VERSION 5.8 ;
BUSBITCHARS "[]" ;
DIVIDERCHAR "/" ;
UNITS
    DATABASE MICRONS 1000 ;
END UNITS

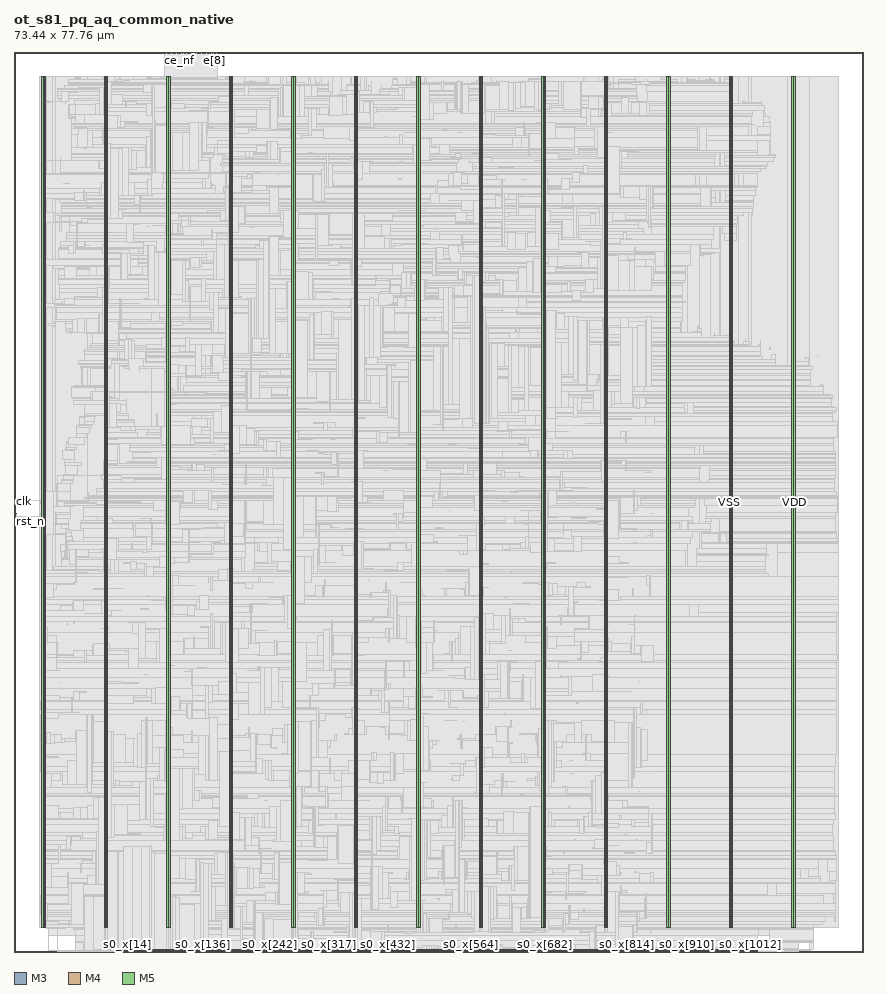
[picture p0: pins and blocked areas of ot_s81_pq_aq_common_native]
MACRO ot_s81_pq_aq_common_native
  FOREIGN ot_s81_pq_aq_common_native 0 0 ;
  CLASS BLOCK ;
  SIZE 73.44 BY 77.76 ;
  PIN ce_nf
    DIRECTION OUTPUT ;
    USE SIGNAL ;
    PORT
      LAYER M3 ;
        RECT  14.256 77.616 14.274 77.76 ;
    END
  END ce_nf
  PIN ce_r[0]
    DIRECTION OUTPUT ;
    USE SIGNAL ;
    PORT
      LAYER M3 ;
        RECT  12.96 77.616 12.978 77.76 ;
    END
  END ce_r[0]
  PIN ce_r[1]
    DIRECTION OUTPUT ;
    USE SIGNAL ;
    PORT
      LAYER M3 ;
        RECT  13.104 77.616 13.122 77.76 ;
    END
  END ce_r[1]
  PIN ce_r[2]
    DIRECTION OUTPUT ;
    USE SIGNAL ;
    PORT
      LAYER M3 ;
        RECT  13.248 77.616 13.266 77.76 ;
    END
  END ce_r[2]
  PIN ce_r[3]
    DIRECTION OUTPUT ;
    USE SIGNAL ;
    PORT
      LAYER M3 ;
        RECT  13.392 77.616 13.41 77.76 ;
    END
  END ce_r[3]
  PIN ce_r[4]
    DIRECTION OUTPUT ;
    USE SIGNAL ;
    PORT
      LAYER M3 ;
        RECT  13.536 77.616 13.554 77.76 ;
    END
  END ce_r[4]
  PIN ce_r[5]
    DIRECTION OUTPUT ;
    USE SIGNAL ;
    PORT
      LAYER M3 ;
        RECT  13.68 77.616 13.698 77.76 ;
    END
  END ce_r[5]
  PIN ce_r[6]
    DIRECTION OUTPUT ;
    USE SIGNAL ;
    PORT
      LAYER M3 ;
        RECT  13.824 77.616 13.842 77.76 ;
    END
  END ce_r[6]
  PIN ce_r[7]
    DIRECTION OUTPUT ;
    USE SIGNAL ;
    PORT
      LAYER M3 ;
        RECT  13.968 77.616 13.986 77.76 ;
    END
  END ce_r[7]
  PIN ce_r[8]
    DIRECTION OUTPUT ;
    USE SIGNAL ;
    PORT
      LAYER M3 ;
        RECT  14.112 77.616 14.13 77.76 ;
    END
  END ce_r[8]
  PIN clk
    DIRECTION INPUT ;
    USE SIGNAL ;
    PORT
      LAYER M4 ;
        RECT  0 38.88 0.192 38.904 ;
    END
    PORT
      LAYER M4 ;
        RECT  0.156 38.88 0.205 38.904 ;
    END
  END clk
  PIN e[0]
    DIRECTION OUTPUT ;
    USE SIGNAL ;
    PORT
      LAYER M3 ;
        RECT  16.128 77.616 16.146 77.76 ;
    END
  END e[0]
  PIN e[1]
    DIRECTION OUTPUT ;
    USE SIGNAL ;
    PORT
      LAYER M3 ;
        RECT  16.272 77.616 16.29 77.76 ;
    END
  END e[1]
  PIN e[2]
    DIRECTION OUTPUT ;
    USE SIGNAL ;
    PORT
      LAYER M3 ;
        RECT  16.416 77.616 16.434 77.76 ;
    END
  END e[2]
  PIN e[3]
    DIRECTION OUTPUT ;
    USE SIGNAL ;
    PORT
      LAYER M3 ;
        RECT  16.56 77.616 16.578 77.76 ;
    END
  END e[3]
  PIN e[4]
    DIRECTION OUTPUT ;
    USE SIGNAL ;
    PORT
      LAYER M3 ;
        RECT  16.704 77.616 16.722 77.76 ;
    END
  END e[4]
  PIN e[5]
    DIRECTION OUTPUT ;
    USE SIGNAL ;
    PORT
      LAYER M3 ;
        RECT  16.848 77.616 16.866 77.76 ;
    END
  END e[5]
  PIN e[6]
    DIRECTION OUTPUT ;
    USE SIGNAL ;
    PORT
      LAYER M3 ;
        RECT  16.992 77.616 17.01 77.76 ;
    END
  END e[6]
  PIN e[7]
    DIRECTION OUTPUT ;
    USE SIGNAL ;
    PORT
      LAYER M3 ;
        RECT  17.136 77.616 17.154 77.76 ;
    END
  END e[7]
  PIN e[8]
    DIRECTION OUTPUT ;
    USE SIGNAL ;
    PORT
      LAYER M3 ;
        RECT  17.28 77.616 17.298 77.76 ;
    END
  END e[8]
  PIN e[9]
    DIRECTION OUTPUT ;
    USE SIGNAL ;
    PORT
      LAYER M3 ;
        RECT  17.424 77.616 17.442 77.76 ;
    END
  END e[9]
  PIN ep
    DIRECTION OUTPUT ;
    USE SIGNAL ;
    PORT
      LAYER M3 ;
        RECT  17.568 77.616 17.586 77.76 ;
    END
  END ep
  PIN fault
    DIRECTION OUTPUT ;
    USE SIGNAL ;
    PORT
      LAYER M3 ;
        RECT  15.984 77.616 16.002 77.76 ;
    END
  END fault
  PIN rst_n
    DIRECTION INPUT ;
    USE SIGNAL ;
    PORT
      LAYER M4 ;
        RECT  0 37.872 0.192 37.896 ;
    END
    PORT
      LAYER M4 ;
        RECT  0.156 37.872 0.245 37.896 ;
    END
  END rst_n
  PIN s0_x[0]
    DIRECTION INPUT ;
    USE SIGNAL ;
    PORT
      LAYER M3 ;
        RECT  9 0 9.018 0.144 ;
    END
  END s0_x[0]
  PIN s0_x[1000]
    DIRECTION INPUT ;
    USE SIGNAL ;
    PORT
      LAYER M3 ;
        RECT  63 0 63.018 0.144 ;
    END
  END s0_x[1000]
  PIN s0_x[1001]
    DIRECTION INPUT ;
    USE SIGNAL ;
    PORT
      LAYER M5 ;
        RECT  60 0 60.024 0.192 ;
    END
  END s0_x[1001]
  PIN s0_x[1002]
    DIRECTION INPUT ;
    USE SIGNAL ;
    PORT
      LAYER M3 ;
        RECT  63.108 0 63.126 0.144 ;
    END
  END s0_x[1002]
  PIN s0_x[1003]
    DIRECTION INPUT ;
    USE SIGNAL ;
    PORT
      LAYER M5 ;
        RECT  60.096 0 60.12 0.192 ;
    END
  END s0_x[1003]
  PIN s0_x[1004]
    DIRECTION INPUT ;
    USE SIGNAL ;
    PORT
      LAYER M3 ;
        RECT  63.216 0 63.234 0.144 ;
    END
  END s0_x[1004]
  PIN s0_x[1005]
    DIRECTION INPUT ;
    USE SIGNAL ;
    PORT
      LAYER M5 ;
        RECT  60.192 0 60.216 0.192 ;
    END
  END s0_x[1005]
  PIN s0_x[1006]
    DIRECTION INPUT ;
    USE SIGNAL ;
    PORT
      LAYER M3 ;
        RECT  63.324 0 63.342 0.144 ;
    END
  END s0_x[1006]
  PIN s0_x[1007]
    DIRECTION INPUT ;
    USE SIGNAL ;
    PORT
      LAYER M5 ;
        RECT  60.288 0 60.312 0.192 ;
    END
  END s0_x[1007]
  PIN s0_x[1008]
    DIRECTION INPUT ;
    USE SIGNAL ;
    PORT
      LAYER M3 ;
        RECT  63.432 0 63.45 0.144 ;
    END
  END s0_x[1008]
  PIN s0_x[1009]
    DIRECTION INPUT ;
    USE SIGNAL ;
    PORT
      LAYER M5 ;
        RECT  60.384 0 60.408 0.192 ;
    END
  END s0_x[1009]
  PIN s0_x[100]
    DIRECTION INPUT ;
    USE SIGNAL ;
    PORT
      LAYER M3 ;
        RECT  14.4 0 14.418 0.144 ;
    END
  END s0_x[100]
  PIN s0_x[1010]
    DIRECTION INPUT ;
    USE SIGNAL ;
    PORT
      LAYER M3 ;
        RECT  63.54 0 63.558 0.144 ;
    END
  END s0_x[1010]
  PIN s0_x[1011]
    DIRECTION INPUT ;
    USE SIGNAL ;
    PORT
      LAYER M5 ;
        RECT  60.48 0 60.504 0.192 ;
    END
  END s0_x[1011]
  PIN s0_x[1012]
    DIRECTION INPUT ;
    USE SIGNAL ;
    PORT
      LAYER M3 ;
        RECT  63.648 0 63.666 0.144 ;
    END
  END s0_x[1012]
  PIN s0_x[1013]
    DIRECTION INPUT ;
    USE SIGNAL ;
    PORT
      LAYER M5 ;
        RECT  60.576 0 60.6 0.192 ;
    END
  END s0_x[1013]
  PIN s0_x[1014]
    DIRECTION INPUT ;
    USE SIGNAL ;
    PORT
      LAYER M3 ;
        RECT  63.756 0 63.774 0.144 ;
    END
  END s0_x[1014]
  PIN s0_x[1015]
    DIRECTION INPUT ;
    USE SIGNAL ;
    PORT
      LAYER M5 ;
        RECT  60.672 0 60.696 0.192 ;
    END
  END s0_x[1015]
  PIN s0_x[1016]
    DIRECTION INPUT ;
    USE SIGNAL ;
    PORT
      LAYER M3 ;
        RECT  63.864 0 63.882 0.144 ;
    END
  END s0_x[1016]
  PIN s0_x[1017]
    DIRECTION INPUT ;
    USE SIGNAL ;
    PORT
      LAYER M5 ;
        RECT  60.768 0 60.792 0.192 ;
    END
  END s0_x[1017]
  PIN s0_x[1018]
    DIRECTION INPUT ;
    USE SIGNAL ;
    PORT
      LAYER M3 ;
        RECT  63.972 0 63.99 0.144 ;
    END
  END s0_x[1018]
  PIN s0_x[1019]
    DIRECTION INPUT ;
    USE SIGNAL ;
    PORT
      LAYER M5 ;
        RECT  60.864 0 60.888 0.192 ;
    END
  END s0_x[1019]
  PIN s0_x[101]
    DIRECTION INPUT ;
    USE SIGNAL ;
    PORT
      LAYER M5 ;
        RECT  16.8 0 16.824 0.192 ;
    END
  END s0_x[101]
  PIN s0_x[1020]
    DIRECTION INPUT ;
    USE SIGNAL ;
    PORT
      LAYER M3 ;
        RECT  64.08 0 64.098 0.144 ;
    END
  END s0_x[1020]
  PIN s0_x[1021]
    DIRECTION INPUT ;
    USE SIGNAL ;
    PORT
      LAYER M5 ;
        RECT  60.96 0 60.984 0.192 ;
    END
  END s0_x[1021]
  PIN s0_x[1022]
    DIRECTION INPUT ;
    USE SIGNAL ;
    PORT
      LAYER M3 ;
        RECT  64.188 0 64.206 0.144 ;
    END
  END s0_x[1022]
  PIN s0_x[1023]
    DIRECTION INPUT ;
    USE SIGNAL ;
    PORT
      LAYER M5 ;
        RECT  61.056 0 61.08 0.192 ;
    END
  END s0_x[1023]
  PIN s0_x[102]
    DIRECTION INPUT ;
    USE SIGNAL ;
    PORT
      LAYER M3 ;
        RECT  14.508 0 14.526 0.144 ;
    END
  END s0_x[102]
  PIN s0_x[103]
    DIRECTION INPUT ;
    USE SIGNAL ;
    PORT
      LAYER M5 ;
        RECT  16.896 0 16.92 0.192 ;
    END
  END s0_x[103]
  PIN s0_x[104]
    DIRECTION INPUT ;
    USE SIGNAL ;
    PORT
      LAYER M3 ;
        RECT  14.616 0 14.634 0.144 ;
    END
  END s0_x[104]
  PIN s0_x[105]
    DIRECTION INPUT ;
    USE SIGNAL ;
    PORT
      LAYER M5 ;
        RECT  16.992 0 17.016 0.192 ;
    END
  END s0_x[105]
  PIN s0_x[106]
    DIRECTION INPUT ;
    USE SIGNAL ;
    PORT
      LAYER M3 ;
        RECT  14.724 0 14.742 0.144 ;
    END
  END s0_x[106]
  PIN s0_x[107]
    DIRECTION INPUT ;
    USE SIGNAL ;
    PORT
      LAYER M5 ;
        RECT  17.088 0 17.112 0.192 ;
    END
  END s0_x[107]
  PIN s0_x[108]
    DIRECTION INPUT ;
    USE SIGNAL ;
    PORT
      LAYER M3 ;
        RECT  14.832 0 14.85 0.144 ;
    END
  END s0_x[108]
  PIN s0_x[109]
    DIRECTION INPUT ;
    USE SIGNAL ;
    PORT
      LAYER M5 ;
        RECT  17.184 0 17.208 0.192 ;
    END
  END s0_x[109]
  PIN s0_x[10]
    DIRECTION INPUT ;
    USE SIGNAL ;
    PORT
      LAYER M3 ;
        RECT  9.54 0 9.558 0.144 ;
    END
  END s0_x[10]
  PIN s0_x[110]
    DIRECTION INPUT ;
    USE SIGNAL ;
    PORT
      LAYER M3 ;
        RECT  14.94 0 14.958 0.144 ;
    END
  END s0_x[110]
  PIN s0_x[111]
    DIRECTION INPUT ;
    USE SIGNAL ;
    PORT
      LAYER M5 ;
        RECT  17.28 0 17.304 0.192 ;
    END
  END s0_x[111]
  PIN s0_x[112]
    DIRECTION INPUT ;
    USE SIGNAL ;
    PORT
      LAYER M3 ;
        RECT  15.048 0 15.066 0.144 ;
    END
  END s0_x[112]
  PIN s0_x[113]
    DIRECTION INPUT ;
    USE SIGNAL ;
    PORT
      LAYER M5 ;
        RECT  17.376 0 17.4 0.192 ;
    END
  END s0_x[113]
  PIN s0_x[114]
    DIRECTION INPUT ;
    USE SIGNAL ;
    PORT
      LAYER M3 ;
        RECT  15.156 0 15.174 0.144 ;
    END
  END s0_x[114]
  PIN s0_x[115]
    DIRECTION INPUT ;
    USE SIGNAL ;
    PORT
      LAYER M5 ;
        RECT  17.472 0 17.496 0.192 ;
    END
  END s0_x[115]
  PIN s0_x[116]
    DIRECTION INPUT ;
    USE SIGNAL ;
    PORT
      LAYER M3 ;
        RECT  15.264 0 15.282 0.144 ;
    END
  END s0_x[116]
  PIN s0_x[117]
    DIRECTION INPUT ;
    USE SIGNAL ;
    PORT
      LAYER M5 ;
        RECT  17.568 0 17.592 0.192 ;
    END
  END s0_x[117]
  PIN s0_x[118]
    DIRECTION INPUT ;
    USE SIGNAL ;
    PORT
      LAYER M3 ;
        RECT  15.372 0 15.39 0.144 ;
    END
  END s0_x[118]
  PIN s0_x[119]
    DIRECTION INPUT ;
    USE SIGNAL ;
    PORT
      LAYER M5 ;
        RECT  17.664 0 17.688 0.192 ;
    END
  END s0_x[119]
  PIN s0_x[11]
    DIRECTION INPUT ;
    USE SIGNAL ;
    PORT
      LAYER M5 ;
        RECT  12.48 0 12.504 0.192 ;
    END
  END s0_x[11]
  PIN s0_x[120]
    DIRECTION INPUT ;
    USE SIGNAL ;
    PORT
      LAYER M3 ;
        RECT  15.48 0 15.498 0.144 ;
    END
  END s0_x[120]
  PIN s0_x[121]
    DIRECTION INPUT ;
    USE SIGNAL ;
    PORT
      LAYER M5 ;
        RECT  17.76 0 17.784 0.192 ;
    END
  END s0_x[121]
  PIN s0_x[122]
    DIRECTION INPUT ;
    USE SIGNAL ;
    PORT
      LAYER M3 ;
        RECT  15.588 0 15.606 0.144 ;
    END
  END s0_x[122]
  PIN s0_x[123]
    DIRECTION INPUT ;
    USE SIGNAL ;
    PORT
      LAYER M5 ;
        RECT  17.856 0 17.88 0.192 ;
    END
  END s0_x[123]
  PIN s0_x[124]
    DIRECTION INPUT ;
    USE SIGNAL ;
    PORT
      LAYER M3 ;
        RECT  15.696 0 15.714 0.144 ;
    END
  END s0_x[124]
  PIN s0_x[125]
    DIRECTION INPUT ;
    USE SIGNAL ;
    PORT
      LAYER M5 ;
        RECT  17.952 0 17.976 0.192 ;
    END
  END s0_x[125]
  PIN s0_x[126]
    DIRECTION INPUT ;
    USE SIGNAL ;
    PORT
      LAYER M3 ;
        RECT  15.804 0 15.822 0.144 ;
    END
  END s0_x[126]
  PIN s0_x[127]
    DIRECTION INPUT ;
    USE SIGNAL ;
    PORT
      LAYER M5 ;
        RECT  18.048 0 18.072 0.192 ;
    END
  END s0_x[127]
  PIN s0_x[128]
    DIRECTION INPUT ;
    USE SIGNAL ;
    PORT
      LAYER M3 ;
        RECT  15.912 0 15.93 0.144 ;
    END
  END s0_x[128]
  PIN s0_x[129]
    DIRECTION INPUT ;
    USE SIGNAL ;
    PORT
      LAYER M5 ;
        RECT  18.144 0 18.168 0.192 ;
    END
  END s0_x[129]
  PIN s0_x[12]
    DIRECTION INPUT ;
    USE SIGNAL ;
    PORT
      LAYER M3 ;
        RECT  9.648 0 9.666 0.144 ;
    END
  END s0_x[12]
  PIN s0_x[130]
    DIRECTION INPUT ;
    USE SIGNAL ;
    PORT
      LAYER M3 ;
        RECT  16.02 0 16.038 0.144 ;
    END
  END s0_x[130]
  PIN s0_x[131]
    DIRECTION INPUT ;
    USE SIGNAL ;
    PORT
      LAYER M5 ;
        RECT  18.24 0 18.264 0.192 ;
    END
  END s0_x[131]
  PIN s0_x[132]
    DIRECTION INPUT ;
    USE SIGNAL ;
    PORT
      LAYER M3 ;
        RECT  16.128 0 16.146 0.144 ;
    END
  END s0_x[132]
  PIN s0_x[133]
    DIRECTION INPUT ;
    USE SIGNAL ;
    PORT
      LAYER M5 ;
        RECT  18.336 0 18.36 0.192 ;
    END
  END s0_x[133]
  PIN s0_x[134]
    DIRECTION INPUT ;
    USE SIGNAL ;
    PORT
      LAYER M3 ;
        RECT  16.236 0 16.254 0.144 ;
    END
  END s0_x[134]
  PIN s0_x[135]
    DIRECTION INPUT ;
    USE SIGNAL ;
    PORT
      LAYER M5 ;
        RECT  18.432 0 18.456 0.192 ;
    END
  END s0_x[135]
  PIN s0_x[136]
    DIRECTION INPUT ;
    USE SIGNAL ;
    PORT
      LAYER M3 ;
        RECT  16.344 0 16.362 0.144 ;
    END
  END s0_x[136]
  PIN s0_x[137]
    DIRECTION INPUT ;
    USE SIGNAL ;
    PORT
      LAYER M5 ;
        RECT  18.528 0 18.552 0.192 ;
    END
  END s0_x[137]
  PIN s0_x[138]
    DIRECTION INPUT ;
    USE SIGNAL ;
    PORT
      LAYER M3 ;
        RECT  16.452 0 16.47 0.144 ;
    END
  END s0_x[138]
  PIN s0_x[139]
    DIRECTION INPUT ;
    USE SIGNAL ;
    PORT
      LAYER M5 ;
        RECT  18.624 0 18.648 0.192 ;
    END
  END s0_x[139]
  PIN s0_x[13]
    DIRECTION INPUT ;
    USE SIGNAL ;
    PORT
      LAYER M5 ;
        RECT  12.576 0 12.6 0.192 ;
    END
  END s0_x[13]
  PIN s0_x[140]
    DIRECTION INPUT ;
    USE SIGNAL ;
    PORT
      LAYER M3 ;
        RECT  16.56 0 16.578 0.144 ;
    END
  END s0_x[140]
  PIN s0_x[141]
    DIRECTION INPUT ;
    USE SIGNAL ;
    PORT
      LAYER M5 ;
        RECT  18.72 0 18.744 0.192 ;
    END
  END s0_x[141]
  PIN s0_x[142]
    DIRECTION INPUT ;
    USE SIGNAL ;
    PORT
      LAYER M3 ;
        RECT  16.668 0 16.686 0.144 ;
    END
  END s0_x[142]
  PIN s0_x[143]
    DIRECTION INPUT ;
    USE SIGNAL ;
    PORT
      LAYER M5 ;
        RECT  18.816 0 18.84 0.192 ;
    END
  END s0_x[143]
  PIN s0_x[144]
    DIRECTION INPUT ;
    USE SIGNAL ;
    PORT
      LAYER M3 ;
        RECT  16.776 0 16.794 0.144 ;
    END
  END s0_x[144]
  PIN s0_x[145]
    DIRECTION INPUT ;
    USE SIGNAL ;
    PORT
      LAYER M5 ;
        RECT  18.912 0 18.936 0.192 ;
    END
  END s0_x[145]
  PIN s0_x[146]
    DIRECTION INPUT ;
    USE SIGNAL ;
    PORT
      LAYER M3 ;
        RECT  16.884 0 16.902 0.144 ;
    END
  END s0_x[146]
  PIN s0_x[147]
    DIRECTION INPUT ;
    USE SIGNAL ;
    PORT
      LAYER M5 ;
        RECT  19.008 0 19.032 0.192 ;
    END
  END s0_x[147]
  PIN s0_x[148]
    DIRECTION INPUT ;
    USE SIGNAL ;
    PORT
      LAYER M3 ;
        RECT  16.992 0 17.01 0.144 ;
    END
  END s0_x[148]
  PIN s0_x[149]
    DIRECTION INPUT ;
    USE SIGNAL ;
    PORT
      LAYER M5 ;
        RECT  19.104 0 19.128 0.192 ;
    END
  END s0_x[149]
  PIN s0_x[14]
    DIRECTION INPUT ;
    USE SIGNAL ;
    PORT
      LAYER M3 ;
        RECT  9.756 0 9.774 0.144 ;
    END
  END s0_x[14]
  PIN s0_x[150]
    DIRECTION INPUT ;
    USE SIGNAL ;
    PORT
      LAYER M3 ;
        RECT  17.1 0 17.118 0.144 ;
    END
  END s0_x[150]
  PIN s0_x[151]
    DIRECTION INPUT ;
    USE SIGNAL ;
    PORT
      LAYER M5 ;
        RECT  19.2 0 19.224 0.192 ;
    END
  END s0_x[151]
  PIN s0_x[152]
    DIRECTION INPUT ;
    USE SIGNAL ;
    PORT
      LAYER M3 ;
        RECT  17.208 0 17.226 0.144 ;
    END
  END s0_x[152]
  PIN s0_x[153]
    DIRECTION INPUT ;
    USE SIGNAL ;
    PORT
      LAYER M5 ;
        RECT  19.296 0 19.32 0.192 ;
    END
  END s0_x[153]
  PIN s0_x[154]
    DIRECTION INPUT ;
    USE SIGNAL ;
    PORT
      LAYER M3 ;
        RECT  17.316 0 17.334 0.144 ;
    END
  END s0_x[154]
  PIN s0_x[155]
    DIRECTION INPUT ;
    USE SIGNAL ;
    PORT
      LAYER M5 ;
        RECT  19.392 0 19.416 0.192 ;
    END
  END s0_x[155]
  PIN s0_x[156]
    DIRECTION INPUT ;
    USE SIGNAL ;
    PORT
      LAYER M3 ;
        RECT  17.424 0 17.442 0.144 ;
    END
  END s0_x[156]
  PIN s0_x[157]
    DIRECTION INPUT ;
    USE SIGNAL ;
    PORT
      LAYER M5 ;
        RECT  19.488 0 19.512 0.192 ;
    END
  END s0_x[157]
  PIN s0_x[158]
    DIRECTION INPUT ;
    USE SIGNAL ;
    PORT
      LAYER M3 ;
        RECT  17.532 0 17.55 0.144 ;
    END
  END s0_x[158]
  PIN s0_x[159]
    DIRECTION INPUT ;
    USE SIGNAL ;
    PORT
      LAYER M5 ;
        RECT  19.584 0 19.608 0.192 ;
    END
  END s0_x[159]
  PIN s0_x[15]
    DIRECTION INPUT ;
    USE SIGNAL ;
    PORT
      LAYER M5 ;
        RECT  12.672 0 12.696 0.192 ;
    END
  END s0_x[15]
  PIN s0_x[160]
    DIRECTION INPUT ;
    USE SIGNAL ;
    PORT
      LAYER M3 ;
        RECT  17.64 0 17.658 0.144 ;
    END
  END s0_x[160]
  PIN s0_x[161]
    DIRECTION INPUT ;
    USE SIGNAL ;
    PORT
      LAYER M5 ;
        RECT  19.68 0 19.704 0.192 ;
    END
  END s0_x[161]
  PIN s0_x[162]
    DIRECTION INPUT ;
    USE SIGNAL ;
    PORT
      LAYER M3 ;
        RECT  17.748 0 17.766 0.144 ;
    END
  END s0_x[162]
  PIN s0_x[163]
    DIRECTION INPUT ;
    USE SIGNAL ;
    PORT
      LAYER M5 ;
        RECT  19.776 0 19.8 0.192 ;
    END
  END s0_x[163]
  PIN s0_x[164]
    DIRECTION INPUT ;
    USE SIGNAL ;
    PORT
      LAYER M3 ;
        RECT  17.856 0 17.874 0.144 ;
    END
  END s0_x[164]
  PIN s0_x[165]
    DIRECTION INPUT ;
    USE SIGNAL ;
    PORT
      LAYER M5 ;
        RECT  19.872 0 19.896 0.192 ;
    END
  END s0_x[165]
  PIN s0_x[166]
    DIRECTION INPUT ;
    USE SIGNAL ;
    PORT
      LAYER M3 ;
        RECT  17.964 0 17.982 0.144 ;
    END
  END s0_x[166]
  PIN s0_x[167]
    DIRECTION INPUT ;
    USE SIGNAL ;
    PORT
      LAYER M5 ;
        RECT  19.968 0 19.992 0.192 ;
    END
  END s0_x[167]
  PIN s0_x[168]
    DIRECTION INPUT ;
    USE SIGNAL ;
    PORT
      LAYER M3 ;
        RECT  18.072 0 18.09 0.144 ;
    END
  END s0_x[168]
  PIN s0_x[169]
    DIRECTION INPUT ;
    USE SIGNAL ;
    PORT
      LAYER M5 ;
        RECT  20.064 0 20.088 0.192 ;
    END
  END s0_x[169]
  PIN s0_x[16]
    DIRECTION INPUT ;
    USE SIGNAL ;
    PORT
      LAYER M3 ;
        RECT  9.864 0 9.882 0.144 ;
    END
  END s0_x[16]
  PIN s0_x[170]
    DIRECTION INPUT ;
    USE SIGNAL ;
    PORT
      LAYER M3 ;
        RECT  18.18 0 18.198 0.144 ;
    END
  END s0_x[170]
  PIN s0_x[171]
    DIRECTION INPUT ;
    USE SIGNAL ;
    PORT
      LAYER M5 ;
        RECT  20.16 0 20.184 0.192 ;
    END
  END s0_x[171]
  PIN s0_x[172]
    DIRECTION INPUT ;
    USE SIGNAL ;
    PORT
      LAYER M3 ;
        RECT  18.288 0 18.306 0.144 ;
    END
  END s0_x[172]
  PIN s0_x[173]
    DIRECTION INPUT ;
    USE SIGNAL ;
    PORT
      LAYER M5 ;
        RECT  20.256 0 20.28 0.192 ;
    END
  END s0_x[173]
  PIN s0_x[174]
    DIRECTION INPUT ;
    USE SIGNAL ;
    PORT
      LAYER M3 ;
        RECT  18.396 0 18.414 0.144 ;
    END
  END s0_x[174]
  PIN s0_x[175]
    DIRECTION INPUT ;
    USE SIGNAL ;
    PORT
      LAYER M5 ;
        RECT  20.352 0 20.376 0.192 ;
    END
  END s0_x[175]
  PIN s0_x[176]
    DIRECTION INPUT ;
    USE SIGNAL ;
    PORT
      LAYER M3 ;
        RECT  18.504 0 18.522 0.144 ;
    END
  END s0_x[176]
  PIN s0_x[177]
    DIRECTION INPUT ;
    USE SIGNAL ;
    PORT
      LAYER M5 ;
        RECT  20.448 0 20.472 0.192 ;
    END
  END s0_x[177]
  PIN s0_x[178]
    DIRECTION INPUT ;
    USE SIGNAL ;
    PORT
      LAYER M3 ;
        RECT  18.612 0 18.63 0.144 ;
    END
  END s0_x[178]
  PIN s0_x[179]
    DIRECTION INPUT ;
    USE SIGNAL ;
    PORT
      LAYER M5 ;
        RECT  20.544 0 20.568 0.192 ;
    END
  END s0_x[179]
  PIN s0_x[17]
    DIRECTION INPUT ;
    USE SIGNAL ;
    PORT
      LAYER M5 ;
        RECT  12.768 0 12.792 0.192 ;
    END
  END s0_x[17]
  PIN s0_x[180]
    DIRECTION INPUT ;
    USE SIGNAL ;
    PORT
      LAYER M3 ;
        RECT  18.72 0 18.738 0.144 ;
    END
  END s0_x[180]
  PIN s0_x[181]
    DIRECTION INPUT ;
    USE SIGNAL ;
    PORT
      LAYER M5 ;
        RECT  20.64 0 20.664 0.192 ;
    END
  END s0_x[181]
  PIN s0_x[182]
    DIRECTION INPUT ;
    USE SIGNAL ;
    PORT
      LAYER M3 ;
        RECT  18.828 0 18.846 0.144 ;
    END
  END s0_x[182]
  PIN s0_x[183]
    DIRECTION INPUT ;
    USE SIGNAL ;
    PORT
      LAYER M5 ;
        RECT  20.736 0 20.76 0.192 ;
    END
  END s0_x[183]
  PIN s0_x[184]
    DIRECTION INPUT ;
    USE SIGNAL ;
    PORT
      LAYER M3 ;
        RECT  18.936 0 18.954 0.144 ;
    END
  END s0_x[184]
  PIN s0_x[185]
    DIRECTION INPUT ;
    USE SIGNAL ;
    PORT
      LAYER M5 ;
        RECT  20.832 0 20.856 0.192 ;
    END
  END s0_x[185]
  PIN s0_x[186]
    DIRECTION INPUT ;
    USE SIGNAL ;
    PORT
      LAYER M3 ;
        RECT  19.044 0 19.062 0.144 ;
    END
  END s0_x[186]
  PIN s0_x[187]
    DIRECTION INPUT ;
    USE SIGNAL ;
    PORT
      LAYER M5 ;
        RECT  20.928 0 20.952 0.192 ;
    END
  END s0_x[187]
  PIN s0_x[188]
    DIRECTION INPUT ;
    USE SIGNAL ;
    PORT
      LAYER M3 ;
        RECT  19.152 0 19.17 0.144 ;
    END
  END s0_x[188]
  PIN s0_x[189]
    DIRECTION INPUT ;
    USE SIGNAL ;
    PORT
      LAYER M5 ;
        RECT  21.024 0 21.048 0.192 ;
    END
  END s0_x[189]
  PIN s0_x[18]
    DIRECTION INPUT ;
    USE SIGNAL ;
    PORT
      LAYER M3 ;
        RECT  9.972 0 9.99 0.144 ;
    END
  END s0_x[18]
  PIN s0_x[190]
    DIRECTION INPUT ;
    USE SIGNAL ;
    PORT
      LAYER M3 ;
        RECT  19.26 0 19.278 0.144 ;
    END
  END s0_x[190]
  PIN s0_x[191]
    DIRECTION INPUT ;
    USE SIGNAL ;
    PORT
      LAYER M5 ;
        RECT  21.12 0 21.144 0.192 ;
    END
  END s0_x[191]
  PIN s0_x[192]
    DIRECTION INPUT ;
    USE SIGNAL ;
    PORT
      LAYER M3 ;
        RECT  19.368 0 19.386 0.144 ;
    END
  END s0_x[192]
  PIN s0_x[193]
    DIRECTION INPUT ;
    USE SIGNAL ;
    PORT
      LAYER M5 ;
        RECT  21.216 0 21.24 0.192 ;
    END
  END s0_x[193]
  PIN s0_x[194]
    DIRECTION INPUT ;
    USE SIGNAL ;
    PORT
      LAYER M3 ;
        RECT  19.476 0 19.494 0.144 ;
    END
  END s0_x[194]
  PIN s0_x[195]
    DIRECTION INPUT ;
    USE SIGNAL ;
    PORT
      LAYER M5 ;
        RECT  21.312 0 21.336 0.192 ;
    END
  END s0_x[195]
  PIN s0_x[196]
    DIRECTION INPUT ;
    USE SIGNAL ;
    PORT
      LAYER M3 ;
        RECT  19.584 0 19.602 0.144 ;
    END
  END s0_x[196]
  PIN s0_x[197]
    DIRECTION INPUT ;
    USE SIGNAL ;
    PORT
      LAYER M5 ;
        RECT  21.408 0 21.432 0.192 ;
    END
  END s0_x[197]
  PIN s0_x[198]
    DIRECTION INPUT ;
    USE SIGNAL ;
    PORT
      LAYER M3 ;
        RECT  19.692 0 19.71 0.144 ;
    END
  END s0_x[198]
  PIN s0_x[199]
    DIRECTION INPUT ;
    USE SIGNAL ;
    PORT
      LAYER M5 ;
        RECT  21.504 0 21.528 0.192 ;
    END
  END s0_x[199]
  PIN s0_x[19]
    DIRECTION INPUT ;
    USE SIGNAL ;
    PORT
      LAYER M5 ;
        RECT  12.864 0 12.888 0.192 ;
    END
  END s0_x[19]
  PIN s0_x[1]
    DIRECTION INPUT ;
    USE SIGNAL ;
    PORT
      LAYER M5 ;
        RECT  12 0 12.024 0.192 ;
    END
  END s0_x[1]
  PIN s0_x[200]
    DIRECTION INPUT ;
    USE SIGNAL ;
    PORT
      LAYER M3 ;
        RECT  19.8 0 19.818 0.144 ;
    END
  END s0_x[200]
  PIN s0_x[201]
    DIRECTION INPUT ;
    USE SIGNAL ;
    PORT
      LAYER M5 ;
        RECT  21.6 0 21.624 0.192 ;
    END
  END s0_x[201]
  PIN s0_x[202]
    DIRECTION INPUT ;
    USE SIGNAL ;
    PORT
      LAYER M3 ;
        RECT  19.908 0 19.926 0.144 ;
    END
  END s0_x[202]
  PIN s0_x[203]
    DIRECTION INPUT ;
    USE SIGNAL ;
    PORT
      LAYER M5 ;
        RECT  21.696 0 21.72 0.192 ;
    END
  END s0_x[203]
  PIN s0_x[204]
    DIRECTION INPUT ;
    USE SIGNAL ;
    PORT
      LAYER M3 ;
        RECT  20.016 0 20.034 0.144 ;
    END
  END s0_x[204]
  PIN s0_x[205]
    DIRECTION INPUT ;
    USE SIGNAL ;
    PORT
      LAYER M5 ;
        RECT  21.792 0 21.816 0.192 ;
    END
  END s0_x[205]
  PIN s0_x[206]
    DIRECTION INPUT ;
    USE SIGNAL ;
    PORT
      LAYER M3 ;
        RECT  20.124 0 20.142 0.144 ;
    END
  END s0_x[206]
  PIN s0_x[207]
    DIRECTION INPUT ;
    USE SIGNAL ;
    PORT
      LAYER M5 ;
        RECT  21.888 0 21.912 0.192 ;
    END
  END s0_x[207]
  PIN s0_x[208]
    DIRECTION INPUT ;
    USE SIGNAL ;
    PORT
      LAYER M3 ;
        RECT  20.232 0 20.25 0.144 ;
    END
  END s0_x[208]
  PIN s0_x[209]
    DIRECTION INPUT ;
    USE SIGNAL ;
    PORT
      LAYER M5 ;
        RECT  21.984 0 22.008 0.192 ;
    END
  END s0_x[209]
  PIN s0_x[20]
    DIRECTION INPUT ;
    USE SIGNAL ;
    PORT
      LAYER M3 ;
        RECT  10.08 0 10.098 0.144 ;
    END
  END s0_x[20]
  PIN s0_x[210]
    DIRECTION INPUT ;
    USE SIGNAL ;
    PORT
      LAYER M3 ;
        RECT  20.34 0 20.358 0.144 ;
    END
  END s0_x[210]
  PIN s0_x[211]
    DIRECTION INPUT ;
    USE SIGNAL ;
    PORT
      LAYER M5 ;
        RECT  22.08 0 22.104 0.192 ;
    END
  END s0_x[211]
  PIN s0_x[212]
    DIRECTION INPUT ;
    USE SIGNAL ;
    PORT
      LAYER M3 ;
        RECT  20.448 0 20.466 0.144 ;
    END
  END s0_x[212]
  PIN s0_x[213]
    DIRECTION INPUT ;
    USE SIGNAL ;
    PORT
      LAYER M5 ;
        RECT  22.176 0 22.2 0.192 ;
    END
  END s0_x[213]
  PIN s0_x[214]
    DIRECTION INPUT ;
    USE SIGNAL ;
    PORT
      LAYER M3 ;
        RECT  20.556 0 20.574 0.144 ;
    END
  END s0_x[214]
  PIN s0_x[215]
    DIRECTION INPUT ;
    USE SIGNAL ;
    PORT
      LAYER M5 ;
        RECT  22.272 0 22.296 0.192 ;
    END
  END s0_x[215]
  PIN s0_x[216]
    DIRECTION INPUT ;
    USE SIGNAL ;
    PORT
      LAYER M3 ;
        RECT  20.664 0 20.682 0.144 ;
    END
  END s0_x[216]
  PIN s0_x[217]
    DIRECTION INPUT ;
    USE SIGNAL ;
    PORT
      LAYER M5 ;
        RECT  22.368 0 22.392 0.192 ;
    END
  END s0_x[217]
  PIN s0_x[218]
    DIRECTION INPUT ;
    USE SIGNAL ;
    PORT
      LAYER M3 ;
        RECT  20.772 0 20.79 0.144 ;
    END
  END s0_x[218]
  PIN s0_x[219]
    DIRECTION INPUT ;
    USE SIGNAL ;
    PORT
      LAYER M5 ;
        RECT  22.464 0 22.488 0.192 ;
    END
  END s0_x[219]
  PIN s0_x[21]
    DIRECTION INPUT ;
    USE SIGNAL ;
    PORT
      LAYER M5 ;
        RECT  12.96 0 12.984 0.192 ;
    END
  END s0_x[21]
  PIN s0_x[220]
    DIRECTION INPUT ;
    USE SIGNAL ;
    PORT
      LAYER M3 ;
        RECT  20.88 0 20.898 0.144 ;
    END
  END s0_x[220]
  PIN s0_x[221]
    DIRECTION INPUT ;
    USE SIGNAL ;
    PORT
      LAYER M5 ;
        RECT  22.56 0 22.584 0.192 ;
    END
  END s0_x[221]
  PIN s0_x[222]
    DIRECTION INPUT ;
    USE SIGNAL ;
    PORT
      LAYER M3 ;
        RECT  20.988 0 21.006 0.144 ;
    END
  END s0_x[222]
  PIN s0_x[223]
    DIRECTION INPUT ;
    USE SIGNAL ;
    PORT
      LAYER M5 ;
        RECT  22.656 0 22.68 0.192 ;
    END
  END s0_x[223]
  PIN s0_x[224]
    DIRECTION INPUT ;
    USE SIGNAL ;
    PORT
      LAYER M3 ;
        RECT  21.096 0 21.114 0.144 ;
    END
  END s0_x[224]
  PIN s0_x[225]
    DIRECTION INPUT ;
    USE SIGNAL ;
    PORT
      LAYER M5 ;
        RECT  22.752 0 22.776 0.192 ;
    END
  END s0_x[225]
  PIN s0_x[226]
    DIRECTION INPUT ;
    USE SIGNAL ;
    PORT
      LAYER M3 ;
        RECT  21.204 0 21.222 0.144 ;
    END
  END s0_x[226]
  PIN s0_x[227]
    DIRECTION INPUT ;
    USE SIGNAL ;
    PORT
      LAYER M5 ;
        RECT  22.848 0 22.872 0.192 ;
    END
  END s0_x[227]
  PIN s0_x[228]
    DIRECTION INPUT ;
    USE SIGNAL ;
    PORT
      LAYER M3 ;
        RECT  21.312 0 21.33 0.144 ;
    END
  END s0_x[228]
  PIN s0_x[229]
    DIRECTION INPUT ;
    USE SIGNAL ;
    PORT
      LAYER M5 ;
        RECT  22.944 0 22.968 0.192 ;
    END
  END s0_x[229]
  PIN s0_x[22]
    DIRECTION INPUT ;
    USE SIGNAL ;
    PORT
      LAYER M3 ;
        RECT  10.188 0 10.206 0.144 ;
    END
  END s0_x[22]
  PIN s0_x[230]
    DIRECTION INPUT ;
    USE SIGNAL ;
    PORT
      LAYER M3 ;
        RECT  21.42 0 21.438 0.144 ;
    END
  END s0_x[230]
  PIN s0_x[231]
    DIRECTION INPUT ;
    USE SIGNAL ;
    PORT
      LAYER M5 ;
        RECT  23.04 0 23.064 0.192 ;
    END
  END s0_x[231]
  PIN s0_x[232]
    DIRECTION INPUT ;
    USE SIGNAL ;
    PORT
      LAYER M3 ;
        RECT  21.528 0 21.546 0.144 ;
    END
  END s0_x[232]
  PIN s0_x[233]
    DIRECTION INPUT ;
    USE SIGNAL ;
    PORT
      LAYER M5 ;
        RECT  23.136 0 23.16 0.192 ;
    END
  END s0_x[233]
  PIN s0_x[234]
    DIRECTION INPUT ;
    USE SIGNAL ;
    PORT
      LAYER M3 ;
        RECT  21.636 0 21.654 0.144 ;
    END
  END s0_x[234]
  PIN s0_x[235]
    DIRECTION INPUT ;
    USE SIGNAL ;
    PORT
      LAYER M5 ;
        RECT  23.232 0 23.256 0.192 ;
    END
  END s0_x[235]
  PIN s0_x[236]
    DIRECTION INPUT ;
    USE SIGNAL ;
    PORT
      LAYER M3 ;
        RECT  21.744 0 21.762 0.144 ;
    END
  END s0_x[236]
  PIN s0_x[237]
    DIRECTION INPUT ;
    USE SIGNAL ;
    PORT
      LAYER M5 ;
        RECT  23.328 0 23.352 0.192 ;
    END
  END s0_x[237]
  PIN s0_x[238]
    DIRECTION INPUT ;
    USE SIGNAL ;
    PORT
      LAYER M3 ;
        RECT  21.852 0 21.87 0.144 ;
    END
  END s0_x[238]
  PIN s0_x[239]
    DIRECTION INPUT ;
    USE SIGNAL ;
    PORT
      LAYER M5 ;
        RECT  23.424 0 23.448 0.192 ;
    END
  END s0_x[239]
  PIN s0_x[23]
    DIRECTION INPUT ;
    USE SIGNAL ;
    PORT
      LAYER M5 ;
        RECT  13.056 0 13.08 0.192 ;
    END
  END s0_x[23]
  PIN s0_x[240]
    DIRECTION INPUT ;
    USE SIGNAL ;
    PORT
      LAYER M3 ;
        RECT  21.96 0 21.978 0.144 ;
    END
  END s0_x[240]
  PIN s0_x[241]
    DIRECTION INPUT ;
    USE SIGNAL ;
    PORT
      LAYER M5 ;
        RECT  23.52 0 23.544 0.192 ;
    END
  END s0_x[241]
  PIN s0_x[242]
    DIRECTION INPUT ;
    USE SIGNAL ;
    PORT
      LAYER M3 ;
        RECT  22.068 0 22.086 0.144 ;
    END
  END s0_x[242]
  PIN s0_x[243]
    DIRECTION INPUT ;
    USE SIGNAL ;
    PORT
      LAYER M5 ;
        RECT  23.616 0 23.64 0.192 ;
    END
  END s0_x[243]
  PIN s0_x[244]
    DIRECTION INPUT ;
    USE SIGNAL ;
    PORT
      LAYER M3 ;
        RECT  22.176 0 22.194 0.144 ;
    END
  END s0_x[244]
  PIN s0_x[245]
    DIRECTION INPUT ;
    USE SIGNAL ;
    PORT
      LAYER M5 ;
        RECT  23.712 0 23.736 0.192 ;
    END
  END s0_x[245]
  PIN s0_x[246]
    DIRECTION INPUT ;
    USE SIGNAL ;
    PORT
      LAYER M3 ;
        RECT  22.284 0 22.302 0.144 ;
    END
  END s0_x[246]
  PIN s0_x[247]
    DIRECTION INPUT ;
    USE SIGNAL ;
    PORT
      LAYER M5 ;
        RECT  23.808 0 23.832 0.192 ;
    END
  END s0_x[247]
  PIN s0_x[248]
    DIRECTION INPUT ;
    USE SIGNAL ;
    PORT
      LAYER M3 ;
        RECT  22.392 0 22.41 0.144 ;
    END
  END s0_x[248]
  PIN s0_x[249]
    DIRECTION INPUT ;
    USE SIGNAL ;
    PORT
      LAYER M5 ;
        RECT  23.904 0 23.928 0.192 ;
    END
  END s0_x[249]
  PIN s0_x[24]
    DIRECTION INPUT ;
    USE SIGNAL ;
    PORT
      LAYER M3 ;
        RECT  10.296 0 10.314 0.144 ;
    END
  END s0_x[24]
  PIN s0_x[250]
    DIRECTION INPUT ;
    USE SIGNAL ;
    PORT
      LAYER M3 ;
        RECT  22.5 0 22.518 0.144 ;
    END
  END s0_x[250]
  PIN s0_x[251]
    DIRECTION INPUT ;
    USE SIGNAL ;
    PORT
      LAYER M5 ;
        RECT  24 0 24.024 0.192 ;
    END
  END s0_x[251]
  PIN s0_x[252]
    DIRECTION INPUT ;
    USE SIGNAL ;
    PORT
      LAYER M3 ;
        RECT  22.608 0 22.626 0.144 ;
    END
  END s0_x[252]
  PIN s0_x[253]
    DIRECTION INPUT ;
    USE SIGNAL ;
    PORT
      LAYER M5 ;
        RECT  24.096 0 24.12 0.192 ;
    END
  END s0_x[253]
  PIN s0_x[254]
    DIRECTION INPUT ;
    USE SIGNAL ;
    PORT
      LAYER M3 ;
        RECT  22.716 0 22.734 0.144 ;
    END
  END s0_x[254]
  PIN s0_x[255]
    DIRECTION INPUT ;
    USE SIGNAL ;
    PORT
      LAYER M5 ;
        RECT  24.192 0 24.216 0.192 ;
    END
  END s0_x[255]
  PIN s0_x[256]
    DIRECTION INPUT ;
    USE SIGNAL ;
    PORT
      LAYER M3 ;
        RECT  22.824 0 22.842 0.144 ;
    END
  END s0_x[256]
  PIN s0_x[257]
    DIRECTION INPUT ;
    USE SIGNAL ;
    PORT
      LAYER M5 ;
        RECT  24.288 0 24.312 0.192 ;
    END
  END s0_x[257]
  PIN s0_x[258]
    DIRECTION INPUT ;
    USE SIGNAL ;
    PORT
      LAYER M3 ;
        RECT  22.932 0 22.95 0.144 ;
    END
  END s0_x[258]
  PIN s0_x[259]
    DIRECTION INPUT ;
    USE SIGNAL ;
    PORT
      LAYER M5 ;
        RECT  24.384 0 24.408 0.192 ;
    END
  END s0_x[259]
  PIN s0_x[25]
    DIRECTION INPUT ;
    USE SIGNAL ;
    PORT
      LAYER M5 ;
        RECT  13.152 0 13.176 0.192 ;
    END
  END s0_x[25]
  PIN s0_x[260]
    DIRECTION INPUT ;
    USE SIGNAL ;
    PORT
      LAYER M3 ;
        RECT  23.04 0 23.058 0.144 ;
    END
  END s0_x[260]
  PIN s0_x[261]
    DIRECTION INPUT ;
    USE SIGNAL ;
    PORT
      LAYER M5 ;
        RECT  24.48 0 24.504 0.192 ;
    END
  END s0_x[261]
  PIN s0_x[262]
    DIRECTION INPUT ;
    USE SIGNAL ;
    PORT
      LAYER M3 ;
        RECT  23.148 0 23.166 0.144 ;
    END
  END s0_x[262]
  PIN s0_x[263]
    DIRECTION INPUT ;
    USE SIGNAL ;
    PORT
      LAYER M5 ;
        RECT  24.576 0 24.6 0.192 ;
    END
  END s0_x[263]
  PIN s0_x[264]
    DIRECTION INPUT ;
    USE SIGNAL ;
    PORT
      LAYER M3 ;
        RECT  23.256 0 23.274 0.144 ;
    END
  END s0_x[264]
  PIN s0_x[265]
    DIRECTION INPUT ;
    USE SIGNAL ;
    PORT
      LAYER M5 ;
        RECT  24.672 0 24.696 0.192 ;
    END
  END s0_x[265]
  PIN s0_x[266]
    DIRECTION INPUT ;
    USE SIGNAL ;
    PORT
      LAYER M3 ;
        RECT  23.364 0 23.382 0.144 ;
    END
  END s0_x[266]
  PIN s0_x[267]
    DIRECTION INPUT ;
    USE SIGNAL ;
    PORT
      LAYER M5 ;
        RECT  24.768 0 24.792 0.192 ;
    END
  END s0_x[267]
  PIN s0_x[268]
    DIRECTION INPUT ;
    USE SIGNAL ;
    PORT
      LAYER M3 ;
        RECT  23.472 0 23.49 0.144 ;
    END
  END s0_x[268]
  PIN s0_x[269]
    DIRECTION INPUT ;
    USE SIGNAL ;
    PORT
      LAYER M5 ;
        RECT  24.864 0 24.888 0.192 ;
    END
  END s0_x[269]
  PIN s0_x[26]
    DIRECTION INPUT ;
    USE SIGNAL ;
    PORT
      LAYER M3 ;
        RECT  10.404 0 10.422 0.144 ;
    END
  END s0_x[26]
  PIN s0_x[270]
    DIRECTION INPUT ;
    USE SIGNAL ;
    PORT
      LAYER M3 ;
        RECT  23.58 0 23.598 0.144 ;
    END
  END s0_x[270]
  PIN s0_x[271]
    DIRECTION INPUT ;
    USE SIGNAL ;
    PORT
      LAYER M5 ;
        RECT  24.96 0 24.984 0.192 ;
    END
  END s0_x[271]
  PIN s0_x[272]
    DIRECTION INPUT ;
    USE SIGNAL ;
    PORT
      LAYER M3 ;
        RECT  23.688 0 23.706 0.144 ;
    END
  END s0_x[272]
  PIN s0_x[273]
    DIRECTION INPUT ;
    USE SIGNAL ;
    PORT
      LAYER M5 ;
        RECT  25.056 0 25.08 0.192 ;
    END
  END s0_x[273]
  PIN s0_x[274]
    DIRECTION INPUT ;
    USE SIGNAL ;
    PORT
      LAYER M3 ;
        RECT  23.796 0 23.814 0.144 ;
    END
  END s0_x[274]
  PIN s0_x[275]
    DIRECTION INPUT ;
    USE SIGNAL ;
    PORT
      LAYER M5 ;
        RECT  25.152 0 25.176 0.192 ;
    END
  END s0_x[275]
  PIN s0_x[276]
    DIRECTION INPUT ;
    USE SIGNAL ;
    PORT
      LAYER M3 ;
        RECT  23.904 0 23.922 0.144 ;
    END
  END s0_x[276]
  PIN s0_x[277]
    DIRECTION INPUT ;
    USE SIGNAL ;
    PORT
      LAYER M5 ;
        RECT  25.248 0 25.272 0.192 ;
    END
  END s0_x[277]
  PIN s0_x[278]
    DIRECTION INPUT ;
    USE SIGNAL ;
    PORT
      LAYER M3 ;
        RECT  24.012 0 24.03 0.144 ;
    END
  END s0_x[278]
  PIN s0_x[279]
    DIRECTION INPUT ;
    USE SIGNAL ;
    PORT
      LAYER M5 ;
        RECT  25.344 0 25.368 0.192 ;
    END
  END s0_x[279]
  PIN s0_x[27]
    DIRECTION INPUT ;
    USE SIGNAL ;
    PORT
      LAYER M5 ;
        RECT  13.248 0 13.272 0.192 ;
    END
  END s0_x[27]
  PIN s0_x[280]
    DIRECTION INPUT ;
    USE SIGNAL ;
    PORT
      LAYER M3 ;
        RECT  24.12 0 24.138 0.144 ;
    END
  END s0_x[280]
  PIN s0_x[281]
    DIRECTION INPUT ;
    USE SIGNAL ;
    PORT
      LAYER M5 ;
        RECT  25.44 0 25.464 0.192 ;
    END
  END s0_x[281]
  PIN s0_x[282]
    DIRECTION INPUT ;
    USE SIGNAL ;
    PORT
      LAYER M3 ;
        RECT  24.228 0 24.246 0.144 ;
    END
  END s0_x[282]
  PIN s0_x[283]
    DIRECTION INPUT ;
    USE SIGNAL ;
    PORT
      LAYER M5 ;
        RECT  25.536 0 25.56 0.192 ;
    END
  END s0_x[283]
  PIN s0_x[284]
    DIRECTION INPUT ;
    USE SIGNAL ;
    PORT
      LAYER M3 ;
        RECT  24.336 0 24.354 0.144 ;
    END
  END s0_x[284]
  PIN s0_x[285]
    DIRECTION INPUT ;
    USE SIGNAL ;
    PORT
      LAYER M5 ;
        RECT  25.632 0 25.656 0.192 ;
    END
  END s0_x[285]
  PIN s0_x[286]
    DIRECTION INPUT ;
    USE SIGNAL ;
    PORT
      LAYER M3 ;
        RECT  24.444 0 24.462 0.144 ;
    END
  END s0_x[286]
  PIN s0_x[287]
    DIRECTION INPUT ;
    USE SIGNAL ;
    PORT
      LAYER M5 ;
        RECT  25.728 0 25.752 0.192 ;
    END
  END s0_x[287]
  PIN s0_x[288]
    DIRECTION INPUT ;
    USE SIGNAL ;
    PORT
      LAYER M3 ;
        RECT  24.552 0 24.57 0.144 ;
    END
  END s0_x[288]
  PIN s0_x[289]
    DIRECTION INPUT ;
    USE SIGNAL ;
    PORT
      LAYER M5 ;
        RECT  25.824 0 25.848 0.192 ;
    END
  END s0_x[289]
  PIN s0_x[28]
    DIRECTION INPUT ;
    USE SIGNAL ;
    PORT
      LAYER M3 ;
        RECT  10.512 0 10.53 0.144 ;
    END
  END s0_x[28]
  PIN s0_x[290]
    DIRECTION INPUT ;
    USE SIGNAL ;
    PORT
      LAYER M3 ;
        RECT  24.66 0 24.678 0.144 ;
    END
  END s0_x[290]
  PIN s0_x[291]
    DIRECTION INPUT ;
    USE SIGNAL ;
    PORT
      LAYER M5 ;
        RECT  25.92 0 25.944 0.192 ;
    END
  END s0_x[291]
  PIN s0_x[292]
    DIRECTION INPUT ;
    USE SIGNAL ;
    PORT
      LAYER M3 ;
        RECT  24.768 0 24.786 0.144 ;
    END
  END s0_x[292]
  PIN s0_x[293]
    DIRECTION INPUT ;
    USE SIGNAL ;
    PORT
      LAYER M5 ;
        RECT  26.016 0 26.04 0.192 ;
    END
  END s0_x[293]
  PIN s0_x[294]
    DIRECTION INPUT ;
    USE SIGNAL ;
    PORT
      LAYER M3 ;
        RECT  24.876 0 24.894 0.144 ;
    END
  END s0_x[294]
  PIN s0_x[295]
    DIRECTION INPUT ;
    USE SIGNAL ;
    PORT
      LAYER M5 ;
        RECT  26.112 0 26.136 0.192 ;
    END
  END s0_x[295]
  PIN s0_x[296]
    DIRECTION INPUT ;
    USE SIGNAL ;
    PORT
      LAYER M3 ;
        RECT  24.984 0 25.002 0.144 ;
    END
  END s0_x[296]
  PIN s0_x[297]
    DIRECTION INPUT ;
    USE SIGNAL ;
    PORT
      LAYER M5 ;
        RECT  26.208 0 26.232 0.192 ;
    END
  END s0_x[297]
  PIN s0_x[298]
    DIRECTION INPUT ;
    USE SIGNAL ;
    PORT
      LAYER M3 ;
        RECT  25.092 0 25.11 0.144 ;
    END
  END s0_x[298]
  PIN s0_x[299]
    DIRECTION INPUT ;
    USE SIGNAL ;
    PORT
      LAYER M5 ;
        RECT  26.304 0 26.328 0.192 ;
    END
  END s0_x[299]
  PIN s0_x[29]
    DIRECTION INPUT ;
    USE SIGNAL ;
    PORT
      LAYER M5 ;
        RECT  13.344 0 13.368 0.192 ;
    END
  END s0_x[29]
  PIN s0_x[2]
    DIRECTION INPUT ;
    USE SIGNAL ;
    PORT
      LAYER M3 ;
        RECT  9.108 0 9.126 0.144 ;
    END
  END s0_x[2]
  PIN s0_x[300]
    DIRECTION INPUT ;
    USE SIGNAL ;
    PORT
      LAYER M3 ;
        RECT  25.2 0 25.218 0.144 ;
    END
  END s0_x[300]
  PIN s0_x[301]
    DIRECTION INPUT ;
    USE SIGNAL ;
    PORT
      LAYER M5 ;
        RECT  26.4 0 26.424 0.192 ;
    END
  END s0_x[301]
  PIN s0_x[302]
    DIRECTION INPUT ;
    USE SIGNAL ;
    PORT
      LAYER M3 ;
        RECT  25.308 0 25.326 0.144 ;
    END
  END s0_x[302]
  PIN s0_x[303]
    DIRECTION INPUT ;
    USE SIGNAL ;
    PORT
      LAYER M5 ;
        RECT  26.496 0 26.52 0.192 ;
    END
  END s0_x[303]
  PIN s0_x[304]
    DIRECTION INPUT ;
    USE SIGNAL ;
    PORT
      LAYER M3 ;
        RECT  25.416 0 25.434 0.144 ;
    END
  END s0_x[304]
  PIN s0_x[305]
    DIRECTION INPUT ;
    USE SIGNAL ;
    PORT
      LAYER M5 ;
        RECT  26.592 0 26.616 0.192 ;
    END
  END s0_x[305]
  PIN s0_x[306]
    DIRECTION INPUT ;
    USE SIGNAL ;
    PORT
      LAYER M3 ;
        RECT  25.524 0 25.542 0.144 ;
    END
  END s0_x[306]
  PIN s0_x[307]
    DIRECTION INPUT ;
    USE SIGNAL ;
    PORT
      LAYER M5 ;
        RECT  26.688 0 26.712 0.192 ;
    END
  END s0_x[307]
  PIN s0_x[308]
    DIRECTION INPUT ;
    USE SIGNAL ;
    PORT
      LAYER M3 ;
        RECT  25.632 0 25.65 0.144 ;
    END
  END s0_x[308]
  PIN s0_x[309]
    DIRECTION INPUT ;
    USE SIGNAL ;
    PORT
      LAYER M5 ;
        RECT  26.784 0 26.808 0.192 ;
    END
  END s0_x[309]
  PIN s0_x[30]
    DIRECTION INPUT ;
    USE SIGNAL ;
    PORT
      LAYER M3 ;
        RECT  10.62 0 10.638 0.144 ;
    END
  END s0_x[30]
  PIN s0_x[310]
    DIRECTION INPUT ;
    USE SIGNAL ;
    PORT
      LAYER M3 ;
        RECT  25.74 0 25.758 0.144 ;
    END
  END s0_x[310]
  PIN s0_x[311]
    DIRECTION INPUT ;
    USE SIGNAL ;
    PORT
      LAYER M5 ;
        RECT  26.88 0 26.904 0.192 ;
    END
  END s0_x[311]
  PIN s0_x[312]
    DIRECTION INPUT ;
    USE SIGNAL ;
    PORT
      LAYER M3 ;
        RECT  25.848 0 25.866 0.144 ;
    END
  END s0_x[312]
  PIN s0_x[313]
    DIRECTION INPUT ;
    USE SIGNAL ;
    PORT
      LAYER M5 ;
        RECT  26.976 0 27 0.192 ;
    END
  END s0_x[313]
  PIN s0_x[314]
    DIRECTION INPUT ;
    USE SIGNAL ;
    PORT
      LAYER M3 ;
        RECT  25.956 0 25.974 0.144 ;
    END
  END s0_x[314]
  PIN s0_x[315]
    DIRECTION INPUT ;
    USE SIGNAL ;
    PORT
      LAYER M5 ;
        RECT  27.072 0 27.096 0.192 ;
    END
  END s0_x[315]
  PIN s0_x[316]
    DIRECTION INPUT ;
    USE SIGNAL ;
    PORT
      LAYER M3 ;
        RECT  26.064 0 26.082 0.144 ;
    END
  END s0_x[316]
  PIN s0_x[317]
    DIRECTION INPUT ;
    USE SIGNAL ;
    PORT
      LAYER M5 ;
        RECT  27.168 0 27.192 0.192 ;
    END
  END s0_x[317]
  PIN s0_x[318]
    DIRECTION INPUT ;
    USE SIGNAL ;
    PORT
      LAYER M3 ;
        RECT  26.172 0 26.19 0.144 ;
    END
  END s0_x[318]
  PIN s0_x[319]
    DIRECTION INPUT ;
    USE SIGNAL ;
    PORT
      LAYER M5 ;
        RECT  27.264 0 27.288 0.192 ;
    END
  END s0_x[319]
  PIN s0_x[31]
    DIRECTION INPUT ;
    USE SIGNAL ;
    PORT
      LAYER M5 ;
        RECT  13.44 0 13.464 0.192 ;
    END
  END s0_x[31]
  PIN s0_x[320]
    DIRECTION INPUT ;
    USE SIGNAL ;
    PORT
      LAYER M3 ;
        RECT  26.28 0 26.298 0.144 ;
    END
  END s0_x[320]
  PIN s0_x[321]
    DIRECTION INPUT ;
    USE SIGNAL ;
    PORT
      LAYER M5 ;
        RECT  27.36 0 27.384 0.192 ;
    END
  END s0_x[321]
  PIN s0_x[322]
    DIRECTION INPUT ;
    USE SIGNAL ;
    PORT
      LAYER M3 ;
        RECT  26.388 0 26.406 0.144 ;
    END
  END s0_x[322]
  PIN s0_x[323]
    DIRECTION INPUT ;
    USE SIGNAL ;
    PORT
      LAYER M5 ;
        RECT  27.456 0 27.48 0.192 ;
    END
  END s0_x[323]
  PIN s0_x[324]
    DIRECTION INPUT ;
    USE SIGNAL ;
    PORT
      LAYER M3 ;
        RECT  26.496 0 26.514 0.144 ;
    END
  END s0_x[324]
  PIN s0_x[325]
    DIRECTION INPUT ;
    USE SIGNAL ;
    PORT
      LAYER M5 ;
        RECT  27.552 0 27.576 0.192 ;
    END
  END s0_x[325]
  PIN s0_x[326]
    DIRECTION INPUT ;
    USE SIGNAL ;
    PORT
      LAYER M3 ;
        RECT  26.604 0 26.622 0.144 ;
    END
  END s0_x[326]
  PIN s0_x[327]
    DIRECTION INPUT ;
    USE SIGNAL ;
    PORT
      LAYER M5 ;
        RECT  27.648 0 27.672 0.192 ;
    END
  END s0_x[327]
  PIN s0_x[328]
    DIRECTION INPUT ;
    USE SIGNAL ;
    PORT
      LAYER M3 ;
        RECT  26.712 0 26.73 0.144 ;
    END
  END s0_x[328]
  PIN s0_x[329]
    DIRECTION INPUT ;
    USE SIGNAL ;
    PORT
      LAYER M5 ;
        RECT  27.744 0 27.768 0.192 ;
    END
  END s0_x[329]
  PIN s0_x[32]
    DIRECTION INPUT ;
    USE SIGNAL ;
    PORT
      LAYER M3 ;
        RECT  10.728 0 10.746 0.144 ;
    END
  END s0_x[32]
  PIN s0_x[330]
    DIRECTION INPUT ;
    USE SIGNAL ;
    PORT
      LAYER M3 ;
        RECT  26.82 0 26.838 0.144 ;
    END
  END s0_x[330]
  PIN s0_x[331]
    DIRECTION INPUT ;
    USE SIGNAL ;
    PORT
      LAYER M5 ;
        RECT  27.84 0 27.864 0.192 ;
    END
  END s0_x[331]
  PIN s0_x[332]
    DIRECTION INPUT ;
    USE SIGNAL ;
    PORT
      LAYER M3 ;
        RECT  26.928 0 26.946 0.144 ;
    END
  END s0_x[332]
  PIN s0_x[333]
    DIRECTION INPUT ;
    USE SIGNAL ;
    PORT
      LAYER M5 ;
        RECT  27.936 0 27.96 0.192 ;
    END
  END s0_x[333]
  PIN s0_x[334]
    DIRECTION INPUT ;
    USE SIGNAL ;
    PORT
      LAYER M3 ;
        RECT  27.036 0 27.054 0.144 ;
    END
  END s0_x[334]
  PIN s0_x[335]
    DIRECTION INPUT ;
    USE SIGNAL ;
    PORT
      LAYER M5 ;
        RECT  28.032 0 28.056 0.192 ;
    END
  END s0_x[335]
  PIN s0_x[336]
    DIRECTION INPUT ;
    USE SIGNAL ;
    PORT
      LAYER M3 ;
        RECT  27.144 0 27.162 0.144 ;
    END
  END s0_x[336]
  PIN s0_x[337]
    DIRECTION INPUT ;
    USE SIGNAL ;
    PORT
      LAYER M5 ;
        RECT  28.128 0 28.152 0.192 ;
    END
  END s0_x[337]
  PIN s0_x[338]
    DIRECTION INPUT ;
    USE SIGNAL ;
    PORT
      LAYER M3 ;
        RECT  27.252 0 27.27 0.144 ;
    END
  END s0_x[338]
  PIN s0_x[339]
    DIRECTION INPUT ;
    USE SIGNAL ;
    PORT
      LAYER M5 ;
        RECT  28.224 0 28.248 0.192 ;
    END
  END s0_x[339]
  PIN s0_x[33]
    DIRECTION INPUT ;
    USE SIGNAL ;
    PORT
      LAYER M5 ;
        RECT  13.536 0 13.56 0.192 ;
    END
  END s0_x[33]
  PIN s0_x[340]
    DIRECTION INPUT ;
    USE SIGNAL ;
    PORT
      LAYER M3 ;
        RECT  27.36 0 27.378 0.144 ;
    END
  END s0_x[340]
  PIN s0_x[341]
    DIRECTION INPUT ;
    USE SIGNAL ;
    PORT
      LAYER M5 ;
        RECT  28.32 0 28.344 0.192 ;
    END
  END s0_x[341]
  PIN s0_x[342]
    DIRECTION INPUT ;
    USE SIGNAL ;
    PORT
      LAYER M3 ;
        RECT  27.468 0 27.486 0.144 ;
    END
  END s0_x[342]
  PIN s0_x[343]
    DIRECTION INPUT ;
    USE SIGNAL ;
    PORT
      LAYER M5 ;
        RECT  28.416 0 28.44 0.192 ;
    END
  END s0_x[343]
  PIN s0_x[344]
    DIRECTION INPUT ;
    USE SIGNAL ;
    PORT
      LAYER M3 ;
        RECT  27.576 0 27.594 0.144 ;
    END
  END s0_x[344]
  PIN s0_x[345]
    DIRECTION INPUT ;
    USE SIGNAL ;
    PORT
      LAYER M5 ;
        RECT  28.512 0 28.536 0.192 ;
    END
  END s0_x[345]
  PIN s0_x[346]
    DIRECTION INPUT ;
    USE SIGNAL ;
    PORT
      LAYER M3 ;
        RECT  27.684 0 27.702 0.144 ;
    END
  END s0_x[346]
  PIN s0_x[347]
    DIRECTION INPUT ;
    USE SIGNAL ;
    PORT
      LAYER M5 ;
        RECT  28.608 0 28.632 0.192 ;
    END
  END s0_x[347]
  PIN s0_x[348]
    DIRECTION INPUT ;
    USE SIGNAL ;
    PORT
      LAYER M3 ;
        RECT  27.792 0 27.81 0.144 ;
    END
  END s0_x[348]
  PIN s0_x[349]
    DIRECTION INPUT ;
    USE SIGNAL ;
    PORT
      LAYER M5 ;
        RECT  28.704 0 28.728 0.192 ;
    END
  END s0_x[349]
  PIN s0_x[34]
    DIRECTION INPUT ;
    USE SIGNAL ;
    PORT
      LAYER M3 ;
        RECT  10.836 0 10.854 0.144 ;
    END
  END s0_x[34]
  PIN s0_x[350]
    DIRECTION INPUT ;
    USE SIGNAL ;
    PORT
      LAYER M3 ;
        RECT  27.9 0 27.918 0.144 ;
    END
  END s0_x[350]
  PIN s0_x[351]
    DIRECTION INPUT ;
    USE SIGNAL ;
    PORT
      LAYER M5 ;
        RECT  28.8 0 28.824 0.192 ;
    END
  END s0_x[351]
  PIN s0_x[352]
    DIRECTION INPUT ;
    USE SIGNAL ;
    PORT
      LAYER M3 ;
        RECT  28.008 0 28.026 0.144 ;
    END
  END s0_x[352]
  PIN s0_x[353]
    DIRECTION INPUT ;
    USE SIGNAL ;
    PORT
      LAYER M5 ;
        RECT  28.896 0 28.92 0.192 ;
    END
  END s0_x[353]
  PIN s0_x[354]
    DIRECTION INPUT ;
    USE SIGNAL ;
    PORT
      LAYER M3 ;
        RECT  28.116 0 28.134 0.144 ;
    END
  END s0_x[354]
  PIN s0_x[355]
    DIRECTION INPUT ;
    USE SIGNAL ;
    PORT
      LAYER M5 ;
        RECT  28.992 0 29.016 0.192 ;
    END
  END s0_x[355]
  PIN s0_x[356]
    DIRECTION INPUT ;
    USE SIGNAL ;
    PORT
      LAYER M3 ;
        RECT  28.224 0 28.242 0.144 ;
    END
  END s0_x[356]
  PIN s0_x[357]
    DIRECTION INPUT ;
    USE SIGNAL ;
    PORT
      LAYER M5 ;
        RECT  29.088 0 29.112 0.192 ;
    END
  END s0_x[357]
  PIN s0_x[358]
    DIRECTION INPUT ;
    USE SIGNAL ;
    PORT
      LAYER M3 ;
        RECT  28.332 0 28.35 0.144 ;
    END
  END s0_x[358]
  PIN s0_x[359]
    DIRECTION INPUT ;
    USE SIGNAL ;
    PORT
      LAYER M5 ;
        RECT  29.184 0 29.208 0.192 ;
    END
  END s0_x[359]
  PIN s0_x[35]
    DIRECTION INPUT ;
    USE SIGNAL ;
    PORT
      LAYER M5 ;
        RECT  13.632 0 13.656 0.192 ;
    END
  END s0_x[35]
  PIN s0_x[360]
    DIRECTION INPUT ;
    USE SIGNAL ;
    PORT
      LAYER M3 ;
        RECT  28.44 0 28.458 0.144 ;
    END
  END s0_x[360]
  PIN s0_x[361]
    DIRECTION INPUT ;
    USE SIGNAL ;
    PORT
      LAYER M5 ;
        RECT  29.28 0 29.304 0.192 ;
    END
  END s0_x[361]
  PIN s0_x[362]
    DIRECTION INPUT ;
    USE SIGNAL ;
    PORT
      LAYER M3 ;
        RECT  28.548 0 28.566 0.144 ;
    END
  END s0_x[362]
  PIN s0_x[363]
    DIRECTION INPUT ;
    USE SIGNAL ;
    PORT
      LAYER M5 ;
        RECT  29.376 0 29.4 0.192 ;
    END
  END s0_x[363]
  PIN s0_x[364]
    DIRECTION INPUT ;
    USE SIGNAL ;
    PORT
      LAYER M3 ;
        RECT  28.656 0 28.674 0.144 ;
    END
  END s0_x[364]
  PIN s0_x[365]
    DIRECTION INPUT ;
    USE SIGNAL ;
    PORT
      LAYER M5 ;
        RECT  29.472 0 29.496 0.192 ;
    END
  END s0_x[365]
  PIN s0_x[366]
    DIRECTION INPUT ;
    USE SIGNAL ;
    PORT
      LAYER M3 ;
        RECT  28.764 0 28.782 0.144 ;
    END
  END s0_x[366]
  PIN s0_x[367]
    DIRECTION INPUT ;
    USE SIGNAL ;
    PORT
      LAYER M5 ;
        RECT  29.568 0 29.592 0.192 ;
    END
  END s0_x[367]
  PIN s0_x[368]
    DIRECTION INPUT ;
    USE SIGNAL ;
    PORT
      LAYER M3 ;
        RECT  28.872 0 28.89 0.144 ;
    END
  END s0_x[368]
  PIN s0_x[369]
    DIRECTION INPUT ;
    USE SIGNAL ;
    PORT
      LAYER M5 ;
        RECT  29.664 0 29.688 0.192 ;
    END
  END s0_x[369]
  PIN s0_x[36]
    DIRECTION INPUT ;
    USE SIGNAL ;
    PORT
      LAYER M3 ;
        RECT  10.944 0 10.962 0.144 ;
    END
  END s0_x[36]
  PIN s0_x[370]
    DIRECTION INPUT ;
    USE SIGNAL ;
    PORT
      LAYER M3 ;
        RECT  28.98 0 28.998 0.144 ;
    END
  END s0_x[370]
  PIN s0_x[371]
    DIRECTION INPUT ;
    USE SIGNAL ;
    PORT
      LAYER M5 ;
        RECT  29.76 0 29.784 0.192 ;
    END
  END s0_x[371]
  PIN s0_x[372]
    DIRECTION INPUT ;
    USE SIGNAL ;
    PORT
      LAYER M3 ;
        RECT  29.088 0 29.106 0.144 ;
    END
  END s0_x[372]
  PIN s0_x[373]
    DIRECTION INPUT ;
    USE SIGNAL ;
    PORT
      LAYER M5 ;
        RECT  29.856 0 29.88 0.192 ;
    END
  END s0_x[373]
  PIN s0_x[374]
    DIRECTION INPUT ;
    USE SIGNAL ;
    PORT
      LAYER M3 ;
        RECT  29.196 0 29.214 0.144 ;
    END
  END s0_x[374]
  PIN s0_x[375]
    DIRECTION INPUT ;
    USE SIGNAL ;
    PORT
      LAYER M5 ;
        RECT  29.952 0 29.976 0.192 ;
    END
  END s0_x[375]
  PIN s0_x[376]
    DIRECTION INPUT ;
    USE SIGNAL ;
    PORT
      LAYER M3 ;
        RECT  29.304 0 29.322 0.144 ;
    END
  END s0_x[376]
  PIN s0_x[377]
    DIRECTION INPUT ;
    USE SIGNAL ;
    PORT
      LAYER M5 ;
        RECT  30.048 0 30.072 0.192 ;
    END
  END s0_x[377]
  PIN s0_x[378]
    DIRECTION INPUT ;
    USE SIGNAL ;
    PORT
      LAYER M3 ;
        RECT  29.412 0 29.43 0.144 ;
    END
  END s0_x[378]
  PIN s0_x[379]
    DIRECTION INPUT ;
    USE SIGNAL ;
    PORT
      LAYER M5 ;
        RECT  30.144 0 30.168 0.192 ;
    END
  END s0_x[379]
  PIN s0_x[37]
    DIRECTION INPUT ;
    USE SIGNAL ;
    PORT
      LAYER M5 ;
        RECT  13.728 0 13.752 0.192 ;
    END
  END s0_x[37]
  PIN s0_x[380]
    DIRECTION INPUT ;
    USE SIGNAL ;
    PORT
      LAYER M3 ;
        RECT  29.52 0 29.538 0.144 ;
    END
  END s0_x[380]
  PIN s0_x[381]
    DIRECTION INPUT ;
    USE SIGNAL ;
    PORT
      LAYER M5 ;
        RECT  30.24 0 30.264 0.192 ;
    END
  END s0_x[381]
  PIN s0_x[382]
    DIRECTION INPUT ;
    USE SIGNAL ;
    PORT
      LAYER M3 ;
        RECT  29.628 0 29.646 0.144 ;
    END
  END s0_x[382]
  PIN s0_x[383]
    DIRECTION INPUT ;
    USE SIGNAL ;
    PORT
      LAYER M5 ;
        RECT  30.336 0 30.36 0.192 ;
    END
  END s0_x[383]
  PIN s0_x[384]
    DIRECTION INPUT ;
    USE SIGNAL ;
    PORT
      LAYER M3 ;
        RECT  29.736 0 29.754 0.144 ;
    END
  END s0_x[384]
  PIN s0_x[385]
    DIRECTION INPUT ;
    USE SIGNAL ;
    PORT
      LAYER M5 ;
        RECT  30.432 0 30.456 0.192 ;
    END
  END s0_x[385]
  PIN s0_x[386]
    DIRECTION INPUT ;
    USE SIGNAL ;
    PORT
      LAYER M3 ;
        RECT  29.844 0 29.862 0.144 ;
    END
  END s0_x[386]
  PIN s0_x[387]
    DIRECTION INPUT ;
    USE SIGNAL ;
    PORT
      LAYER M5 ;
        RECT  30.528 0 30.552 0.192 ;
    END
  END s0_x[387]
  PIN s0_x[388]
    DIRECTION INPUT ;
    USE SIGNAL ;
    PORT
      LAYER M3 ;
        RECT  29.952 0 29.97 0.144 ;
    END
  END s0_x[388]
  PIN s0_x[389]
    DIRECTION INPUT ;
    USE SIGNAL ;
    PORT
      LAYER M5 ;
        RECT  30.624 0 30.648 0.192 ;
    END
  END s0_x[389]
  PIN s0_x[38]
    DIRECTION INPUT ;
    USE SIGNAL ;
    PORT
      LAYER M3 ;
        RECT  11.052 0 11.07 0.144 ;
    END
  END s0_x[38]
  PIN s0_x[390]
    DIRECTION INPUT ;
    USE SIGNAL ;
    PORT
      LAYER M3 ;
        RECT  30.06 0 30.078 0.144 ;
    END
  END s0_x[390]
  PIN s0_x[391]
    DIRECTION INPUT ;
    USE SIGNAL ;
    PORT
      LAYER M5 ;
        RECT  30.72 0 30.744 0.192 ;
    END
  END s0_x[391]
  PIN s0_x[392]
    DIRECTION INPUT ;
    USE SIGNAL ;
    PORT
      LAYER M3 ;
        RECT  30.168 0 30.186 0.144 ;
    END
  END s0_x[392]
  PIN s0_x[393]
    DIRECTION INPUT ;
    USE SIGNAL ;
    PORT
      LAYER M5 ;
        RECT  30.816 0 30.84 0.192 ;
    END
  END s0_x[393]
  PIN s0_x[394]
    DIRECTION INPUT ;
    USE SIGNAL ;
    PORT
      LAYER M3 ;
        RECT  30.276 0 30.294 0.144 ;
    END
  END s0_x[394]
  PIN s0_x[395]
    DIRECTION INPUT ;
    USE SIGNAL ;
    PORT
      LAYER M5 ;
        RECT  30.912 0 30.936 0.192 ;
    END
  END s0_x[395]
  PIN s0_x[396]
    DIRECTION INPUT ;
    USE SIGNAL ;
    PORT
      LAYER M3 ;
        RECT  30.384 0 30.402 0.144 ;
    END
  END s0_x[396]
  PIN s0_x[397]
    DIRECTION INPUT ;
    USE SIGNAL ;
    PORT
      LAYER M5 ;
        RECT  31.008 0 31.032 0.192 ;
    END
  END s0_x[397]
  PIN s0_x[398]
    DIRECTION INPUT ;
    USE SIGNAL ;
    PORT
      LAYER M3 ;
        RECT  30.492 0 30.51 0.144 ;
    END
  END s0_x[398]
  PIN s0_x[399]
    DIRECTION INPUT ;
    USE SIGNAL ;
    PORT
      LAYER M5 ;
        RECT  31.104 0 31.128 0.192 ;
    END
  END s0_x[399]
  PIN s0_x[39]
    DIRECTION INPUT ;
    USE SIGNAL ;
    PORT
      LAYER M5 ;
        RECT  13.824 0 13.848 0.192 ;
    END
  END s0_x[39]
  PIN s0_x[3]
    DIRECTION INPUT ;
    USE SIGNAL ;
    PORT
      LAYER M5 ;
        RECT  12.096 0 12.12 0.192 ;
    END
  END s0_x[3]
  PIN s0_x[400]
    DIRECTION INPUT ;
    USE SIGNAL ;
    PORT
      LAYER M3 ;
        RECT  30.6 0 30.618 0.144 ;
    END
  END s0_x[400]
  PIN s0_x[401]
    DIRECTION INPUT ;
    USE SIGNAL ;
    PORT
      LAYER M5 ;
        RECT  31.2 0 31.224 0.192 ;
    END
  END s0_x[401]
  PIN s0_x[402]
    DIRECTION INPUT ;
    USE SIGNAL ;
    PORT
      LAYER M3 ;
        RECT  30.708 0 30.726 0.144 ;
    END
  END s0_x[402]
  PIN s0_x[403]
    DIRECTION INPUT ;
    USE SIGNAL ;
    PORT
      LAYER M5 ;
        RECT  31.296 0 31.32 0.192 ;
    END
  END s0_x[403]
  PIN s0_x[404]
    DIRECTION INPUT ;
    USE SIGNAL ;
    PORT
      LAYER M3 ;
        RECT  30.816 0 30.834 0.144 ;
    END
  END s0_x[404]
  PIN s0_x[405]
    DIRECTION INPUT ;
    USE SIGNAL ;
    PORT
      LAYER M5 ;
        RECT  31.392 0 31.416 0.192 ;
    END
  END s0_x[405]
  PIN s0_x[406]
    DIRECTION INPUT ;
    USE SIGNAL ;
    PORT
      LAYER M3 ;
        RECT  30.924 0 30.942 0.144 ;
    END
  END s0_x[406]
  PIN s0_x[407]
    DIRECTION INPUT ;
    USE SIGNAL ;
    PORT
      LAYER M5 ;
        RECT  31.488 0 31.512 0.192 ;
    END
  END s0_x[407]
  PIN s0_x[408]
    DIRECTION INPUT ;
    USE SIGNAL ;
    PORT
      LAYER M3 ;
        RECT  31.032 0 31.05 0.144 ;
    END
  END s0_x[408]
  PIN s0_x[409]
    DIRECTION INPUT ;
    USE SIGNAL ;
    PORT
      LAYER M5 ;
        RECT  31.584 0 31.608 0.192 ;
    END
  END s0_x[409]
  PIN s0_x[40]
    DIRECTION INPUT ;
    USE SIGNAL ;
    PORT
      LAYER M3 ;
        RECT  11.16 0 11.178 0.144 ;
    END
  END s0_x[40]
  PIN s0_x[410]
    DIRECTION INPUT ;
    USE SIGNAL ;
    PORT
      LAYER M3 ;
        RECT  31.14 0 31.158 0.144 ;
    END
  END s0_x[410]
  PIN s0_x[411]
    DIRECTION INPUT ;
    USE SIGNAL ;
    PORT
      LAYER M5 ;
        RECT  31.68 0 31.704 0.192 ;
    END
  END s0_x[411]
  PIN s0_x[412]
    DIRECTION INPUT ;
    USE SIGNAL ;
    PORT
      LAYER M3 ;
        RECT  31.248 0 31.266 0.144 ;
    END
  END s0_x[412]
  PIN s0_x[413]
    DIRECTION INPUT ;
    USE SIGNAL ;
    PORT
      LAYER M5 ;
        RECT  31.776 0 31.8 0.192 ;
    END
  END s0_x[413]
  PIN s0_x[414]
    DIRECTION INPUT ;
    USE SIGNAL ;
    PORT
      LAYER M3 ;
        RECT  31.356 0 31.374 0.144 ;
    END
  END s0_x[414]
  PIN s0_x[415]
    DIRECTION INPUT ;
    USE SIGNAL ;
    PORT
      LAYER M5 ;
        RECT  31.872 0 31.896 0.192 ;
    END
  END s0_x[415]
  PIN s0_x[416]
    DIRECTION INPUT ;
    USE SIGNAL ;
    PORT
      LAYER M3 ;
        RECT  31.464 0 31.482 0.144 ;
    END
  END s0_x[416]
  PIN s0_x[417]
    DIRECTION INPUT ;
    USE SIGNAL ;
    PORT
      LAYER M5 ;
        RECT  31.968 0 31.992 0.192 ;
    END
  END s0_x[417]
  PIN s0_x[418]
    DIRECTION INPUT ;
    USE SIGNAL ;
    PORT
      LAYER M3 ;
        RECT  31.572 0 31.59 0.144 ;
    END
  END s0_x[418]
  PIN s0_x[419]
    DIRECTION INPUT ;
    USE SIGNAL ;
    PORT
      LAYER M5 ;
        RECT  32.064 0 32.088 0.192 ;
    END
  END s0_x[419]
  PIN s0_x[41]
    DIRECTION INPUT ;
    USE SIGNAL ;
    PORT
      LAYER M5 ;
        RECT  13.92 0 13.944 0.192 ;
    END
  END s0_x[41]
  PIN s0_x[420]
    DIRECTION INPUT ;
    USE SIGNAL ;
    PORT
      LAYER M3 ;
        RECT  31.68 0 31.698 0.144 ;
    END
  END s0_x[420]
  PIN s0_x[421]
    DIRECTION INPUT ;
    USE SIGNAL ;
    PORT
      LAYER M5 ;
        RECT  32.16 0 32.184 0.192 ;
    END
  END s0_x[421]
  PIN s0_x[422]
    DIRECTION INPUT ;
    USE SIGNAL ;
    PORT
      LAYER M3 ;
        RECT  31.788 0 31.806 0.144 ;
    END
  END s0_x[422]
  PIN s0_x[423]
    DIRECTION INPUT ;
    USE SIGNAL ;
    PORT
      LAYER M5 ;
        RECT  32.256 0 32.28 0.192 ;
    END
  END s0_x[423]
  PIN s0_x[424]
    DIRECTION INPUT ;
    USE SIGNAL ;
    PORT
      LAYER M3 ;
        RECT  31.896 0 31.914 0.144 ;
    END
  END s0_x[424]
  PIN s0_x[425]
    DIRECTION INPUT ;
    USE SIGNAL ;
    PORT
      LAYER M5 ;
        RECT  32.352 0 32.376 0.192 ;
    END
  END s0_x[425]
  PIN s0_x[426]
    DIRECTION INPUT ;
    USE SIGNAL ;
    PORT
      LAYER M3 ;
        RECT  32.004 0 32.022 0.144 ;
    END
  END s0_x[426]
  PIN s0_x[427]
    DIRECTION INPUT ;
    USE SIGNAL ;
    PORT
      LAYER M5 ;
        RECT  32.448 0 32.472 0.192 ;
    END
  END s0_x[427]
  PIN s0_x[428]
    DIRECTION INPUT ;
    USE SIGNAL ;
    PORT
      LAYER M3 ;
        RECT  32.112 0 32.13 0.144 ;
    END
  END s0_x[428]
  PIN s0_x[429]
    DIRECTION INPUT ;
    USE SIGNAL ;
    PORT
      LAYER M5 ;
        RECT  32.544 0 32.568 0.192 ;
    END
  END s0_x[429]
  PIN s0_x[42]
    DIRECTION INPUT ;
    USE SIGNAL ;
    PORT
      LAYER M3 ;
        RECT  11.268 0 11.286 0.144 ;
    END
  END s0_x[42]
  PIN s0_x[430]
    DIRECTION INPUT ;
    USE SIGNAL ;
    PORT
      LAYER M3 ;
        RECT  32.22 0 32.238 0.144 ;
    END
  END s0_x[430]
  PIN s0_x[431]
    DIRECTION INPUT ;
    USE SIGNAL ;
    PORT
      LAYER M5 ;
        RECT  32.64 0 32.664 0.192 ;
    END
  END s0_x[431]
  PIN s0_x[432]
    DIRECTION INPUT ;
    USE SIGNAL ;
    PORT
      LAYER M3 ;
        RECT  32.328 0 32.346 0.144 ;
    END
  END s0_x[432]
  PIN s0_x[433]
    DIRECTION INPUT ;
    USE SIGNAL ;
    PORT
      LAYER M5 ;
        RECT  32.736 0 32.76 0.192 ;
    END
  END s0_x[433]
  PIN s0_x[434]
    DIRECTION INPUT ;
    USE SIGNAL ;
    PORT
      LAYER M3 ;
        RECT  32.436 0 32.454 0.144 ;
    END
  END s0_x[434]
  PIN s0_x[435]
    DIRECTION INPUT ;
    USE SIGNAL ;
    PORT
      LAYER M5 ;
        RECT  32.832 0 32.856 0.192 ;
    END
  END s0_x[435]
  PIN s0_x[436]
    DIRECTION INPUT ;
    USE SIGNAL ;
    PORT
      LAYER M3 ;
        RECT  32.544 0 32.562 0.144 ;
    END
  END s0_x[436]
  PIN s0_x[437]
    DIRECTION INPUT ;
    USE SIGNAL ;
    PORT
      LAYER M5 ;
        RECT  32.928 0 32.952 0.192 ;
    END
  END s0_x[437]
  PIN s0_x[438]
    DIRECTION INPUT ;
    USE SIGNAL ;
    PORT
      LAYER M3 ;
        RECT  32.652 0 32.67 0.144 ;
    END
  END s0_x[438]
  PIN s0_x[439]
    DIRECTION INPUT ;
    USE SIGNAL ;
    PORT
      LAYER M5 ;
        RECT  33.024 0 33.048 0.192 ;
    END
  END s0_x[439]
  PIN s0_x[43]
    DIRECTION INPUT ;
    USE SIGNAL ;
    PORT
      LAYER M5 ;
        RECT  14.016 0 14.04 0.192 ;
    END
  END s0_x[43]
  PIN s0_x[440]
    DIRECTION INPUT ;
    USE SIGNAL ;
    PORT
      LAYER M3 ;
        RECT  32.76 0 32.778 0.144 ;
    END
  END s0_x[440]
  PIN s0_x[441]
    DIRECTION INPUT ;
    USE SIGNAL ;
    PORT
      LAYER M5 ;
        RECT  33.12 0 33.144 0.192 ;
    END
  END s0_x[441]
  PIN s0_x[442]
    DIRECTION INPUT ;
    USE SIGNAL ;
    PORT
      LAYER M3 ;
        RECT  32.868 0 32.886 0.144 ;
    END
  END s0_x[442]
  PIN s0_x[443]
    DIRECTION INPUT ;
    USE SIGNAL ;
    PORT
      LAYER M5 ;
        RECT  33.216 0 33.24 0.192 ;
    END
  END s0_x[443]
  PIN s0_x[444]
    DIRECTION INPUT ;
    USE SIGNAL ;
    PORT
      LAYER M3 ;
        RECT  32.976 0 32.994 0.144 ;
    END
  END s0_x[444]
  PIN s0_x[445]
    DIRECTION INPUT ;
    USE SIGNAL ;
    PORT
      LAYER M5 ;
        RECT  33.312 0 33.336 0.192 ;
    END
  END s0_x[445]
  PIN s0_x[446]
    DIRECTION INPUT ;
    USE SIGNAL ;
    PORT
      LAYER M3 ;
        RECT  33.084 0 33.102 0.144 ;
    END
  END s0_x[446]
  PIN s0_x[447]
    DIRECTION INPUT ;
    USE SIGNAL ;
    PORT
      LAYER M5 ;
        RECT  33.408 0 33.432 0.192 ;
    END
  END s0_x[447]
  PIN s0_x[448]
    DIRECTION INPUT ;
    USE SIGNAL ;
    PORT
      LAYER M3 ;
        RECT  33.192 0 33.21 0.144 ;
    END
  END s0_x[448]
  PIN s0_x[449]
    DIRECTION INPUT ;
    USE SIGNAL ;
    PORT
      LAYER M5 ;
        RECT  33.504 0 33.528 0.192 ;
    END
  END s0_x[449]
  PIN s0_x[44]
    DIRECTION INPUT ;
    USE SIGNAL ;
    PORT
      LAYER M3 ;
        RECT  11.376 0 11.394 0.144 ;
    END
  END s0_x[44]
  PIN s0_x[450]
    DIRECTION INPUT ;
    USE SIGNAL ;
    PORT
      LAYER M3 ;
        RECT  33.3 0 33.318 0.144 ;
    END
  END s0_x[450]
  PIN s0_x[451]
    DIRECTION INPUT ;
    USE SIGNAL ;
    PORT
      LAYER M5 ;
        RECT  33.6 0 33.624 0.192 ;
    END
  END s0_x[451]
  PIN s0_x[452]
    DIRECTION INPUT ;
    USE SIGNAL ;
    PORT
      LAYER M3 ;
        RECT  33.408 0 33.426 0.144 ;
    END
  END s0_x[452]
  PIN s0_x[453]
    DIRECTION INPUT ;
    USE SIGNAL ;
    PORT
      LAYER M5 ;
        RECT  33.696 0 33.72 0.192 ;
    END
  END s0_x[453]
  PIN s0_x[454]
    DIRECTION INPUT ;
    USE SIGNAL ;
    PORT
      LAYER M3 ;
        RECT  33.516 0 33.534 0.144 ;
    END
  END s0_x[454]
  PIN s0_x[455]
    DIRECTION INPUT ;
    USE SIGNAL ;
    PORT
      LAYER M5 ;
        RECT  33.792 0 33.816 0.192 ;
    END
  END s0_x[455]
  PIN s0_x[456]
    DIRECTION INPUT ;
    USE SIGNAL ;
    PORT
      LAYER M3 ;
        RECT  33.624 0 33.642 0.144 ;
    END
  END s0_x[456]
  PIN s0_x[457]
    DIRECTION INPUT ;
    USE SIGNAL ;
    PORT
      LAYER M5 ;
        RECT  33.888 0 33.912 0.192 ;
    END
  END s0_x[457]
  PIN s0_x[458]
    DIRECTION INPUT ;
    USE SIGNAL ;
    PORT
      LAYER M3 ;
        RECT  33.732 0 33.75 0.144 ;
    END
  END s0_x[458]
  PIN s0_x[459]
    DIRECTION INPUT ;
    USE SIGNAL ;
    PORT
      LAYER M5 ;
        RECT  33.984 0 34.008 0.192 ;
    END
  END s0_x[459]
  PIN s0_x[45]
    DIRECTION INPUT ;
    USE SIGNAL ;
    PORT
      LAYER M5 ;
        RECT  14.112 0 14.136 0.192 ;
    END
  END s0_x[45]
  PIN s0_x[460]
    DIRECTION INPUT ;
    USE SIGNAL ;
    PORT
      LAYER M3 ;
        RECT  33.84 0 33.858 0.144 ;
    END
  END s0_x[460]
  PIN s0_x[461]
    DIRECTION INPUT ;
    USE SIGNAL ;
    PORT
      LAYER M5 ;
        RECT  34.08 0 34.104 0.192 ;
    END
  END s0_x[461]
  PIN s0_x[462]
    DIRECTION INPUT ;
    USE SIGNAL ;
    PORT
      LAYER M3 ;
        RECT  33.948 0 33.966 0.144 ;
    END
  END s0_x[462]
  PIN s0_x[463]
    DIRECTION INPUT ;
    USE SIGNAL ;
    PORT
      LAYER M5 ;
        RECT  34.176 0 34.2 0.192 ;
    END
  END s0_x[463]
  PIN s0_x[464]
    DIRECTION INPUT ;
    USE SIGNAL ;
    PORT
      LAYER M3 ;
        RECT  34.056 0 34.074 0.144 ;
    END
  END s0_x[464]
  PIN s0_x[465]
    DIRECTION INPUT ;
    USE SIGNAL ;
    PORT
      LAYER M5 ;
        RECT  34.272 0 34.296 0.192 ;
    END
  END s0_x[465]
  PIN s0_x[466]
    DIRECTION INPUT ;
    USE SIGNAL ;
    PORT
      LAYER M3 ;
        RECT  34.164 0 34.182 0.144 ;
    END
  END s0_x[466]
  PIN s0_x[467]
    DIRECTION INPUT ;
    USE SIGNAL ;
    PORT
      LAYER M5 ;
        RECT  34.368 0 34.392 0.192 ;
    END
  END s0_x[467]
  PIN s0_x[468]
    DIRECTION INPUT ;
    USE SIGNAL ;
    PORT
      LAYER M3 ;
        RECT  34.272 0 34.29 0.144 ;
    END
  END s0_x[468]
  PIN s0_x[469]
    DIRECTION INPUT ;
    USE SIGNAL ;
    PORT
      LAYER M5 ;
        RECT  34.464 0 34.488 0.192 ;
    END
  END s0_x[469]
  PIN s0_x[46]
    DIRECTION INPUT ;
    USE SIGNAL ;
    PORT
      LAYER M3 ;
        RECT  11.484 0 11.502 0.144 ;
    END
  END s0_x[46]
  PIN s0_x[470]
    DIRECTION INPUT ;
    USE SIGNAL ;
    PORT
      LAYER M3 ;
        RECT  34.38 0 34.398 0.144 ;
    END
  END s0_x[470]
  PIN s0_x[471]
    DIRECTION INPUT ;
    USE SIGNAL ;
    PORT
      LAYER M5 ;
        RECT  34.56 0 34.584 0.192 ;
    END
  END s0_x[471]
  PIN s0_x[472]
    DIRECTION INPUT ;
    USE SIGNAL ;
    PORT
      LAYER M3 ;
        RECT  34.488 0 34.506 0.144 ;
    END
  END s0_x[472]
  PIN s0_x[473]
    DIRECTION INPUT ;
    USE SIGNAL ;
    PORT
      LAYER M5 ;
        RECT  34.656 0 34.68 0.192 ;
    END
  END s0_x[473]
  PIN s0_x[474]
    DIRECTION INPUT ;
    USE SIGNAL ;
    PORT
      LAYER M3 ;
        RECT  34.596 0 34.614 0.144 ;
    END
  END s0_x[474]
  PIN s0_x[475]
    DIRECTION INPUT ;
    USE SIGNAL ;
    PORT
      LAYER M5 ;
        RECT  34.752 0 34.776 0.192 ;
    END
  END s0_x[475]
  PIN s0_x[476]
    DIRECTION INPUT ;
    USE SIGNAL ;
    PORT
      LAYER M3 ;
        RECT  34.704 0 34.722 0.144 ;
    END
  END s0_x[476]
  PIN s0_x[477]
    DIRECTION INPUT ;
    USE SIGNAL ;
    PORT
      LAYER M5 ;
        RECT  34.848 0 34.872 0.192 ;
    END
  END s0_x[477]
  PIN s0_x[478]
    DIRECTION INPUT ;
    USE SIGNAL ;
    PORT
      LAYER M3 ;
        RECT  34.812 0 34.83 0.144 ;
    END
  END s0_x[478]
  PIN s0_x[479]
    DIRECTION INPUT ;
    USE SIGNAL ;
    PORT
      LAYER M5 ;
        RECT  34.944 0 34.968 0.192 ;
    END
  END s0_x[479]
  PIN s0_x[47]
    DIRECTION INPUT ;
    USE SIGNAL ;
    PORT
      LAYER M5 ;
        RECT  14.208 0 14.232 0.192 ;
    END
  END s0_x[47]
  PIN s0_x[480]
    DIRECTION INPUT ;
    USE SIGNAL ;
    PORT
      LAYER M3 ;
        RECT  34.92 0 34.938 0.144 ;
    END
  END s0_x[480]
  PIN s0_x[481]
    DIRECTION INPUT ;
    USE SIGNAL ;
    PORT
      LAYER M5 ;
        RECT  35.04 0 35.064 0.192 ;
    END
  END s0_x[481]
  PIN s0_x[482]
    DIRECTION INPUT ;
    USE SIGNAL ;
    PORT
      LAYER M3 ;
        RECT  35.028 0 35.046 0.144 ;
    END
  END s0_x[482]
  PIN s0_x[483]
    DIRECTION INPUT ;
    USE SIGNAL ;
    PORT
      LAYER M5 ;
        RECT  35.136 0 35.16 0.192 ;
    END
  END s0_x[483]
  PIN s0_x[484]
    DIRECTION INPUT ;
    USE SIGNAL ;
    PORT
      LAYER M3 ;
        RECT  35.136 0 35.154 0.144 ;
    END
  END s0_x[484]
  PIN s0_x[485]
    DIRECTION INPUT ;
    USE SIGNAL ;
    PORT
      LAYER M5 ;
        RECT  35.232 0 35.256 0.192 ;
    END
  END s0_x[485]
  PIN s0_x[486]
    DIRECTION INPUT ;
    USE SIGNAL ;
    PORT
      LAYER M3 ;
        RECT  35.244 0 35.262 0.144 ;
    END
  END s0_x[486]
  PIN s0_x[487]
    DIRECTION INPUT ;
    USE SIGNAL ;
    PORT
      LAYER M5 ;
        RECT  35.328 0 35.352 0.192 ;
    END
  END s0_x[487]
  PIN s0_x[488]
    DIRECTION INPUT ;
    USE SIGNAL ;
    PORT
      LAYER M3 ;
        RECT  35.352 0 35.37 0.144 ;
    END
  END s0_x[488]
  PIN s0_x[489]
    DIRECTION INPUT ;
    USE SIGNAL ;
    PORT
      LAYER M5 ;
        RECT  35.424 0 35.448 0.192 ;
    END
  END s0_x[489]
  PIN s0_x[48]
    DIRECTION INPUT ;
    USE SIGNAL ;
    PORT
      LAYER M3 ;
        RECT  11.592 0 11.61 0.144 ;
    END
  END s0_x[48]
  PIN s0_x[490]
    DIRECTION INPUT ;
    USE SIGNAL ;
    PORT
      LAYER M3 ;
        RECT  35.46 0 35.478 0.144 ;
    END
  END s0_x[490]
  PIN s0_x[491]
    DIRECTION INPUT ;
    USE SIGNAL ;
    PORT
      LAYER M5 ;
        RECT  35.52 0 35.544 0.192 ;
    END
  END s0_x[491]
  PIN s0_x[492]
    DIRECTION INPUT ;
    USE SIGNAL ;
    PORT
      LAYER M3 ;
        RECT  35.568 0 35.586 0.144 ;
    END
  END s0_x[492]
  PIN s0_x[493]
    DIRECTION INPUT ;
    USE SIGNAL ;
    PORT
      LAYER M5 ;
        RECT  35.616 0 35.64 0.192 ;
    END
  END s0_x[493]
  PIN s0_x[494]
    DIRECTION INPUT ;
    USE SIGNAL ;
    PORT
      LAYER M3 ;
        RECT  35.676 0 35.694 0.144 ;
    END
  END s0_x[494]
  PIN s0_x[495]
    DIRECTION INPUT ;
    USE SIGNAL ;
    PORT
      LAYER M5 ;
        RECT  35.712 0 35.736 0.192 ;
    END
  END s0_x[495]
  PIN s0_x[496]
    DIRECTION INPUT ;
    USE SIGNAL ;
    PORT
      LAYER M3 ;
        RECT  35.784 0 35.802 0.144 ;
    END
  END s0_x[496]
  PIN s0_x[497]
    DIRECTION INPUT ;
    USE SIGNAL ;
    PORT
      LAYER M5 ;
        RECT  35.808 0 35.832 0.192 ;
    END
  END s0_x[497]
  PIN s0_x[498]
    DIRECTION INPUT ;
    USE SIGNAL ;
    PORT
      LAYER M3 ;
        RECT  35.892 0 35.91 0.144 ;
    END
  END s0_x[498]
  PIN s0_x[499]
    DIRECTION INPUT ;
    USE SIGNAL ;
    PORT
      LAYER M5 ;
        RECT  35.904 0 35.928 0.192 ;
    END
  END s0_x[499]
  PIN s0_x[49]
    DIRECTION INPUT ;
    USE SIGNAL ;
    PORT
      LAYER M5 ;
        RECT  14.304 0 14.328 0.192 ;
    END
  END s0_x[49]
  PIN s0_x[4]
    DIRECTION INPUT ;
    USE SIGNAL ;
    PORT
      LAYER M3 ;
        RECT  9.216 0 9.234 0.144 ;
    END
  END s0_x[4]
  PIN s0_x[500]
    DIRECTION INPUT ;
    USE SIGNAL ;
    PORT
      LAYER M3 ;
        RECT  36 0 36.018 0.144 ;
    END
  END s0_x[500]
  PIN s0_x[501]
    DIRECTION INPUT ;
    USE SIGNAL ;
    PORT
      LAYER M5 ;
        RECT  36 0 36.024 0.192 ;
    END
  END s0_x[501]
  PIN s0_x[502]
    DIRECTION INPUT ;
    USE SIGNAL ;
    PORT
      LAYER M3 ;
        RECT  36.108 0 36.126 0.144 ;
    END
  END s0_x[502]
  PIN s0_x[503]
    DIRECTION INPUT ;
    USE SIGNAL ;
    PORT
      LAYER M5 ;
        RECT  36.096 0 36.12 0.192 ;
    END
  END s0_x[503]
  PIN s0_x[504]
    DIRECTION INPUT ;
    USE SIGNAL ;
    PORT
      LAYER M3 ;
        RECT  36.216 0 36.234 0.144 ;
    END
  END s0_x[504]
  PIN s0_x[505]
    DIRECTION INPUT ;
    USE SIGNAL ;
    PORT
      LAYER M5 ;
        RECT  36.192 0 36.216 0.192 ;
    END
  END s0_x[505]
  PIN s0_x[506]
    DIRECTION INPUT ;
    USE SIGNAL ;
    PORT
      LAYER M3 ;
        RECT  36.324 0 36.342 0.144 ;
    END
  END s0_x[506]
  PIN s0_x[507]
    DIRECTION INPUT ;
    USE SIGNAL ;
    PORT
      LAYER M5 ;
        RECT  36.288 0 36.312 0.192 ;
    END
  END s0_x[507]
  PIN s0_x[508]
    DIRECTION INPUT ;
    USE SIGNAL ;
    PORT
      LAYER M3 ;
        RECT  36.432 0 36.45 0.144 ;
    END
  END s0_x[508]
  PIN s0_x[509]
    DIRECTION INPUT ;
    USE SIGNAL ;
    PORT
      LAYER M5 ;
        RECT  36.384 0 36.408 0.192 ;
    END
  END s0_x[509]
  PIN s0_x[50]
    DIRECTION INPUT ;
    USE SIGNAL ;
    PORT
      LAYER M3 ;
        RECT  11.7 0 11.718 0.144 ;
    END
  END s0_x[50]
  PIN s0_x[510]
    DIRECTION INPUT ;
    USE SIGNAL ;
    PORT
      LAYER M3 ;
        RECT  36.54 0 36.558 0.144 ;
    END
  END s0_x[510]
  PIN s0_x[511]
    DIRECTION INPUT ;
    USE SIGNAL ;
    PORT
      LAYER M5 ;
        RECT  36.48 0 36.504 0.192 ;
    END
  END s0_x[511]
  PIN s0_x[512]
    DIRECTION INPUT ;
    USE SIGNAL ;
    PORT
      LAYER M3 ;
        RECT  36.648 0 36.666 0.144 ;
    END
  END s0_x[512]
  PIN s0_x[513]
    DIRECTION INPUT ;
    USE SIGNAL ;
    PORT
      LAYER M5 ;
        RECT  36.576 0 36.6 0.192 ;
    END
  END s0_x[513]
  PIN s0_x[514]
    DIRECTION INPUT ;
    USE SIGNAL ;
    PORT
      LAYER M3 ;
        RECT  36.756 0 36.774 0.144 ;
    END
  END s0_x[514]
  PIN s0_x[515]
    DIRECTION INPUT ;
    USE SIGNAL ;
    PORT
      LAYER M5 ;
        RECT  36.672 0 36.696 0.192 ;
    END
  END s0_x[515]
  PIN s0_x[516]
    DIRECTION INPUT ;
    USE SIGNAL ;
    PORT
      LAYER M3 ;
        RECT  36.864 0 36.882 0.144 ;
    END
  END s0_x[516]
  PIN s0_x[517]
    DIRECTION INPUT ;
    USE SIGNAL ;
    PORT
      LAYER M5 ;
        RECT  36.768 0 36.792 0.192 ;
    END
  END s0_x[517]
  PIN s0_x[518]
    DIRECTION INPUT ;
    USE SIGNAL ;
    PORT
      LAYER M3 ;
        RECT  36.972 0 36.99 0.144 ;
    END
  END s0_x[518]
  PIN s0_x[519]
    DIRECTION INPUT ;
    USE SIGNAL ;
    PORT
      LAYER M5 ;
        RECT  36.864 0 36.888 0.192 ;
    END
  END s0_x[519]
  PIN s0_x[51]
    DIRECTION INPUT ;
    USE SIGNAL ;
    PORT
      LAYER M5 ;
        RECT  14.4 0 14.424 0.192 ;
    END
  END s0_x[51]
  PIN s0_x[520]
    DIRECTION INPUT ;
    USE SIGNAL ;
    PORT
      LAYER M3 ;
        RECT  37.08 0 37.098 0.144 ;
    END
  END s0_x[520]
  PIN s0_x[521]
    DIRECTION INPUT ;
    USE SIGNAL ;
    PORT
      LAYER M5 ;
        RECT  36.96 0 36.984 0.192 ;
    END
  END s0_x[521]
  PIN s0_x[522]
    DIRECTION INPUT ;
    USE SIGNAL ;
    PORT
      LAYER M3 ;
        RECT  37.188 0 37.206 0.144 ;
    END
  END s0_x[522]
  PIN s0_x[523]
    DIRECTION INPUT ;
    USE SIGNAL ;
    PORT
      LAYER M5 ;
        RECT  37.056 0 37.08 0.192 ;
    END
  END s0_x[523]
  PIN s0_x[524]
    DIRECTION INPUT ;
    USE SIGNAL ;
    PORT
      LAYER M3 ;
        RECT  37.296 0 37.314 0.144 ;
    END
  END s0_x[524]
  PIN s0_x[525]
    DIRECTION INPUT ;
    USE SIGNAL ;
    PORT
      LAYER M5 ;
        RECT  37.152 0 37.176 0.192 ;
    END
  END s0_x[525]
  PIN s0_x[526]
    DIRECTION INPUT ;
    USE SIGNAL ;
    PORT
      LAYER M3 ;
        RECT  37.404 0 37.422 0.144 ;
    END
  END s0_x[526]
  PIN s0_x[527]
    DIRECTION INPUT ;
    USE SIGNAL ;
    PORT
      LAYER M5 ;
        RECT  37.248 0 37.272 0.192 ;
    END
  END s0_x[527]
  PIN s0_x[528]
    DIRECTION INPUT ;
    USE SIGNAL ;
    PORT
      LAYER M3 ;
        RECT  37.512 0 37.53 0.144 ;
    END
  END s0_x[528]
  PIN s0_x[529]
    DIRECTION INPUT ;
    USE SIGNAL ;
    PORT
      LAYER M5 ;
        RECT  37.344 0 37.368 0.192 ;
    END
  END s0_x[529]
  PIN s0_x[52]
    DIRECTION INPUT ;
    USE SIGNAL ;
    PORT
      LAYER M3 ;
        RECT  11.808 0 11.826 0.144 ;
    END
  END s0_x[52]
  PIN s0_x[530]
    DIRECTION INPUT ;
    USE SIGNAL ;
    PORT
      LAYER M3 ;
        RECT  37.62 0 37.638 0.144 ;
    END
  END s0_x[530]
  PIN s0_x[531]
    DIRECTION INPUT ;
    USE SIGNAL ;
    PORT
      LAYER M5 ;
        RECT  37.44 0 37.464 0.192 ;
    END
  END s0_x[531]
  PIN s0_x[532]
    DIRECTION INPUT ;
    USE SIGNAL ;
    PORT
      LAYER M3 ;
        RECT  37.728 0 37.746 0.144 ;
    END
  END s0_x[532]
  PIN s0_x[533]
    DIRECTION INPUT ;
    USE SIGNAL ;
    PORT
      LAYER M5 ;
        RECT  37.536 0 37.56 0.192 ;
    END
  END s0_x[533]
  PIN s0_x[534]
    DIRECTION INPUT ;
    USE SIGNAL ;
    PORT
      LAYER M3 ;
        RECT  37.836 0 37.854 0.144 ;
    END
  END s0_x[534]
  PIN s0_x[535]
    DIRECTION INPUT ;
    USE SIGNAL ;
    PORT
      LAYER M5 ;
        RECT  37.632 0 37.656 0.192 ;
    END
  END s0_x[535]
  PIN s0_x[536]
    DIRECTION INPUT ;
    USE SIGNAL ;
    PORT
      LAYER M3 ;
        RECT  37.944 0 37.962 0.144 ;
    END
  END s0_x[536]
  PIN s0_x[537]
    DIRECTION INPUT ;
    USE SIGNAL ;
    PORT
      LAYER M5 ;
        RECT  37.728 0 37.752 0.192 ;
    END
  END s0_x[537]
  PIN s0_x[538]
    DIRECTION INPUT ;
    USE SIGNAL ;
    PORT
      LAYER M3 ;
        RECT  38.052 0 38.07 0.144 ;
    END
  END s0_x[538]
  PIN s0_x[539]
    DIRECTION INPUT ;
    USE SIGNAL ;
    PORT
      LAYER M5 ;
        RECT  37.824 0 37.848 0.192 ;
    END
  END s0_x[539]
  PIN s0_x[53]
    DIRECTION INPUT ;
    USE SIGNAL ;
    PORT
      LAYER M5 ;
        RECT  14.496 0 14.52 0.192 ;
    END
  END s0_x[53]
  PIN s0_x[540]
    DIRECTION INPUT ;
    USE SIGNAL ;
    PORT
      LAYER M3 ;
        RECT  38.16 0 38.178 0.144 ;
    END
  END s0_x[540]
  PIN s0_x[541]
    DIRECTION INPUT ;
    USE SIGNAL ;
    PORT
      LAYER M5 ;
        RECT  37.92 0 37.944 0.192 ;
    END
  END s0_x[541]
  PIN s0_x[542]
    DIRECTION INPUT ;
    USE SIGNAL ;
    PORT
      LAYER M3 ;
        RECT  38.268 0 38.286 0.144 ;
    END
  END s0_x[542]
  PIN s0_x[543]
    DIRECTION INPUT ;
    USE SIGNAL ;
    PORT
      LAYER M5 ;
        RECT  38.016 0 38.04 0.192 ;
    END
  END s0_x[543]
  PIN s0_x[544]
    DIRECTION INPUT ;
    USE SIGNAL ;
    PORT
      LAYER M3 ;
        RECT  38.376 0 38.394 0.144 ;
    END
  END s0_x[544]
  PIN s0_x[545]
    DIRECTION INPUT ;
    USE SIGNAL ;
    PORT
      LAYER M5 ;
        RECT  38.112 0 38.136 0.192 ;
    END
  END s0_x[545]
  PIN s0_x[546]
    DIRECTION INPUT ;
    USE SIGNAL ;
    PORT
      LAYER M3 ;
        RECT  38.484 0 38.502 0.144 ;
    END
  END s0_x[546]
  PIN s0_x[547]
    DIRECTION INPUT ;
    USE SIGNAL ;
    PORT
      LAYER M5 ;
        RECT  38.208 0 38.232 0.192 ;
    END
  END s0_x[547]
  PIN s0_x[548]
    DIRECTION INPUT ;
    USE SIGNAL ;
    PORT
      LAYER M3 ;
        RECT  38.592 0 38.61 0.144 ;
    END
  END s0_x[548]
  PIN s0_x[549]
    DIRECTION INPUT ;
    USE SIGNAL ;
    PORT
      LAYER M5 ;
        RECT  38.304 0 38.328 0.192 ;
    END
  END s0_x[549]
  PIN s0_x[54]
    DIRECTION INPUT ;
    USE SIGNAL ;
    PORT
      LAYER M3 ;
        RECT  11.916 0 11.934 0.144 ;
    END
  END s0_x[54]
  PIN s0_x[550]
    DIRECTION INPUT ;
    USE SIGNAL ;
    PORT
      LAYER M3 ;
        RECT  38.7 0 38.718 0.144 ;
    END
  END s0_x[550]
  PIN s0_x[551]
    DIRECTION INPUT ;
    USE SIGNAL ;
    PORT
      LAYER M5 ;
        RECT  38.4 0 38.424 0.192 ;
    END
  END s0_x[551]
  PIN s0_x[552]
    DIRECTION INPUT ;
    USE SIGNAL ;
    PORT
      LAYER M3 ;
        RECT  38.808 0 38.826 0.144 ;
    END
  END s0_x[552]
  PIN s0_x[553]
    DIRECTION INPUT ;
    USE SIGNAL ;
    PORT
      LAYER M5 ;
        RECT  38.496 0 38.52 0.192 ;
    END
  END s0_x[553]
  PIN s0_x[554]
    DIRECTION INPUT ;
    USE SIGNAL ;
    PORT
      LAYER M3 ;
        RECT  38.916 0 38.934 0.144 ;
    END
  END s0_x[554]
  PIN s0_x[555]
    DIRECTION INPUT ;
    USE SIGNAL ;
    PORT
      LAYER M5 ;
        RECT  38.592 0 38.616 0.192 ;
    END
  END s0_x[555]
  PIN s0_x[556]
    DIRECTION INPUT ;
    USE SIGNAL ;
    PORT
      LAYER M3 ;
        RECT  39.024 0 39.042 0.144 ;
    END
  END s0_x[556]
  PIN s0_x[557]
    DIRECTION INPUT ;
    USE SIGNAL ;
    PORT
      LAYER M5 ;
        RECT  38.688 0 38.712 0.192 ;
    END
  END s0_x[557]
  PIN s0_x[558]
    DIRECTION INPUT ;
    USE SIGNAL ;
    PORT
      LAYER M3 ;
        RECT  39.132 0 39.15 0.144 ;
    END
  END s0_x[558]
  PIN s0_x[559]
    DIRECTION INPUT ;
    USE SIGNAL ;
    PORT
      LAYER M5 ;
        RECT  38.784 0 38.808 0.192 ;
    END
  END s0_x[559]
  PIN s0_x[55]
    DIRECTION INPUT ;
    USE SIGNAL ;
    PORT
      LAYER M5 ;
        RECT  14.592 0 14.616 0.192 ;
    END
  END s0_x[55]
  PIN s0_x[560]
    DIRECTION INPUT ;
    USE SIGNAL ;
    PORT
      LAYER M3 ;
        RECT  39.24 0 39.258 0.144 ;
    END
  END s0_x[560]
  PIN s0_x[561]
    DIRECTION INPUT ;
    USE SIGNAL ;
    PORT
      LAYER M5 ;
        RECT  38.88 0 38.904 0.192 ;
    END
  END s0_x[561]
  PIN s0_x[562]
    DIRECTION INPUT ;
    USE SIGNAL ;
    PORT
      LAYER M3 ;
        RECT  39.348 0 39.366 0.144 ;
    END
  END s0_x[562]
  PIN s0_x[563]
    DIRECTION INPUT ;
    USE SIGNAL ;
    PORT
      LAYER M5 ;
        RECT  38.976 0 39 0.192 ;
    END
  END s0_x[563]
  PIN s0_x[564]
    DIRECTION INPUT ;
    USE SIGNAL ;
    PORT
      LAYER M3 ;
        RECT  39.456 0 39.474 0.144 ;
    END
  END s0_x[564]
  PIN s0_x[565]
    DIRECTION INPUT ;
    USE SIGNAL ;
    PORT
      LAYER M5 ;
        RECT  39.072 0 39.096 0.192 ;
    END
  END s0_x[565]
  PIN s0_x[566]
    DIRECTION INPUT ;
    USE SIGNAL ;
    PORT
      LAYER M3 ;
        RECT  39.564 0 39.582 0.144 ;
    END
  END s0_x[566]
  PIN s0_x[567]
    DIRECTION INPUT ;
    USE SIGNAL ;
    PORT
      LAYER M5 ;
        RECT  39.168 0 39.192 0.192 ;
    END
  END s0_x[567]
  PIN s0_x[568]
    DIRECTION INPUT ;
    USE SIGNAL ;
    PORT
      LAYER M3 ;
        RECT  39.672 0 39.69 0.144 ;
    END
  END s0_x[568]
  PIN s0_x[569]
    DIRECTION INPUT ;
    USE SIGNAL ;
    PORT
      LAYER M5 ;
        RECT  39.264 0 39.288 0.192 ;
    END
  END s0_x[569]
  PIN s0_x[56]
    DIRECTION INPUT ;
    USE SIGNAL ;
    PORT
      LAYER M3 ;
        RECT  12.024 0 12.042 0.144 ;
    END
  END s0_x[56]
  PIN s0_x[570]
    DIRECTION INPUT ;
    USE SIGNAL ;
    PORT
      LAYER M3 ;
        RECT  39.78 0 39.798 0.144 ;
    END
  END s0_x[570]
  PIN s0_x[571]
    DIRECTION INPUT ;
    USE SIGNAL ;
    PORT
      LAYER M5 ;
        RECT  39.36 0 39.384 0.192 ;
    END
  END s0_x[571]
  PIN s0_x[572]
    DIRECTION INPUT ;
    USE SIGNAL ;
    PORT
      LAYER M3 ;
        RECT  39.888 0 39.906 0.144 ;
    END
  END s0_x[572]
  PIN s0_x[573]
    DIRECTION INPUT ;
    USE SIGNAL ;
    PORT
      LAYER M5 ;
        RECT  39.456 0 39.48 0.192 ;
    END
  END s0_x[573]
  PIN s0_x[574]
    DIRECTION INPUT ;
    USE SIGNAL ;
    PORT
      LAYER M3 ;
        RECT  39.996 0 40.014 0.144 ;
    END
  END s0_x[574]
  PIN s0_x[575]
    DIRECTION INPUT ;
    USE SIGNAL ;
    PORT
      LAYER M5 ;
        RECT  39.552 0 39.576 0.192 ;
    END
  END s0_x[575]
  PIN s0_x[576]
    DIRECTION INPUT ;
    USE SIGNAL ;
    PORT
      LAYER M3 ;
        RECT  40.104 0 40.122 0.144 ;
    END
  END s0_x[576]
  PIN s0_x[577]
    DIRECTION INPUT ;
    USE SIGNAL ;
    PORT
      LAYER M5 ;
        RECT  39.648 0 39.672 0.192 ;
    END
  END s0_x[577]
  PIN s0_x[578]
    DIRECTION INPUT ;
    USE SIGNAL ;
    PORT
      LAYER M3 ;
        RECT  40.212 0 40.23 0.144 ;
    END
  END s0_x[578]
  PIN s0_x[579]
    DIRECTION INPUT ;
    USE SIGNAL ;
    PORT
      LAYER M5 ;
        RECT  39.744 0 39.768 0.192 ;
    END
  END s0_x[579]
  PIN s0_x[57]
    DIRECTION INPUT ;
    USE SIGNAL ;
    PORT
      LAYER M5 ;
        RECT  14.688 0 14.712 0.192 ;
    END
  END s0_x[57]
  PIN s0_x[580]
    DIRECTION INPUT ;
    USE SIGNAL ;
    PORT
      LAYER M3 ;
        RECT  40.32 0 40.338 0.144 ;
    END
  END s0_x[580]
  PIN s0_x[581]
    DIRECTION INPUT ;
    USE SIGNAL ;
    PORT
      LAYER M5 ;
        RECT  39.84 0 39.864 0.192 ;
    END
  END s0_x[581]
  PIN s0_x[582]
    DIRECTION INPUT ;
    USE SIGNAL ;
    PORT
      LAYER M3 ;
        RECT  40.428 0 40.446 0.144 ;
    END
  END s0_x[582]
  PIN s0_x[583]
    DIRECTION INPUT ;
    USE SIGNAL ;
    PORT
      LAYER M5 ;
        RECT  39.936 0 39.96 0.192 ;
    END
  END s0_x[583]
  PIN s0_x[584]
    DIRECTION INPUT ;
    USE SIGNAL ;
    PORT
      LAYER M3 ;
        RECT  40.536 0 40.554 0.144 ;
    END
  END s0_x[584]
  PIN s0_x[585]
    DIRECTION INPUT ;
    USE SIGNAL ;
    PORT
      LAYER M5 ;
        RECT  40.032 0 40.056 0.192 ;
    END
  END s0_x[585]
  PIN s0_x[586]
    DIRECTION INPUT ;
    USE SIGNAL ;
    PORT
      LAYER M3 ;
        RECT  40.644 0 40.662 0.144 ;
    END
  END s0_x[586]
  PIN s0_x[587]
    DIRECTION INPUT ;
    USE SIGNAL ;
    PORT
      LAYER M5 ;
        RECT  40.128 0 40.152 0.192 ;
    END
  END s0_x[587]
  PIN s0_x[588]
    DIRECTION INPUT ;
    USE SIGNAL ;
    PORT
      LAYER M3 ;
        RECT  40.752 0 40.77 0.144 ;
    END
  END s0_x[588]
  PIN s0_x[589]
    DIRECTION INPUT ;
    USE SIGNAL ;
    PORT
      LAYER M5 ;
        RECT  40.224 0 40.248 0.192 ;
    END
  END s0_x[589]
  PIN s0_x[58]
    DIRECTION INPUT ;
    USE SIGNAL ;
    PORT
      LAYER M3 ;
        RECT  12.132 0 12.15 0.144 ;
    END
  END s0_x[58]
  PIN s0_x[590]
    DIRECTION INPUT ;
    USE SIGNAL ;
    PORT
      LAYER M3 ;
        RECT  40.86 0 40.878 0.144 ;
    END
  END s0_x[590]
  PIN s0_x[591]
    DIRECTION INPUT ;
    USE SIGNAL ;
    PORT
      LAYER M5 ;
        RECT  40.32 0 40.344 0.192 ;
    END
  END s0_x[591]
  PIN s0_x[592]
    DIRECTION INPUT ;
    USE SIGNAL ;
    PORT
      LAYER M3 ;
        RECT  40.968 0 40.986 0.144 ;
    END
  END s0_x[592]
  PIN s0_x[593]
    DIRECTION INPUT ;
    USE SIGNAL ;
    PORT
      LAYER M5 ;
        RECT  40.416 0 40.44 0.192 ;
    END
  END s0_x[593]
  PIN s0_x[594]
    DIRECTION INPUT ;
    USE SIGNAL ;
    PORT
      LAYER M3 ;
        RECT  41.076 0 41.094 0.144 ;
    END
  END s0_x[594]
  PIN s0_x[595]
    DIRECTION INPUT ;
    USE SIGNAL ;
    PORT
      LAYER M5 ;
        RECT  40.512 0 40.536 0.192 ;
    END
  END s0_x[595]
  PIN s0_x[596]
    DIRECTION INPUT ;
    USE SIGNAL ;
    PORT
      LAYER M3 ;
        RECT  41.184 0 41.202 0.144 ;
    END
  END s0_x[596]
  PIN s0_x[597]
    DIRECTION INPUT ;
    USE SIGNAL ;
    PORT
      LAYER M5 ;
        RECT  40.608 0 40.632 0.192 ;
    END
  END s0_x[597]
  PIN s0_x[598]
    DIRECTION INPUT ;
    USE SIGNAL ;
    PORT
      LAYER M3 ;
        RECT  41.292 0 41.31 0.144 ;
    END
  END s0_x[598]
  PIN s0_x[599]
    DIRECTION INPUT ;
    USE SIGNAL ;
    PORT
      LAYER M5 ;
        RECT  40.704 0 40.728 0.192 ;
    END
  END s0_x[599]
  PIN s0_x[59]
    DIRECTION INPUT ;
    USE SIGNAL ;
    PORT
      LAYER M5 ;
        RECT  14.784 0 14.808 0.192 ;
    END
  END s0_x[59]
  PIN s0_x[5]
    DIRECTION INPUT ;
    USE SIGNAL ;
    PORT
      LAYER M5 ;
        RECT  12.192 0 12.216 0.192 ;
    END
  END s0_x[5]
  PIN s0_x[600]
    DIRECTION INPUT ;
    USE SIGNAL ;
    PORT
      LAYER M3 ;
        RECT  41.4 0 41.418 0.144 ;
    END
  END s0_x[600]
  PIN s0_x[601]
    DIRECTION INPUT ;
    USE SIGNAL ;
    PORT
      LAYER M5 ;
        RECT  40.8 0 40.824 0.192 ;
    END
  END s0_x[601]
  PIN s0_x[602]
    DIRECTION INPUT ;
    USE SIGNAL ;
    PORT
      LAYER M3 ;
        RECT  41.508 0 41.526 0.144 ;
    END
  END s0_x[602]
  PIN s0_x[603]
    DIRECTION INPUT ;
    USE SIGNAL ;
    PORT
      LAYER M5 ;
        RECT  40.896 0 40.92 0.192 ;
    END
  END s0_x[603]
  PIN s0_x[604]
    DIRECTION INPUT ;
    USE SIGNAL ;
    PORT
      LAYER M3 ;
        RECT  41.616 0 41.634 0.144 ;
    END
  END s0_x[604]
  PIN s0_x[605]
    DIRECTION INPUT ;
    USE SIGNAL ;
    PORT
      LAYER M5 ;
        RECT  40.992 0 41.016 0.192 ;
    END
  END s0_x[605]
  PIN s0_x[606]
    DIRECTION INPUT ;
    USE SIGNAL ;
    PORT
      LAYER M3 ;
        RECT  41.724 0 41.742 0.144 ;
    END
  END s0_x[606]
  PIN s0_x[607]
    DIRECTION INPUT ;
    USE SIGNAL ;
    PORT
      LAYER M5 ;
        RECT  41.088 0 41.112 0.192 ;
    END
  END s0_x[607]
  PIN s0_x[608]
    DIRECTION INPUT ;
    USE SIGNAL ;
    PORT
      LAYER M3 ;
        RECT  41.832 0 41.85 0.144 ;
    END
  END s0_x[608]
  PIN s0_x[609]
    DIRECTION INPUT ;
    USE SIGNAL ;
    PORT
      LAYER M5 ;
        RECT  41.184 0 41.208 0.192 ;
    END
  END s0_x[609]
  PIN s0_x[60]
    DIRECTION INPUT ;
    USE SIGNAL ;
    PORT
      LAYER M3 ;
        RECT  12.24 0 12.258 0.144 ;
    END
  END s0_x[60]
  PIN s0_x[610]
    DIRECTION INPUT ;
    USE SIGNAL ;
    PORT
      LAYER M3 ;
        RECT  41.94 0 41.958 0.144 ;
    END
  END s0_x[610]
  PIN s0_x[611]
    DIRECTION INPUT ;
    USE SIGNAL ;
    PORT
      LAYER M5 ;
        RECT  41.28 0 41.304 0.192 ;
    END
  END s0_x[611]
  PIN s0_x[612]
    DIRECTION INPUT ;
    USE SIGNAL ;
    PORT
      LAYER M3 ;
        RECT  42.048 0 42.066 0.144 ;
    END
  END s0_x[612]
  PIN s0_x[613]
    DIRECTION INPUT ;
    USE SIGNAL ;
    PORT
      LAYER M5 ;
        RECT  41.376 0 41.4 0.192 ;
    END
  END s0_x[613]
  PIN s0_x[614]
    DIRECTION INPUT ;
    USE SIGNAL ;
    PORT
      LAYER M3 ;
        RECT  42.156 0 42.174 0.144 ;
    END
  END s0_x[614]
  PIN s0_x[615]
    DIRECTION INPUT ;
    USE SIGNAL ;
    PORT
      LAYER M5 ;
        RECT  41.472 0 41.496 0.192 ;
    END
  END s0_x[615]
  PIN s0_x[616]
    DIRECTION INPUT ;
    USE SIGNAL ;
    PORT
      LAYER M3 ;
        RECT  42.264 0 42.282 0.144 ;
    END
  END s0_x[616]
  PIN s0_x[617]
    DIRECTION INPUT ;
    USE SIGNAL ;
    PORT
      LAYER M5 ;
        RECT  41.568 0 41.592 0.192 ;
    END
  END s0_x[617]
  PIN s0_x[618]
    DIRECTION INPUT ;
    USE SIGNAL ;
    PORT
      LAYER M3 ;
        RECT  42.372 0 42.39 0.144 ;
    END
  END s0_x[618]
  PIN s0_x[619]
    DIRECTION INPUT ;
    USE SIGNAL ;
    PORT
      LAYER M5 ;
        RECT  41.664 0 41.688 0.192 ;
    END
  END s0_x[619]
  PIN s0_x[61]
    DIRECTION INPUT ;
    USE SIGNAL ;
    PORT
      LAYER M5 ;
        RECT  14.88 0 14.904 0.192 ;
    END
  END s0_x[61]
  PIN s0_x[620]
    DIRECTION INPUT ;
    USE SIGNAL ;
    PORT
      LAYER M3 ;
        RECT  42.48 0 42.498 0.144 ;
    END
  END s0_x[620]
  PIN s0_x[621]
    DIRECTION INPUT ;
    USE SIGNAL ;
    PORT
      LAYER M5 ;
        RECT  41.76 0 41.784 0.192 ;
    END
  END s0_x[621]
  PIN s0_x[622]
    DIRECTION INPUT ;
    USE SIGNAL ;
    PORT
      LAYER M3 ;
        RECT  42.588 0 42.606 0.144 ;
    END
  END s0_x[622]
  PIN s0_x[623]
    DIRECTION INPUT ;
    USE SIGNAL ;
    PORT
      LAYER M5 ;
        RECT  41.856 0 41.88 0.192 ;
    END
  END s0_x[623]
  PIN s0_x[624]
    DIRECTION INPUT ;
    USE SIGNAL ;
    PORT
      LAYER M3 ;
        RECT  42.696 0 42.714 0.144 ;
    END
  END s0_x[624]
  PIN s0_x[625]
    DIRECTION INPUT ;
    USE SIGNAL ;
    PORT
      LAYER M5 ;
        RECT  41.952 0 41.976 0.192 ;
    END
  END s0_x[625]
  PIN s0_x[626]
    DIRECTION INPUT ;
    USE SIGNAL ;
    PORT
      LAYER M3 ;
        RECT  42.804 0 42.822 0.144 ;
    END
  END s0_x[626]
  PIN s0_x[627]
    DIRECTION INPUT ;
    USE SIGNAL ;
    PORT
      LAYER M5 ;
        RECT  42.048 0 42.072 0.192 ;
    END
  END s0_x[627]
  PIN s0_x[628]
    DIRECTION INPUT ;
    USE SIGNAL ;
    PORT
      LAYER M3 ;
        RECT  42.912 0 42.93 0.144 ;
    END
  END s0_x[628]
  PIN s0_x[629]
    DIRECTION INPUT ;
    USE SIGNAL ;
    PORT
      LAYER M5 ;
        RECT  42.144 0 42.168 0.192 ;
    END
  END s0_x[629]
  PIN s0_x[62]
    DIRECTION INPUT ;
    USE SIGNAL ;
    PORT
      LAYER M3 ;
        RECT  12.348 0 12.366 0.144 ;
    END
  END s0_x[62]
  PIN s0_x[630]
    DIRECTION INPUT ;
    USE SIGNAL ;
    PORT
      LAYER M3 ;
        RECT  43.02 0 43.038 0.144 ;
    END
  END s0_x[630]
  PIN s0_x[631]
    DIRECTION INPUT ;
    USE SIGNAL ;
    PORT
      LAYER M5 ;
        RECT  42.24 0 42.264 0.192 ;
    END
  END s0_x[631]
  PIN s0_x[632]
    DIRECTION INPUT ;
    USE SIGNAL ;
    PORT
      LAYER M3 ;
        RECT  43.128 0 43.146 0.144 ;
    END
  END s0_x[632]
  PIN s0_x[633]
    DIRECTION INPUT ;
    USE SIGNAL ;
    PORT
      LAYER M5 ;
        RECT  42.336 0 42.36 0.192 ;
    END
  END s0_x[633]
  PIN s0_x[634]
    DIRECTION INPUT ;
    USE SIGNAL ;
    PORT
      LAYER M3 ;
        RECT  43.236 0 43.254 0.144 ;
    END
  END s0_x[634]
  PIN s0_x[635]
    DIRECTION INPUT ;
    USE SIGNAL ;
    PORT
      LAYER M5 ;
        RECT  42.432 0 42.456 0.192 ;
    END
  END s0_x[635]
  PIN s0_x[636]
    DIRECTION INPUT ;
    USE SIGNAL ;
    PORT
      LAYER M3 ;
        RECT  43.344 0 43.362 0.144 ;
    END
  END s0_x[636]
  PIN s0_x[637]
    DIRECTION INPUT ;
    USE SIGNAL ;
    PORT
      LAYER M5 ;
        RECT  42.528 0 42.552 0.192 ;
    END
  END s0_x[637]
  PIN s0_x[638]
    DIRECTION INPUT ;
    USE SIGNAL ;
    PORT
      LAYER M3 ;
        RECT  43.452 0 43.47 0.144 ;
    END
  END s0_x[638]
  PIN s0_x[639]
    DIRECTION INPUT ;
    USE SIGNAL ;
    PORT
      LAYER M5 ;
        RECT  42.624 0 42.648 0.192 ;
    END
  END s0_x[639]
  PIN s0_x[63]
    DIRECTION INPUT ;
    USE SIGNAL ;
    PORT
      LAYER M5 ;
        RECT  14.976 0 15 0.192 ;
    END
  END s0_x[63]
  PIN s0_x[640]
    DIRECTION INPUT ;
    USE SIGNAL ;
    PORT
      LAYER M3 ;
        RECT  43.56 0 43.578 0.144 ;
    END
  END s0_x[640]
  PIN s0_x[641]
    DIRECTION INPUT ;
    USE SIGNAL ;
    PORT
      LAYER M5 ;
        RECT  42.72 0 42.744 0.192 ;
    END
  END s0_x[641]
  PIN s0_x[642]
    DIRECTION INPUT ;
    USE SIGNAL ;
    PORT
      LAYER M3 ;
        RECT  43.668 0 43.686 0.144 ;
    END
  END s0_x[642]
  PIN s0_x[643]
    DIRECTION INPUT ;
    USE SIGNAL ;
    PORT
      LAYER M5 ;
        RECT  42.816 0 42.84 0.192 ;
    END
  END s0_x[643]
  PIN s0_x[644]
    DIRECTION INPUT ;
    USE SIGNAL ;
    PORT
      LAYER M3 ;
        RECT  43.776 0 43.794 0.144 ;
    END
  END s0_x[644]
  PIN s0_x[645]
    DIRECTION INPUT ;
    USE SIGNAL ;
    PORT
      LAYER M5 ;
        RECT  42.912 0 42.936 0.192 ;
    END
  END s0_x[645]
  PIN s0_x[646]
    DIRECTION INPUT ;
    USE SIGNAL ;
    PORT
      LAYER M3 ;
        RECT  43.884 0 43.902 0.144 ;
    END
  END s0_x[646]
  PIN s0_x[647]
    DIRECTION INPUT ;
    USE SIGNAL ;
    PORT
      LAYER M5 ;
        RECT  43.008 0 43.032 0.192 ;
    END
  END s0_x[647]
  PIN s0_x[648]
    DIRECTION INPUT ;
    USE SIGNAL ;
    PORT
      LAYER M3 ;
        RECT  43.992 0 44.01 0.144 ;
    END
  END s0_x[648]
  PIN s0_x[649]
    DIRECTION INPUT ;
    USE SIGNAL ;
    PORT
      LAYER M5 ;
        RECT  43.104 0 43.128 0.192 ;
    END
  END s0_x[649]
  PIN s0_x[64]
    DIRECTION INPUT ;
    USE SIGNAL ;
    PORT
      LAYER M3 ;
        RECT  12.456 0 12.474 0.144 ;
    END
  END s0_x[64]
  PIN s0_x[650]
    DIRECTION INPUT ;
    USE SIGNAL ;
    PORT
      LAYER M3 ;
        RECT  44.1 0 44.118 0.144 ;
    END
  END s0_x[650]
  PIN s0_x[651]
    DIRECTION INPUT ;
    USE SIGNAL ;
    PORT
      LAYER M5 ;
        RECT  43.2 0 43.224 0.192 ;
    END
  END s0_x[651]
  PIN s0_x[652]
    DIRECTION INPUT ;
    USE SIGNAL ;
    PORT
      LAYER M3 ;
        RECT  44.208 0 44.226 0.144 ;
    END
  END s0_x[652]
  PIN s0_x[653]
    DIRECTION INPUT ;
    USE SIGNAL ;
    PORT
      LAYER M5 ;
        RECT  43.296 0 43.32 0.192 ;
    END
  END s0_x[653]
  PIN s0_x[654]
    DIRECTION INPUT ;
    USE SIGNAL ;
    PORT
      LAYER M3 ;
        RECT  44.316 0 44.334 0.144 ;
    END
  END s0_x[654]
  PIN s0_x[655]
    DIRECTION INPUT ;
    USE SIGNAL ;
    PORT
      LAYER M5 ;
        RECT  43.392 0 43.416 0.192 ;
    END
  END s0_x[655]
  PIN s0_x[656]
    DIRECTION INPUT ;
    USE SIGNAL ;
    PORT
      LAYER M3 ;
        RECT  44.424 0 44.442 0.144 ;
    END
  END s0_x[656]
  PIN s0_x[657]
    DIRECTION INPUT ;
    USE SIGNAL ;
    PORT
      LAYER M5 ;
        RECT  43.488 0 43.512 0.192 ;
    END
  END s0_x[657]
  PIN s0_x[658]
    DIRECTION INPUT ;
    USE SIGNAL ;
    PORT
      LAYER M3 ;
        RECT  44.532 0 44.55 0.144 ;
    END
  END s0_x[658]
  PIN s0_x[659]
    DIRECTION INPUT ;
    USE SIGNAL ;
    PORT
      LAYER M5 ;
        RECT  43.584 0 43.608 0.192 ;
    END
  END s0_x[659]
  PIN s0_x[65]
    DIRECTION INPUT ;
    USE SIGNAL ;
    PORT
      LAYER M5 ;
        RECT  15.072 0 15.096 0.192 ;
    END
  END s0_x[65]
  PIN s0_x[660]
    DIRECTION INPUT ;
    USE SIGNAL ;
    PORT
      LAYER M3 ;
        RECT  44.64 0 44.658 0.144 ;
    END
  END s0_x[660]
  PIN s0_x[661]
    DIRECTION INPUT ;
    USE SIGNAL ;
    PORT
      LAYER M5 ;
        RECT  43.68 0 43.704 0.192 ;
    END
  END s0_x[661]
  PIN s0_x[662]
    DIRECTION INPUT ;
    USE SIGNAL ;
    PORT
      LAYER M3 ;
        RECT  44.748 0 44.766 0.144 ;
    END
  END s0_x[662]
  PIN s0_x[663]
    DIRECTION INPUT ;
    USE SIGNAL ;
    PORT
      LAYER M5 ;
        RECT  43.776 0 43.8 0.192 ;
    END
  END s0_x[663]
  PIN s0_x[664]
    DIRECTION INPUT ;
    USE SIGNAL ;
    PORT
      LAYER M3 ;
        RECT  44.856 0 44.874 0.144 ;
    END
  END s0_x[664]
  PIN s0_x[665]
    DIRECTION INPUT ;
    USE SIGNAL ;
    PORT
      LAYER M5 ;
        RECT  43.872 0 43.896 0.192 ;
    END
  END s0_x[665]
  PIN s0_x[666]
    DIRECTION INPUT ;
    USE SIGNAL ;
    PORT
      LAYER M3 ;
        RECT  44.964 0 44.982 0.144 ;
    END
  END s0_x[666]
  PIN s0_x[667]
    DIRECTION INPUT ;
    USE SIGNAL ;
    PORT
      LAYER M5 ;
        RECT  43.968 0 43.992 0.192 ;
    END
  END s0_x[667]
  PIN s0_x[668]
    DIRECTION INPUT ;
    USE SIGNAL ;
    PORT
      LAYER M3 ;
        RECT  45.072 0 45.09 0.144 ;
    END
  END s0_x[668]
  PIN s0_x[669]
    DIRECTION INPUT ;
    USE SIGNAL ;
    PORT
      LAYER M5 ;
        RECT  44.064 0 44.088 0.192 ;
    END
  END s0_x[669]
  PIN s0_x[66]
    DIRECTION INPUT ;
    USE SIGNAL ;
    PORT
      LAYER M3 ;
        RECT  12.564 0 12.582 0.144 ;
    END
  END s0_x[66]
  PIN s0_x[670]
    DIRECTION INPUT ;
    USE SIGNAL ;
    PORT
      LAYER M3 ;
        RECT  45.18 0 45.198 0.144 ;
    END
  END s0_x[670]
  PIN s0_x[671]
    DIRECTION INPUT ;
    USE SIGNAL ;
    PORT
      LAYER M5 ;
        RECT  44.16 0 44.184 0.192 ;
    END
  END s0_x[671]
  PIN s0_x[672]
    DIRECTION INPUT ;
    USE SIGNAL ;
    PORT
      LAYER M3 ;
        RECT  45.288 0 45.306 0.144 ;
    END
  END s0_x[672]
  PIN s0_x[673]
    DIRECTION INPUT ;
    USE SIGNAL ;
    PORT
      LAYER M5 ;
        RECT  44.256 0 44.28 0.192 ;
    END
  END s0_x[673]
  PIN s0_x[674]
    DIRECTION INPUT ;
    USE SIGNAL ;
    PORT
      LAYER M3 ;
        RECT  45.396 0 45.414 0.144 ;
    END
  END s0_x[674]
  PIN s0_x[675]
    DIRECTION INPUT ;
    USE SIGNAL ;
    PORT
      LAYER M5 ;
        RECT  44.352 0 44.376 0.192 ;
    END
  END s0_x[675]
  PIN s0_x[676]
    DIRECTION INPUT ;
    USE SIGNAL ;
    PORT
      LAYER M3 ;
        RECT  45.504 0 45.522 0.144 ;
    END
  END s0_x[676]
  PIN s0_x[677]
    DIRECTION INPUT ;
    USE SIGNAL ;
    PORT
      LAYER M5 ;
        RECT  44.448 0 44.472 0.192 ;
    END
  END s0_x[677]
  PIN s0_x[678]
    DIRECTION INPUT ;
    USE SIGNAL ;
    PORT
      LAYER M3 ;
        RECT  45.612 0 45.63 0.144 ;
    END
  END s0_x[678]
  PIN s0_x[679]
    DIRECTION INPUT ;
    USE SIGNAL ;
    PORT
      LAYER M5 ;
        RECT  44.544 0 44.568 0.192 ;
    END
  END s0_x[679]
  PIN s0_x[67]
    DIRECTION INPUT ;
    USE SIGNAL ;
    PORT
      LAYER M5 ;
        RECT  15.168 0 15.192 0.192 ;
    END
  END s0_x[67]
  PIN s0_x[680]
    DIRECTION INPUT ;
    USE SIGNAL ;
    PORT
      LAYER M3 ;
        RECT  45.72 0 45.738 0.144 ;
    END
  END s0_x[680]
  PIN s0_x[681]
    DIRECTION INPUT ;
    USE SIGNAL ;
    PORT
      LAYER M5 ;
        RECT  44.64 0 44.664 0.192 ;
    END
  END s0_x[681]
  PIN s0_x[682]
    DIRECTION INPUT ;
    USE SIGNAL ;
    PORT
      LAYER M3 ;
        RECT  45.828 0 45.846 0.144 ;
    END
  END s0_x[682]
  PIN s0_x[683]
    DIRECTION INPUT ;
    USE SIGNAL ;
    PORT
      LAYER M5 ;
        RECT  44.736 0 44.76 0.192 ;
    END
  END s0_x[683]
  PIN s0_x[684]
    DIRECTION INPUT ;
    USE SIGNAL ;
    PORT
      LAYER M3 ;
        RECT  45.936 0 45.954 0.144 ;
    END
  END s0_x[684]
  PIN s0_x[685]
    DIRECTION INPUT ;
    USE SIGNAL ;
    PORT
      LAYER M5 ;
        RECT  44.832 0 44.856 0.192 ;
    END
  END s0_x[685]
  PIN s0_x[686]
    DIRECTION INPUT ;
    USE SIGNAL ;
    PORT
      LAYER M3 ;
        RECT  46.044 0 46.062 0.144 ;
    END
  END s0_x[686]
  PIN s0_x[687]
    DIRECTION INPUT ;
    USE SIGNAL ;
    PORT
      LAYER M5 ;
        RECT  44.928 0 44.952 0.192 ;
    END
  END s0_x[687]
  PIN s0_x[688]
    DIRECTION INPUT ;
    USE SIGNAL ;
    PORT
      LAYER M3 ;
        RECT  46.152 0 46.17 0.144 ;
    END
  END s0_x[688]
  PIN s0_x[689]
    DIRECTION INPUT ;
    USE SIGNAL ;
    PORT
      LAYER M5 ;
        RECT  45.024 0 45.048 0.192 ;
    END
  END s0_x[689]
  PIN s0_x[68]
    DIRECTION INPUT ;
    USE SIGNAL ;
    PORT
      LAYER M3 ;
        RECT  12.672 0 12.69 0.144 ;
    END
  END s0_x[68]
  PIN s0_x[690]
    DIRECTION INPUT ;
    USE SIGNAL ;
    PORT
      LAYER M3 ;
        RECT  46.26 0 46.278 0.144 ;
    END
  END s0_x[690]
  PIN s0_x[691]
    DIRECTION INPUT ;
    USE SIGNAL ;
    PORT
      LAYER M5 ;
        RECT  45.12 0 45.144 0.192 ;
    END
  END s0_x[691]
  PIN s0_x[692]
    DIRECTION INPUT ;
    USE SIGNAL ;
    PORT
      LAYER M3 ;
        RECT  46.368 0 46.386 0.144 ;
    END
  END s0_x[692]
  PIN s0_x[693]
    DIRECTION INPUT ;
    USE SIGNAL ;
    PORT
      LAYER M5 ;
        RECT  45.216 0 45.24 0.192 ;
    END
  END s0_x[693]
  PIN s0_x[694]
    DIRECTION INPUT ;
    USE SIGNAL ;
    PORT
      LAYER M3 ;
        RECT  46.476 0 46.494 0.144 ;
    END
  END s0_x[694]
  PIN s0_x[695]
    DIRECTION INPUT ;
    USE SIGNAL ;
    PORT
      LAYER M5 ;
        RECT  45.312 0 45.336 0.192 ;
    END
  END s0_x[695]
  PIN s0_x[696]
    DIRECTION INPUT ;
    USE SIGNAL ;
    PORT
      LAYER M3 ;
        RECT  46.584 0 46.602 0.144 ;
    END
  END s0_x[696]
  PIN s0_x[697]
    DIRECTION INPUT ;
    USE SIGNAL ;
    PORT
      LAYER M5 ;
        RECT  45.408 0 45.432 0.192 ;
    END
  END s0_x[697]
  PIN s0_x[698]
    DIRECTION INPUT ;
    USE SIGNAL ;
    PORT
      LAYER M3 ;
        RECT  46.692 0 46.71 0.144 ;
    END
  END s0_x[698]
  PIN s0_x[699]
    DIRECTION INPUT ;
    USE SIGNAL ;
    PORT
      LAYER M5 ;
        RECT  45.504 0 45.528 0.192 ;
    END
  END s0_x[699]
  PIN s0_x[69]
    DIRECTION INPUT ;
    USE SIGNAL ;
    PORT
      LAYER M5 ;
        RECT  15.264 0 15.288 0.192 ;
    END
  END s0_x[69]
  PIN s0_x[6]
    DIRECTION INPUT ;
    USE SIGNAL ;
    PORT
      LAYER M3 ;
        RECT  9.324 0 9.342 0.144 ;
    END
  END s0_x[6]
  PIN s0_x[700]
    DIRECTION INPUT ;
    USE SIGNAL ;
    PORT
      LAYER M3 ;
        RECT  46.8 0 46.818 0.144 ;
    END
  END s0_x[700]
  PIN s0_x[701]
    DIRECTION INPUT ;
    USE SIGNAL ;
    PORT
      LAYER M5 ;
        RECT  45.6 0 45.624 0.192 ;
    END
  END s0_x[701]
  PIN s0_x[702]
    DIRECTION INPUT ;
    USE SIGNAL ;
    PORT
      LAYER M3 ;
        RECT  46.908 0 46.926 0.144 ;
    END
  END s0_x[702]
  PIN s0_x[703]
    DIRECTION INPUT ;
    USE SIGNAL ;
    PORT
      LAYER M5 ;
        RECT  45.696 0 45.72 0.192 ;
    END
  END s0_x[703]
  PIN s0_x[704]
    DIRECTION INPUT ;
    USE SIGNAL ;
    PORT
      LAYER M3 ;
        RECT  47.016 0 47.034 0.144 ;
    END
  END s0_x[704]
  PIN s0_x[705]
    DIRECTION INPUT ;
    USE SIGNAL ;
    PORT
      LAYER M5 ;
        RECT  45.792 0 45.816 0.192 ;
    END
  END s0_x[705]
  PIN s0_x[706]
    DIRECTION INPUT ;
    USE SIGNAL ;
    PORT
      LAYER M3 ;
        RECT  47.124 0 47.142 0.144 ;
    END
  END s0_x[706]
  PIN s0_x[707]
    DIRECTION INPUT ;
    USE SIGNAL ;
    PORT
      LAYER M5 ;
        RECT  45.888 0 45.912 0.192 ;
    END
  END s0_x[707]
  PIN s0_x[708]
    DIRECTION INPUT ;
    USE SIGNAL ;
    PORT
      LAYER M3 ;
        RECT  47.232 0 47.25 0.144 ;
    END
  END s0_x[708]
  PIN s0_x[709]
    DIRECTION INPUT ;
    USE SIGNAL ;
    PORT
      LAYER M5 ;
        RECT  45.984 0 46.008 0.192 ;
    END
  END s0_x[709]
  PIN s0_x[70]
    DIRECTION INPUT ;
    USE SIGNAL ;
    PORT
      LAYER M3 ;
        RECT  12.78 0 12.798 0.144 ;
    END
  END s0_x[70]
  PIN s0_x[710]
    DIRECTION INPUT ;
    USE SIGNAL ;
    PORT
      LAYER M3 ;
        RECT  47.34 0 47.358 0.144 ;
    END
  END s0_x[710]
  PIN s0_x[711]
    DIRECTION INPUT ;
    USE SIGNAL ;
    PORT
      LAYER M5 ;
        RECT  46.08 0 46.104 0.192 ;
    END
  END s0_x[711]
  PIN s0_x[712]
    DIRECTION INPUT ;
    USE SIGNAL ;
    PORT
      LAYER M3 ;
        RECT  47.448 0 47.466 0.144 ;
    END
  END s0_x[712]
  PIN s0_x[713]
    DIRECTION INPUT ;
    USE SIGNAL ;
    PORT
      LAYER M5 ;
        RECT  46.176 0 46.2 0.192 ;
    END
  END s0_x[713]
  PIN s0_x[714]
    DIRECTION INPUT ;
    USE SIGNAL ;
    PORT
      LAYER M3 ;
        RECT  47.556 0 47.574 0.144 ;
    END
  END s0_x[714]
  PIN s0_x[715]
    DIRECTION INPUT ;
    USE SIGNAL ;
    PORT
      LAYER M5 ;
        RECT  46.272 0 46.296 0.192 ;
    END
  END s0_x[715]
  PIN s0_x[716]
    DIRECTION INPUT ;
    USE SIGNAL ;
    PORT
      LAYER M3 ;
        RECT  47.664 0 47.682 0.144 ;
    END
  END s0_x[716]
  PIN s0_x[717]
    DIRECTION INPUT ;
    USE SIGNAL ;
    PORT
      LAYER M5 ;
        RECT  46.368 0 46.392 0.192 ;
    END
  END s0_x[717]
  PIN s0_x[718]
    DIRECTION INPUT ;
    USE SIGNAL ;
    PORT
      LAYER M3 ;
        RECT  47.772 0 47.79 0.144 ;
    END
  END s0_x[718]
  PIN s0_x[719]
    DIRECTION INPUT ;
    USE SIGNAL ;
    PORT
      LAYER M5 ;
        RECT  46.464 0 46.488 0.192 ;
    END
  END s0_x[719]
  PIN s0_x[71]
    DIRECTION INPUT ;
    USE SIGNAL ;
    PORT
      LAYER M5 ;
        RECT  15.36 0 15.384 0.192 ;
    END
  END s0_x[71]
  PIN s0_x[720]
    DIRECTION INPUT ;
    USE SIGNAL ;
    PORT
      LAYER M3 ;
        RECT  47.88 0 47.898 0.144 ;
    END
  END s0_x[720]
  PIN s0_x[721]
    DIRECTION INPUT ;
    USE SIGNAL ;
    PORT
      LAYER M5 ;
        RECT  46.56 0 46.584 0.192 ;
    END
  END s0_x[721]
  PIN s0_x[722]
    DIRECTION INPUT ;
    USE SIGNAL ;
    PORT
      LAYER M3 ;
        RECT  47.988 0 48.006 0.144 ;
    END
  END s0_x[722]
  PIN s0_x[723]
    DIRECTION INPUT ;
    USE SIGNAL ;
    PORT
      LAYER M5 ;
        RECT  46.656 0 46.68 0.192 ;
    END
  END s0_x[723]
  PIN s0_x[724]
    DIRECTION INPUT ;
    USE SIGNAL ;
    PORT
      LAYER M3 ;
        RECT  48.096 0 48.114 0.144 ;
    END
  END s0_x[724]
  PIN s0_x[725]
    DIRECTION INPUT ;
    USE SIGNAL ;
    PORT
      LAYER M5 ;
        RECT  46.752 0 46.776 0.192 ;
    END
  END s0_x[725]
  PIN s0_x[726]
    DIRECTION INPUT ;
    USE SIGNAL ;
    PORT
      LAYER M3 ;
        RECT  48.204 0 48.222 0.144 ;
    END
  END s0_x[726]
  PIN s0_x[727]
    DIRECTION INPUT ;
    USE SIGNAL ;
    PORT
      LAYER M5 ;
        RECT  46.848 0 46.872 0.192 ;
    END
  END s0_x[727]
  PIN s0_x[728]
    DIRECTION INPUT ;
    USE SIGNAL ;
    PORT
      LAYER M3 ;
        RECT  48.312 0 48.33 0.144 ;
    END
  END s0_x[728]
  PIN s0_x[729]
    DIRECTION INPUT ;
    USE SIGNAL ;
    PORT
      LAYER M5 ;
        RECT  46.944 0 46.968 0.192 ;
    END
  END s0_x[729]
  PIN s0_x[72]
    DIRECTION INPUT ;
    USE SIGNAL ;
    PORT
      LAYER M3 ;
        RECT  12.888 0 12.906 0.144 ;
    END
  END s0_x[72]
  PIN s0_x[730]
    DIRECTION INPUT ;
    USE SIGNAL ;
    PORT
      LAYER M3 ;
        RECT  48.42 0 48.438 0.144 ;
    END
  END s0_x[730]
  PIN s0_x[731]
    DIRECTION INPUT ;
    USE SIGNAL ;
    PORT
      LAYER M5 ;
        RECT  47.04 0 47.064 0.192 ;
    END
  END s0_x[731]
  PIN s0_x[732]
    DIRECTION INPUT ;
    USE SIGNAL ;
    PORT
      LAYER M3 ;
        RECT  48.528 0 48.546 0.144 ;
    END
  END s0_x[732]
  PIN s0_x[733]
    DIRECTION INPUT ;
    USE SIGNAL ;
    PORT
      LAYER M5 ;
        RECT  47.136 0 47.16 0.192 ;
    END
  END s0_x[733]
  PIN s0_x[734]
    DIRECTION INPUT ;
    USE SIGNAL ;
    PORT
      LAYER M3 ;
        RECT  48.636 0 48.654 0.144 ;
    END
  END s0_x[734]
  PIN s0_x[735]
    DIRECTION INPUT ;
    USE SIGNAL ;
    PORT
      LAYER M5 ;
        RECT  47.232 0 47.256 0.192 ;
    END
  END s0_x[735]
  PIN s0_x[736]
    DIRECTION INPUT ;
    USE SIGNAL ;
    PORT
      LAYER M3 ;
        RECT  48.744 0 48.762 0.144 ;
    END
  END s0_x[736]
  PIN s0_x[737]
    DIRECTION INPUT ;
    USE SIGNAL ;
    PORT
      LAYER M5 ;
        RECT  47.328 0 47.352 0.192 ;
    END
  END s0_x[737]
  PIN s0_x[738]
    DIRECTION INPUT ;
    USE SIGNAL ;
    PORT
      LAYER M3 ;
        RECT  48.852 0 48.87 0.144 ;
    END
  END s0_x[738]
  PIN s0_x[739]
    DIRECTION INPUT ;
    USE SIGNAL ;
    PORT
      LAYER M5 ;
        RECT  47.424 0 47.448 0.192 ;
    END
  END s0_x[739]
  PIN s0_x[73]
    DIRECTION INPUT ;
    USE SIGNAL ;
    PORT
      LAYER M5 ;
        RECT  15.456 0 15.48 0.192 ;
    END
  END s0_x[73]
  PIN s0_x[740]
    DIRECTION INPUT ;
    USE SIGNAL ;
    PORT
      LAYER M3 ;
        RECT  48.96 0 48.978 0.144 ;
    END
  END s0_x[740]
  PIN s0_x[741]
    DIRECTION INPUT ;
    USE SIGNAL ;
    PORT
      LAYER M5 ;
        RECT  47.52 0 47.544 0.192 ;
    END
  END s0_x[741]
  PIN s0_x[742]
    DIRECTION INPUT ;
    USE SIGNAL ;
    PORT
      LAYER M3 ;
        RECT  49.068 0 49.086 0.144 ;
    END
  END s0_x[742]
  PIN s0_x[743]
    DIRECTION INPUT ;
    USE SIGNAL ;
    PORT
      LAYER M5 ;
        RECT  47.616 0 47.64 0.192 ;
    END
  END s0_x[743]
  PIN s0_x[744]
    DIRECTION INPUT ;
    USE SIGNAL ;
    PORT
      LAYER M3 ;
        RECT  49.176 0 49.194 0.144 ;
    END
  END s0_x[744]
  PIN s0_x[745]
    DIRECTION INPUT ;
    USE SIGNAL ;
    PORT
      LAYER M5 ;
        RECT  47.712 0 47.736 0.192 ;
    END
  END s0_x[745]
  PIN s0_x[746]
    DIRECTION INPUT ;
    USE SIGNAL ;
    PORT
      LAYER M3 ;
        RECT  49.284 0 49.302 0.144 ;
    END
  END s0_x[746]
  PIN s0_x[747]
    DIRECTION INPUT ;
    USE SIGNAL ;
    PORT
      LAYER M5 ;
        RECT  47.808 0 47.832 0.192 ;
    END
  END s0_x[747]
  PIN s0_x[748]
    DIRECTION INPUT ;
    USE SIGNAL ;
    PORT
      LAYER M3 ;
        RECT  49.392 0 49.41 0.144 ;
    END
  END s0_x[748]
  PIN s0_x[749]
    DIRECTION INPUT ;
    USE SIGNAL ;
    PORT
      LAYER M5 ;
        RECT  47.904 0 47.928 0.192 ;
    END
  END s0_x[749]
  PIN s0_x[74]
    DIRECTION INPUT ;
    USE SIGNAL ;
    PORT
      LAYER M3 ;
        RECT  12.996 0 13.014 0.144 ;
    END
  END s0_x[74]
  PIN s0_x[750]
    DIRECTION INPUT ;
    USE SIGNAL ;
    PORT
      LAYER M3 ;
        RECT  49.5 0 49.518 0.144 ;
    END
  END s0_x[750]
  PIN s0_x[751]
    DIRECTION INPUT ;
    USE SIGNAL ;
    PORT
      LAYER M5 ;
        RECT  48 0 48.024 0.192 ;
    END
  END s0_x[751]
  PIN s0_x[752]
    DIRECTION INPUT ;
    USE SIGNAL ;
    PORT
      LAYER M3 ;
        RECT  49.608 0 49.626 0.144 ;
    END
  END s0_x[752]
  PIN s0_x[753]
    DIRECTION INPUT ;
    USE SIGNAL ;
    PORT
      LAYER M5 ;
        RECT  48.096 0 48.12 0.192 ;
    END
  END s0_x[753]
  PIN s0_x[754]
    DIRECTION INPUT ;
    USE SIGNAL ;
    PORT
      LAYER M3 ;
        RECT  49.716 0 49.734 0.144 ;
    END
  END s0_x[754]
  PIN s0_x[755]
    DIRECTION INPUT ;
    USE SIGNAL ;
    PORT
      LAYER M5 ;
        RECT  48.192 0 48.216 0.192 ;
    END
  END s0_x[755]
  PIN s0_x[756]
    DIRECTION INPUT ;
    USE SIGNAL ;
    PORT
      LAYER M3 ;
        RECT  49.824 0 49.842 0.144 ;
    END
  END s0_x[756]
  PIN s0_x[757]
    DIRECTION INPUT ;
    USE SIGNAL ;
    PORT
      LAYER M5 ;
        RECT  48.288 0 48.312 0.192 ;
    END
  END s0_x[757]
  PIN s0_x[758]
    DIRECTION INPUT ;
    USE SIGNAL ;
    PORT
      LAYER M3 ;
        RECT  49.932 0 49.95 0.144 ;
    END
  END s0_x[758]
  PIN s0_x[759]
    DIRECTION INPUT ;
    USE SIGNAL ;
    PORT
      LAYER M5 ;
        RECT  48.384 0 48.408 0.192 ;
    END
  END s0_x[759]
  PIN s0_x[75]
    DIRECTION INPUT ;
    USE SIGNAL ;
    PORT
      LAYER M5 ;
        RECT  15.552 0 15.576 0.192 ;
    END
  END s0_x[75]
  PIN s0_x[760]
    DIRECTION INPUT ;
    USE SIGNAL ;
    PORT
      LAYER M3 ;
        RECT  50.04 0 50.058 0.144 ;
    END
  END s0_x[760]
  PIN s0_x[761]
    DIRECTION INPUT ;
    USE SIGNAL ;
    PORT
      LAYER M5 ;
        RECT  48.48 0 48.504 0.192 ;
    END
  END s0_x[761]
  PIN s0_x[762]
    DIRECTION INPUT ;
    USE SIGNAL ;
    PORT
      LAYER M3 ;
        RECT  50.148 0 50.166 0.144 ;
    END
  END s0_x[762]
  PIN s0_x[763]
    DIRECTION INPUT ;
    USE SIGNAL ;
    PORT
      LAYER M5 ;
        RECT  48.576 0 48.6 0.192 ;
    END
  END s0_x[763]
  PIN s0_x[764]
    DIRECTION INPUT ;
    USE SIGNAL ;
    PORT
      LAYER M3 ;
        RECT  50.256 0 50.274 0.144 ;
    END
  END s0_x[764]
  PIN s0_x[765]
    DIRECTION INPUT ;
    USE SIGNAL ;
    PORT
      LAYER M5 ;
        RECT  48.672 0 48.696 0.192 ;
    END
  END s0_x[765]
  PIN s0_x[766]
    DIRECTION INPUT ;
    USE SIGNAL ;
    PORT
      LAYER M3 ;
        RECT  50.364 0 50.382 0.144 ;
    END
  END s0_x[766]
  PIN s0_x[767]
    DIRECTION INPUT ;
    USE SIGNAL ;
    PORT
      LAYER M5 ;
        RECT  48.768 0 48.792 0.192 ;
    END
  END s0_x[767]
  PIN s0_x[768]
    DIRECTION INPUT ;
    USE SIGNAL ;
    PORT
      LAYER M3 ;
        RECT  50.472 0 50.49 0.144 ;
    END
  END s0_x[768]
  PIN s0_x[769]
    DIRECTION INPUT ;
    USE SIGNAL ;
    PORT
      LAYER M5 ;
        RECT  48.864 0 48.888 0.192 ;
    END
  END s0_x[769]
  PIN s0_x[76]
    DIRECTION INPUT ;
    USE SIGNAL ;
    PORT
      LAYER M3 ;
        RECT  13.104 0 13.122 0.144 ;
    END
  END s0_x[76]
  PIN s0_x[770]
    DIRECTION INPUT ;
    USE SIGNAL ;
    PORT
      LAYER M3 ;
        RECT  50.58 0 50.598 0.144 ;
    END
  END s0_x[770]
  PIN s0_x[771]
    DIRECTION INPUT ;
    USE SIGNAL ;
    PORT
      LAYER M5 ;
        RECT  48.96 0 48.984 0.192 ;
    END
  END s0_x[771]
  PIN s0_x[772]
    DIRECTION INPUT ;
    USE SIGNAL ;
    PORT
      LAYER M3 ;
        RECT  50.688 0 50.706 0.144 ;
    END
  END s0_x[772]
  PIN s0_x[773]
    DIRECTION INPUT ;
    USE SIGNAL ;
    PORT
      LAYER M5 ;
        RECT  49.056 0 49.08 0.192 ;
    END
  END s0_x[773]
  PIN s0_x[774]
    DIRECTION INPUT ;
    USE SIGNAL ;
    PORT
      LAYER M3 ;
        RECT  50.796 0 50.814 0.144 ;
    END
  END s0_x[774]
  PIN s0_x[775]
    DIRECTION INPUT ;
    USE SIGNAL ;
    PORT
      LAYER M5 ;
        RECT  49.152 0 49.176 0.192 ;
    END
  END s0_x[775]
  PIN s0_x[776]
    DIRECTION INPUT ;
    USE SIGNAL ;
    PORT
      LAYER M3 ;
        RECT  50.904 0 50.922 0.144 ;
    END
  END s0_x[776]
  PIN s0_x[777]
    DIRECTION INPUT ;
    USE SIGNAL ;
    PORT
      LAYER M5 ;
        RECT  49.248 0 49.272 0.192 ;
    END
  END s0_x[777]
  PIN s0_x[778]
    DIRECTION INPUT ;
    USE SIGNAL ;
    PORT
      LAYER M3 ;
        RECT  51.012 0 51.03 0.144 ;
    END
  END s0_x[778]
  PIN s0_x[779]
    DIRECTION INPUT ;
    USE SIGNAL ;
    PORT
      LAYER M5 ;
        RECT  49.344 0 49.368 0.192 ;
    END
  END s0_x[779]
  PIN s0_x[77]
    DIRECTION INPUT ;
    USE SIGNAL ;
    PORT
      LAYER M5 ;
        RECT  15.648 0 15.672 0.192 ;
    END
  END s0_x[77]
  PIN s0_x[780]
    DIRECTION INPUT ;
    USE SIGNAL ;
    PORT
      LAYER M3 ;
        RECT  51.12 0 51.138 0.144 ;
    END
  END s0_x[780]
  PIN s0_x[781]
    DIRECTION INPUT ;
    USE SIGNAL ;
    PORT
      LAYER M5 ;
        RECT  49.44 0 49.464 0.192 ;
    END
  END s0_x[781]
  PIN s0_x[782]
    DIRECTION INPUT ;
    USE SIGNAL ;
    PORT
      LAYER M3 ;
        RECT  51.228 0 51.246 0.144 ;
    END
  END s0_x[782]
  PIN s0_x[783]
    DIRECTION INPUT ;
    USE SIGNAL ;
    PORT
      LAYER M5 ;
        RECT  49.536 0 49.56 0.192 ;
    END
  END s0_x[783]
  PIN s0_x[784]
    DIRECTION INPUT ;
    USE SIGNAL ;
    PORT
      LAYER M3 ;
        RECT  51.336 0 51.354 0.144 ;
    END
  END s0_x[784]
  PIN s0_x[785]
    DIRECTION INPUT ;
    USE SIGNAL ;
    PORT
      LAYER M5 ;
        RECT  49.632 0 49.656 0.192 ;
    END
  END s0_x[785]
  PIN s0_x[786]
    DIRECTION INPUT ;
    USE SIGNAL ;
    PORT
      LAYER M3 ;
        RECT  51.444 0 51.462 0.144 ;
    END
  END s0_x[786]
  PIN s0_x[787]
    DIRECTION INPUT ;
    USE SIGNAL ;
    PORT
      LAYER M5 ;
        RECT  49.728 0 49.752 0.192 ;
    END
  END s0_x[787]
  PIN s0_x[788]
    DIRECTION INPUT ;
    USE SIGNAL ;
    PORT
      LAYER M3 ;
        RECT  51.552 0 51.57 0.144 ;
    END
  END s0_x[788]
  PIN s0_x[789]
    DIRECTION INPUT ;
    USE SIGNAL ;
    PORT
      LAYER M5 ;
        RECT  49.824 0 49.848 0.192 ;
    END
  END s0_x[789]
  PIN s0_x[78]
    DIRECTION INPUT ;
    USE SIGNAL ;
    PORT
      LAYER M3 ;
        RECT  13.212 0 13.23 0.144 ;
    END
  END s0_x[78]
  PIN s0_x[790]
    DIRECTION INPUT ;
    USE SIGNAL ;
    PORT
      LAYER M3 ;
        RECT  51.66 0 51.678 0.144 ;
    END
  END s0_x[790]
  PIN s0_x[791]
    DIRECTION INPUT ;
    USE SIGNAL ;
    PORT
      LAYER M5 ;
        RECT  49.92 0 49.944 0.192 ;
    END
  END s0_x[791]
  PIN s0_x[792]
    DIRECTION INPUT ;
    USE SIGNAL ;
    PORT
      LAYER M3 ;
        RECT  51.768 0 51.786 0.144 ;
    END
  END s0_x[792]
  PIN s0_x[793]
    DIRECTION INPUT ;
    USE SIGNAL ;
    PORT
      LAYER M5 ;
        RECT  50.016 0 50.04 0.192 ;
    END
  END s0_x[793]
  PIN s0_x[794]
    DIRECTION INPUT ;
    USE SIGNAL ;
    PORT
      LAYER M3 ;
        RECT  51.876 0 51.894 0.144 ;
    END
  END s0_x[794]
  PIN s0_x[795]
    DIRECTION INPUT ;
    USE SIGNAL ;
    PORT
      LAYER M5 ;
        RECT  50.112 0 50.136 0.192 ;
    END
  END s0_x[795]
  PIN s0_x[796]
    DIRECTION INPUT ;
    USE SIGNAL ;
    PORT
      LAYER M3 ;
        RECT  51.984 0 52.002 0.144 ;
    END
  END s0_x[796]
  PIN s0_x[797]
    DIRECTION INPUT ;
    USE SIGNAL ;
    PORT
      LAYER M5 ;
        RECT  50.208 0 50.232 0.192 ;
    END
  END s0_x[797]
  PIN s0_x[798]
    DIRECTION INPUT ;
    USE SIGNAL ;
    PORT
      LAYER M3 ;
        RECT  52.092 0 52.11 0.144 ;
    END
  END s0_x[798]
  PIN s0_x[799]
    DIRECTION INPUT ;
    USE SIGNAL ;
    PORT
      LAYER M5 ;
        RECT  50.304 0 50.328 0.192 ;
    END
  END s0_x[799]
  PIN s0_x[79]
    DIRECTION INPUT ;
    USE SIGNAL ;
    PORT
      LAYER M5 ;
        RECT  15.744 0 15.768 0.192 ;
    END
  END s0_x[79]
  PIN s0_x[7]
    DIRECTION INPUT ;
    USE SIGNAL ;
    PORT
      LAYER M5 ;
        RECT  12.288 0 12.312 0.192 ;
    END
  END s0_x[7]
  PIN s0_x[800]
    DIRECTION INPUT ;
    USE SIGNAL ;
    PORT
      LAYER M3 ;
        RECT  52.2 0 52.218 0.144 ;
    END
  END s0_x[800]
  PIN s0_x[801]
    DIRECTION INPUT ;
    USE SIGNAL ;
    PORT
      LAYER M5 ;
        RECT  50.4 0 50.424 0.192 ;
    END
  END s0_x[801]
  PIN s0_x[802]
    DIRECTION INPUT ;
    USE SIGNAL ;
    PORT
      LAYER M3 ;
        RECT  52.308 0 52.326 0.144 ;
    END
  END s0_x[802]
  PIN s0_x[803]
    DIRECTION INPUT ;
    USE SIGNAL ;
    PORT
      LAYER M5 ;
        RECT  50.496 0 50.52 0.192 ;
    END
  END s0_x[803]
  PIN s0_x[804]
    DIRECTION INPUT ;
    USE SIGNAL ;
    PORT
      LAYER M3 ;
        RECT  52.416 0 52.434 0.144 ;
    END
  END s0_x[804]
  PIN s0_x[805]
    DIRECTION INPUT ;
    USE SIGNAL ;
    PORT
      LAYER M5 ;
        RECT  50.592 0 50.616 0.192 ;
    END
  END s0_x[805]
  PIN s0_x[806]
    DIRECTION INPUT ;
    USE SIGNAL ;
    PORT
      LAYER M3 ;
        RECT  52.524 0 52.542 0.144 ;
    END
  END s0_x[806]
  PIN s0_x[807]
    DIRECTION INPUT ;
    USE SIGNAL ;
    PORT
      LAYER M5 ;
        RECT  50.688 0 50.712 0.192 ;
    END
  END s0_x[807]
  PIN s0_x[808]
    DIRECTION INPUT ;
    USE SIGNAL ;
    PORT
      LAYER M3 ;
        RECT  52.632 0 52.65 0.144 ;
    END
  END s0_x[808]
  PIN s0_x[809]
    DIRECTION INPUT ;
    USE SIGNAL ;
    PORT
      LAYER M5 ;
        RECT  50.784 0 50.808 0.192 ;
    END
  END s0_x[809]
  PIN s0_x[80]
    DIRECTION INPUT ;
    USE SIGNAL ;
    PORT
      LAYER M3 ;
        RECT  13.32 0 13.338 0.144 ;
    END
  END s0_x[80]
  PIN s0_x[810]
    DIRECTION INPUT ;
    USE SIGNAL ;
    PORT
      LAYER M3 ;
        RECT  52.74 0 52.758 0.144 ;
    END
  END s0_x[810]
  PIN s0_x[811]
    DIRECTION INPUT ;
    USE SIGNAL ;
    PORT
      LAYER M5 ;
        RECT  50.88 0 50.904 0.192 ;
    END
  END s0_x[811]
  PIN s0_x[812]
    DIRECTION INPUT ;
    USE SIGNAL ;
    PORT
      LAYER M3 ;
        RECT  52.848 0 52.866 0.144 ;
    END
  END s0_x[812]
  PIN s0_x[813]
    DIRECTION INPUT ;
    USE SIGNAL ;
    PORT
      LAYER M5 ;
        RECT  50.976 0 51 0.192 ;
    END
  END s0_x[813]
  PIN s0_x[814]
    DIRECTION INPUT ;
    USE SIGNAL ;
    PORT
      LAYER M3 ;
        RECT  52.956 0 52.974 0.144 ;
    END
  END s0_x[814]
  PIN s0_x[815]
    DIRECTION INPUT ;
    USE SIGNAL ;
    PORT
      LAYER M5 ;
        RECT  51.072 0 51.096 0.192 ;
    END
  END s0_x[815]
  PIN s0_x[816]
    DIRECTION INPUT ;
    USE SIGNAL ;
    PORT
      LAYER M3 ;
        RECT  53.064 0 53.082 0.144 ;
    END
  END s0_x[816]
  PIN s0_x[817]
    DIRECTION INPUT ;
    USE SIGNAL ;
    PORT
      LAYER M5 ;
        RECT  51.168 0 51.192 0.192 ;
    END
  END s0_x[817]
  PIN s0_x[818]
    DIRECTION INPUT ;
    USE SIGNAL ;
    PORT
      LAYER M3 ;
        RECT  53.172 0 53.19 0.144 ;
    END
  END s0_x[818]
  PIN s0_x[819]
    DIRECTION INPUT ;
    USE SIGNAL ;
    PORT
      LAYER M5 ;
        RECT  51.264 0 51.288 0.192 ;
    END
  END s0_x[819]
  PIN s0_x[81]
    DIRECTION INPUT ;
    USE SIGNAL ;
    PORT
      LAYER M5 ;
        RECT  15.84 0 15.864 0.192 ;
    END
  END s0_x[81]
  PIN s0_x[820]
    DIRECTION INPUT ;
    USE SIGNAL ;
    PORT
      LAYER M3 ;
        RECT  53.28 0 53.298 0.144 ;
    END
  END s0_x[820]
  PIN s0_x[821]
    DIRECTION INPUT ;
    USE SIGNAL ;
    PORT
      LAYER M5 ;
        RECT  51.36 0 51.384 0.192 ;
    END
  END s0_x[821]
  PIN s0_x[822]
    DIRECTION INPUT ;
    USE SIGNAL ;
    PORT
      LAYER M3 ;
        RECT  53.388 0 53.406 0.144 ;
    END
  END s0_x[822]
  PIN s0_x[823]
    DIRECTION INPUT ;
    USE SIGNAL ;
    PORT
      LAYER M5 ;
        RECT  51.456 0 51.48 0.192 ;
    END
  END s0_x[823]
  PIN s0_x[824]
    DIRECTION INPUT ;
    USE SIGNAL ;
    PORT
      LAYER M3 ;
        RECT  53.496 0 53.514 0.144 ;
    END
  END s0_x[824]
  PIN s0_x[825]
    DIRECTION INPUT ;
    USE SIGNAL ;
    PORT
      LAYER M5 ;
        RECT  51.552 0 51.576 0.192 ;
    END
  END s0_x[825]
  PIN s0_x[826]
    DIRECTION INPUT ;
    USE SIGNAL ;
    PORT
      LAYER M3 ;
        RECT  53.604 0 53.622 0.144 ;
    END
  END s0_x[826]
  PIN s0_x[827]
    DIRECTION INPUT ;
    USE SIGNAL ;
    PORT
      LAYER M5 ;
        RECT  51.648 0 51.672 0.192 ;
    END
  END s0_x[827]
  PIN s0_x[828]
    DIRECTION INPUT ;
    USE SIGNAL ;
    PORT
      LAYER M3 ;
        RECT  53.712 0 53.73 0.144 ;
    END
  END s0_x[828]
  PIN s0_x[829]
    DIRECTION INPUT ;
    USE SIGNAL ;
    PORT
      LAYER M5 ;
        RECT  51.744 0 51.768 0.192 ;
    END
  END s0_x[829]
  PIN s0_x[82]
    DIRECTION INPUT ;
    USE SIGNAL ;
    PORT
      LAYER M3 ;
        RECT  13.428 0 13.446 0.144 ;
    END
  END s0_x[82]
  PIN s0_x[830]
    DIRECTION INPUT ;
    USE SIGNAL ;
    PORT
      LAYER M3 ;
        RECT  53.82 0 53.838 0.144 ;
    END
  END s0_x[830]
  PIN s0_x[831]
    DIRECTION INPUT ;
    USE SIGNAL ;
    PORT
      LAYER M5 ;
        RECT  51.84 0 51.864 0.192 ;
    END
  END s0_x[831]
  PIN s0_x[832]
    DIRECTION INPUT ;
    USE SIGNAL ;
    PORT
      LAYER M3 ;
        RECT  53.928 0 53.946 0.144 ;
    END
  END s0_x[832]
  PIN s0_x[833]
    DIRECTION INPUT ;
    USE SIGNAL ;
    PORT
      LAYER M5 ;
        RECT  51.936 0 51.96 0.192 ;
    END
  END s0_x[833]
  PIN s0_x[834]
    DIRECTION INPUT ;
    USE SIGNAL ;
    PORT
      LAYER M3 ;
        RECT  54.036 0 54.054 0.144 ;
    END
  END s0_x[834]
  PIN s0_x[835]
    DIRECTION INPUT ;
    USE SIGNAL ;
    PORT
      LAYER M5 ;
        RECT  52.032 0 52.056 0.192 ;
    END
  END s0_x[835]
  PIN s0_x[836]
    DIRECTION INPUT ;
    USE SIGNAL ;
    PORT
      LAYER M3 ;
        RECT  54.144 0 54.162 0.144 ;
    END
  END s0_x[836]
  PIN s0_x[837]
    DIRECTION INPUT ;
    USE SIGNAL ;
    PORT
      LAYER M5 ;
        RECT  52.128 0 52.152 0.192 ;
    END
  END s0_x[837]
  PIN s0_x[838]
    DIRECTION INPUT ;
    USE SIGNAL ;
    PORT
      LAYER M3 ;
        RECT  54.252 0 54.27 0.144 ;
    END
  END s0_x[838]
  PIN s0_x[839]
    DIRECTION INPUT ;
    USE SIGNAL ;
    PORT
      LAYER M5 ;
        RECT  52.224 0 52.248 0.192 ;
    END
  END s0_x[839]
  PIN s0_x[83]
    DIRECTION INPUT ;
    USE SIGNAL ;
    PORT
      LAYER M5 ;
        RECT  15.936 0 15.96 0.192 ;
    END
  END s0_x[83]
  PIN s0_x[840]
    DIRECTION INPUT ;
    USE SIGNAL ;
    PORT
      LAYER M3 ;
        RECT  54.36 0 54.378 0.144 ;
    END
  END s0_x[840]
  PIN s0_x[841]
    DIRECTION INPUT ;
    USE SIGNAL ;
    PORT
      LAYER M5 ;
        RECT  52.32 0 52.344 0.192 ;
    END
  END s0_x[841]
  PIN s0_x[842]
    DIRECTION INPUT ;
    USE SIGNAL ;
    PORT
      LAYER M3 ;
        RECT  54.468 0 54.486 0.144 ;
    END
  END s0_x[842]
  PIN s0_x[843]
    DIRECTION INPUT ;
    USE SIGNAL ;
    PORT
      LAYER M5 ;
        RECT  52.416 0 52.44 0.192 ;
    END
  END s0_x[843]
  PIN s0_x[844]
    DIRECTION INPUT ;
    USE SIGNAL ;
    PORT
      LAYER M3 ;
        RECT  54.576 0 54.594 0.144 ;
    END
  END s0_x[844]
  PIN s0_x[845]
    DIRECTION INPUT ;
    USE SIGNAL ;
    PORT
      LAYER M5 ;
        RECT  52.512 0 52.536 0.192 ;
    END
  END s0_x[845]
  PIN s0_x[846]
    DIRECTION INPUT ;
    USE SIGNAL ;
    PORT
      LAYER M3 ;
        RECT  54.684 0 54.702 0.144 ;
    END
  END s0_x[846]
  PIN s0_x[847]
    DIRECTION INPUT ;
    USE SIGNAL ;
    PORT
      LAYER M5 ;
        RECT  52.608 0 52.632 0.192 ;
    END
  END s0_x[847]
  PIN s0_x[848]
    DIRECTION INPUT ;
    USE SIGNAL ;
    PORT
      LAYER M3 ;
        RECT  54.792 0 54.81 0.144 ;
    END
  END s0_x[848]
  PIN s0_x[849]
    DIRECTION INPUT ;
    USE SIGNAL ;
    PORT
      LAYER M5 ;
        RECT  52.704 0 52.728 0.192 ;
    END
  END s0_x[849]
  PIN s0_x[84]
    DIRECTION INPUT ;
    USE SIGNAL ;
    PORT
      LAYER M3 ;
        RECT  13.536 0 13.554 0.144 ;
    END
  END s0_x[84]
  PIN s0_x[850]
    DIRECTION INPUT ;
    USE SIGNAL ;
    PORT
      LAYER M3 ;
        RECT  54.9 0 54.918 0.144 ;
    END
  END s0_x[850]
  PIN s0_x[851]
    DIRECTION INPUT ;
    USE SIGNAL ;
    PORT
      LAYER M5 ;
        RECT  52.8 0 52.824 0.192 ;
    END
  END s0_x[851]
  PIN s0_x[852]
    DIRECTION INPUT ;
    USE SIGNAL ;
    PORT
      LAYER M3 ;
        RECT  55.008 0 55.026 0.144 ;
    END
  END s0_x[852]
  PIN s0_x[853]
    DIRECTION INPUT ;
    USE SIGNAL ;
    PORT
      LAYER M5 ;
        RECT  52.896 0 52.92 0.192 ;
    END
  END s0_x[853]
  PIN s0_x[854]
    DIRECTION INPUT ;
    USE SIGNAL ;
    PORT
      LAYER M3 ;
        RECT  55.116 0 55.134 0.144 ;
    END
  END s0_x[854]
  PIN s0_x[855]
    DIRECTION INPUT ;
    USE SIGNAL ;
    PORT
      LAYER M5 ;
        RECT  52.992 0 53.016 0.192 ;
    END
  END s0_x[855]
  PIN s0_x[856]
    DIRECTION INPUT ;
    USE SIGNAL ;
    PORT
      LAYER M3 ;
        RECT  55.224 0 55.242 0.144 ;
    END
  END s0_x[856]
  PIN s0_x[857]
    DIRECTION INPUT ;
    USE SIGNAL ;
    PORT
      LAYER M5 ;
        RECT  53.088 0 53.112 0.192 ;
    END
  END s0_x[857]
  PIN s0_x[858]
    DIRECTION INPUT ;
    USE SIGNAL ;
    PORT
      LAYER M3 ;
        RECT  55.332 0 55.35 0.144 ;
    END
  END s0_x[858]
  PIN s0_x[859]
    DIRECTION INPUT ;
    USE SIGNAL ;
    PORT
      LAYER M5 ;
        RECT  53.184 0 53.208 0.192 ;
    END
  END s0_x[859]
  PIN s0_x[85]
    DIRECTION INPUT ;
    USE SIGNAL ;
    PORT
      LAYER M5 ;
        RECT  16.032 0 16.056 0.192 ;
    END
  END s0_x[85]
  PIN s0_x[860]
    DIRECTION INPUT ;
    USE SIGNAL ;
    PORT
      LAYER M3 ;
        RECT  55.44 0 55.458 0.144 ;
    END
  END s0_x[860]
  PIN s0_x[861]
    DIRECTION INPUT ;
    USE SIGNAL ;
    PORT
      LAYER M5 ;
        RECT  53.28 0 53.304 0.192 ;
    END
  END s0_x[861]
  PIN s0_x[862]
    DIRECTION INPUT ;
    USE SIGNAL ;
    PORT
      LAYER M3 ;
        RECT  55.548 0 55.566 0.144 ;
    END
  END s0_x[862]
  PIN s0_x[863]
    DIRECTION INPUT ;
    USE SIGNAL ;
    PORT
      LAYER M5 ;
        RECT  53.376 0 53.4 0.192 ;
    END
  END s0_x[863]
  PIN s0_x[864]
    DIRECTION INPUT ;
    USE SIGNAL ;
    PORT
      LAYER M3 ;
        RECT  55.656 0 55.674 0.144 ;
    END
  END s0_x[864]
  PIN s0_x[865]
    DIRECTION INPUT ;
    USE SIGNAL ;
    PORT
      LAYER M5 ;
        RECT  53.472 0 53.496 0.192 ;
    END
  END s0_x[865]
  PIN s0_x[866]
    DIRECTION INPUT ;
    USE SIGNAL ;
    PORT
      LAYER M3 ;
        RECT  55.764 0 55.782 0.144 ;
    END
  END s0_x[866]
  PIN s0_x[867]
    DIRECTION INPUT ;
    USE SIGNAL ;
    PORT
      LAYER M5 ;
        RECT  53.568 0 53.592 0.192 ;
    END
  END s0_x[867]
  PIN s0_x[868]
    DIRECTION INPUT ;
    USE SIGNAL ;
    PORT
      LAYER M3 ;
        RECT  55.872 0 55.89 0.144 ;
    END
  END s0_x[868]
  PIN s0_x[869]
    DIRECTION INPUT ;
    USE SIGNAL ;
    PORT
      LAYER M5 ;
        RECT  53.664 0 53.688 0.192 ;
    END
  END s0_x[869]
  PIN s0_x[86]
    DIRECTION INPUT ;
    USE SIGNAL ;
    PORT
      LAYER M3 ;
        RECT  13.644 0 13.662 0.144 ;
    END
  END s0_x[86]
  PIN s0_x[870]
    DIRECTION INPUT ;
    USE SIGNAL ;
    PORT
      LAYER M3 ;
        RECT  55.98 0 55.998 0.144 ;
    END
  END s0_x[870]
  PIN s0_x[871]
    DIRECTION INPUT ;
    USE SIGNAL ;
    PORT
      LAYER M5 ;
        RECT  53.76 0 53.784 0.192 ;
    END
  END s0_x[871]
  PIN s0_x[872]
    DIRECTION INPUT ;
    USE SIGNAL ;
    PORT
      LAYER M3 ;
        RECT  56.088 0 56.106 0.144 ;
    END
  END s0_x[872]
  PIN s0_x[873]
    DIRECTION INPUT ;
    USE SIGNAL ;
    PORT
      LAYER M5 ;
        RECT  53.856 0 53.88 0.192 ;
    END
  END s0_x[873]
  PIN s0_x[874]
    DIRECTION INPUT ;
    USE SIGNAL ;
    PORT
      LAYER M3 ;
        RECT  56.196 0 56.214 0.144 ;
    END
  END s0_x[874]
  PIN s0_x[875]
    DIRECTION INPUT ;
    USE SIGNAL ;
    PORT
      LAYER M5 ;
        RECT  53.952 0 53.976 0.192 ;
    END
  END s0_x[875]
  PIN s0_x[876]
    DIRECTION INPUT ;
    USE SIGNAL ;
    PORT
      LAYER M3 ;
        RECT  56.304 0 56.322 0.144 ;
    END
  END s0_x[876]
  PIN s0_x[877]
    DIRECTION INPUT ;
    USE SIGNAL ;
    PORT
      LAYER M5 ;
        RECT  54.048 0 54.072 0.192 ;
    END
  END s0_x[877]
  PIN s0_x[878]
    DIRECTION INPUT ;
    USE SIGNAL ;
    PORT
      LAYER M3 ;
        RECT  56.412 0 56.43 0.144 ;
    END
  END s0_x[878]
  PIN s0_x[879]
    DIRECTION INPUT ;
    USE SIGNAL ;
    PORT
      LAYER M5 ;
        RECT  54.144 0 54.168 0.192 ;
    END
  END s0_x[879]
  PIN s0_x[87]
    DIRECTION INPUT ;
    USE SIGNAL ;
    PORT
      LAYER M5 ;
        RECT  16.128 0 16.152 0.192 ;
    END
  END s0_x[87]
  PIN s0_x[880]
    DIRECTION INPUT ;
    USE SIGNAL ;
    PORT
      LAYER M3 ;
        RECT  56.52 0 56.538 0.144 ;
    END
  END s0_x[880]
  PIN s0_x[881]
    DIRECTION INPUT ;
    USE SIGNAL ;
    PORT
      LAYER M5 ;
        RECT  54.24 0 54.264 0.192 ;
    END
  END s0_x[881]
  PIN s0_x[882]
    DIRECTION INPUT ;
    USE SIGNAL ;
    PORT
      LAYER M3 ;
        RECT  56.628 0 56.646 0.144 ;
    END
  END s0_x[882]
  PIN s0_x[883]
    DIRECTION INPUT ;
    USE SIGNAL ;
    PORT
      LAYER M5 ;
        RECT  54.336 0 54.36 0.192 ;
    END
  END s0_x[883]
  PIN s0_x[884]
    DIRECTION INPUT ;
    USE SIGNAL ;
    PORT
      LAYER M3 ;
        RECT  56.736 0 56.754 0.144 ;
    END
  END s0_x[884]
  PIN s0_x[885]
    DIRECTION INPUT ;
    USE SIGNAL ;
    PORT
      LAYER M5 ;
        RECT  54.432 0 54.456 0.192 ;
    END
  END s0_x[885]
  PIN s0_x[886]
    DIRECTION INPUT ;
    USE SIGNAL ;
    PORT
      LAYER M3 ;
        RECT  56.844 0 56.862 0.144 ;
    END
  END s0_x[886]
  PIN s0_x[887]
    DIRECTION INPUT ;
    USE SIGNAL ;
    PORT
      LAYER M5 ;
        RECT  54.528 0 54.552 0.192 ;
    END
  END s0_x[887]
  PIN s0_x[888]
    DIRECTION INPUT ;
    USE SIGNAL ;
    PORT
      LAYER M3 ;
        RECT  56.952 0 56.97 0.144 ;
    END
  END s0_x[888]
  PIN s0_x[889]
    DIRECTION INPUT ;
    USE SIGNAL ;
    PORT
      LAYER M5 ;
        RECT  54.624 0 54.648 0.192 ;
    END
  END s0_x[889]
  PIN s0_x[88]
    DIRECTION INPUT ;
    USE SIGNAL ;
    PORT
      LAYER M3 ;
        RECT  13.752 0 13.77 0.144 ;
    END
  END s0_x[88]
  PIN s0_x[890]
    DIRECTION INPUT ;
    USE SIGNAL ;
    PORT
      LAYER M3 ;
        RECT  57.06 0 57.078 0.144 ;
    END
  END s0_x[890]
  PIN s0_x[891]
    DIRECTION INPUT ;
    USE SIGNAL ;
    PORT
      LAYER M5 ;
        RECT  54.72 0 54.744 0.192 ;
    END
  END s0_x[891]
  PIN s0_x[892]
    DIRECTION INPUT ;
    USE SIGNAL ;
    PORT
      LAYER M3 ;
        RECT  57.168 0 57.186 0.144 ;
    END
  END s0_x[892]
  PIN s0_x[893]
    DIRECTION INPUT ;
    USE SIGNAL ;
    PORT
      LAYER M5 ;
        RECT  54.816 0 54.84 0.192 ;
    END
  END s0_x[893]
  PIN s0_x[894]
    DIRECTION INPUT ;
    USE SIGNAL ;
    PORT
      LAYER M3 ;
        RECT  57.276 0 57.294 0.144 ;
    END
  END s0_x[894]
  PIN s0_x[895]
    DIRECTION INPUT ;
    USE SIGNAL ;
    PORT
      LAYER M5 ;
        RECT  54.912 0 54.936 0.192 ;
    END
  END s0_x[895]
  PIN s0_x[896]
    DIRECTION INPUT ;
    USE SIGNAL ;
    PORT
      LAYER M3 ;
        RECT  57.384 0 57.402 0.144 ;
    END
  END s0_x[896]
  PIN s0_x[897]
    DIRECTION INPUT ;
    USE SIGNAL ;
    PORT
      LAYER M5 ;
        RECT  55.008 0 55.032 0.192 ;
    END
  END s0_x[897]
  PIN s0_x[898]
    DIRECTION INPUT ;
    USE SIGNAL ;
    PORT
      LAYER M3 ;
        RECT  57.492 0 57.51 0.144 ;
    END
  END s0_x[898]
  PIN s0_x[899]
    DIRECTION INPUT ;
    USE SIGNAL ;
    PORT
      LAYER M5 ;
        RECT  55.104 0 55.128 0.192 ;
    END
  END s0_x[899]
  PIN s0_x[89]
    DIRECTION INPUT ;
    USE SIGNAL ;
    PORT
      LAYER M5 ;
        RECT  16.224 0 16.248 0.192 ;
    END
  END s0_x[89]
  PIN s0_x[8]
    DIRECTION INPUT ;
    USE SIGNAL ;
    PORT
      LAYER M3 ;
        RECT  9.432 0 9.45 0.144 ;
    END
  END s0_x[8]
  PIN s0_x[900]
    DIRECTION INPUT ;
    USE SIGNAL ;
    PORT
      LAYER M3 ;
        RECT  57.6 0 57.618 0.144 ;
    END
  END s0_x[900]
  PIN s0_x[901]
    DIRECTION INPUT ;
    USE SIGNAL ;
    PORT
      LAYER M5 ;
        RECT  55.2 0 55.224 0.192 ;
    END
  END s0_x[901]
  PIN s0_x[902]
    DIRECTION INPUT ;
    USE SIGNAL ;
    PORT
      LAYER M3 ;
        RECT  57.708 0 57.726 0.144 ;
    END
  END s0_x[902]
  PIN s0_x[903]
    DIRECTION INPUT ;
    USE SIGNAL ;
    PORT
      LAYER M5 ;
        RECT  55.296 0 55.32 0.192 ;
    END
  END s0_x[903]
  PIN s0_x[904]
    DIRECTION INPUT ;
    USE SIGNAL ;
    PORT
      LAYER M3 ;
        RECT  57.816 0 57.834 0.144 ;
    END
  END s0_x[904]
  PIN s0_x[905]
    DIRECTION INPUT ;
    USE SIGNAL ;
    PORT
      LAYER M5 ;
        RECT  55.392 0 55.416 0.192 ;
    END
  END s0_x[905]
  PIN s0_x[906]
    DIRECTION INPUT ;
    USE SIGNAL ;
    PORT
      LAYER M3 ;
        RECT  57.924 0 57.942 0.144 ;
    END
  END s0_x[906]
  PIN s0_x[907]
    DIRECTION INPUT ;
    USE SIGNAL ;
    PORT
      LAYER M5 ;
        RECT  55.488 0 55.512 0.192 ;
    END
  END s0_x[907]
  PIN s0_x[908]
    DIRECTION INPUT ;
    USE SIGNAL ;
    PORT
      LAYER M3 ;
        RECT  58.032 0 58.05 0.144 ;
    END
  END s0_x[908]
  PIN s0_x[909]
    DIRECTION INPUT ;
    USE SIGNAL ;
    PORT
      LAYER M5 ;
        RECT  55.584 0 55.608 0.192 ;
    END
  END s0_x[909]
  PIN s0_x[90]
    DIRECTION INPUT ;
    USE SIGNAL ;
    PORT
      LAYER M3 ;
        RECT  13.86 0 13.878 0.144 ;
    END
  END s0_x[90]
  PIN s0_x[910]
    DIRECTION INPUT ;
    USE SIGNAL ;
    PORT
      LAYER M3 ;
        RECT  58.14 0 58.158 0.144 ;
    END
  END s0_x[910]
  PIN s0_x[911]
    DIRECTION INPUT ;
    USE SIGNAL ;
    PORT
      LAYER M5 ;
        RECT  55.68 0 55.704 0.192 ;
    END
  END s0_x[911]
  PIN s0_x[912]
    DIRECTION INPUT ;
    USE SIGNAL ;
    PORT
      LAYER M3 ;
        RECT  58.248 0 58.266 0.144 ;
    END
  END s0_x[912]
  PIN s0_x[913]
    DIRECTION INPUT ;
    USE SIGNAL ;
    PORT
      LAYER M5 ;
        RECT  55.776 0 55.8 0.192 ;
    END
  END s0_x[913]
  PIN s0_x[914]
    DIRECTION INPUT ;
    USE SIGNAL ;
    PORT
      LAYER M3 ;
        RECT  58.356 0 58.374 0.144 ;
    END
  END s0_x[914]
  PIN s0_x[915]
    DIRECTION INPUT ;
    USE SIGNAL ;
    PORT
      LAYER M5 ;
        RECT  55.872 0 55.896 0.192 ;
    END
  END s0_x[915]
  PIN s0_x[916]
    DIRECTION INPUT ;
    USE SIGNAL ;
    PORT
      LAYER M3 ;
        RECT  58.464 0 58.482 0.144 ;
    END
  END s0_x[916]
  PIN s0_x[917]
    DIRECTION INPUT ;
    USE SIGNAL ;
    PORT
      LAYER M5 ;
        RECT  55.968 0 55.992 0.192 ;
    END
  END s0_x[917]
  PIN s0_x[918]
    DIRECTION INPUT ;
    USE SIGNAL ;
    PORT
      LAYER M3 ;
        RECT  58.572 0 58.59 0.144 ;
    END
  END s0_x[918]
  PIN s0_x[919]
    DIRECTION INPUT ;
    USE SIGNAL ;
    PORT
      LAYER M5 ;
        RECT  56.064 0 56.088 0.192 ;
    END
  END s0_x[919]
  PIN s0_x[91]
    DIRECTION INPUT ;
    USE SIGNAL ;
    PORT
      LAYER M5 ;
        RECT  16.32 0 16.344 0.192 ;
    END
  END s0_x[91]
  PIN s0_x[920]
    DIRECTION INPUT ;
    USE SIGNAL ;
    PORT
      LAYER M3 ;
        RECT  58.68 0 58.698 0.144 ;
    END
  END s0_x[920]
  PIN s0_x[921]
    DIRECTION INPUT ;
    USE SIGNAL ;
    PORT
      LAYER M5 ;
        RECT  56.16 0 56.184 0.192 ;
    END
  END s0_x[921]
  PIN s0_x[922]
    DIRECTION INPUT ;
    USE SIGNAL ;
    PORT
      LAYER M3 ;
        RECT  58.788 0 58.806 0.144 ;
    END
  END s0_x[922]
  PIN s0_x[923]
    DIRECTION INPUT ;
    USE SIGNAL ;
    PORT
      LAYER M5 ;
        RECT  56.256 0 56.28 0.192 ;
    END
  END s0_x[923]
  PIN s0_x[924]
    DIRECTION INPUT ;
    USE SIGNAL ;
    PORT
      LAYER M3 ;
        RECT  58.896 0 58.914 0.144 ;
    END
  END s0_x[924]
  PIN s0_x[925]
    DIRECTION INPUT ;
    USE SIGNAL ;
    PORT
      LAYER M5 ;
        RECT  56.352 0 56.376 0.192 ;
    END
  END s0_x[925]
  PIN s0_x[926]
    DIRECTION INPUT ;
    USE SIGNAL ;
    PORT
      LAYER M3 ;
        RECT  59.004 0 59.022 0.144 ;
    END
  END s0_x[926]
  PIN s0_x[927]
    DIRECTION INPUT ;
    USE SIGNAL ;
    PORT
      LAYER M5 ;
        RECT  56.448 0 56.472 0.192 ;
    END
  END s0_x[927]
  PIN s0_x[928]
    DIRECTION INPUT ;
    USE SIGNAL ;
    PORT
      LAYER M3 ;
        RECT  59.112 0 59.13 0.144 ;
    END
  END s0_x[928]
  PIN s0_x[929]
    DIRECTION INPUT ;
    USE SIGNAL ;
    PORT
      LAYER M5 ;
        RECT  56.544 0 56.568 0.192 ;
    END
  END s0_x[929]
  PIN s0_x[92]
    DIRECTION INPUT ;
    USE SIGNAL ;
    PORT
      LAYER M3 ;
        RECT  13.968 0 13.986 0.144 ;
    END
  END s0_x[92]
  PIN s0_x[930]
    DIRECTION INPUT ;
    USE SIGNAL ;
    PORT
      LAYER M3 ;
        RECT  59.22 0 59.238 0.144 ;
    END
  END s0_x[930]
  PIN s0_x[931]
    DIRECTION INPUT ;
    USE SIGNAL ;
    PORT
      LAYER M5 ;
        RECT  56.64 0 56.664 0.192 ;
    END
  END s0_x[931]
  PIN s0_x[932]
    DIRECTION INPUT ;
    USE SIGNAL ;
    PORT
      LAYER M3 ;
        RECT  59.328 0 59.346 0.144 ;
    END
  END s0_x[932]
  PIN s0_x[933]
    DIRECTION INPUT ;
    USE SIGNAL ;
    PORT
      LAYER M5 ;
        RECT  56.736 0 56.76 0.192 ;
    END
  END s0_x[933]
  PIN s0_x[934]
    DIRECTION INPUT ;
    USE SIGNAL ;
    PORT
      LAYER M3 ;
        RECT  59.436 0 59.454 0.144 ;
    END
  END s0_x[934]
  PIN s0_x[935]
    DIRECTION INPUT ;
    USE SIGNAL ;
    PORT
      LAYER M5 ;
        RECT  56.832 0 56.856 0.192 ;
    END
  END s0_x[935]
  PIN s0_x[936]
    DIRECTION INPUT ;
    USE SIGNAL ;
    PORT
      LAYER M3 ;
        RECT  59.544 0 59.562 0.144 ;
    END
  END s0_x[936]
  PIN s0_x[937]
    DIRECTION INPUT ;
    USE SIGNAL ;
    PORT
      LAYER M5 ;
        RECT  56.928 0 56.952 0.192 ;
    END
  END s0_x[937]
  PIN s0_x[938]
    DIRECTION INPUT ;
    USE SIGNAL ;
    PORT
      LAYER M3 ;
        RECT  59.652 0 59.67 0.144 ;
    END
  END s0_x[938]
  PIN s0_x[939]
    DIRECTION INPUT ;
    USE SIGNAL ;
    PORT
      LAYER M5 ;
        RECT  57.024 0 57.048 0.192 ;
    END
  END s0_x[939]
  PIN s0_x[93]
    DIRECTION INPUT ;
    USE SIGNAL ;
    PORT
      LAYER M5 ;
        RECT  16.416 0 16.44 0.192 ;
    END
  END s0_x[93]
  PIN s0_x[940]
    DIRECTION INPUT ;
    USE SIGNAL ;
    PORT
      LAYER M3 ;
        RECT  59.76 0 59.778 0.144 ;
    END
  END s0_x[940]
  PIN s0_x[941]
    DIRECTION INPUT ;
    USE SIGNAL ;
    PORT
      LAYER M5 ;
        RECT  57.12 0 57.144 0.192 ;
    END
  END s0_x[941]
  PIN s0_x[942]
    DIRECTION INPUT ;
    USE SIGNAL ;
    PORT
      LAYER M3 ;
        RECT  59.868 0 59.886 0.144 ;
    END
  END s0_x[942]
  PIN s0_x[943]
    DIRECTION INPUT ;
    USE SIGNAL ;
    PORT
      LAYER M5 ;
        RECT  57.216 0 57.24 0.192 ;
    END
  END s0_x[943]
  PIN s0_x[944]
    DIRECTION INPUT ;
    USE SIGNAL ;
    PORT
      LAYER M3 ;
        RECT  59.976 0 59.994 0.144 ;
    END
  END s0_x[944]
  PIN s0_x[945]
    DIRECTION INPUT ;
    USE SIGNAL ;
    PORT
      LAYER M5 ;
        RECT  57.312 0 57.336 0.192 ;
    END
  END s0_x[945]
  PIN s0_x[946]
    DIRECTION INPUT ;
    USE SIGNAL ;
    PORT
      LAYER M3 ;
        RECT  60.084 0 60.102 0.144 ;
    END
  END s0_x[946]
  PIN s0_x[947]
    DIRECTION INPUT ;
    USE SIGNAL ;
    PORT
      LAYER M5 ;
        RECT  57.408 0 57.432 0.192 ;
    END
  END s0_x[947]
  PIN s0_x[948]
    DIRECTION INPUT ;
    USE SIGNAL ;
    PORT
      LAYER M3 ;
        RECT  60.192 0 60.21 0.144 ;
    END
  END s0_x[948]
  PIN s0_x[949]
    DIRECTION INPUT ;
    USE SIGNAL ;
    PORT
      LAYER M5 ;
        RECT  57.504 0 57.528 0.192 ;
    END
  END s0_x[949]
  PIN s0_x[94]
    DIRECTION INPUT ;
    USE SIGNAL ;
    PORT
      LAYER M3 ;
        RECT  14.076 0 14.094 0.144 ;
    END
  END s0_x[94]
  PIN s0_x[950]
    DIRECTION INPUT ;
    USE SIGNAL ;
    PORT
      LAYER M3 ;
        RECT  60.3 0 60.318 0.144 ;
    END
  END s0_x[950]
  PIN s0_x[951]
    DIRECTION INPUT ;
    USE SIGNAL ;
    PORT
      LAYER M5 ;
        RECT  57.6 0 57.624 0.192 ;
    END
  END s0_x[951]
  PIN s0_x[952]
    DIRECTION INPUT ;
    USE SIGNAL ;
    PORT
      LAYER M3 ;
        RECT  60.408 0 60.426 0.144 ;
    END
  END s0_x[952]
  PIN s0_x[953]
    DIRECTION INPUT ;
    USE SIGNAL ;
    PORT
      LAYER M5 ;
        RECT  57.696 0 57.72 0.192 ;
    END
  END s0_x[953]
  PIN s0_x[954]
    DIRECTION INPUT ;
    USE SIGNAL ;
    PORT
      LAYER M3 ;
        RECT  60.516 0 60.534 0.144 ;
    END
  END s0_x[954]
  PIN s0_x[955]
    DIRECTION INPUT ;
    USE SIGNAL ;
    PORT
      LAYER M5 ;
        RECT  57.792 0 57.816 0.192 ;
    END
  END s0_x[955]
  PIN s0_x[956]
    DIRECTION INPUT ;
    USE SIGNAL ;
    PORT
      LAYER M3 ;
        RECT  60.624 0 60.642 0.144 ;
    END
  END s0_x[956]
  PIN s0_x[957]
    DIRECTION INPUT ;
    USE SIGNAL ;
    PORT
      LAYER M5 ;
        RECT  57.888 0 57.912 0.192 ;
    END
  END s0_x[957]
  PIN s0_x[958]
    DIRECTION INPUT ;
    USE SIGNAL ;
    PORT
      LAYER M3 ;
        RECT  60.732 0 60.75 0.144 ;
    END
  END s0_x[958]
  PIN s0_x[959]
    DIRECTION INPUT ;
    USE SIGNAL ;
    PORT
      LAYER M5 ;
        RECT  57.984 0 58.008 0.192 ;
    END
  END s0_x[959]
  PIN s0_x[95]
    DIRECTION INPUT ;
    USE SIGNAL ;
    PORT
      LAYER M5 ;
        RECT  16.512 0 16.536 0.192 ;
    END
  END s0_x[95]
  PIN s0_x[960]
    DIRECTION INPUT ;
    USE SIGNAL ;
    PORT
      LAYER M3 ;
        RECT  60.84 0 60.858 0.144 ;
    END
  END s0_x[960]
  PIN s0_x[961]
    DIRECTION INPUT ;
    USE SIGNAL ;
    PORT
      LAYER M5 ;
        RECT  58.08 0 58.104 0.192 ;
    END
  END s0_x[961]
  PIN s0_x[962]
    DIRECTION INPUT ;
    USE SIGNAL ;
    PORT
      LAYER M3 ;
        RECT  60.948 0 60.966 0.144 ;
    END
  END s0_x[962]
  PIN s0_x[963]
    DIRECTION INPUT ;
    USE SIGNAL ;
    PORT
      LAYER M5 ;
        RECT  58.176 0 58.2 0.192 ;
    END
  END s0_x[963]
  PIN s0_x[964]
    DIRECTION INPUT ;
    USE SIGNAL ;
    PORT
      LAYER M3 ;
        RECT  61.056 0 61.074 0.144 ;
    END
  END s0_x[964]
  PIN s0_x[965]
    DIRECTION INPUT ;
    USE SIGNAL ;
    PORT
      LAYER M5 ;
        RECT  58.272 0 58.296 0.192 ;
    END
  END s0_x[965]
  PIN s0_x[966]
    DIRECTION INPUT ;
    USE SIGNAL ;
    PORT
      LAYER M3 ;
        RECT  61.164 0 61.182 0.144 ;
    END
  END s0_x[966]
  PIN s0_x[967]
    DIRECTION INPUT ;
    USE SIGNAL ;
    PORT
      LAYER M5 ;
        RECT  58.368 0 58.392 0.192 ;
    END
  END s0_x[967]
  PIN s0_x[968]
    DIRECTION INPUT ;
    USE SIGNAL ;
    PORT
      LAYER M3 ;
        RECT  61.272 0 61.29 0.144 ;
    END
  END s0_x[968]
  PIN s0_x[969]
    DIRECTION INPUT ;
    USE SIGNAL ;
    PORT
      LAYER M5 ;
        RECT  58.464 0 58.488 0.192 ;
    END
  END s0_x[969]
  PIN s0_x[96]
    DIRECTION INPUT ;
    USE SIGNAL ;
    PORT
      LAYER M3 ;
        RECT  14.184 0 14.202 0.144 ;
    END
  END s0_x[96]
  PIN s0_x[970]
    DIRECTION INPUT ;
    USE SIGNAL ;
    PORT
      LAYER M3 ;
        RECT  61.38 0 61.398 0.144 ;
    END
  END s0_x[970]
  PIN s0_x[971]
    DIRECTION INPUT ;
    USE SIGNAL ;
    PORT
      LAYER M5 ;
        RECT  58.56 0 58.584 0.192 ;
    END
  END s0_x[971]
  PIN s0_x[972]
    DIRECTION INPUT ;
    USE SIGNAL ;
    PORT
      LAYER M3 ;
        RECT  61.488 0 61.506 0.144 ;
    END
  END s0_x[972]
  PIN s0_x[973]
    DIRECTION INPUT ;
    USE SIGNAL ;
    PORT
      LAYER M5 ;
        RECT  58.656 0 58.68 0.192 ;
    END
  END s0_x[973]
  PIN s0_x[974]
    DIRECTION INPUT ;
    USE SIGNAL ;
    PORT
      LAYER M3 ;
        RECT  61.596 0 61.614 0.144 ;
    END
  END s0_x[974]
  PIN s0_x[975]
    DIRECTION INPUT ;
    USE SIGNAL ;
    PORT
      LAYER M5 ;
        RECT  58.752 0 58.776 0.192 ;
    END
  END s0_x[975]
  PIN s0_x[976]
    DIRECTION INPUT ;
    USE SIGNAL ;
    PORT
      LAYER M3 ;
        RECT  61.704 0 61.722 0.144 ;
    END
  END s0_x[976]
  PIN s0_x[977]
    DIRECTION INPUT ;
    USE SIGNAL ;
    PORT
      LAYER M5 ;
        RECT  58.848 0 58.872 0.192 ;
    END
  END s0_x[977]
  PIN s0_x[978]
    DIRECTION INPUT ;
    USE SIGNAL ;
    PORT
      LAYER M3 ;
        RECT  61.812 0 61.83 0.144 ;
    END
  END s0_x[978]
  PIN s0_x[979]
    DIRECTION INPUT ;
    USE SIGNAL ;
    PORT
      LAYER M5 ;
        RECT  58.944 0 58.968 0.192 ;
    END
  END s0_x[979]
  PIN s0_x[97]
    DIRECTION INPUT ;
    USE SIGNAL ;
    PORT
      LAYER M5 ;
        RECT  16.608 0 16.632 0.192 ;
    END
  END s0_x[97]
  PIN s0_x[980]
    DIRECTION INPUT ;
    USE SIGNAL ;
    PORT
      LAYER M3 ;
        RECT  61.92 0 61.938 0.144 ;
    END
  END s0_x[980]
  PIN s0_x[981]
    DIRECTION INPUT ;
    USE SIGNAL ;
    PORT
      LAYER M5 ;
        RECT  59.04 0 59.064 0.192 ;
    END
  END s0_x[981]
  PIN s0_x[982]
    DIRECTION INPUT ;
    USE SIGNAL ;
    PORT
      LAYER M3 ;
        RECT  62.028 0 62.046 0.144 ;
    END
  END s0_x[982]
  PIN s0_x[983]
    DIRECTION INPUT ;
    USE SIGNAL ;
    PORT
      LAYER M5 ;
        RECT  59.136 0 59.16 0.192 ;
    END
  END s0_x[983]
  PIN s0_x[984]
    DIRECTION INPUT ;
    USE SIGNAL ;
    PORT
      LAYER M3 ;
        RECT  62.136 0 62.154 0.144 ;
    END
  END s0_x[984]
  PIN s0_x[985]
    DIRECTION INPUT ;
    USE SIGNAL ;
    PORT
      LAYER M5 ;
        RECT  59.232 0 59.256 0.192 ;
    END
  END s0_x[985]
  PIN s0_x[986]
    DIRECTION INPUT ;
    USE SIGNAL ;
    PORT
      LAYER M3 ;
        RECT  62.244 0 62.262 0.144 ;
    END
  END s0_x[986]
  PIN s0_x[987]
    DIRECTION INPUT ;
    USE SIGNAL ;
    PORT
      LAYER M5 ;
        RECT  59.328 0 59.352 0.192 ;
    END
  END s0_x[987]
  PIN s0_x[988]
    DIRECTION INPUT ;
    USE SIGNAL ;
    PORT
      LAYER M3 ;
        RECT  62.352 0 62.37 0.144 ;
    END
  END s0_x[988]
  PIN s0_x[989]
    DIRECTION INPUT ;
    USE SIGNAL ;
    PORT
      LAYER M5 ;
        RECT  59.424 0 59.448 0.192 ;
    END
  END s0_x[989]
  PIN s0_x[98]
    DIRECTION INPUT ;
    USE SIGNAL ;
    PORT
      LAYER M3 ;
        RECT  14.292 0 14.31 0.144 ;
    END
  END s0_x[98]
  PIN s0_x[990]
    DIRECTION INPUT ;
    USE SIGNAL ;
    PORT
      LAYER M3 ;
        RECT  62.46 0 62.478 0.144 ;
    END
  END s0_x[990]
  PIN s0_x[991]
    DIRECTION INPUT ;
    USE SIGNAL ;
    PORT
      LAYER M5 ;
        RECT  59.52 0 59.544 0.192 ;
    END
  END s0_x[991]
  PIN s0_x[992]
    DIRECTION INPUT ;
    USE SIGNAL ;
    PORT
      LAYER M3 ;
        RECT  62.568 0 62.586 0.144 ;
    END
  END s0_x[992]
  PIN s0_x[993]
    DIRECTION INPUT ;
    USE SIGNAL ;
    PORT
      LAYER M5 ;
        RECT  59.616 0 59.64 0.192 ;
    END
  END s0_x[993]
  PIN s0_x[994]
    DIRECTION INPUT ;
    USE SIGNAL ;
    PORT
      LAYER M3 ;
        RECT  62.676 0 62.694 0.144 ;
    END
  END s0_x[994]
  PIN s0_x[995]
    DIRECTION INPUT ;
    USE SIGNAL ;
    PORT
      LAYER M5 ;
        RECT  59.712 0 59.736 0.192 ;
    END
  END s0_x[995]
  PIN s0_x[996]
    DIRECTION INPUT ;
    USE SIGNAL ;
    PORT
      LAYER M3 ;
        RECT  62.784 0 62.802 0.144 ;
    END
  END s0_x[996]
  PIN s0_x[997]
    DIRECTION INPUT ;
    USE SIGNAL ;
    PORT
      LAYER M5 ;
        RECT  59.808 0 59.832 0.192 ;
    END
  END s0_x[997]
  PIN s0_x[998]
    DIRECTION INPUT ;
    USE SIGNAL ;
    PORT
      LAYER M3 ;
        RECT  62.892 0 62.91 0.144 ;
    END
  END s0_x[998]
  PIN s0_x[999]
    DIRECTION INPUT ;
    USE SIGNAL ;
    PORT
      LAYER M5 ;
        RECT  59.904 0 59.928 0.192 ;
    END
  END s0_x[999]
  PIN s0_x[99]
    DIRECTION INPUT ;
    USE SIGNAL ;
    PORT
      LAYER M5 ;
        RECT  16.704 0 16.728 0.192 ;
    END
  END s0_x[99]
  PIN s0_x[9]
    DIRECTION INPUT ;
    USE SIGNAL ;
    PORT
      LAYER M5 ;
        RECT  12.384 0 12.408 0.192 ;
    END
  END s0_x[9]
  PIN s15_e[0]
    DIRECTION OUTPUT ;
    USE SIGNAL ;
    PORT
      LAYER M3 ;
        RECT  14.4 77.616 14.418 77.76 ;
    END
  END s15_e[0]
  PIN s15_e[1]
    DIRECTION OUTPUT ;
    USE SIGNAL ;
    PORT
      LAYER M3 ;
        RECT  14.544 77.616 14.562 77.76 ;
    END
  END s15_e[1]
  PIN s15_e[2]
    DIRECTION OUTPUT ;
    USE SIGNAL ;
    PORT
      LAYER M3 ;
        RECT  14.688 77.616 14.706 77.76 ;
    END
  END s15_e[2]
  PIN s15_e[3]
    DIRECTION OUTPUT ;
    USE SIGNAL ;
    PORT
      LAYER M3 ;
        RECT  14.832 77.616 14.85 77.76 ;
    END
  END s15_e[3]
  PIN s15_e[4]
    DIRECTION OUTPUT ;
    USE SIGNAL ;
    PORT
      LAYER M3 ;
        RECT  14.976 77.616 14.994 77.76 ;
    END
  END s15_e[4]
  PIN s15_e[5]
    DIRECTION OUTPUT ;
    USE SIGNAL ;
    PORT
      LAYER M3 ;
        RECT  15.12 77.616 15.138 77.76 ;
    END
  END s15_e[5]
  PIN s15_e[6]
    DIRECTION OUTPUT ;
    USE SIGNAL ;
    PORT
      LAYER M3 ;
        RECT  15.264 77.616 15.282 77.76 ;
    END
  END s15_e[6]
  PIN s15_e[7]
    DIRECTION OUTPUT ;
    USE SIGNAL ;
    PORT
      LAYER M3 ;
        RECT  15.408 77.616 15.426 77.76 ;
    END
  END s15_e[7]
  PIN s15_e[8]
    DIRECTION OUTPUT ;
    USE SIGNAL ;
    PORT
      LAYER M3 ;
        RECT  15.552 77.616 15.57 77.76 ;
    END
  END s15_e[8]
  PIN s15_e[9]
    DIRECTION OUTPUT ;
    USE SIGNAL ;
    PORT
      LAYER M3 ;
        RECT  15.696 77.616 15.714 77.76 ;
    END
  END s15_e[9]
  PIN v
    DIRECTION INPUT ;
    USE SIGNAL ;
    PORT
      LAYER M4 ;
        RECT  0 36.864 0.192 36.888 ;
    END
    PORT
      LAYER M4 ;
        RECT  0.156 36.864 2.408 36.888 ;
    END
  END v
  PIN vo
    DIRECTION OUTPUT ;
    USE SIGNAL ;
    PORT
      LAYER M3 ;
        RECT  15.84 77.616 15.858 77.76 ;
    END
  END vo
  PIN VDD
    DIRECTION INOUT ;
    USE POWER ;
    PORT
      LAYER M5 ;
        RECT  67.392 2.151 67.512 75.609 ;
        RECT  61.992 2.151 62.112 75.609 ;
        RECT  56.592 2.151 56.712 75.609 ;
        RECT  51.192 2.151 51.312 75.609 ;
        RECT  45.792 2.151 45.912 75.609 ;
        RECT  40.392 2.151 40.512 75.609 ;
        RECT  34.992 2.151 35.112 75.609 ;
        RECT  29.592 2.151 29.712 75.609 ;
        RECT  24.192 2.151 24.312 75.609 ;
        RECT  18.792 2.151 18.912 75.609 ;
        RECT  13.392 2.151 13.512 75.609 ;
        RECT  7.992 2.151 8.112 75.609 ;
        RECT  2.592 2.151 2.712 75.609 ;
    END
  END VDD
  PIN VSS
    DIRECTION INOUT ;
    USE GROUND ;
    PORT
      LAYER M5 ;
        RECT  67.2 2.137 67.32 75.623 ;
        RECT  61.8 2.137 61.92 75.623 ;
        RECT  56.4 2.137 56.52 75.623 ;
        RECT  51 2.137 51.12 75.623 ;
        RECT  45.6 2.137 45.72 75.623 ;
        RECT  40.2 2.137 40.32 75.623 ;
        RECT  34.8 2.137 34.92 75.623 ;
        RECT  29.4 2.137 29.52 75.623 ;
        RECT  24 2.137 24.12 75.623 ;
        RECT  18.6 2.137 18.72 75.623 ;
        RECT  13.2 2.137 13.32 75.623 ;
        RECT  7.8 2.137 7.92 75.623 ;
        RECT  2.4 2.137 2.52 75.623 ;
    END
  END VSS
  # OT_OBS_CLOSED layer=M5 d_um=1.536 added=348
  OBS
    LAYER RVTN ;
     RECT  2.16 2.16 71.28 2.295 ;
     RECT  2.16 2.565 71.28 2.835 ;
     RECT  2.16 3.105 71.28 3.375 ;
     RECT  2.16 3.645 71.28 3.915 ;
     RECT  2.16 4.185 71.28 4.455 ;
     RECT  2.16 4.725 71.28 4.995 ;
     RECT  2.16 5.265 71.28 5.535 ;
     RECT  2.16 5.805 71.28 6.075 ;
     RECT  2.16 6.345 71.28 6.615 ;
     RECT  2.16 6.885 71.28 7.155 ;
     RECT  2.16 7.425 71.28 7.695 ;
     RECT  2.16 7.965 71.28 8.235 ;
     RECT  2.16 8.505 71.28 8.775 ;
     RECT  2.16 9.045 71.28 9.315 ;
     RECT  2.16 9.585 71.28 9.855 ;
     RECT  2.16 10.125 71.28 10.395 ;
     RECT  2.16 10.665 71.28 10.935 ;
     RECT  2.16 11.205 71.28 11.475 ;
     RECT  2.16 11.745 71.28 12.015 ;
     RECT  2.16 12.285 71.28 12.555 ;
     RECT  2.16 12.825 71.28 13.095 ;
     RECT  2.16 13.365 71.28 13.635 ;
     RECT  2.16 13.905 71.28 14.175 ;
     RECT  2.16 14.445 71.28 14.715 ;
     RECT  2.16 14.985 71.28 15.255 ;
     RECT  2.16 15.525 71.28 15.795 ;
     RECT  2.16 16.065 71.28 16.335 ;
     RECT  2.16 16.605 71.28 16.875 ;
     RECT  2.16 17.145 71.28 17.415 ;
     RECT  2.16 17.685 71.28 17.955 ;
     RECT  2.16 18.225 71.28 18.495 ;
     RECT  2.16 18.765 71.28 19.035 ;
     RECT  2.16 19.305 71.28 19.575 ;
     RECT  2.16 19.845 71.28 20.115 ;
     RECT  2.16 20.385 71.28 20.655 ;
     RECT  2.16 20.925 71.28 21.195 ;
     RECT  2.16 21.465 71.28 21.735 ;
     RECT  2.16 22.005 71.28 22.275 ;
     RECT  2.16 22.545 71.28 22.815 ;
     RECT  2.16 23.085 71.28 23.355 ;
     RECT  2.16 23.625 71.28 23.895 ;
     RECT  2.16 24.165 71.28 24.435 ;
     RECT  2.16 24.705 71.28 24.975 ;
     RECT  2.16 25.245 71.28 25.515 ;
     RECT  2.16 25.785 71.28 26.055 ;
     RECT  2.16 26.325 71.28 26.595 ;
     RECT  2.16 26.865 71.28 27.135 ;
     RECT  2.16 27.405 71.28 27.675 ;
     RECT  2.16 27.945 71.28 28.215 ;
     RECT  2.16 28.485 71.28 28.755 ;
     RECT  2.16 29.025 71.28 29.295 ;
     RECT  2.16 29.565 71.28 29.835 ;
     RECT  2.16 30.105 71.28 30.375 ;
     RECT  2.16 30.645 71.28 30.915 ;
     RECT  2.16 31.185 71.28 31.455 ;
     RECT  2.16 31.725 71.28 31.995 ;
     RECT  2.16 32.265 71.28 32.535 ;
     RECT  2.16 32.805 71.28 33.075 ;
     RECT  2.16 33.345 71.28 33.615 ;
     RECT  2.16 33.885 71.28 34.155 ;
     RECT  2.16 34.425 71.28 34.695 ;
     RECT  2.16 34.965 71.28 35.235 ;
     RECT  2.16 35.505 71.28 35.775 ;
     RECT  2.16 36.045 71.28 36.315 ;
     RECT  2.16 36.585 71.28 36.855 ;
     RECT  2.16 37.125 71.28 37.395 ;
     RECT  2.16 37.665 71.28 37.935 ;
     RECT  2.16 38.205 71.28 38.475 ;
     RECT  2.16 38.745 71.28 39.015 ;
     RECT  2.16 39.285 71.28 39.555 ;
     RECT  2.16 39.825 71.28 40.095 ;
     RECT  2.16 40.365 71.28 40.635 ;
     RECT  2.16 40.905 71.28 41.175 ;
     RECT  2.16 41.445 71.28 41.715 ;
     RECT  2.16 41.985 71.28 42.255 ;
     RECT  2.16 42.525 71.28 42.795 ;
     RECT  2.16 43.065 71.28 43.335 ;
     RECT  2.16 43.605 71.28 43.875 ;
     RECT  2.16 44.145 71.28 44.415 ;
     RECT  2.16 44.685 71.28 44.955 ;
     RECT  2.16 45.225 71.28 45.495 ;
     RECT  2.16 45.765 71.28 46.035 ;
     RECT  2.16 46.305 71.28 46.575 ;
     RECT  2.16 46.845 71.28 47.115 ;
     RECT  2.16 47.385 71.28 47.655 ;
     RECT  2.16 47.925 71.28 48.195 ;
     RECT  2.16 48.465 71.28 48.735 ;
     RECT  2.16 49.005 71.28 49.275 ;
     RECT  2.16 49.545 71.28 49.815 ;
     RECT  2.16 50.085 71.28 50.355 ;
     RECT  2.16 50.625 71.28 50.895 ;
     RECT  2.16 51.165 71.28 51.435 ;
     RECT  2.16 51.705 71.28 51.975 ;
     RECT  2.16 52.245 71.28 52.515 ;
     RECT  2.16 52.785 71.28 53.055 ;
     RECT  2.16 53.325 71.28 53.595 ;
     RECT  2.16 53.865 71.28 54.135 ;
     RECT  2.16 54.405 71.28 54.675 ;
     RECT  2.16 54.945 71.28 55.215 ;
     RECT  2.16 55.485 71.28 55.755 ;
     RECT  2.16 56.025 71.28 56.295 ;
     RECT  2.16 56.565 71.28 56.835 ;
     RECT  2.16 57.105 71.28 57.375 ;
     RECT  2.16 57.645 71.28 57.915 ;
     RECT  2.16 58.185 71.28 58.455 ;
     RECT  2.16 58.725 71.28 58.995 ;
     RECT  2.16 59.265 71.28 59.535 ;
     RECT  2.16 59.805 71.28 60.075 ;
     RECT  2.16 60.345 71.28 60.615 ;
     RECT  2.16 60.885 71.28 61.155 ;
     RECT  2.16 61.425 71.28 61.695 ;
     RECT  2.16 61.965 71.28 62.235 ;
     RECT  2.16 62.505 71.28 62.775 ;
     RECT  2.16 63.045 71.28 63.315 ;
     RECT  2.16 63.585 71.28 63.855 ;
     RECT  2.16 64.125 71.28 64.395 ;
     RECT  2.16 64.665 71.28 64.935 ;
     RECT  2.16 65.205 71.28 65.475 ;
     RECT  2.16 65.745 71.28 66.015 ;
     RECT  2.16 66.285 71.28 66.555 ;
     RECT  2.16 66.825 71.28 67.095 ;
     RECT  2.16 67.365 71.28 67.635 ;
     RECT  2.16 67.905 71.28 68.175 ;
     RECT  2.16 68.445 71.28 68.715 ;
     RECT  2.16 68.985 71.28 69.255 ;
     RECT  2.16 69.525 71.28 69.795 ;
     RECT  2.16 70.065 71.28 70.335 ;
     RECT  2.16 70.605 71.28 70.875 ;
     RECT  2.16 71.145 71.28 71.415 ;
     RECT  2.16 71.685 71.28 71.955 ;
     RECT  2.16 72.225 71.28 72.495 ;
     RECT  2.16 72.765 71.28 73.035 ;
     RECT  2.16 73.305 71.28 73.575 ;
     RECT  2.16 73.845 71.28 74.115 ;
     RECT  2.16 74.385 71.28 74.655 ;
     RECT  2.16 74.925 71.28 75.195 ;
     RECT  2.16 75.465 71.28 75.6 ;
    LAYER RVTP ;
     RECT  2.16 2.295 71.28 2.565 ;
     RECT  2.16 2.835 71.28 3.105 ;
     RECT  2.16 3.375 71.28 3.645 ;
     RECT  2.16 3.915 71.28 4.185 ;
     RECT  2.16 4.455 71.28 4.725 ;
     RECT  2.16 4.995 71.28 5.265 ;
     RECT  2.16 5.535 71.28 5.805 ;
     RECT  2.16 6.075 71.28 6.345 ;
     RECT  2.16 6.615 71.28 6.885 ;
     RECT  2.16 7.155 71.28 7.425 ;
     RECT  2.16 7.695 71.28 7.965 ;
     RECT  2.16 8.235 71.28 8.505 ;
     RECT  2.16 8.775 71.28 9.045 ;
     RECT  2.16 9.315 71.28 9.585 ;
     RECT  2.16 9.855 71.28 10.125 ;
     RECT  2.16 10.395 71.28 10.665 ;
     RECT  2.16 10.935 71.28 11.205 ;
     RECT  2.16 11.475 71.28 11.745 ;
     RECT  2.16 12.015 71.28 12.285 ;
     RECT  2.16 12.555 71.28 12.825 ;
     RECT  2.16 13.095 71.28 13.365 ;
     RECT  2.16 13.635 71.28 13.905 ;
     RECT  2.16 14.175 71.28 14.445 ;
     RECT  2.16 14.715 71.28 14.985 ;
     RECT  2.16 15.255 71.28 15.525 ;
     RECT  2.16 15.795 71.28 16.065 ;
     RECT  2.16 16.335 71.28 16.605 ;
     RECT  2.16 16.875 71.28 17.145 ;
     RECT  2.16 17.415 71.28 17.685 ;
     RECT  2.16 17.955 71.28 18.225 ;
     RECT  2.16 18.495 71.28 18.765 ;
     RECT  2.16 19.035 71.28 19.305 ;
     RECT  2.16 19.575 71.28 19.845 ;
     RECT  2.16 20.115 71.28 20.385 ;
     RECT  2.16 20.655 71.28 20.925 ;
     RECT  2.16 21.195 71.28 21.465 ;
     RECT  2.16 21.735 71.28 22.005 ;
     RECT  2.16 22.275 71.28 22.545 ;
     RECT  2.16 22.815 71.28 23.085 ;
     RECT  2.16 23.355 71.28 23.625 ;
     RECT  2.16 23.895 71.28 24.165 ;
     RECT  2.16 24.435 71.28 24.705 ;
     RECT  2.16 24.975 71.28 25.245 ;
     RECT  2.16 25.515 71.28 25.785 ;
     RECT  2.16 26.055 71.28 26.325 ;
     RECT  2.16 26.595 71.28 26.865 ;
     RECT  2.16 27.135 71.28 27.405 ;
     RECT  2.16 27.675 71.28 27.945 ;
     RECT  2.16 28.215 71.28 28.485 ;
     RECT  2.16 28.755 71.28 29.025 ;
     RECT  2.16 29.295 71.28 29.565 ;
     RECT  2.16 29.835 71.28 30.105 ;
     RECT  2.16 30.375 71.28 30.645 ;
     RECT  2.16 30.915 71.28 31.185 ;
     RECT  2.16 31.455 71.28 31.725 ;
     RECT  2.16 31.995 71.28 32.265 ;
     RECT  2.16 32.535 71.28 32.805 ;
     RECT  2.16 33.075 71.28 33.345 ;
     RECT  2.16 33.615 71.28 33.885 ;
     RECT  2.16 34.155 71.28 34.425 ;
     RECT  2.16 34.695 71.28 34.965 ;
     RECT  2.16 35.235 71.28 35.505 ;
     RECT  2.16 35.775 71.28 36.045 ;
     RECT  2.16 36.315 71.28 36.585 ;
     RECT  2.16 36.855 71.28 37.125 ;
     RECT  2.16 37.395 71.28 37.665 ;
     RECT  2.16 37.935 71.28 38.205 ;
     RECT  2.16 38.475 71.28 38.745 ;
     RECT  2.16 39.015 71.28 39.285 ;
     RECT  2.16 39.555 71.28 39.825 ;
     RECT  2.16 40.095 71.28 40.365 ;
     RECT  2.16 40.635 71.28 40.905 ;
     RECT  2.16 41.175 71.28 41.445 ;
     RECT  2.16 41.715 71.28 41.985 ;
     RECT  2.16 42.255 71.28 42.525 ;
     RECT  2.16 42.795 71.28 43.065 ;
     RECT  2.16 43.335 71.28 43.605 ;
     RECT  2.16 43.875 71.28 44.145 ;
     RECT  2.16 44.415 71.28 44.685 ;
     RECT  2.16 44.955 71.28 45.225 ;
     RECT  2.16 45.495 71.28 45.765 ;
     RECT  2.16 46.035 71.28 46.305 ;
     RECT  2.16 46.575 71.28 46.845 ;
     RECT  2.16 47.115 71.28 47.385 ;
     RECT  2.16 47.655 71.28 47.925 ;
     RECT  2.16 48.195 71.28 48.465 ;
     RECT  2.16 48.735 71.28 49.005 ;
     RECT  2.16 49.275 71.28 49.545 ;
     RECT  2.16 49.815 71.28 50.085 ;
     RECT  2.16 50.355 71.28 50.625 ;
     RECT  2.16 50.895 71.28 51.165 ;
     RECT  2.16 51.435 71.28 51.705 ;
     RECT  2.16 51.975 71.28 52.245 ;
     RECT  2.16 52.515 71.28 52.785 ;
     RECT  2.16 53.055 71.28 53.325 ;
     RECT  2.16 53.595 71.28 53.865 ;
     RECT  2.16 54.135 71.28 54.405 ;
     RECT  2.16 54.675 71.28 54.945 ;
     RECT  2.16 55.215 71.28 55.485 ;
     RECT  2.16 55.755 71.28 56.025 ;
     RECT  2.16 56.295 71.28 56.565 ;
     RECT  2.16 56.835 71.28 57.105 ;
     RECT  2.16 57.375 71.28 57.645 ;
     RECT  2.16 57.915 71.28 58.185 ;
     RECT  2.16 58.455 71.28 58.725 ;
     RECT  2.16 58.995 71.28 59.265 ;
     RECT  2.16 59.535 71.28 59.805 ;
     RECT  2.16 60.075 71.28 60.345 ;
     RECT  2.16 60.615 71.28 60.885 ;
     RECT  2.16 61.155 71.28 61.425 ;
     RECT  2.16 61.695 71.28 61.965 ;
     RECT  2.16 62.235 71.28 62.505 ;
     RECT  2.16 62.775 71.28 63.045 ;
     RECT  2.16 63.315 71.28 63.585 ;
     RECT  2.16 63.855 71.28 64.125 ;
     RECT  2.16 64.395 71.28 64.665 ;
     RECT  2.16 64.935 71.28 65.205 ;
     RECT  2.16 65.475 71.28 65.745 ;
     RECT  2.16 66.015 71.28 66.285 ;
     RECT  2.16 66.555 71.28 66.825 ;
     RECT  2.16 67.095 71.28 67.365 ;
     RECT  2.16 67.635 71.28 67.905 ;
     RECT  2.16 68.175 71.28 68.445 ;
     RECT  2.16 68.715 71.28 68.985 ;
     RECT  2.16 69.255 71.28 69.525 ;
     RECT  2.16 69.795 71.28 70.065 ;
     RECT  2.16 70.335 71.28 70.605 ;
     RECT  2.16 70.875 71.28 71.145 ;
     RECT  2.16 71.415 71.28 71.685 ;
     RECT  2.16 71.955 71.28 72.225 ;
     RECT  2.16 72.495 71.28 72.765 ;
     RECT  2.16 73.035 71.28 73.305 ;
     RECT  2.16 73.575 71.28 73.845 ;
     RECT  2.16 74.115 71.28 74.385 ;
     RECT  2.16 74.655 71.28 74.925 ;
     RECT  2.16 75.195 71.28 75.465 ;
    LAYER M1 ;
     RECT  2.16 2.151 71.28 75.609 ;
    LAYER M2 ;
     RECT  0.211 37.602 2.16 37.62 ;
     RECT  2.16 2.151 2.803 75.609 ;
     RECT  2.803 2.07 3.307 75.609 ;
     RECT  3.307 2.034 3.559 75.609 ;
     RECT  3.559 1.422 6.367 75.609 ;
     RECT  3.739 0.072 7.267 0.09 ;
     RECT  7.267 0.036 8.671 0.09 ;
     RECT  6.367 0.882 8.671 75.609 ;
     RECT  8.671 0.036 9.139 75.609 ;
     RECT  9.139 0.036 11.867 75.654 ;
     RECT  11.867 0.036 13.019 75.609 ;
     RECT  13.019 1.926 13.135 75.609 ;
     RECT  13.019 0.036 13.199 0.864 ;
     RECT  13.243 76.896 13.379 76.914 ;
     RECT  13.199 0.216 14.107 0.864 ;
     RECT  13.135 1.926 14.107 75.654 ;
     RECT  14.107 0.216 14.207 75.798 ;
     RECT  14.207 0.216 14.395 75.654 ;
     RECT  14.827 76.896 14.963 76.914 ;
     RECT  14.395 0.144 15.107 75.654 ;
     RECT  15.107 1.152 15.259 75.654 ;
     RECT  15.259 1.152 15.395 75.726 ;
     RECT  15.107 0.144 15.835 0.234 ;
     RECT  15.835 0.144 16.483 0.324 ;
     RECT  15.395 1.152 16.555 75.654 ;
     RECT  16.555 1.152 17.015 75.798 ;
     RECT  16.987 76.896 17.087 76.914 ;
     RECT  16.483 0.144 17.663 0.396 ;
     RECT  17.663 0.306 18.283 0.396 ;
     RECT  17.015 1.152 18.283 75.609 ;
     RECT  18.283 0.306 18.383 75.609 ;
     RECT  18.383 0.306 18.427 0.396 ;
     RECT  18.383 1.152 18.455 75.609 ;
     RECT  18.455 1.188 18.527 75.609 ;
     RECT  18.427 0.144 18.635 0.396 ;
     RECT  18.527 1.188 19.283 1.206 ;
     RECT  19.291 1.116 19.427 1.134 ;
     RECT  18.635 0.144 19.471 0.162 ;
     RECT  19.471 0.144 19.687 0.324 ;
     RECT  18.527 1.962 19.939 75.609 ;
     RECT  19.687 0.144 20.407 0.396 ;
     RECT  20.407 0.144 20.875 0.549 ;
     RECT  20.875 0.144 20.975 0.594 ;
     RECT  20.975 0.144 21.011 0.396 ;
     RECT  21.011 0.216 21.739 0.396 ;
     RECT  19.939 1.881 21.775 75.609 ;
     RECT  21.775 1.728 21.983 75.609 ;
     RECT  21.739 0.144 22.523 0.396 ;
     RECT  21.983 1.926 23.035 75.609 ;
     RECT  23.035 1.881 23.207 75.609 ;
     RECT  23.207 1.926 23.531 75.609 ;
     RECT  22.523 0.144 23.719 0.162 ;
     RECT  23.719 0.144 23.899 0.324 ;
     RECT  23.531 1.962 24.295 75.609 ;
     RECT  24.295 1.224 24.367 75.609 ;
     RECT  23.899 0.144 24.683 0.396 ;
     RECT  24.683 0.216 25.411 0.396 ;
     RECT  24.367 1.152 25.411 75.609 ;
     RECT  25.411 0.144 25.655 75.609 ;
     RECT  25.655 1.152 26.051 75.609 ;
     RECT  26.051 2.034 26.591 75.609 ;
     RECT  25.655 0.144 27.031 0.396 ;
     RECT  26.051 1.152 27.031 1.17 ;
     RECT  27.031 0.144 27.275 1.242 ;
     RECT  27.275 1.152 27.355 1.242 ;
     RECT  26.591 2.106 27.527 75.609 ;
     RECT  27.355 1.152 27.779 1.359 ;
     RECT  27.275 0.144 28.147 0.234 ;
     RECT  27.527 2.151 28.291 75.609 ;
     RECT  28.147 0.144 29.003 0.594 ;
     RECT  28.291 1.8 29.083 75.609 ;
     RECT  29.083 1.188 29.183 75.609 ;
     RECT  29.003 0.144 29.543 0.234 ;
     RECT  29.183 1.224 29.579 1.242 ;
     RECT  29.183 2.106 29.947 75.609 ;
     RECT  29.947 1.728 30.299 75.609 ;
     RECT  30.299 2.106 30.443 75.609 ;
     RECT  29.543 0.144 30.595 0.162 ;
     RECT  30.595 0.144 30.703 0.468 ;
     RECT  30.703 0.144 31.019 0.549 ;
     RECT  31.099 1.152 31.343 1.17 ;
     RECT  31.019 0.144 31.999 0.279 ;
     RECT  31.999 0.144 32.539 0.324 ;
     RECT  32.539 0.144 32.639 1.17 ;
     RECT  32.639 0.144 32.783 0.468 ;
     RECT  32.783 0.144 33.691 0.162 ;
     RECT  30.443 2.151 33.907 75.609 ;
     RECT  33.691 0.144 33.979 0.198 ;
     RECT  33.979 0.144 34.267 0.234 ;
     RECT  33.907 2.106 34.267 75.609 ;
     RECT  34.267 0.144 34.303 0.324 ;
     RECT  34.303 0.036 34.403 0.324 ;
     RECT  34.403 0.036 35.015 0.234 ;
     RECT  35.015 0.036 35.159 0.198 ;
     RECT  35.159 0.036 35.231 0.162 ;
     RECT  34.267 1.728 35.447 75.609 ;
     RECT  35.447 1.8 35.627 75.609 ;
     RECT  35.231 0.036 35.987 0.054 ;
     RECT  36.031 0.144 36.607 0.234 ;
     RECT  36.607 0.144 37.319 0.594 ;
     RECT  37.319 0.144 38.047 0.198 ;
     RECT  38.047 0.144 38.903 0.279 ;
     RECT  38.903 0.216 39.011 0.279 ;
     RECT  39.011 0.261 39.047 0.279 ;
     RECT  35.627 2.151 40.171 75.609 ;
     RECT  40.171 1.728 40.343 75.609 ;
     RECT  40.063 0.144 40.747 0.162 ;
     RECT  40.343 1.998 41.279 75.609 ;
     RECT  40.747 0.144 41.531 0.324 ;
     RECT  41.531 0.144 42.143 0.234 ;
     RECT  42.143 0.144 43.519 0.162 ;
     RECT  43.519 0.144 43.655 0.549 ;
     RECT  43.655 0.144 44.087 0.198 ;
     RECT  44.087 0.144 44.375 0.162 ;
     RECT  41.279 2.151 45.211 75.609 ;
     RECT  45.175 0.144 45.283 0.162 ;
     RECT  45.211 1.728 45.635 75.609 ;
     RECT  45.283 0.144 46.031 0.234 ;
     RECT  46.031 0.144 47.515 0.162 ;
     RECT  47.515 0.144 48.199 0.198 ;
     RECT  48.199 0.144 48.703 0.234 ;
     RECT  48.703 0.144 48.811 0.396 ;
     RECT  45.635 2.151 49.243 75.609 ;
     RECT  48.811 0.144 49.343 0.594 ;
     RECT  49.243 2.106 49.343 75.609 ;
     RECT  49.343 0.144 49.523 0.396 ;
     RECT  49.523 0.144 49.919 0.324 ;
     RECT  49.919 0.144 49.955 0.162 ;
     RECT  49.675 1.152 50.027 1.242 ;
     RECT  50.027 1.152 50.099 1.17 ;
     RECT  49.343 2.151 50.467 75.609 ;
     RECT  50.827 0.144 50.935 0.162 ;
     RECT  50.935 0.144 51.035 0.234 ;
     RECT  51.035 0.144 51.215 0.162 ;
     RECT  50.863 1.152 51.331 1.17 ;
     RECT  50.467 2.106 51.331 75.609 ;
     RECT  51.331 1.152 51.827 75.609 ;
     RECT  51.827 1.152 52.691 1.242 ;
     RECT  52.691 1.152 52.799 1.17 ;
     RECT  52.663 0.144 52.979 0.162 ;
     RECT  53.707 0.144 54.139 0.162 ;
     RECT  54.139 0.144 54.571 0.234 ;
     RECT  54.571 0.144 56.443 0.324 ;
     RECT  51.827 2.151 56.515 75.609 ;
     RECT  56.515 1.728 57.631 75.609 ;
     RECT  56.443 0.144 58.171 0.594 ;
     RECT  57.631 1.53 58.171 75.609 ;
     RECT  58.171 0.144 59.251 75.609 ;
     RECT  59.251 0.036 60.143 75.609 ;
     RECT  60.143 1.422 60.979 75.609 ;
     RECT  60.143 0.036 61.015 0.594 ;
     RECT  60.979 1.341 61.015 75.609 ;
     RECT  61.015 0.036 61.079 75.609 ;
     RECT  61.079 0.036 62.347 0.324 ;
     RECT  61.079 1.152 62.627 75.609 ;
     RECT  62.347 0.036 63.427 0.36 ;
     RECT  62.627 1.26 63.427 75.609 ;
     RECT  63.427 0.036 63.743 75.609 ;
     RECT  63.743 0.036 66.695 0.594 ;
     RECT  63.743 1.422 66.839 75.609 ;
     RECT  66.695 0.036 67.775 0.234 ;
     RECT  66.839 1.494 68.747 75.609 ;
     RECT  67.775 0.144 68.783 0.234 ;
     RECT  68.783 0.216 69.107 0.234 ;
     RECT  68.747 2.151 71.28 75.609 ;
    LAYER M3 ;
     RECT  66.708 0.067 66.726 0.103 ;
     RECT  67.752 0.031 67.77 0.103 ;
     RECT  9.36 0.067 9.378 0.108 ;
     RECT  13.176 0.031 13.194 0.108 ;
     RECT  34.308 0.031 34.326 0.108 ;
     RECT  35.964 0.031 35.982 0.108 ;
     RECT  59.256 0.031 59.274 0.108 ;
     RECT  62.1 0.067 62.118 0.108 ;
     RECT  7.272 0.031 7.29 0.139 ;
     RECT  66.6 0.103 67.77 0.187 ;
     RECT  68.76 0.139 68.778 0.211 ;
     RECT  9 0.108 64.206 0.301 ;
     RECT  66.276 0.187 67.77 0.301 ;
     RECT  8.964 0.301 64.206 0.373 ;
     RECT  6.84 0.139 7.29 0.461 ;
     RECT  66.132 0.301 67.77 0.811 ;
     RECT  68.76 0.211 69.102 0.811 ;
     RECT  5.328 0.811 5.346 0.859 ;
     RECT  5.328 0.859 6.03 0.877 ;
     RECT  66.132 0.811 69.102 0.907 ;
     RECT  8.676 0.373 64.206 0.955 ;
     RECT  65.844 0.907 69.102 0.955 ;
     RECT  5.328 0.877 6.39 1.387 ;
     RECT  7.272 0.461 7.29 1.387 ;
     RECT  2.988 0.139 3.006 1.417 ;
     RECT  3.744 0.067 3.762 1.417 ;
     RECT  8.244 0.955 64.206 1.453 ;
     RECT  5.328 1.387 7.29 1.921 ;
     RECT  8.244 1.453 64.35 1.957 ;
     RECT  65.268 0.955 69.102 1.957 ;
     RECT  2.988 1.417 3.762 1.993 ;
     RECT  8.244 1.957 69.102 1.993 ;
     RECT  5.148 1.921 7.29 2.029 ;
     RECT  8.1 1.993 69.102 2.029 ;
     RECT  2.988 1.993 4.41 2.065 ;
     RECT  2.808 2.065 4.41 2.101 ;
     RECT  5.148 2.029 69.102 2.101 ;
     RECT  2.808 2.101 69.102 2.143 ;
     RECT  2.415 2.143 69.102 2.335 ;
     RECT  2.415 2.335 69.426 2.371 ;
     RECT  2.415 2.371 69.858 2.641 ;
     RECT  70.92 2.641 70.938 2.911 ;
     RECT  2.376 2.641 70.146 3.073 ;
     RECT  70.92 2.911 70.974 3.073 ;
     RECT  2.376 3.073 70.974 3.109 ;
     RECT  2.34 3.109 70.974 3.271 ;
     RECT  2.304 3.271 70.974 3.379 ;
     RECT  2.304 3.379 71.01 3.569 ;
     RECT  2.304 3.569 70.974 4.217 ;
     RECT  2.304 4.217 69.93 4.919 ;
     RECT  2.34 4.919 65.106 4.991 ;
     RECT  65.844 4.919 69.93 5.029 ;
     RECT  70.776 4.217 70.974 5.029 ;
     RECT  65.844 5.029 70.974 5.071 ;
     RECT  2.415 4.991 65.106 5.881 ;
     RECT  65.844 5.071 71.01 5.881 ;
     RECT  2.415 5.881 71.01 5.999 ;
     RECT  70.488 5.999 71.01 6.151 ;
     RECT  2.415 5.999 69.714 6.317 ;
     RECT  2.415 6.317 67.914 6.379 ;
     RECT  68.688 6.317 69.714 6.539 ;
     RECT  70.488 6.151 71.046 6.961 ;
     RECT  2.376 6.379 67.914 7.195 ;
     RECT  68.688 6.539 69.534 7.195 ;
     RECT  2.376 7.195 69.534 8.005 ;
     RECT  70.272 6.961 71.046 8.005 ;
     RECT  2.376 8.005 71.046 8.041 ;
     RECT  2.34 8.041 71.046 8.339 ;
     RECT  2.34 8.339 70.938 8.699 ;
     RECT  2.415 8.699 70.938 8.771 ;
     RECT  2.415 8.771 70.794 9.625 ;
     RECT  2.376 9.625 70.794 10.049 ;
     RECT  2.376 10.049 70.758 10.319 ;
     RECT  2.415 10.319 70.758 11.011 ;
     RECT  2.415 11.011 70.794 11.407 ;
     RECT  2.415 11.407 70.974 11.939 ;
     RECT  2.415 11.939 70.902 12.361 ;
     RECT  2.376 12.361 70.902 13.405 ;
     RECT  2.376 13.405 71.01 13.441 ;
     RECT  2.376 13.441 71.154 13.559 ;
     RECT  2.376 13.559 71.01 13.667 ;
     RECT  2.376 13.667 70.902 14.237 ;
     RECT  2.415 14.237 70.902 15.601 ;
     RECT  2.304 15.601 70.902 16.069 ;
     RECT  2.304 16.069 71.01 17.077 ;
     RECT  2.304 17.077 71.082 20.551 ;
     RECT  2.232 20.551 71.082 20.921 ;
     RECT  2.304 20.921 71.082 21.659 ;
     RECT  2.376 21.659 71.082 21.767 ;
     RECT  2.376 21.767 71.046 22.739 ;
     RECT  2.415 22.739 71.046 23.701 ;
     RECT  2.376 23.701 71.046 24.461 ;
     RECT  2.415 24.461 71.046 24.979 ;
     RECT  2.415 24.979 71.082 25.213 ;
     RECT  2.415 25.213 71.118 25.709 ;
     RECT  2.415 25.709 71.082 27.599 ;
     RECT  20.448 27.599 71.082 28.507 ;
     RECT  2.415 27.599 19.674 28.561 ;
     RECT  20.412 28.507 71.082 28.561 ;
     RECT  2.415 28.561 71.082 28.949 ;
     RECT  59.112 28.949 71.082 29.371 ;
     RECT  2.415 28.949 58.374 30.037 ;
     RECT  59.112 29.371 71.226 30.037 ;
     RECT  2.415 30.037 71.226 30.415 ;
     RECT  2.412 30.415 71.226 30.701 ;
     RECT  2.415 30.701 71.226 32.459 ;
     RECT  2.415 32.459 65.214 32.729 ;
     RECT  9.072 32.729 64.962 32.837 ;
     RECT  2.415 32.729 8.334 32.999 ;
     RECT  20.592 32.837 64.962 33.035 ;
     RECT  3.456 32.999 8.334 33.071 ;
     RECT  20.7 33.035 64.962 33.071 ;
     RECT  3.456 33.071 8.298 33.305 ;
     RECT  20.772 33.071 64.962 33.305 ;
     RECT  58.932 33.305 64.962 33.719 ;
     RECT  4.14 33.305 8.298 33.925 ;
     RECT  9.072 32.837 19.674 33.925 ;
     RECT  4.14 33.925 19.674 34.087 ;
     RECT  58.968 33.719 64.962 34.231 ;
     RECT  58.968 34.231 65.178 34.349 ;
     RECT  58.968 34.349 65.034 34.465 ;
     RECT  65.988 32.459 71.226 34.501 ;
     RECT  4.14 34.087 20.034 34.627 ;
     RECT  20.808 33.305 58.05 34.663 ;
     RECT  58.932 34.465 65.034 34.889 ;
     RECT  4.032 34.627 20.034 35.195 ;
     RECT  20.808 34.663 58.158 35.311 ;
     RECT  59.364 34.889 65.034 35.311 ;
     RECT  65.952 34.501 71.226 35.311 ;
     RECT  59.364 35.311 71.226 35.357 ;
     RECT  4.464 35.195 20.034 35.429 ;
     RECT  61.596 35.357 71.226 35.501 ;
     RECT  4.464 35.429 5.13 35.573 ;
     RECT  61.596 35.501 71.154 35.699 ;
     RECT  5.976 35.429 20.034 35.843 ;
     RECT  19.836 35.843 20.034 35.851 ;
     RECT  20.808 35.311 58.482 35.851 ;
     RECT  4.464 35.573 5.022 35.879 ;
     RECT  59.364 35.357 60.858 36.121 ;
     RECT  61.596 35.699 71.082 36.121 ;
     RECT  4.464 35.879 4.95 36.239 ;
     RECT  59.364 36.121 71.082 36.275 ;
     RECT  60.984 36.275 71.082 36.311 ;
     RECT  19.836 35.851 58.626 36.355 ;
     RECT  59.364 36.275 60.174 36.355 ;
     RECT  4.464 36.239 4.842 36.509 ;
     RECT  19.836 36.355 60.174 36.509 ;
     RECT  4.464 36.509 4.698 36.553 ;
     RECT  5.976 35.843 18.897 36.589 ;
     RECT  4.068 36.553 4.698 36.895 ;
     RECT  2.415 32.999 2.697 36.931 ;
     RECT  3.996 36.895 4.698 36.931 ;
     RECT  5.76 36.589 18.897 37.021 ;
     RECT  19.836 36.509 57.474 37.021 ;
     RECT  2.415 36.931 4.698 37.049 ;
     RECT  58.284 36.509 60.174 37.049 ;
     RECT  5.76 37.021 57.474 37.085 ;
     RECT  58.284 37.049 58.698 37.085 ;
     RECT  59.76 37.049 60.174 37.201 ;
     RECT  5.868 37.085 57.474 37.291 ;
     RECT  58.284 37.085 58.662 37.291 ;
     RECT  5.868 37.291 58.662 37.319 ;
     RECT  59.76 37.201 60.246 37.435 ;
     RECT  60.984 36.311 71.01 37.435 ;
     RECT  3.708 37.049 4.698 37.471 ;
     RECT  5.976 37.319 58.662 37.589 ;
     RECT  5.976 37.589 58.59 37.625 ;
     RECT  59.76 37.435 71.01 37.625 ;
     RECT  2.415 37.049 2.697 37.741 ;
     RECT  3.708 37.471 4.914 37.831 ;
     RECT  2.304 37.741 2.697 37.895 ;
     RECT  0.216 37.597 0.234 37.901 ;
     RECT  3.6 37.831 4.914 37.939 ;
     RECT  2.415 37.895 2.697 37.975 ;
     RECT  2.415 37.975 2.754 38.005 ;
     RECT  3.564 37.939 4.914 38.005 ;
     RECT  59.832 37.625 71.01 38.011 ;
     RECT  5.976 37.625 58.266 38.371 ;
     RECT  2.415 38.005 4.914 38.515 ;
     RECT  2.415 38.515 5.166 38.551 ;
     RECT  5.976 38.371 58.77 38.551 ;
     RECT  59.832 38.011 71.154 38.551 ;
     RECT  2.415 38.551 58.914 38.713 ;
     RECT  2.34 38.713 58.914 38.765 ;
     RECT  0.216 38.875 0.234 39.005 ;
     RECT  2.415 38.765 58.914 39.011 ;
     RECT  6.12 39.011 58.914 39.181 ;
     RECT  59.688 38.551 71.154 39.181 ;
     RECT  6.12 39.181 71.154 39.245 ;
     RECT  6.372 39.245 71.154 39.317 ;
     RECT  6.372 39.317 71.082 39.479 ;
     RECT  6.372 39.479 6.39 39.677 ;
     RECT  7.164 39.479 71.082 39.749 ;
     RECT  2.415 39.011 4.914 39.773 ;
     RECT  7.164 39.749 70.938 39.785 ;
     RECT  7.164 39.785 70.902 40.055 ;
     RECT  3.744 39.773 4.914 40.441 ;
     RECT  3.744 40.441 5.022 40.445 ;
     RECT  7.776 40.055 70.902 40.559 ;
     RECT  4.14 40.445 5.022 40.711 ;
     RECT  7.776 40.559 59.238 40.801 ;
     RECT  4.14 40.711 5.166 40.829 ;
     RECT  60.012 40.559 70.902 40.865 ;
     RECT  60.12 40.865 70.902 40.945 ;
     RECT  7.596 40.801 59.238 41.021 ;
     RECT  60.12 40.945 70.938 41.179 ;
     RECT  4.284 40.829 5.166 41.213 ;
     RECT  7.596 41.021 21.582 41.243 ;
     RECT  4.464 41.213 5.166 41.251 ;
     RECT  60.12 41.179 71.01 41.639 ;
     RECT  22.356 41.021 59.238 41.791 ;
     RECT  60.12 41.639 70.938 41.791 ;
     RECT  7.776 41.243 21.582 41.881 ;
     RECT  22.356 41.791 59.346 41.881 ;
     RECT  4.464 41.251 5.526 42.025 ;
     RECT  4.392 42.025 5.526 42.061 ;
     RECT  7.776 41.881 59.346 42.061 ;
     RECT  60.084 41.791 70.938 42.061 ;
     RECT  7.776 42.061 70.938 42.179 ;
     RECT  4.392 42.061 5.814 42.323 ;
     RECT  9.684 42.179 70.938 42.323 ;
     RECT  4.392 42.323 5.238 42.331 ;
     RECT  9.792 42.323 70.938 42.359 ;
     RECT  7.776 42.179 8.91 42.485 ;
     RECT  4.356 42.331 5.238 42.529 ;
     RECT  10.26 42.359 70.938 42.601 ;
     RECT  10.26 42.601 70.974 42.719 ;
     RECT  45.36 42.719 70.974 42.989 ;
     RECT  59.544 42.989 70.974 43.097 ;
     RECT  10.26 42.719 44.586 43.231 ;
     RECT  59.544 43.097 70.938 43.259 ;
     RECT  4.176 42.529 5.238 43.331 ;
     RECT  4.428 43.331 5.238 43.411 ;
     RECT  4.428 43.411 5.382 43.565 ;
     RECT  9.972 43.231 44.586 43.609 ;
     RECT  45.36 42.989 58.806 43.609 ;
     RECT  9.972 43.609 58.806 43.771 ;
     RECT  59.544 43.259 70.83 43.771 ;
     RECT  4.716 43.565 5.382 43.843 ;
     RECT  7.815 42.485 8.91 43.879 ;
     RECT  7.815 43.879 9.126 43.951 ;
     RECT  9.936 43.771 70.83 43.951 ;
     RECT  7.815 43.951 70.83 44.339 ;
     RECT  4.716 43.843 6.066 44.419 ;
     RECT  7.815 44.339 45.99 44.447 ;
     RECT  4.716 44.419 6.282 44.477 ;
     RECT  46.8 44.339 70.83 44.491 ;
     RECT  11.412 44.447 45.99 44.753 ;
     RECT  5.364 44.477 6.282 44.761 ;
     RECT  7.815 44.447 10.638 44.879 ;
     RECT  11.412 44.753 15.426 44.879 ;
     RECT  16.236 44.753 45.99 45.023 ;
     RECT  42.624 45.023 45.99 45.149 ;
     RECT  11.592 44.879 15.426 45.293 ;
     RECT  5.364 44.761 6.534 45.301 ;
     RECT  16.236 45.023 41.886 45.329 ;
     RECT  7.815 44.879 10.458 45.419 ;
     RECT  12.276 45.293 15.426 45.419 ;
     RECT  39.6 45.329 41.886 45.455 ;
     RECT  46.8 44.491 71.154 45.491 ;
     RECT  5.364 45.301 6.714 45.527 ;
     RECT  42.624 45.149 45.897 45.527 ;
     RECT  5.58 45.527 6.714 45.571 ;
     RECT  5.58 45.571 6.894 45.581 ;
     RECT  7.815 45.419 10.422 45.725 ;
     RECT  55.368 45.491 71.154 45.797 ;
     RECT  6.12 45.581 6.894 45.841 ;
     RECT  13.176 45.419 15.426 45.841 ;
     RECT  39.636 45.455 41.886 45.841 ;
     RECT  42.624 45.527 44.226 45.841 ;
     RECT  7.815 45.725 10.386 45.959 ;
     RECT  7.815 45.959 10.314 45.995 ;
     RECT  39.636 45.841 44.226 46.109 ;
     RECT  6.12 45.841 6.966 46.237 ;
     RECT  46.8 45.491 54.522 46.309 ;
     RECT  55.368 45.797 70.758 46.309 ;
     RECT  13.176 45.841 15.498 46.345 ;
     RECT  16.236 45.329 38.754 46.345 ;
     RECT  6.12 46.237 7.002 46.381 ;
     RECT  7.815 45.995 9.882 46.381 ;
     RECT  39.924 46.109 44.226 46.381 ;
     RECT  45.036 45.527 45.897 46.381 ;
     RECT  12.276 45.419 12.438 46.499 ;
     RECT  6.12 46.381 9.882 46.535 ;
     RECT  12.276 46.499 12.294 46.535 ;
     RECT  46.8 46.309 70.758 46.535 ;
     RECT  13.176 46.345 38.754 46.579 ;
     RECT  46.8 46.535 57.978 46.643 ;
     RECT  58.716 46.535 70.758 46.651 ;
     RECT  13.176 46.579 38.898 46.741 ;
     RECT  58.716 46.651 70.938 46.813 ;
     RECT  13.176 46.741 39.006 46.885 ;
     RECT  39.924 46.381 45.897 46.921 ;
     RECT  46.8 46.643 57.942 47.011 ;
     RECT  58.716 46.813 71.082 47.039 ;
     RECT  58.716 47.039 70.938 47.075 ;
     RECT  39.924 46.921 45.954 47.083 ;
     RECT  46.764 47.011 57.942 47.083 ;
     RECT  58.716 47.075 70.83 47.111 ;
     RECT  6.12 46.535 9.738 47.281 ;
     RECT  5.688 47.281 9.738 47.317 ;
     RECT  13.176 46.885 39.078 47.389 ;
     RECT  39.924 47.083 57.942 47.389 ;
     RECT  13.176 47.389 57.942 47.461 ;
     RECT  58.716 47.111 70.614 47.461 ;
     RECT  5.148 47.317 9.738 47.651 ;
     RECT  5.148 47.651 8.946 47.849 ;
     RECT  9.72 47.651 9.738 47.849 ;
     RECT  13.176 47.461 70.614 47.857 ;
     RECT  7.815 47.849 8.802 47.885 ;
     RECT  13.176 47.857 70.722 47.885 ;
     RECT  5.148 47.849 7.002 47.893 ;
     RECT  7.815 47.885 8.406 48.029 ;
     RECT  13.215 47.885 70.722 48.119 ;
     RECT  13.215 48.119 70.578 48.155 ;
     RECT  13.215 48.155 70.11 48.191 ;
     RECT  13.215 48.191 69.966 48.389 ;
     RECT  13.215 48.389 39.006 48.413 ;
     RECT  39.78 48.389 53.694 48.425 ;
     RECT  40.068 48.425 53.694 48.461 ;
     RECT  13.215 48.413 13.842 48.509 ;
     RECT  13.215 48.509 13.662 48.659 ;
     RECT  5.004 47.893 7.002 48.811 ;
     RECT  7.815 48.029 8.097 48.811 ;
     RECT  54.468 48.389 69.966 48.839 ;
     RECT  5.004 48.811 8.097 48.845 ;
     RECT  14.652 48.413 39.006 48.929 ;
     RECT  54.468 48.839 68.814 48.929 ;
     RECT  69.552 48.839 69.966 48.929 ;
     RECT  5.256 48.845 8.097 48.965 ;
     RECT  40.068 48.461 53.622 48.965 ;
     RECT  69.732 48.929 69.822 48.965 ;
     RECT  40.068 48.965 49.554 49.001 ;
     RECT  69.804 48.965 69.822 49.001 ;
     RECT  50.292 48.965 53.622 49.199 ;
     RECT  14.868 48.929 39.006 49.207 ;
     RECT  40.068 49.001 49.518 49.207 ;
     RECT  50.364 49.199 53.622 49.351 ;
     RECT  54.468 48.929 68.778 49.351 ;
     RECT  5.796 48.965 5.886 49.469 ;
     RECT  50.364 49.351 68.778 49.505 ;
     RECT  14.868 49.207 49.518 49.613 ;
     RECT  14.868 49.613 18.897 49.649 ;
     RECT  13.215 48.659 13.554 49.747 ;
     RECT  14.868 49.649 16.182 49.747 ;
     RECT  19.656 49.613 49.518 49.747 ;
     RECT  50.58 49.505 68.778 49.847 ;
     RECT  50.58 49.847 53.154 49.919 ;
     RECT  53.892 49.847 68.778 50.009 ;
     RECT  16.992 49.649 18.897 50.045 ;
     RECT  13.215 49.747 16.182 50.053 ;
     RECT  13.104 50.053 16.182 50.125 ;
     RECT  10.836 50.089 10.854 50.251 ;
     RECT  19.656 49.747 49.626 50.323 ;
     RECT  54.144 50.009 68.778 50.323 ;
     RECT  50.58 49.919 53.118 50.395 ;
     RECT  5.868 49.469 5.886 50.431 ;
     RECT  6.624 48.965 8.097 50.431 ;
     RECT  9.936 50.251 9.954 50.431 ;
     RECT  10.8 50.251 10.854 50.431 ;
     RECT  12.96 50.125 16.182 50.431 ;
     RECT  16.992 50.045 17.154 50.431 ;
     RECT  18.108 50.045 18.897 50.431 ;
     RECT  19.656 50.323 49.698 50.431 ;
     RECT  50.544 50.395 53.118 50.431 ;
     RECT  5.724 50.431 5.886 50.521 ;
     RECT  6.624 50.431 8.37 50.521 ;
     RECT  9.576 50.431 9.954 50.549 ;
     RECT  10.8 50.431 17.154 50.549 ;
     RECT  54.144 50.323 68.994 50.549 ;
     RECT  10.8 50.549 16.218 50.585 ;
     RECT  10.8 50.585 16.11 50.621 ;
     RECT  9.576 50.549 9.882 50.629 ;
     RECT  54.144 50.549 68.67 50.657 ;
     RECT  54.144 50.657 66.186 50.693 ;
     RECT  9.324 50.629 9.882 50.701 ;
     RECT  18.108 50.431 53.118 50.729 ;
     RECT  5.724 50.521 8.37 50.791 ;
     RECT  18.108 50.729 30.366 50.791 ;
     RECT  17.028 50.549 17.154 50.819 ;
     RECT  5.616 50.791 8.37 50.827 ;
     RECT  9.108 50.701 9.882 50.827 ;
     RECT  17.1 50.819 17.154 50.863 ;
     RECT  31.392 50.729 53.118 50.923 ;
     RECT  54.144 50.693 65.826 50.923 ;
     RECT  67.215 50.657 68.67 50.999 ;
     RECT  5.616 50.827 9.882 51.089 ;
     RECT  6.084 51.089 9.882 51.125 ;
     RECT  18.072 50.791 30.366 51.133 ;
     RECT  31.392 50.923 65.826 51.161 ;
     RECT  31.392 51.161 65.79 51.233 ;
     RECT  11.16 50.621 16.11 51.331 ;
     RECT  68.4 50.999 68.67 51.359 ;
     RECT  18 51.133 30.366 51.395 ;
     RECT  68.4 51.359 68.418 51.395 ;
     RECT  31.392 51.233 64.638 51.467 ;
     RECT  11.16 51.331 16.182 51.475 ;
     RECT  10.728 51.475 16.182 51.499 ;
     RECT  17.1 50.863 17.19 51.511 ;
     RECT  18 51.395 22.914 51.511 ;
     RECT  31.392 51.467 64.53 51.511 ;
     RECT  69.444 51.451 69.462 51.539 ;
     RECT  65.412 51.233 65.79 51.629 ;
     RECT  23.724 51.395 30.366 51.635 ;
     RECT  65.412 51.629 65.646 51.665 ;
     RECT  29.124 51.635 30.366 51.673 ;
     RECT  17.1 51.511 22.914 51.677 ;
     RECT  10.728 51.499 16.29 51.781 ;
     RECT  17.1 51.677 20.646 51.781 ;
     RECT  6.084 51.125 8.91 51.883 ;
     RECT  9.864 51.125 9.882 51.883 ;
     RECT  10.728 51.781 20.646 51.883 ;
     RECT  29.124 51.673 30.438 51.883 ;
     RECT  31.356 51.511 64.53 51.883 ;
     RECT  29.124 51.883 64.53 51.899 ;
     RECT  6.084 51.883 9.882 51.907 ;
     RECT  10.62 51.883 20.646 51.907 ;
     RECT  6.084 51.907 20.646 52.043 ;
     RECT  21.384 51.677 22.914 52.141 ;
     RECT  23.724 51.635 28.386 52.141 ;
     RECT  6.336 52.043 20.646 52.205 ;
     RECT  65.304 52.051 65.322 52.241 ;
     RECT  29.124 51.899 64.494 52.349 ;
     RECT  21.384 52.141 28.386 52.411 ;
     RECT  29.124 52.349 63.522 52.411 ;
     RECT  6.624 52.205 20.646 52.439 ;
     RECT  21.384 52.411 63.522 52.445 ;
     RECT  64.332 52.349 64.494 52.445 ;
     RECT  6.624 52.439 9.018 52.547 ;
     RECT  21.384 52.445 62.262 52.619 ;
     RECT  48.996 52.619 62.262 52.709 ;
     RECT  63.072 52.445 63.522 52.709 ;
     RECT  48.996 52.709 62.154 52.745 ;
     RECT  63.216 52.709 63.378 52.745 ;
     RECT  63.216 52.745 63.306 52.781 ;
     RECT  64.476 52.445 64.494 52.853 ;
     RECT  21.384 52.619 48.15 52.979 ;
     RECT  63.216 52.781 63.234 52.979 ;
     RECT  9.756 52.439 20.646 52.981 ;
     RECT  21.384 52.979 42.822 52.981 ;
     RECT  48.996 52.745 62.097 53.051 ;
     RECT  48.996 53.051 59.49 53.123 ;
     RECT  60.444 53.051 62.097 53.249 ;
     RECT  6.768 52.547 9.018 53.401 ;
     RECT  9.756 52.981 42.822 53.401 ;
     RECT  6.768 53.401 42.822 53.467 ;
     RECT  4.86 53.365 4.878 53.491 ;
     RECT  43.56 52.979 48.15 53.491 ;
     RECT  48.996 53.123 59.382 53.491 ;
     RECT  43.56 53.491 59.382 53.519 ;
     RECT  60.516 53.249 60.534 53.519 ;
     RECT  6.264 53.467 42.822 53.555 ;
     RECT  4.788 53.491 4.878 53.563 ;
     RECT  58.716 53.519 59.382 53.591 ;
     RECT  4.536 53.563 4.878 53.671 ;
     RECT  6.264 53.555 31.302 53.797 ;
     RECT  32.256 53.555 42.822 53.833 ;
     RECT  43.56 53.519 57.618 53.833 ;
     RECT  4.428 53.671 4.878 53.869 ;
     RECT  5.868 53.797 31.302 53.869 ;
     RECT  32.256 53.833 57.618 53.885 ;
     RECT  59.04 53.591 59.382 53.897 ;
     RECT  33.336 53.885 57.618 53.969 ;
     RECT  3.564 53.905 3.582 54.031 ;
     RECT  59.04 53.897 59.13 54.059 ;
     RECT  33.336 53.969 52.362 54.095 ;
     RECT  59.04 54.059 59.058 54.095 ;
     RECT  2.415 39.773 2.697 54.139 ;
     RECT  3.42 54.031 3.582 54.139 ;
     RECT  4.428 53.869 31.302 54.301 ;
     RECT  2.415 54.139 3.582 54.329 ;
     RECT  32.256 53.885 32.562 54.409 ;
     RECT  4.428 54.301 31.374 54.445 ;
     RECT  3.492 54.329 3.582 54.481 ;
     RECT  4.392 54.445 31.374 54.481 ;
     RECT  53.1 53.969 57.618 54.481 ;
     RECT  3.492 54.481 31.374 54.509 ;
     RECT  12.6 54.509 31.374 54.607 ;
     RECT  32.22 54.409 32.562 54.607 ;
     RECT  33.336 54.095 35.55 54.607 ;
     RECT  3.492 54.509 11.862 54.635 ;
     RECT  12.6 54.607 35.55 54.841 ;
     RECT  36.36 54.095 52.362 54.841 ;
     RECT  53.1 54.481 57.798 54.841 ;
     RECT  3.636 54.635 11.862 55.255 ;
     RECT  12.6 54.841 57.798 55.255 ;
     RECT  3.636 55.255 57.798 55.675 ;
     RECT  3.492 55.675 57.798 55.679 ;
     RECT  3.492 55.679 43.578 55.715 ;
     RECT  3.492 55.715 33.102 55.853 ;
     RECT  32.292 55.853 33.102 55.949 ;
     RECT  32.616 55.949 33.102 56.021 ;
     RECT  32.688 56.021 33.102 56.129 ;
     RECT  44.316 55.679 57.798 56.155 ;
     RECT  44.316 56.155 58.014 56.219 ;
     RECT  3.492 55.853 31.482 56.363 ;
     RECT  33.84 55.715 43.578 56.569 ;
     RECT  44.316 56.219 57.798 56.569 ;
     RECT  32.796 56.129 33.102 56.582 ;
     RECT  33.84 56.569 57.798 56.582 ;
     RECT  32.796 56.582 57.798 56.633 ;
     RECT  32.796 56.633 57.726 56.759 ;
     RECT  32.796 56.759 38.07 56.869 ;
     RECT  3.96 56.363 31.482 57.019 ;
     RECT  32.328 56.869 38.07 57.019 ;
     RECT  3.96 57.019 38.07 57.335 ;
     RECT  34.272 57.335 38.07 57.577 ;
     RECT  38.844 56.759 57.726 57.577 ;
     RECT  3.96 57.335 33.498 57.685 ;
     RECT  34.272 57.577 57.726 57.721 ;
     RECT  34.272 57.721 57.798 57.811 ;
     RECT  34.272 57.811 57.942 57.875 ;
     RECT  34.38 57.875 57.942 57.991 ;
     RECT  3.888 57.685 33.498 58.081 ;
     RECT  3.852 58.081 33.498 58.153 ;
     RECT  3.816 58.153 33.498 58.415 ;
     RECT  34.38 57.991 58.05 58.657 ;
     RECT  33.48 58.415 33.498 58.693 ;
     RECT  34.344 58.657 58.05 58.693 ;
     RECT  33.48 58.693 58.05 58.721 ;
     RECT  33.624 58.721 58.05 58.793 ;
     RECT  3.816 58.415 32.67 58.955 ;
     RECT  33.624 58.793 54.522 59.027 ;
     RECT  3.816 58.955 9.954 59.035 ;
     RECT  33.624 59.027 52.47 59.063 ;
     RECT  53.28 59.027 54.522 59.063 ;
     RECT  3.78 59.035 9.954 59.071 ;
     RECT  33.624 59.063 52.254 59.261 ;
     RECT  55.44 58.793 58.05 59.261 ;
     RECT  2.415 54.329 2.697 59.305 ;
     RECT  3.456 59.071 9.954 59.305 ;
     RECT  56.232 59.261 58.05 59.341 ;
     RECT  55.44 59.261 55.458 59.459 ;
     RECT  10.728 58.955 32.67 59.467 ;
     RECT  33.624 59.261 46.17 59.467 ;
     RECT  10.728 59.467 46.17 59.531 ;
     RECT  2.415 59.305 9.954 59.809 ;
     RECT  10.728 59.531 37.674 59.809 ;
     RECT  2.415 59.809 37.674 59.837 ;
     RECT  53.388 59.063 54.522 59.845 ;
     RECT  55.296 59.605 55.422 59.845 ;
     RECT  3.852 59.837 37.674 59.885 ;
     RECT  10.728 59.885 37.674 59.909 ;
     RECT  38.592 59.531 46.17 60.115 ;
     RECT  46.98 59.261 52.254 60.115 ;
     RECT  59.58 60.115 59.598 60.151 ;
     RECT  10.728 59.909 37.638 60.269 ;
     RECT  38.592 60.115 52.254 60.277 ;
     RECT  53.028 59.845 55.422 60.277 ;
     RECT  59.292 60.151 59.598 60.283 ;
     RECT  59.292 60.283 60.102 60.377 ;
     RECT  38.592 60.277 55.422 60.385 ;
     RECT  56.232 59.341 58.41 60.385 ;
     RECT  59.328 60.377 60.102 60.385 ;
     RECT  59.328 60.385 60.498 60.421 ;
     RECT  38.412 60.385 55.422 60.511 ;
     RECT  56.196 60.385 58.41 60.511 ;
     RECT  10.728 60.269 37.53 60.539 ;
     RECT  3.852 59.885 9.954 60.719 ;
     RECT  3.888 60.719 9.954 60.781 ;
     RECT  10.728 60.539 12.33 60.781 ;
     RECT  13.104 60.539 37.53 60.809 ;
     RECT  59.328 60.421 61.038 60.809 ;
     RECT  3.888 60.781 12.33 60.845 ;
     RECT  61.02 60.809 61.038 60.881 ;
     RECT  38.412 60.511 58.41 61.123 ;
     RECT  59.328 60.809 60.282 61.123 ;
     RECT  13.215 60.809 37.53 61.159 ;
     RECT  38.412 61.123 60.282 61.159 ;
     RECT  3.996 60.845 12.33 61.349 ;
     RECT  61.815 53.249 62.097 61.465 ;
     RECT  61.38 61.465 62.097 61.501 ;
     RECT  13.215 61.159 60.282 61.529 ;
     RECT  36.756 61.529 60.282 61.531 ;
     RECT  4.572 61.349 12.33 61.663 ;
     RECT  13.215 61.529 36.018 61.663 ;
     RECT  4.572 61.663 36.018 61.889 ;
     RECT  14.544 61.889 36.018 61.925 ;
     RECT  36.756 61.531 60.426 61.997 ;
     RECT  55.116 61.997 60.426 62.005 ;
     RECT  61.38 61.501 62.406 62.041 ;
     RECT  4.572 61.889 13.698 62.159 ;
     RECT  32.508 61.925 36.018 62.275 ;
     RECT  36.756 61.997 54.378 62.275 ;
     RECT  32.508 62.275 54.378 62.537 ;
     RECT  55.116 62.005 60.462 62.671 ;
     RECT  61.236 62.041 62.406 62.671 ;
     RECT  14.544 61.925 31.734 62.699 ;
     RECT  15.264 62.699 31.734 62.815 ;
     RECT  32.508 62.537 53.946 62.815 ;
     RECT  55.116 62.671 62.406 62.851 ;
     RECT  4.824 62.159 13.698 62.941 ;
     RECT  14.472 62.707 14.49 62.941 ;
     RECT  55.116 62.851 62.55 62.977 ;
     RECT  15.264 62.815 53.946 63.113 ;
     RECT  15.264 63.113 38.358 63.149 ;
     RECT  39.132 63.113 53.946 63.319 ;
     RECT  54.72 62.977 62.55 63.319 ;
     RECT  3.924 62.275 4.086 63.553 ;
     RECT  4.824 62.941 14.49 63.553 ;
     RECT  15.264 63.149 38.106 63.553 ;
     RECT  3.924 63.553 38.106 63.661 ;
     RECT  39.132 63.319 62.55 63.661 ;
     RECT  3.42 63.661 38.106 63.779 ;
     RECT  39.132 63.661 63.018 63.859 ;
     RECT  63.792 63.661 63.81 63.859 ;
     RECT  2.415 59.837 2.697 63.883 ;
     RECT  2.415 63.883 3.294 63.923 ;
     RECT  4.068 63.779 38.106 63.931 ;
     RECT  39.132 63.859 63.81 63.931 ;
     RECT  4.068 63.931 63.81 64.201 ;
     RECT  4.068 64.201 63.882 64.391 ;
     RECT  4.068 64.391 59.418 64.499 ;
     RECT  4.068 64.499 59.31 64.661 ;
     RECT  36.756 64.661 59.31 64.697 ;
     RECT  60.228 64.391 63.882 64.733 ;
     RECT  4.068 64.661 35.982 64.741 ;
     RECT  61.38 64.733 63.882 64.867 ;
     RECT  61.38 64.867 63.918 64.895 ;
     RECT  3.96 64.741 35.982 65.011 ;
     RECT  2.415 63.923 2.697 65.083 ;
     RECT  3.492 65.011 35.982 65.083 ;
     RECT  60.228 64.733 60.642 65.165 ;
     RECT  61.452 64.895 63.918 65.371 ;
     RECT  36.756 64.697 47.394 65.443 ;
     RECT  48.24 64.697 59.31 65.443 ;
     RECT  2.415 65.083 35.982 65.507 ;
     RECT  18.144 65.507 35.982 65.509 ;
     RECT  36.756 65.443 59.31 65.509 ;
     RECT  18.144 65.509 59.31 65.515 ;
     RECT  60.3 65.165 60.642 65.785 ;
     RECT  61.452 65.371 64.062 65.785 ;
     RECT  2.415 65.507 17.406 65.939 ;
     RECT  12.816 65.939 17.406 65.975 ;
     RECT  60.3 65.785 64.062 66.055 ;
     RECT  18.144 65.515 59.346 66.091 ;
     RECT  60.3 66.055 64.242 66.091 ;
     RECT  18.144 66.091 64.242 66.119 ;
     RECT  18.36 66.119 64.242 66.173 ;
     RECT  17.064 65.975 17.406 66.209 ;
     RECT  18.36 66.173 51.354 66.209 ;
     RECT  52.308 66.173 64.242 66.209 ;
     RECT  38.7 66.209 39.366 66.245 ;
     RECT  40.104 66.209 51.354 66.245 ;
     RECT  17.064 66.209 17.262 66.317 ;
     RECT  38.7 66.245 39.294 66.389 ;
     RECT  17.064 66.317 17.082 66.479 ;
     RECT  12.816 65.975 16.326 66.515 ;
     RECT  12.888 66.515 16.326 66.829 ;
     RECT  40.104 66.245 51.297 67.135 ;
     RECT  52.308 66.209 58.914 67.135 ;
     RECT  2.415 65.939 11.862 67.171 ;
     RECT  38.7 66.389 39.15 67.171 ;
     RECT  40.104 67.135 58.914 67.171 ;
     RECT  59.868 66.209 62.226 67.171 ;
     RECT  18.36 66.209 37.962 67.243 ;
     RECT  63 66.209 64.242 67.243 ;
     RECT  12.888 66.829 16.794 67.261 ;
     RECT  38.7 67.171 62.226 67.261 ;
     RECT  63 67.243 64.278 67.261 ;
     RECT  2.415 67.171 11.97 67.277 ;
     RECT  3.672 67.277 11.97 67.289 ;
     RECT  12.888 67.261 17.082 67.297 ;
     RECT  12.744 67.297 17.082 67.325 ;
     RECT  3.996 67.289 11.97 67.333 ;
     RECT  12.744 67.325 16.902 67.333 ;
     RECT  38.7 67.261 64.278 67.433 ;
     RECT  18.036 67.243 37.962 67.441 ;
     RECT  39.6 67.433 64.278 67.441 ;
     RECT  39.6 67.441 64.458 67.711 ;
     RECT  39.6 67.711 64.998 67.829 ;
     RECT  18.036 67.441 38.214 67.981 ;
     RECT  61.416 67.829 64.998 67.981 ;
     RECT  17.82 67.981 38.214 68.099 ;
     RECT  18.036 68.099 38.214 68.251 ;
     RECT  39.6 67.829 60.534 68.251 ;
     RECT  61.416 67.981 65.07 68.341 ;
     RECT  3.996 67.333 16.902 68.405 ;
     RECT  18.036 68.251 38.43 68.449 ;
     RECT  18.036 68.449 38.574 68.521 ;
     RECT  39.348 68.251 60.534 68.521 ;
     RECT  4.932 68.405 16.902 68.611 ;
     RECT  61.416 68.341 65.61 68.611 ;
     RECT  3.996 68.405 4.014 68.639 ;
     RECT  18.036 68.521 60.534 68.755 ;
     RECT  61.416 68.611 65.754 68.819 ;
     RECT  4.932 68.611 17.226 68.881 ;
     RECT  18.036 68.755 60.57 68.881 ;
     RECT  4.932 68.881 60.57 68.909 ;
     RECT  65.088 68.819 65.754 68.909 ;
     RECT  65.304 68.909 65.61 68.945 ;
     RECT  4.932 68.909 36.882 68.981 ;
     RECT  37.62 68.909 60.57 69.061 ;
     RECT  61.416 68.819 64.278 69.061 ;
     RECT  37.62 69.061 64.278 69.251 ;
     RECT  37.62 69.251 59.13 69.359 ;
     RECT  4.932 68.981 36.738 69.491 ;
     RECT  37.62 69.359 59.022 69.521 ;
     RECT  6.804 69.491 36.738 69.799 ;
     RECT  37.62 69.521 43.11 69.799 ;
     RECT  59.868 69.251 64.278 70.141 ;
     RECT  65.304 68.945 65.322 70.141 ;
     RECT  6.804 69.799 43.11 70.411 ;
     RECT  43.884 69.521 59.022 70.411 ;
     RECT  59.868 70.141 65.322 70.529 ;
     RECT  64.224 70.529 65.322 70.601 ;
     RECT  4.932 69.491 5.526 70.645 ;
     RECT  6.804 70.411 59.022 70.951 ;
     RECT  4.932 70.645 5.598 71.179 ;
     RECT  6.336 70.951 59.022 71.179 ;
     RECT  4.932 71.179 59.022 71.323 ;
     RECT  59.868 70.529 63.486 71.323 ;
     RECT  64.26 70.601 65.322 71.339 ;
     RECT  4.932 71.323 63.486 71.455 ;
     RECT  4.932 71.455 63.99 71.501 ;
     RECT  4.932 71.501 63.702 71.609 ;
     RECT  64.728 71.339 65.322 71.681 ;
     RECT  4.932 71.609 5.31 72.031 ;
     RECT  4.716 72.031 5.31 72.077 ;
     RECT  64.728 71.681 65.25 72.185 ;
     RECT  4.932 72.077 5.31 72.221 ;
     RECT  41.508 71.609 63.702 72.221 ;
     RECT  50.652 72.221 63.702 72.301 ;
     RECT  4.968 72.221 5.31 72.365 ;
     RECT  4.968 72.365 5.202 72.419 ;
     RECT  41.508 72.221 49.806 72.419 ;
     RECT  50.652 72.301 63.774 72.419 ;
     RECT  64.728 72.185 64.89 72.455 ;
     RECT  64.728 72.455 64.854 72.527 ;
     RECT  5.004 72.419 5.022 72.563 ;
     RECT  6.12 71.609 40.734 72.661 ;
     RECT  41.508 72.419 49.626 72.661 ;
     RECT  50.724 72.419 63.774 72.689 ;
     RECT  50.904 72.689 63.774 72.733 ;
     RECT  64.728 72.527 64.818 72.733 ;
     RECT  6.12 72.661 49.626 73.003 ;
     RECT  50.904 72.733 64.818 73.139 ;
     RECT  6.048 73.003 49.626 73.201 ;
     RECT  50.904 73.139 64.566 73.337 ;
     RECT  62.928 73.337 64.566 73.373 ;
     RECT  2.415 67.277 2.697 73.381 ;
     RECT  4.464 73.345 4.482 73.471 ;
     RECT  2.415 73.381 3.114 73.499 ;
     RECT  50.904 73.337 62.097 73.499 ;
     RECT  62.928 73.373 63.162 73.499 ;
     RECT  64.548 73.373 64.566 73.499 ;
     RECT  54.684 73.499 62.097 73.517 ;
     RECT  2.415 73.499 2.97 73.535 ;
     RECT  5.22 73.201 49.626 73.535 ;
     RECT  62.928 73.499 62.946 73.535 ;
     RECT  5.22 73.535 41.058 73.565 ;
     RECT  4.32 73.471 4.482 73.651 ;
     RECT  3.852 73.651 4.482 73.741 ;
     RECT  50.904 73.499 53.838 73.741 ;
     RECT  3.78 73.741 4.482 73.771 ;
     RECT  5.22 73.565 41.022 73.771 ;
     RECT  41.904 73.535 49.626 73.921 ;
     RECT  50.832 73.741 53.838 73.921 ;
     RECT  3.78 73.771 41.022 74.039 ;
     RECT  41.904 73.921 53.838 74.039 ;
     RECT  28.08 74.039 41.022 74.075 ;
     RECT  28.08 74.075 30.87 74.111 ;
     RECT  3.78 74.039 27.306 74.309 ;
     RECT  54.72 73.517 62.097 74.353 ;
     RECT  31.608 74.075 41.022 74.389 ;
     RECT  41.904 74.039 53.802 74.389 ;
     RECT  28.188 74.111 30.87 74.417 ;
     RECT  28.764 74.417 30.87 74.453 ;
     RECT  3.78 74.309 27.198 74.489 ;
     RECT  31.608 74.389 53.802 74.489 ;
     RECT  31.752 74.489 53.802 74.579 ;
     RECT  3.78 74.489 27.162 74.615 ;
     RECT  28.764 74.453 29.898 74.849 ;
     RECT  30.672 74.453 30.87 74.849 ;
     RECT  31.752 74.579 31.77 74.849 ;
     RECT  4.32 74.615 27.162 74.885 ;
     RECT  32.652 74.579 51.534 74.885 ;
     RECT  54.684 74.353 62.097 74.893 ;
     RECT  4.716 74.885 27.162 74.921 ;
     RECT  32.724 74.885 51.534 74.921 ;
     RECT  4.716 74.921 22.302 74.957 ;
     RECT  23.04 74.921 25.074 74.957 ;
     RECT  26.064 74.921 26.37 74.957 ;
     RECT  28.764 74.849 29.862 74.993 ;
     RECT  32.724 74.921 33.138 74.993 ;
     RECT  34.344 74.921 49.698 74.993 ;
     RECT  4.716 74.957 21.978 75.029 ;
     RECT  27.108 74.921 27.162 75.029 ;
     RECT  34.344 74.993 48.942 75.029 ;
     RECT  52.272 74.579 53.802 75.067 ;
     RECT  54.576 74.893 62.097 75.067 ;
     RECT  4.716 75.029 18.897 75.119 ;
     RECT  19.8 75.029 21.978 75.119 ;
     RECT  23.508 74.957 25.074 75.119 ;
     RECT  26.136 74.957 26.37 75.119 ;
     RECT  34.344 75.029 38.754 75.119 ;
     RECT  39.528 75.029 48.942 75.119 ;
     RECT  52.272 75.067 62.097 75.119 ;
     RECT  19.8 75.119 21.33 75.155 ;
     RECT  23.796 75.119 24.426 75.155 ;
     RECT  26.352 75.119 26.37 75.155 ;
     RECT  34.344 75.119 35.097 75.155 ;
     RECT  36.432 75.119 37.134 75.155 ;
     RECT  38.16 75.119 38.754 75.155 ;
     RECT  39.96 75.119 40.626 75.155 ;
     RECT  41.688 75.119 48.258 75.155 ;
     RECT  50.544 74.921 51.534 75.155 ;
     RECT  20.088 75.155 20.898 75.191 ;
     RECT  24.015 75.155 24.426 75.191 ;
     RECT  27.144 75.029 27.162 75.191 ;
     RECT  30.888 75.001 30.906 75.191 ;
     RECT  34.38 75.155 35.097 75.191 ;
     RECT  43.56 75.155 46.422 75.191 ;
     RECT  47.232 75.155 47.934 75.191 ;
     RECT  50.76 75.155 51.534 75.191 ;
     RECT  38.232 75.155 38.754 75.197 ;
     RECT  50.832 75.191 51.534 75.197 ;
     RECT  58.068 75.119 60.57 75.197 ;
     RECT  38.232 75.197 38.61 75.2 ;
     RECT  20.088 75.191 20.538 75.227 ;
     RECT  44.172 75.191 46.422 75.227 ;
     RECT  52.272 75.119 57.294 75.227 ;
     RECT  36.936 75.155 37.134 75.245 ;
     RECT  38.304 75.2 38.61 75.245 ;
     RECT  41.688 75.155 42.714 75.245 ;
     RECT  44.172 75.227 45.897 75.245 ;
     RECT  47.232 75.191 47.25 75.245 ;
     RECT  20.52 75.227 20.538 75.263 ;
     RECT  24.015 75.191 24.39 75.263 ;
     RECT  38.376 75.245 38.394 75.263 ;
     RECT  39.96 75.155 40.497 75.263 ;
     RECT  41.688 75.245 41.706 75.299 ;
     RECT  58.068 75.197 60.462 75.299 ;
     RECT  2.415 73.535 2.697 75.347 ;
     RECT  4.716 75.119 8.097 75.347 ;
     RECT  8.892 75.119 18.897 75.347 ;
     RECT  24.015 75.263 24.297 75.347 ;
     RECT  29.415 74.993 29.697 75.347 ;
     RECT  34.815 75.191 35.097 75.347 ;
     RECT  40.215 75.263 40.497 75.347 ;
     RECT  44.46 75.245 45.897 75.347 ;
     RECT  50.832 75.197 51.297 75.347 ;
     RECT  61.38 75.119 62.097 75.347 ;
     RECT  67.215 50.999 67.497 75.347 ;
     RECT  8.892 75.347 18.738 75.389 ;
     RECT  52.272 75.227 53.694 75.389 ;
     RECT  55.872 75.227 57.294 75.389 ;
     RECT  58.068 75.299 58.806 75.389 ;
     RECT  59.724 75.299 60.462 75.389 ;
     RECT  4.716 75.347 7.905 75.425 ;
     RECT  8.892 75.389 9.45 75.425 ;
     RECT  10.332 75.389 10.566 75.425 ;
     RECT  11.412 75.389 18.738 75.425 ;
     RECT  32.724 74.993 33.102 75.425 ;
     RECT  54.72 75.227 54.738 75.425 ;
     RECT  58.752 75.389 58.806 75.425 ;
     RECT  60.12 75.389 60.462 75.425 ;
     RECT  18.615 75.425 18.738 75.461 ;
     RECT  32.832 75.425 33.102 75.461 ;
     RECT  5.184 75.425 5.778 75.497 ;
     RECT  11.412 75.425 17.586 75.497 ;
     RECT  44.46 75.347 45.705 75.497 ;
     RECT  50.832 75.347 51.105 75.497 ;
     RECT  58.752 75.425 58.77 75.497 ;
     RECT  5.184 75.497 5.742 75.533 ;
     RECT  7.632 75.425 7.905 75.533 ;
     RECT  10.332 75.425 10.35 75.533 ;
     RECT  32.832 75.461 32.85 75.533 ;
     RECT  50.94 75.497 51.105 75.533 ;
     RECT  53.676 75.389 53.694 75.533 ;
     RECT  11.412 75.497 11.862 75.569 ;
     RECT  12.6 75.497 17.586 75.569 ;
     RECT  55.872 75.389 56.505 75.569 ;
     RECT  60.12 75.425 60.138 75.569 ;
     RECT  61.38 75.347 61.905 75.569 ;
     RECT  2.415 75.347 2.505 75.617 ;
     RECT  7.815 75.533 7.905 75.617 ;
     RECT  18.615 75.461 18.705 75.617 ;
     RECT  24.015 75.347 24.105 75.617 ;
     RECT  29.415 75.347 29.505 75.617 ;
     RECT  34.815 75.347 34.905 75.617 ;
     RECT  40.215 75.347 40.305 75.617 ;
     RECT  45.615 75.497 45.705 75.617 ;
     RECT  51.015 75.533 51.105 75.617 ;
     RECT  56.415 75.569 56.505 75.617 ;
     RECT  61.815 75.569 61.905 75.617 ;
     RECT  67.215 75.347 67.305 75.617 ;
     RECT  9.144 75.425 9.162 75.659 ;
     RECT  11.844 75.569 11.862 75.659 ;
     RECT  12.96 75.569 17.586 77.628 ;
    LAYER M4 ;
     RECT  0.205 38.88 0.245 39 ;
     RECT  0.245 38.976 2.329 39 ;
     RECT  2.293 18.96 2.365 18.984 ;
     RECT  2.365 6.384 2.408 6.408 ;
     RECT  2.365 7.632 2.408 7.656 ;
     RECT  2.365 14.208 2.408 14.232 ;
     RECT  2.365 18 2.408 18.984 ;
     RECT  2.365 24.432 2.408 24.456 ;
     RECT  2.401 30.672 2.408 30.696 ;
     RECT  2.329 38.736 2.408 39 ;
     RECT  2.408 2.148 2.512 75.612 ;
     RECT  2.512 2.418 2.704 75.342 ;
     RECT  2.704 18 2.837 18.984 ;
     RECT  2.704 26.736 2.867 28.008 ;
     RECT  2.704 2.736 2.873 4.152 ;
     RECT  2.837 18 3.161 18.936 ;
     RECT  2.704 14.208 3.203 15.432 ;
     RECT  2.704 5.568 3.233 7.656 ;
     RECT  2.704 63.072 3.395 63.912 ;
     RECT  2.704 65.088 3.395 65.112 ;
     RECT  2.704 30.672 3.443 31.8 ;
     RECT  2.704 36.096 3.443 39.768 ;
     RECT  2.704 67.248 3.443 67.272 ;
     RECT  2.704 54.096 3.449 54.168 ;
     RECT  3.161 18 3.485 18.792 ;
     RECT  2.704 55.68 3.539 55.992 ;
     RECT  3.449 54.096 3.593 54.12 ;
     RECT  2.704 24.336 3.629 25.464 ;
     RECT  2.867 26.736 3.629 27.384 ;
     RECT  3.443 31.344 3.629 31.8 ;
     RECT  3.629 25.44 3.685 25.464 ;
     RECT  3.629 26.736 3.685 26.76 ;
     RECT  3.443 38.496 3.692 39.768 ;
     RECT  3.692 38.496 3.733 40.44 ;
     RECT  3.443 37.44 3.737 37.464 ;
     RECT  3.685 25.44 3.772 26.76 ;
     RECT  3.733 38.496 3.779 41.208 ;
     RECT  3.233 7.632 3.805 7.656 ;
     RECT  2.704 8.88 3.805 9.288 ;
     RECT  2.704 20.16 3.809 20.712 ;
     RECT  2.873 2.736 3.841 2.76 ;
     RECT  3.805 7.632 3.845 9.288 ;
     RECT  2.704 11.568 3.881 12.648 ;
     RECT  2.704 16.848 3.881 16.872 ;
     RECT  3.772 26.736 3.881 26.76 ;
     RECT  2.704 22.176 3.913 22.2 ;
     RECT  3.913 21.936 3.923 22.2 ;
     RECT  3.629 24.336 3.923 24.36 ;
     RECT  3.877 23.28 3.964 23.304 ;
     RECT  3.923 21.936 3.973 21.96 ;
     RECT  3.881 11.568 3.985 12.024 ;
     RECT  3.203 14.832 3.985 15.432 ;
     RECT  2.704 29.52 3.985 29.544 ;
     RECT  3.809 20.496 4.019 20.712 ;
     RECT  3.845 7.968 4.025 9.288 ;
     RECT  3.485 18.144 4.097 18.792 ;
     RECT  2.704 73.488 4.129 73.512 ;
     RECT  2.704 59.328 4.169 59.352 ;
     RECT  3.539 55.968 4.201 55.992 ;
     RECT  3.985 14.832 4.22 15.624 ;
     RECT  4.201 34.032 4.345 34.056 ;
     RECT  4.201 55.968 4.345 56.136 ;
     RECT  4.345 58.224 4.381 58.248 ;
     RECT  4.097 18.144 4.385 18.456 ;
     RECT  3.779 38.496 4.385 38.904 ;
     RECT  4.345 34.032 4.453 34.728 ;
     RECT  3.443 36.096 4.453 36.12 ;
     RECT  4.453 34.032 4.493 36.12 ;
     RECT  4.165 43.296 4.501 43.32 ;
     RECT  4.501 43.296 4.547 44.088 ;
     RECT  4.025 8.88 4.549 9.288 ;
     RECT  4.501 28.32 4.588 28.344 ;
     RECT  4.493 34.032 4.595 35.352 ;
     RECT  3.233 5.568 4.597 6.552 ;
     RECT  4.22 14.496 4.633 15.624 ;
     RECT  3.841 2.496 4.669 2.76 ;
     RECT  2.873 4.128 4.693 4.152 ;
     RECT  4.597 5.568 4.693 6.84 ;
     RECT  4.693 72.336 4.7 72.36 ;
     RECT  4.547 44.064 4.705 44.088 ;
     RECT  3.985 61.008 4.705 61.032 ;
     RECT  4.129 73.488 4.739 74.328 ;
     RECT  4.7 72.048 4.741 72.36 ;
     RECT  4.693 4.128 4.745 6.84 ;
     RECT  4.705 44.064 4.745 44.472 ;
     RECT  4.669 2.256 4.753 2.76 ;
     RECT  4.741 72.048 4.787 73.224 ;
     RECT  4.595 34.032 4.789 34.776 ;
     RECT  4.309 66.384 4.817 66.408 ;
     RECT  4.777 53.568 4.849 53.592 ;
     RECT  3.395 63.072 4.849 63.096 ;
     RECT  4.549 8.88 4.883 9.96 ;
     RECT  4.753 2.352 4.993 2.76 ;
     RECT  4.745 4.128 4.993 5.88 ;
     RECT  4.019 20.688 4.993 20.712 ;
     RECT  3.973 21.696 4.993 21.96 ;
     RECT  4.883 9.264 4.997 9.96 ;
     RECT  4.849 53.568 5.029 53.64 ;
     RECT  4.885 54.624 5.029 54.648 ;
     RECT  3.985 29.52 5.065 29.928 ;
     RECT  4.993 20.688 5.077 21.96 ;
     RECT  5.077 21.696 5.101 21.96 ;
     RECT  4.705 60.384 5.101 61.032 ;
     RECT  3.772 25.44 5.125 25.656 ;
     RECT  3.629 31.776 5.125 31.8 ;
     RECT  5.125 28.368 5.137 28.392 ;
     RECT  3.985 11.52 5.173 12.024 ;
     RECT  5.065 29.52 5.173 30.216 ;
     RECT  5.125 31.776 5.185 31.944 ;
     RECT  4.345 55.968 5.209 56.424 ;
     RECT  5.137 28.368 5.212 28.488 ;
     RECT  5.212 28.464 5.221 28.488 ;
     RECT  5.209 55.968 5.249 56.616 ;
     RECT  4.789 33.456 5.276 34.776 ;
     RECT  5.101 60.384 5.285 61.368 ;
     RECT  2.977 0.144 5.317 0.168 ;
     RECT  4.385 18.192 5.317 18.456 ;
     RECT  5.185 31.92 5.317 31.944 ;
     RECT  5.276 33.216 5.317 34.776 ;
     RECT  4.787 72.336 5.321 73.224 ;
     RECT  5.245 69.504 5.329 69.528 ;
     RECT  5.269 71.184 5.356 71.304 ;
     RECT  4.381 58.224 5.357 59.208 ;
     RECT  5.317 31.92 5.363 34.776 ;
     RECT  4.745 44.448 5.393 44.472 ;
     RECT  5.285 60.96 5.413 61.368 ;
     RECT  4.849 62.736 5.413 63.096 ;
     RECT  5.363 31.92 5.421 32.76 ;
     RECT  4.633 14.496 5.425 16.536 ;
     RECT  5.317 18.192 5.425 19.128 ;
     RECT  4.739 74.304 5.465 74.328 ;
     RECT  5.029 53.568 5.497 54.648 ;
     RECT  5.413 60.96 5.5 63.096 ;
     RECT  5.569 45.552 5.653 45.576 ;
     RECT  5.077 20.688 5.681 20.712 ;
     RECT  5.101 21.696 5.681 22.488 ;
     RECT  5.653 45.552 5.699 46.248 ;
     RECT  5.653 7.632 5.713 7.656 ;
     RECT  5.173 11.52 5.717 12.456 ;
     RECT  4.997 9.648 5.753 9.96 ;
     RECT  5.753 9.792 5.785 9.96 ;
     RECT  5.5 63.072 5.821 63.096 ;
     RECT  5.713 6.864 5.825 7.656 ;
     RECT  5.825 7.632 5.893 7.656 ;
     RECT  5.785 9.792 5.893 10.056 ;
     RECT  5.245 64.944 5.996 65.592 ;
     RECT  5.317 0.144 6.001 0.84 ;
     RECT  4.993 2.352 6.005 5.88 ;
     RECT  5.173 29.52 6.005 30.36 ;
     RECT  4.669 36.432 6.005 36.456 ;
     RECT  6.001 0.144 6.073 0.888 ;
     RECT  6.005 2.352 6.073 4.824 ;
     RECT  5.125 25.44 6.073 26.088 ;
     RECT  6.044 51.984 6.073 52.008 ;
     RECT  5.996 64.944 6.083 65.784 ;
     RECT  5.497 53.568 6.085 54.744 ;
     RECT  5.5 60.96 6.113 61.368 ;
     RECT  4.993 48.816 6.131 48.84 ;
     RECT  6.073 51.6 6.131 52.008 ;
     RECT  5.699 46.224 6.149 46.248 ;
     RECT  6.113 61.008 6.149 61.368 ;
     RECT  6.073 25.104 6.221 26.088 ;
     RECT  6.037 69.456 6.221 69.48 ;
     RECT  5.356 71.184 6.221 71.208 ;
     RECT  6.083 64.944 6.229 65.592 ;
     RECT  5.681 22.464 6.257 22.488 ;
     RECT  6.229 64.368 6.275 65.592 ;
     RECT  5.425 14.496 6.277 19.128 ;
     RECT  6.277 14.208 6.289 19.128 ;
     RECT  6.181 20.496 6.289 20.52 ;
     RECT  6.085 53.472 6.293 54.744 ;
     RECT  5.717 11.568 6.325 12.456 ;
     RECT  6.289 14.208 6.325 20.52 ;
     RECT  4.385 38.88 6.332 38.904 ;
     RECT  6.325 11.568 6.361 12.6 ;
     RECT  5.421 32.736 6.365 32.76 ;
     RECT  5.821 63.072 6.371 63.336 ;
     RECT  6.005 5.856 6.373 5.88 ;
     RECT  6.332 38.88 6.419 39.672 ;
     RECT  5.363 34.176 6.437 34.776 ;
     RECT  5.357 59.184 6.541 59.208 ;
     RECT  6.149 61.008 6.545 61.032 ;
     RECT  5.893 7.632 6.577 7.896 ;
     RECT  6.325 13.776 6.689 20.52 ;
     RECT  6.275 64.368 6.689 64.392 ;
     RECT  6.577 7.632 6.757 7.944 ;
     RECT  6.221 25.632 6.793 26.088 ;
     RECT  6.689 14.496 6.803 20.52 ;
     RECT  6.649 47.712 6.805 48.408 ;
     RECT  6.803 16.368 6.833 20.52 ;
     RECT  6.793 25.632 6.853 26.472 ;
     RECT  6.361 11.568 6.865 12.696 ;
     RECT  6.073 0.144 6.869 4.824 ;
     RECT  6.373 5.856 7.045 6.6 ;
     RECT  6.757 7.632 7.045 8.712 ;
     RECT  5.321 72.384 7.081 73.224 ;
     RECT  6.419 38.88 7.117 39 ;
     RECT  7.045 5.856 7.141 8.712 ;
     RECT  5.893 9.792 7.141 10.344 ;
     RECT  7.141 5.856 7.153 10.344 ;
     RECT  6.541 58.464 7.153 59.208 ;
     RECT  5.249 56.592 7.189 56.616 ;
     RECT  5.965 37.632 7.237 37.656 ;
     RECT  2.704 68.352 7.297 68.376 ;
     RECT  7.153 5.856 7.333 10.392 ;
     RECT  6.865 11.568 7.333 13.32 ;
     RECT  7.081 33.024 7.333 33.048 ;
     RECT  6.293 53.568 7.34 54.744 ;
     RECT  7.34 53.568 7.369 55.08 ;
     RECT  6.275 65.376 7.369 65.592 ;
     RECT  7.081 72.384 7.381 73.272 ;
     RECT  5.533 74.688 7.381 74.712 ;
     RECT  7.297 67.728 7.405 68.376 ;
     RECT  6.437 34.512 7.549 34.776 ;
     RECT  7.369 65.376 7.549 66.072 ;
     RECT  6.073 29.232 7.585 29.256 ;
     RECT  6.005 30.336 7.585 30.36 ;
     RECT  3.779 41.184 7.585 41.208 ;
     RECT  7.369 53.52 7.657 55.08 ;
     RECT  7.189 56.592 7.657 57.432 ;
     RECT  7.441 70.416 7.669 70.44 ;
     RECT  6.829 31.344 7.729 31.368 ;
     RECT  7.381 72.384 7.729 74.712 ;
     RECT  7.333 32.88 7.765 33.048 ;
     RECT  7.549 34.512 7.765 34.824 ;
     RECT  7.669 69.84 7.765 71.064 ;
     RECT  6.869 0.192 7.808 4.824 ;
     RECT  7.333 5.856 7.808 13.32 ;
     RECT  6.803 14.496 7.808 14.856 ;
     RECT  6.833 16.368 7.808 19.896 ;
     RECT  6.853 25.632 7.808 26.664 ;
     RECT  7.477 27.936 7.808 27.96 ;
     RECT  7.585 29.232 7.808 30.36 ;
     RECT  7.729 31.344 7.808 31.416 ;
     RECT  7.765 32.88 7.808 34.824 ;
     RECT  7.237 37.296 7.808 37.656 ;
     RECT  7.117 38.64 7.808 39 ;
     RECT  7.585 40.848 7.808 41.208 ;
     RECT  6.805 47.616 7.808 48.408 ;
     RECT  5.713 50.592 7.808 50.616 ;
     RECT  6.131 51.6 7.808 51.912 ;
     RECT  7.657 53.52 7.808 57.432 ;
     RECT  7.153 58.464 7.808 59.256 ;
     RECT  7.669 60.384 7.808 61.128 ;
     RECT  6.371 63.312 7.808 63.336 ;
     RECT  7.549 65.376 7.808 66.456 ;
     RECT  7.405 67.68 7.808 68.376 ;
     RECT  7.765 69.84 7.808 71.208 ;
     RECT  7.729 72.24 7.808 74.712 ;
     RECT  7.808 0.192 7.912 75.612 ;
     RECT  7.912 0.192 8.104 75.342 ;
     RECT  8.104 56.016 8.165 59.208 ;
     RECT  8.104 32.448 8.243 32.472 ;
     RECT  8.104 26.064 8.273 26.664 ;
     RECT  8.104 27.936 8.273 27.96 ;
     RECT  8.104 45.36 8.273 48.408 ;
     RECT  8.165 57.408 8.273 59.208 ;
     RECT  8.104 63.408 8.345 69.864 ;
     RECT  8.104 50.592 8.381 51.24 ;
     RECT  8.104 73.248 8.381 75.192 ;
     RECT  8.104 9.888 8.417 19.032 ;
     RECT  8.104 29.04 8.435 29.544 ;
     RECT  8.104 37.056 8.489 37.464 ;
     RECT  8.417 14.256 8.561 19.032 ;
     RECT  8.561 14.256 8.597 18.792 ;
     RECT  8.417 9.888 8.705 12.744 ;
     RECT  8.597 14.256 8.785 14.856 ;
     RECT  8.104 33.936 8.813 35.688 ;
     RECT  8.273 45.36 8.813 47.352 ;
     RECT  8.104 42.144 8.915 42.168 ;
     RECT  8.104 71.184 8.921 72.264 ;
     RECT  8.104 44.304 8.957 44.328 ;
     RECT  8.104 0.192 8.965 8.712 ;
     RECT  8.813 34.752 8.993 35.688 ;
     RECT  8.345 63.408 9.029 69.432 ;
     RECT  8.965 0.144 9.052 8.712 ;
     RECT  8.104 52.848 9.065 54.504 ;
     RECT  8.785 14.352 9.109 14.856 ;
     RECT  8.165 56.016 9.133 56.376 ;
     RECT  9.065 54 9.157 54.504 ;
     RECT  9.133 56.016 9.157 56.472 ;
     RECT  8.813 45.36 9.169 45.384 ;
     RECT  8.921 71.232 9.173 72.264 ;
     RECT  8.813 46.704 9.203 47.352 ;
     RECT  9.203 46.704 9.209 46.728 ;
     RECT  9.157 54 9.217 56.472 ;
     RECT  8.273 58.128 9.241 59.208 ;
     RECT  8.104 60.384 9.241 60.408 ;
     RECT  8.435 29.52 9.245 29.544 ;
     RECT  9.217 54 9.245 56.376 ;
     RECT  8.104 40.848 9.277 41.16 ;
     RECT  9.241 58.128 9.281 60.408 ;
     RECT  8.104 23.232 9.317 23.352 ;
     RECT  9.277 40.608 9.317 41.16 ;
     RECT  8.104 31.392 9.353 31.416 ;
     RECT  9.029 63.408 9.353 64.152 ;
     RECT  9.029 65.376 9.385 69.432 ;
     RECT  8.381 73.248 9.389 74.088 ;
     RECT  8.381 75.168 9.421 75.192 ;
     RECT  9.421 75.168 9.461 75.288 ;
     RECT  9.052 0.192 9.493 8.712 ;
     RECT  8.381 51.216 9.529 51.24 ;
     RECT  9.065 52.848 9.529 52.92 ;
     RECT  9.173 71.232 9.569 71.736 ;
     RECT  9.389 73.248 9.601 73.512 ;
     RECT  8.273 26.064 9.637 26.232 ;
     RECT  8.597 16.368 9.641 18.792 ;
     RECT  9.353 64.128 9.677 64.152 ;
     RECT  9.709 61.344 9.745 61.368 ;
     RECT  9.673 62.88 9.745 62.904 ;
     RECT  9.601 72.96 9.749 73.512 ;
     RECT  8.705 10.176 9.785 12.744 ;
     RECT  9.281 58.128 9.785 60.312 ;
     RECT  9.637 24.48 9.853 24.504 ;
     RECT  9.637 25.968 9.853 26.232 ;
     RECT  9.529 51.216 9.893 52.92 ;
     RECT  9.385 65.376 9.929 69.528 ;
     RECT  9.461 75.264 9.965 75.288 ;
     RECT  9.457 33.6 10.069 33.624 ;
     RECT  9.245 54 10.073 54.504 ;
     RECT  9.785 58.56 10.101 60.312 ;
     RECT  9.169 45.024 10.105 45.384 ;
     RECT  9.893 51.312 10.109 52.92 ;
     RECT  9.929 67.632 10.109 69.528 ;
     RECT  8.993 34.752 10.172 34.776 ;
     RECT  9.493 0.192 10.213 9.144 ;
     RECT  9.109 14.352 10.213 14.76 ;
     RECT  9.853 28.464 10.213 28.488 ;
     RECT  8.489 37.056 10.213 37.08 ;
     RECT  10.172 34.752 10.259 35.304 ;
     RECT  9.641 16.368 10.285 18.456 ;
     RECT  10.213 36.48 10.309 37.08 ;
     RECT  8.104 21.504 10.361 22.2 ;
     RECT  9.745 61.344 10.361 62.904 ;
     RECT  9.929 65.376 10.393 66.504 ;
     RECT  9.317 40.608 10.433 40.872 ;
     RECT  10.109 51.312 10.433 52.872 ;
     RECT  10.393 64.608 10.433 66.504 ;
     RECT  10.309 35.856 10.469 37.08 ;
     RECT  10.105 45.024 10.469 45.432 ;
     RECT  10.069 33.024 10.541 33.72 ;
     RECT  10.109 67.632 10.577 69.24 ;
     RECT  9.749 73.248 10.577 73.512 ;
     RECT  10.285 16.032 10.645 18.456 ;
     RECT  9.569 71.712 10.685 71.736 ;
     RECT  10.645 15.936 10.709 18.456 ;
     RECT  9.317 23.232 10.721 23.256 ;
     RECT  9.853 24.48 10.721 26.232 ;
     RECT  10.721 25.392 10.753 26.232 ;
     RECT  10.213 27.552 10.753 28.488 ;
     RECT  10.361 62.832 10.793 62.904 ;
     RECT  9.785 11.376 10.801 12.744 ;
     RECT  10.801 11.472 10.837 12.744 ;
     RECT  10.213 14.256 10.837 14.76 ;
     RECT  8.104 38.88 10.861 38.904 ;
     RECT  9.245 56.016 10.865 56.04 ;
     RECT  10.433 64.608 10.885 65.4 ;
     RECT  10.861 38.88 10.901 39 ;
     RECT  10.885 63.792 10.931 65.4 ;
     RECT  9.785 10.176 10.937 10.2 ;
     RECT  10.213 0.144 10.973 9.144 ;
     RECT  10.931 64.992 10.973 65.4 ;
     RECT  10.709 15.936 11.029 18.84 ;
     RECT  11.005 19.968 11.029 19.992 ;
     RECT  10.259 34.752 11.077 34.776 ;
     RECT  10.101 58.56 11.113 59.208 ;
     RECT  10.101 60.192 11.149 60.312 ;
     RECT  10.361 61.344 11.149 61.368 ;
     RECT  11.077 74.928 11.149 74.952 ;
     RECT  11.149 60.192 11.189 61.368 ;
     RECT  10.541 33.024 11.257 33.528 ;
     RECT  10.837 11.472 11.324 14.76 ;
     RECT  11.029 15.936 11.324 19.992 ;
     RECT  11.324 11.472 11.329 19.992 ;
     RECT  10.753 25.392 11.333 28.488 ;
     RECT  10.433 51.312 11.352 51.912 ;
     RECT  10.577 67.776 11.365 69.24 ;
     RECT  11.329 11.472 11.411 20.232 ;
     RECT  11.077 34.56 11.413 34.776 ;
     RECT  10.469 35.856 11.413 35.88 ;
     RECT  11.352 50.976 11.413 51.912 ;
     RECT  11.365 67.776 11.413 69.72 ;
     RECT  10.361 22.032 11.42 22.2 ;
     RECT  10.577 73.248 11.437 73.272 ;
     RECT  11.257 32.448 11.459 33.528 ;
     RECT  11.413 34.56 11.459 35.88 ;
     RECT  11.413 50.976 11.459 52.488 ;
     RECT  11.411 16.128 11.477 20.232 ;
     RECT  11.149 23.952 11.507 23.976 ;
     RECT  11.113 58.416 11.509 59.208 ;
     RECT  11.189 60.192 11.509 61.032 ;
     RECT  10.433 66.48 11.509 66.504 ;
     RECT  11.477 16.32 11.513 20.232 ;
     RECT  10.973 65.376 11.545 65.4 ;
     RECT  11.509 66.48 11.545 66.744 ;
     RECT  11.257 56.4 11.581 56.424 ;
     RECT  10.969 29.616 11.603 29.64 ;
     RECT  11.537 30.816 11.621 30.84 ;
     RECT  11.581 56.4 11.653 56.808 ;
     RECT  11.509 58.416 11.653 61.032 ;
     RECT  10.973 0.192 11.689 9.144 ;
     RECT  11.413 62.688 11.729 62.712 ;
     RECT  11.413 67.776 11.761 70.488 ;
     RECT  10.357 43.152 11.765 43.176 ;
     RECT  10.825 37.44 11.797 37.464 ;
     RECT  11.411 11.472 11.833 14.952 ;
     RECT  11.797 37.008 11.837 37.464 ;
     RECT  11.437 72.288 11.869 73.272 ;
     RECT  11.149 74.304 11.869 74.952 ;
     RECT  11.545 65.376 11.873 66.744 ;
     RECT  11.689 0.192 11.891 9.24 ;
     RECT  11.459 34.8 11.893 35.88 ;
     RECT  11.837 37.008 11.893 37.032 ;
     RECT  11.761 67.776 11.9 71.064 ;
     RECT  11.42 22.032 11.905 22.776 ;
     RECT  11.893 34.8 11.909 37.032 ;
     RECT  11.909 35.28 11.98 37.032 ;
     RECT  11.513 16.32 11.981 19.992 ;
     RECT  11.981 16.32 11.987 17.688 ;
     RECT  11.873 65.376 11.987 65.544 ;
     RECT  11.9 67.2 11.987 71.064 ;
     RECT  11.987 67.392 11.989 71.064 ;
     RECT  11.869 72.288 11.989 74.952 ;
     RECT  11.833 10.848 12.017 14.952 ;
     RECT  10.901 38.976 12.085 39 ;
     RECT  11.459 32.448 12.089 33.288 ;
     RECT  11.989 67.392 12.125 74.952 ;
     RECT  11.891 0.192 12.161 8.568 ;
     RECT  11.653 56.4 12.161 61.032 ;
     RECT  12.125 67.392 12.22 71.832 ;
     RECT  12.017 10.848 12.229 10.872 ;
     RECT  11.905 21.504 12.265 22.776 ;
     RECT  11.333 25.392 12.277 26.808 ;
     RECT  11.977 42.72 12.301 42.744 ;
     RECT  12.017 14.832 12.373 14.952 ;
     RECT  12.161 56.4 12.445 60.408 ;
     RECT  12.277 25.056 12.553 26.808 ;
     RECT  11.333 27.888 12.553 27.912 ;
     RECT  12.089 33.264 12.553 33.288 ;
     RECT  12.373 14.832 12.589 15.288 ;
     RECT  11.987 16.32 12.589 17.64 ;
     RECT  10.469 45.168 12.625 45.432 ;
     RECT  10.433 40.848 12.757 40.872 ;
     RECT  12.301 41.904 12.757 42.744 ;
     RECT  12.625 44.448 12.757 45.432 ;
     RECT  11.459 52.176 12.769 52.488 ;
     RECT  12.908 9.6 12.949 9.624 ;
     RECT  12.229 10.8 12.949 10.872 ;
     RECT  11.869 30.384 12.949 30.456 ;
     RECT  12.589 14.832 13.021 17.64 ;
     RECT  12.949 30.384 13.057 30.696 ;
     RECT  11.941 62.736 13.057 62.76 ;
     RECT  11.459 50.976 13.085 51 ;
     RECT  12.769 52.176 13.085 53.112 ;
     RECT  12.949 9.6 13.093 10.872 ;
     RECT  12.017 11.952 13.093 13.608 ;
     RECT  13.021 14.736 13.093 17.64 ;
     RECT  11.981 18.672 13.093 19.992 ;
     RECT  11.98 37.008 13.129 37.032 ;
     RECT  12.085 38.16 13.129 39 ;
     RECT  13.085 50.976 13.129 53.112 ;
     RECT  10.073 54.48 13.129 54.504 ;
     RECT  12.161 0.192 13.208 8.52 ;
     RECT  13.093 9.6 13.208 13.608 ;
     RECT  13.093 14.736 13.208 19.992 ;
     RECT  12.265 21.504 13.208 22.824 ;
     RECT  12.553 25.056 13.208 27.912 ;
     RECT  13.057 29.616 13.208 30.696 ;
     RECT  12.553 33.264 13.208 34.2 ;
     RECT  11.98 35.28 13.208 35.448 ;
     RECT  13.129 36.912 13.208 39 ;
     RECT  12.757 40.848 13.208 42.744 ;
     RECT  12.757 43.824 13.208 45.432 ;
     RECT  8.273 48.384 13.208 48.408 ;
     RECT  13.129 50.976 13.208 54.504 ;
     RECT  12.445 55.824 13.208 60.408 ;
     RECT  13.057 62.016 13.208 62.76 ;
     RECT  10.931 63.792 13.208 63.816 ;
     RECT  11.987 65.52 13.208 65.544 ;
     RECT  12.22 67.392 13.208 71.4 ;
     RECT  12.125 72.96 13.208 74.952 ;
     RECT  13.208 0.192 13.312 75.612 ;
     RECT  13.312 0.192 13.504 75.432 ;
     RECT  13.504 56.784 13.601 59.832 ;
     RECT  13.504 20.592 13.619 22.056 ;
     RECT  13.504 72.912 13.619 73.512 ;
     RECT  13.504 75.072 13.619 75.432 ;
     RECT  13.504 53.904 13.637 54.504 ;
     RECT  13.504 18.672 13.66 19.368 ;
     RECT  13.504 0.192 13.667 4.968 ;
     RECT  13.504 67.392 13.709 70.824 ;
     RECT  13.504 29.184 13.715 32.52 ;
     RECT  13.504 48.336 13.853 48.504 ;
     RECT  13.504 24.72 13.889 24.744 ;
     RECT  13.504 33.6 13.889 34.104 ;
     RECT  13.667 0.192 13.955 4.776 ;
     RECT  13.504 47.28 14.003 47.304 ;
     RECT  13.504 63.216 14.213 63.816 ;
     RECT  13.715 31.632 14.243 32.52 ;
     RECT  13.504 50.016 14.249 50.76 ;
     RECT  13.955 0.192 14.281 4.68 ;
     RECT  13.504 36.912 14.285 38.904 ;
     RECT  13.504 41.664 14.285 41.928 ;
     RECT  13.504 51.84 14.285 52.296 ;
     RECT  14.281 0.144 14.291 4.68 ;
     RECT  13.504 9.648 14.291 15.864 ;
     RECT  13.619 20.832 14.321 22.056 ;
     RECT  13.504 6.384 14.332 8.328 ;
     RECT  14.285 38.208 14.357 38.904 ;
     RECT  14.321 20.832 14.365 21.672 ;
     RECT  13.619 75.072 14.429 75.144 ;
     RECT  13.601 56.784 14.533 59.784 ;
     RECT  14.291 9.648 14.537 10.872 ;
     RECT  14.291 12.336 14.537 15.864 ;
     RECT  13.504 35.424 14.569 35.448 ;
     RECT  14.497 36.48 14.569 36.504 ;
     RECT  13.709 67.488 14.573 70.824 ;
     RECT  14.429 75.12 14.573 75.144 ;
     RECT  13.637 54.096 14.579 54.504 ;
     RECT  14.357 38.88 14.605 38.904 ;
     RECT  13.504 39.888 14.605 39.912 ;
     RECT  13.504 16.848 14.609 17.496 ;
     RECT  13.66 18.672 14.641 18.792 ;
     RECT  13.504 25.728 14.641 26.808 ;
     RECT  13.504 62.016 14.645 62.04 ;
     RECT  13.619 72.912 14.717 73.32 ;
     RECT  14.641 25.728 14.771 27.096 ;
     RECT  14.332 6.384 14.785 8.04 ;
     RECT  14.285 51.888 14.821 52.296 ;
     RECT  14.537 9.792 14.825 10.872 ;
     RECT  14.533 56.208 14.825 59.784 ;
     RECT  14.717 72.912 14.825 73.032 ;
     RECT  13.853 48.336 14.828 48.408 ;
     RECT  14.249 50.016 14.828 50.712 ;
     RECT  14.828 48.288 14.915 48.408 ;
     RECT  14.828 49.536 14.915 50.712 ;
     RECT  14.365 20.832 14.929 21.432 ;
     RECT  14.285 41.664 14.965 41.688 ;
     RECT  14.929 20.256 15.001 21.432 ;
     RECT  13.715 29.184 15.001 29.976 ;
     RECT  13.889 33.648 15.037 34.104 ;
     RECT  14.569 35.424 15.037 36.504 ;
     RECT  14.825 56.208 15.077 58.008 ;
     RECT  14.579 54.48 15.145 54.504 ;
     RECT  15.077 56.208 15.145 57.48 ;
     RECT  14.573 67.536 15.145 70.824 ;
     RECT  14.821 51.888 15.155 53.064 ;
     RECT  14.725 24.24 15.181 24.264 ;
     RECT  15.037 33.648 15.185 36.504 ;
     RECT  15.185 34.08 15.203 36.504 ;
     RECT  14.825 59.04 15.203 59.784 ;
     RECT  15.145 54.48 15.229 57.48 ;
     RECT  15.203 59.136 15.253 59.784 ;
     RECT  13.504 43.872 15.257 45.528 ;
     RECT  14.965 41.616 15.289 41.688 ;
     RECT  14.641 18.144 15.301 18.792 ;
     RECT  15.181 24.24 15.301 24.504 ;
     RECT  15.301 23.952 15.325 24.504 ;
     RECT  15.257 45.408 15.325 45.528 ;
     RECT  15.203 34.08 15.329 34.392 ;
     RECT  15.289 41.568 15.349 41.688 ;
     RECT  15.001 20.16 15.356 21.432 ;
     RECT  15.301 18.144 15.388 19.176 ;
     RECT  15.349 41.568 15.395 42.216 ;
     RECT  15.356 20.16 15.397 21.576 ;
     RECT  15.325 23.04 15.397 24.504 ;
     RECT  14.605 38.88 15.397 39.912 ;
     RECT  14.537 12.432 15.401 15.864 ;
     RECT  15.397 20.16 15.401 24.504 ;
     RECT  14.825 9.792 15.437 10.344 ;
     RECT  14.213 63.216 15.437 63.24 ;
     RECT  15.401 20.16 15.443 23.064 ;
     RECT  14.771 26.208 15.5 27.096 ;
     RECT  14.291 0.144 15.577 4.104 ;
     RECT  15.5 26.208 15.587 27.24 ;
     RECT  15.001 29.088 15.587 29.976 ;
     RECT  15.401 13.056 15.589 15.864 ;
     RECT  14.915 48.384 15.613 48.408 ;
     RECT  14.243 31.632 15.617 31.656 ;
     RECT  15.397 38.736 15.617 39.912 ;
     RECT  15.257 43.872 15.617 44.328 ;
     RECT  14.915 49.824 15.644 50.712 ;
     RECT  15.155 51.888 15.644 52.488 ;
     RECT  15.217 5.232 15.649 5.256 ;
     RECT  14.785 6.288 15.649 8.04 ;
     RECT  15.395 41.616 15.725 42.216 ;
     RECT  15.649 5.232 15.779 8.04 ;
     RECT  15.587 29.616 15.793 29.976 ;
     RECT  15.401 24.48 15.865 24.504 ;
     RECT  15.865 24.48 15.905 24.6 ;
     RECT  15.145 67.536 15.905 71.64 ;
     RECT  15.589 15.36 15.937 15.864 ;
     RECT  14.609 16.848 15.937 17.112 ;
     RECT  15.388 18.144 15.937 18.696 ;
     RECT  15.589 13.056 16.019 13.992 ;
     RECT  15.793 29.616 16.045 30.312 ;
     RECT  15.253 59.136 16.049 60.024 ;
     RECT  15.779 5.232 16.057 7.992 ;
     RECT  15.577 0.144 16.081 4.2 ;
     RECT  16.057 5.232 16.081 7.752 ;
     RECT  15.203 35.424 16.115 35.448 ;
     RECT  15.203 36.48 16.115 36.504 ;
     RECT  15.437 10.32 16.117 10.344 ;
     RECT  16.049 59.232 16.157 60.024 ;
     RECT  15.644 49.824 16.163 52.488 ;
     RECT  16.019 13.296 16.193 13.992 ;
     RECT  15.905 68.4 16.193 71.64 ;
     RECT  15.229 56.208 16.225 57.48 ;
     RECT  15.145 72.672 16.225 72.696 ;
     RECT  16.193 68.736 16.265 71.64 ;
     RECT  16.153 28.08 16.297 28.104 ;
     RECT  16.081 0.144 16.373 7.752 ;
     RECT  16.189 61.008 16.373 61.608 ;
     RECT  15.725 41.616 16.451 42.12 ;
     RECT  16.117 10.32 16.549 10.824 ;
     RECT  16.225 56.208 16.553 58.152 ;
     RECT  15.937 15.36 16.585 18.696 ;
     RECT  15.443 20.16 16.585 20.856 ;
     RECT  15.443 22.176 16.585 23.064 ;
     RECT  15.613 48.384 16.585 48.456 ;
     RECT  16.157 59.712 16.621 60.024 ;
     RECT  15.905 24.576 16.625 24.6 ;
     RECT  16.265 69.072 16.625 71.64 ;
     RECT  16.585 48.24 16.661 48.456 ;
     RECT  15.325 45.408 16.693 46.104 ;
     RECT  16.369 63.84 16.693 63.864 ;
     RECT  16.693 63.84 16.733 64.056 ;
     RECT  16.625 70.656 16.733 71.64 ;
     RECT  16.733 71.232 16.741 71.64 ;
     RECT  16.225 72.672 16.741 72.888 ;
     RECT  15.617 38.976 16.765 39.912 ;
     RECT  16.741 71.232 16.765 72.888 ;
     RECT  16.549 9.696 16.801 10.824 ;
     RECT  16.585 20.16 16.805 23.064 ;
     RECT  16.045 29.616 16.805 30.792 ;
     RECT  16.765 71.232 16.828 73.464 ;
     RECT  16.373 0.144 16.835 7.656 ;
     RECT  16.585 14.832 16.837 18.696 ;
     RECT  15.587 26.208 16.837 27.096 ;
     RECT  16.297 28.08 16.837 28.152 ;
     RECT  16.069 32.448 16.837 32.472 ;
     RECT  16.553 56.208 16.873 57 ;
     RECT  16.837 14.832 16.885 18.744 ;
     RECT  16.805 20.16 16.885 20.28 ;
     RECT  16.837 26.208 16.945 28.152 ;
     RECT  15.229 54.48 16.945 54.504 ;
     RECT  16.837 31.92 16.981 32.472 ;
     RECT  16.828 72.912 16.985 73.464 ;
     RECT  15.617 44.064 17.017 44.328 ;
     RECT  16.693 45.36 17.017 46.104 ;
     RECT  16.835 2.736 17.021 7.656 ;
     RECT  16.765 38.208 17.021 39.912 ;
     RECT  16.373 61.584 17.029 61.608 ;
     RECT  15.329 34.368 17.053 34.392 ;
     RECT  16.451 41.616 17.077 41.88 ;
     RECT  16.945 54 17.089 54.504 ;
     RECT  16.805 21.6 17.129 23.064 ;
     RECT  16.981 31.248 17.129 32.472 ;
     RECT  16.193 13.296 17.161 13.32 ;
     RECT  17.029 61.584 17.164 62.424 ;
     RECT  16.945 26.208 17.165 29.208 ;
     RECT  16.163 51.504 17.165 52.488 ;
     RECT  17.017 44.064 17.197 46.104 ;
     RECT  16.553 58.128 17.197 58.152 ;
     RECT  16.621 59.712 17.197 60.504 ;
     RECT  16.873 74.544 17.201 74.568 ;
     RECT  17.077 40.56 17.219 41.88 ;
     RECT  17.053 34.368 17.237 35.352 ;
     RECT  17.197 44.064 17.237 46.728 ;
     RECT  16.828 71.232 17.237 71.256 ;
     RECT  17.089 53.52 17.269 54.504 ;
     RECT  16.873 55.536 17.269 57 ;
     RECT  16.625 69.072 17.305 69.48 ;
     RECT  17.165 26.208 17.309 28.68 ;
     RECT  17.021 6.72 17.341 7.656 ;
     RECT  17.021 2.736 17.381 5.64 ;
     RECT  17.219 41.76 17.411 41.88 ;
     RECT  17.305 74.976 17.417 75 ;
     RECT  17.197 42.96 17.452 42.984 ;
     RECT  17.197 58.128 17.485 60.504 ;
     RECT  17.164 61.584 17.485 62.136 ;
     RECT  17.485 58.128 17.525 62.136 ;
     RECT  17.411 41.856 17.555 41.88 ;
     RECT  17.341 6.72 17.557 8.52 ;
     RECT  16.801 9.696 17.561 11.4 ;
     RECT  17.021 38.208 17.561 39 ;
     RECT  16.369 36.672 17.593 36.696 ;
     RECT  17.305 68.928 17.593 69.48 ;
     RECT  16.885 14.832 17.597 20.28 ;
     RECT  17.593 68.928 17.597 70.152 ;
     RECT  17.129 22.272 17.629 23.064 ;
     RECT  17.129 32.112 17.629 32.472 ;
     RECT  16.985 73.44 17.629 73.464 ;
     RECT  17.269 53.52 17.633 57 ;
     RECT  16.163 49.824 17.665 49.992 ;
     RECT  17.665 49.344 17.701 49.992 ;
     RECT  17.561 10.848 17.737 11.4 ;
     RECT  17.161 12.528 17.737 13.32 ;
     RECT  17.597 14.832 17.737 17.352 ;
     RECT  17.309 26.208 17.809 28.488 ;
     RECT  17.237 35.328 17.845 35.352 ;
     RECT  16.733 64.032 17.852 64.056 ;
     RECT  16.835 0.144 17.9 1.512 ;
     RECT  17.381 2.736 17.9 2.904 ;
     RECT  17.237 44.88 17.953 46.728 ;
     RECT  17.219 40.56 17.989 40.584 ;
     RECT  17.809 25.824 18.025 28.488 ;
     RECT  17.633 56.592 18.025 57 ;
     RECT  17.053 67.296 18.025 67.32 ;
     RECT  17.845 35.328 18.169 35.592 ;
     RECT  17.593 36.672 18.169 37.08 ;
     RECT  17.597 68.928 18.169 68.952 ;
     RECT  18.025 56.592 18.181 57.144 ;
     RECT  17.525 58.128 18.181 61.128 ;
     RECT  17.665 43.296 18.205 43.32 ;
     RECT  17.165 51.696 18.205 52.488 ;
     RECT  18.169 35.328 18.229 37.08 ;
     RECT  17.381 3.984 18.236 5.64 ;
     RECT  17.557 6.72 18.236 8.568 ;
     RECT  17.852 63.168 18.241 64.056 ;
     RECT  18.169 65.664 18.241 65.688 ;
     RECT  18.025 25.728 18.277 28.488 ;
     RECT  18.205 51.36 18.313 52.488 ;
     RECT  17.633 53.52 18.313 55.56 ;
     RECT  18.241 63.168 18.313 65.784 ;
     RECT  17.9 0.144 18.421 2.904 ;
     RECT  18.236 3.984 18.421 8.568 ;
     RECT  17.629 32.112 18.457 33.048 ;
     RECT  18.421 0.144 18.467 8.568 ;
     RECT  17.525 62.112 18.493 62.136 ;
     RECT  18.313 63.168 18.493 65.976 ;
     RECT  18.181 56.592 18.529 61.128 ;
     RECT  18.493 62.112 18.529 65.976 ;
     RECT  18.467 2.016 18.608 8.568 ;
     RECT  17.561 9.696 18.608 9.864 ;
     RECT  17.737 10.848 18.608 17.352 ;
     RECT  17.597 18.432 18.608 19.656 ;
     RECT  17.629 22.272 18.608 23.4 ;
     RECT  18.277 25.008 18.608 28.488 ;
     RECT  16.805 30.192 18.608 30.216 ;
     RECT  18.457 32.112 18.608 33.096 ;
     RECT  18.229 35.28 18.608 37.08 ;
     RECT  17.561 38.976 18.608 39 ;
     RECT  17.989 40.416 18.608 40.584 ;
     RECT  18.205 43.296 18.608 43.848 ;
     RECT  17.953 44.88 18.608 47.208 ;
     RECT  16.661 48.24 18.608 48.264 ;
     RECT  17.701 49.344 18.608 50.04 ;
     RECT  18.313 51.36 18.608 55.56 ;
     RECT  18.529 56.592 18.608 65.976 ;
     RECT  18.025 67.248 18.608 67.32 ;
     RECT  18.169 68.736 18.608 68.952 ;
     RECT  17.597 70.128 18.608 70.152 ;
     RECT  17.629 73.44 18.608 73.896 ;
     RECT  18.608 2.016 18.712 75.612 ;
     RECT  18.712 2.016 18.904 75.342 ;
     RECT  18.904 2.016 18.929 8.52 ;
     RECT  18.929 2.016 18.965 7.944 ;
     RECT  18.965 2.016 19.037 7.656 ;
     RECT  18.904 33.024 19.037 33.048 ;
     RECT  19.037 2.016 19.043 7.272 ;
     RECT  18.904 70.368 19.043 72.792 ;
     RECT  18.904 22.464 19.181 24.024 ;
     RECT  19.043 5.136 19.217 7.272 ;
     RECT  18.904 25.008 19.379 27.912 ;
     RECT  18.904 20.112 19.397 21.432 ;
     RECT  19.379 25.392 19.397 27.912 ;
     RECT  18.904 56.544 19.397 59.736 ;
     RECT  19.397 25.728 19.433 27.912 ;
     RECT  18.904 62.208 19.433 64.44 ;
     RECT  18.904 9.696 19.475 12.024 ;
     RECT  18.904 43.104 19.505 45.528 ;
     RECT  18.467 0.144 19.609 0.984 ;
     RECT  19.043 2.016 19.609 3.96 ;
     RECT  18.904 65.664 19.613 67.032 ;
     RECT  19.397 56.544 19.649 56.616 ;
     RECT  19.609 0.144 19.715 3.96 ;
     RECT  19.715 0.144 19.793 1.128 ;
     RECT  19.793 0.24 19.837 1.128 ;
     RECT  18.904 48.24 19.897 48.264 ;
     RECT  19.433 62.976 19.897 64.44 ;
     RECT  18.904 40.56 19.925 40.968 ;
     RECT  19.475 9.696 19.933 11.592 ;
     RECT  18.904 73.968 19.933 73.992 ;
     RECT  18.904 35.328 19.957 35.88 ;
     RECT  18.904 37.056 19.957 39 ;
     RECT  19.925 40.56 19.957 41.064 ;
     RECT  19.957 40.416 19.964 41.064 ;
     RECT  19.964 40.416 19.967 41.304 ;
     RECT  18.904 31.872 19.969 31.896 ;
     RECT  19.897 47.808 19.969 48.264 ;
     RECT  18.904 49.824 19.969 50.184 ;
     RECT  18.904 18.576 19.997 18.744 ;
     RECT  19.957 35.328 20.003 39 ;
     RECT  19.897 62.976 20.009 64.488 ;
     RECT  19.933 8.736 20.017 11.592 ;
     RECT  18.904 68.736 20.041 69.144 ;
     RECT  19.505 43.824 20.045 45.528 ;
     RECT  19.967 40.416 20.051 42.216 ;
     RECT  19.715 2.544 20.053 3.96 ;
     RECT  20.051 40.416 20.081 40.584 ;
     RECT  19.969 47.808 20.101 50.184 ;
     RECT  20.101 47.472 20.113 50.184 ;
     RECT  20.003 36.48 20.117 39 ;
     RECT  19.613 66.864 20.149 67.032 ;
     RECT  19.217 5.52 20.185 7.272 ;
     RECT  18.904 13.296 20.185 13.32 ;
     RECT  20.113 46.752 20.188 50.184 ;
     RECT  19.397 20.544 20.221 21.432 ;
     RECT  19.181 22.464 20.221 23.304 ;
     RECT  19.043 70.752 20.225 71.208 ;
     RECT  19.433 26.208 20.243 27.912 ;
     RECT  18.904 51.696 20.257 55.128 ;
     RECT  20.113 56.448 20.257 56.472 ;
     RECT  19.933 73.968 20.261 74.904 ;
     RECT  19.997 18.576 20.293 18.84 ;
     RECT  20.041 68.688 20.329 69.144 ;
     RECT  20.185 5.52 20.333 7.32 ;
     RECT  18.904 29.328 20.365 29.88 ;
     RECT  20.293 18.576 20.377 19.416 ;
     RECT  20.188 47.808 20.396 50.184 ;
     RECT  20.257 51.696 20.396 56.472 ;
     RECT  20.243 26.64 20.401 27.912 ;
     RECT  20.365 29.328 20.401 30.072 ;
     RECT  18.904 16.464 20.473 17.448 ;
     RECT  20.377 18.576 20.473 18.84 ;
     RECT  20.017 9.216 20.477 11.592 ;
     RECT  20.225 70.992 20.477 71.208 ;
     RECT  20.396 47.808 20.483 56.472 ;
     RECT  20.149 66.864 20.545 67.176 ;
     RECT  20.401 26.64 20.549 30.072 ;
     RECT  20.483 51.648 20.549 56.472 ;
     RECT  20.549 29.328 20.579 30.072 ;
     RECT  19.613 65.664 20.581 65.784 ;
     RECT  20.545 66.864 20.581 67.272 ;
     RECT  19.969 31.392 20.585 31.896 ;
     RECT  20.581 65.664 20.621 67.272 ;
     RECT  20.437 62.592 20.627 62.616 ;
     RECT  20.621 65.664 20.627 66.216 ;
     RECT  20.329 68.688 20.657 69.192 ;
     RECT  19.837 0.288 20.725 1.128 ;
     RECT  20.053 2.544 20.725 4.488 ;
     RECT  20.333 5.52 20.729 7.176 ;
     RECT  20.621 67.248 20.761 67.272 ;
     RECT  20.477 10.848 20.797 11.592 ;
     RECT  20.549 52.992 20.797 56.472 ;
     RECT  20.045 43.824 20.801 45.192 ;
     RECT  20.725 0.288 20.821 4.488 ;
     RECT  20.821 0.192 20.867 4.488 ;
     RECT  20.549 26.64 20.873 27.768 ;
     RECT  18.904 15.456 20.905 15.48 ;
     RECT  20.473 16.464 20.905 18.84 ;
     RECT  18.904 60.816 20.905 60.84 ;
     RECT  20.905 15.456 20.909 18.84 ;
     RECT  20.477 71.088 20.909 71.208 ;
     RECT  20.657 69.072 20.941 69.192 ;
     RECT  20.909 71.184 20.941 71.208 ;
     RECT  19.043 72.192 20.941 72.792 ;
     RECT  20.797 52.992 20.972 56.568 ;
     RECT  19.397 57.648 20.972 59.736 ;
     RECT  20.801 43.824 20.977 44.952 ;
     RECT  20.909 17.952 21.017 18.84 ;
     RECT  20.761 67.248 21.017 67.368 ;
     RECT  20.797 10.848 21.049 11.928 ;
     RECT  20.003 35.328 21.049 35.352 ;
     RECT  21.049 34.704 21.071 35.352 ;
     RECT  20.197 24.336 21.077 24.36 ;
     RECT  20.972 52.992 21.085 59.736 ;
     RECT  21.017 67.344 21.089 67.368 ;
     RECT  20.977 43.776 21.107 44.952 ;
     RECT  20.761 31.92 21.109 31.944 ;
     RECT  21.077 24.336 21.121 24.552 ;
     RECT  20.185 13.296 21.125 13.656 ;
     RECT  20.477 9.216 21.157 9.864 ;
     RECT  21.125 13.296 21.161 13.32 ;
     RECT  21.071 34.704 21.193 35.4 ;
     RECT  20.905 60.816 21.193 61.032 ;
     RECT  20.483 47.808 21.197 50.184 ;
     RECT  21.121 24.336 21.205 24.648 ;
     RECT  21.049 25.632 21.229 25.656 ;
     RECT  20.873 26.64 21.229 26.76 ;
     RECT  21.157 8.544 21.233 9.864 ;
     RECT  20.729 5.616 21.251 7.176 ;
     RECT  21.109 31.92 21.269 32.472 ;
     RECT  21.251 6.768 21.329 7.176 ;
     RECT  21.233 8.544 21.329 8.952 ;
     RECT  20.221 20.544 21.337 23.304 ;
     RECT  21.205 24.336 21.337 24.552 ;
     RECT  20.549 51.648 21.341 51.768 ;
     RECT  21.329 6.768 21.413 8.952 ;
     RECT  20.909 15.456 21.443 16.728 ;
     RECT  21.049 10.848 21.481 11.976 ;
     RECT  20.867 0.192 21.485 3.432 ;
     RECT  20.081 40.56 21.493 40.584 ;
     RECT  21.485 0.24 21.539 3.432 ;
     RECT  20.117 37.2 21.553 39 ;
     RECT  21.085 52.992 21.553 59.832 ;
     RECT  21.193 60.816 21.553 61.464 ;
     RECT  21.107 43.776 21.596 44.28 ;
     RECT  21.539 0.24 21.629 2.856 ;
     RECT  21.251 5.616 21.629 5.736 ;
     RECT  21.481 10.752 21.629 11.976 ;
     RECT  21.337 20.544 21.629 24.552 ;
     RECT  20.051 42.192 21.665 42.216 ;
     RECT  20.261 74.88 21.665 74.904 ;
     RECT  20.867 4.416 21.697 4.488 ;
     RECT  21.443 15.456 21.697 16.584 ;
     RECT  20.873 27.744 21.809 27.768 ;
     RECT  21.596 43.344 21.809 44.28 ;
     RECT  20.627 65.76 21.809 66.216 ;
     RECT  21.493 40.272 21.841 40.584 ;
     RECT  20.941 69.072 21.841 69.72 ;
     RECT  20.905 33.6 21.877 33.624 ;
     RECT  21.193 34.608 21.877 35.4 ;
     RECT  21.841 69.072 21.877 70.008 ;
     RECT  20.579 30.048 21.881 30.072 ;
     RECT  21.197 49.824 21.881 50.184 ;
     RECT  21.661 13.104 21.923 13.128 ;
     RECT  21.697 14.928 21.949 16.584 ;
     RECT  21.553 52.992 21.949 61.464 ;
     RECT  21.629 10.8 22.057 11.976 ;
     RECT  20.009 63.792 22.057 64.488 ;
     RECT  21.809 65.76 22.057 66.024 ;
     RECT  20.941 71.184 22.057 72.792 ;
     RECT  21.341 51.696 22.093 51.768 ;
     RECT  21.949 52.992 22.093 61.848 ;
     RECT  22.093 51.696 22.097 61.848 ;
     RECT  21.877 68.448 22.129 70.008 ;
     RECT  22.057 71.184 22.129 73.512 ;
     RECT  21.017 17.952 22.165 18.792 ;
     RECT  20.188 46.752 22.165 46.776 ;
     RECT  22.165 17.664 22.205 18.792 ;
     RECT  21.629 21.12 22.211 24.552 ;
     RECT  22.165 46.656 22.213 46.776 ;
     RECT  21.413 8.928 22.241 8.952 ;
     RECT  22.213 46.656 22.259 46.824 ;
     RECT  21.949 14.832 22.277 16.584 ;
     RECT  21.877 33.6 22.277 35.4 ;
     RECT  21.197 47.808 22.277 48.744 ;
     RECT  22.205 18.672 22.309 18.792 ;
     RECT  21.413 6.768 22.345 7.608 ;
     RECT  22.277 14.832 22.382 15.72 ;
     RECT  22.309 9.552 22.392 9.672 ;
     RECT  21.629 0.288 22.393 2.856 ;
     RECT  21.269 31.92 22.421 31.944 ;
     RECT  21.553 36.96 22.453 39 ;
     RECT  21.841 40.272 22.453 41.016 ;
     RECT  21.229 25.632 22.489 26.76 ;
     RECT  22.057 30.672 22.489 30.696 ;
     RECT  22.205 17.664 22.501 17.688 ;
     RECT  22.345 6.24 22.549 7.608 ;
     RECT  21.697 4.416 22.561 5.112 ;
     RECT  22.097 51.696 22.601 57.288 ;
     RECT  22.501 17.616 22.637 17.688 ;
     RECT  22.392 9.552 22.705 9.72 ;
     RECT  22.057 10.8 22.705 12.552 ;
     RECT  21.809 43.344 22.705 44.088 ;
     RECT  22.489 25.632 22.709 26.904 ;
     RECT  22.709 25.632 22.739 26.808 ;
     RECT  22.277 33.6 22.741 33.768 ;
     RECT  22.129 68.448 22.745 70.056 ;
     RECT  22.561 4.128 22.777 5.112 ;
     RECT  22.129 71.088 22.781 73.8 ;
     RECT  22.277 35.328 22.837 35.4 ;
     RECT  22.211 21.648 22.844 24.552 ;
     RECT  22.097 58.464 22.853 61.848 ;
     RECT  22.741 67.152 22.853 67.176 ;
     RECT  22.777 4.128 22.885 5.208 ;
     RECT  22.549 6.24 22.885 8.568 ;
     RECT  22.781 72.192 22.885 73.8 ;
     RECT  22.844 21.648 22.889 24.6 ;
     RECT  22.057 63.792 22.889 66.024 ;
     RECT  22.885 4.128 22.925 8.568 ;
     RECT  22.889 24.432 22.931 24.6 ;
     RECT  22.745 68.448 22.957 69.48 ;
     RECT  21.881 49.824 22.993 49.848 ;
     RECT  22.885 72.192 22.993 74.616 ;
     RECT  22.705 42.768 22.997 44.088 ;
     RECT  22.853 58.464 22.997 60.648 ;
     RECT  22.957 68.112 22.997 69.48 ;
     RECT  22.889 63.792 23.029 64.104 ;
     RECT  22.705 9.552 23.065 12.552 ;
     RECT  22.309 18.672 23.173 19.272 ;
     RECT  22.489 30.672 23.173 30.744 ;
     RECT  22.889 21.648 23.209 23.4 ;
     RECT  22.993 72.192 23.209 74.664 ;
     RECT  22.837 35.328 23.245 35.832 ;
     RECT  23.173 30.144 23.281 30.744 ;
     RECT  23.209 72.192 23.281 74.856 ;
     RECT  23.245 34.8 23.317 35.976 ;
     RECT  22.453 36.96 23.317 41.016 ;
     RECT  22.853 61.776 23.317 61.848 ;
     RECT  23.029 63.072 23.317 64.104 ;
     RECT  21.805 28.992 23.353 29.016 ;
     RECT  23.281 30.144 23.353 30.792 ;
     RECT  23.173 18.144 23.413 19.272 ;
     RECT  23.353 28.992 23.413 30.792 ;
     RECT  22.601 55.584 23.569 57.288 ;
     RECT  23.077 17.088 23.605 17.112 ;
     RECT  23.413 18.144 23.605 19.656 ;
     RECT  23.413 28.464 23.605 30.792 ;
     RECT  22.601 51.696 23.605 54.504 ;
     RECT  23.569 55.584 23.605 57.96 ;
     RECT  22.277 48.144 23.641 48.744 ;
     RECT  22.382 14.832 23.797 15.672 ;
     RECT  22.259 46.752 23.857 46.824 ;
     RECT  22.741 32.976 23.893 33.768 ;
     RECT  22.781 71.088 23.929 71.112 ;
     RECT  23.893 32.736 23.965 33.768 ;
     RECT  23.317 34.8 23.965 41.016 ;
     RECT  22.889 65.136 24.001 66.024 ;
     RECT  22.393 0.288 24.008 2.808 ;
     RECT  22.925 4.128 24.008 7.752 ;
     RECT  23.065 9.552 24.008 13.128 ;
     RECT  23.797 14.208 24.008 15.672 ;
     RECT  23.605 17.088 24.008 19.656 ;
     RECT  23.209 21.168 24.008 23.4 ;
     RECT  22.931 24.432 24.008 24.552 ;
     RECT  22.739 25.824 24.008 26.808 ;
     RECT  23.605 27.936 24.008 30.792 ;
     RECT  23.965 32.736 24.008 41.016 ;
     RECT  22.997 42.768 24.008 43.368 ;
     RECT  23.893 44.976 24.008 45 ;
     RECT  23.857 46.752 24.008 46.92 ;
     RECT  23.641 47.952 24.008 48.744 ;
     RECT  22.993 49.824 24.008 50.328 ;
     RECT  23.605 51.696 24.008 57.96 ;
     RECT  22.997 58.944 24.008 60.648 ;
     RECT  23.317 61.776 24.008 64.104 ;
     RECT  24.001 65.136 24.008 66.072 ;
     RECT  22.997 68.112 24.008 69.192 ;
     RECT  23.929 70.272 24.008 71.112 ;
     RECT  23.281 72.192 24.008 74.904 ;
     RECT  24.008 0.288 24.085 75.612 ;
     RECT  24.085 0.192 24.112 75.612 ;
     RECT  24.112 0.192 24.289 75.342 ;
     RECT  24.289 0.144 24.304 75.342 ;
     RECT  24.304 10.704 24.419 14.28 ;
     RECT  24.304 28.704 24.419 29.016 ;
     RECT  24.304 0.144 24.515 6.84 ;
     RECT  24.304 44.304 24.545 45 ;
     RECT  24.304 59.76 24.545 61.224 ;
     RECT  24.515 0.144 24.563 1.752 ;
     RECT  24.304 15.456 24.563 19.944 ;
     RECT  24.515 2.784 24.576 3.432 ;
     RECT  24.304 62.496 24.617 64.056 ;
     RECT  24.304 72.192 24.653 74.904 ;
     RECT  24.304 9.12 24.797 9.672 ;
     RECT  24.304 70.272 24.797 70.68 ;
     RECT  24.419 10.848 24.803 14.28 ;
     RECT  24.304 40.56 24.833 40.584 ;
     RECT  24.803 12.528 24.892 14.28 ;
     RECT  24.304 35.808 25.013 39.384 ;
     RECT  24.892 13.68 25.057 14.28 ;
     RECT  24.304 30.144 25.085 34.152 ;
     RECT  24.653 72.192 25.085 74.856 ;
     RECT  24.515 5.088 25.091 6.84 ;
     RECT  24.419 28.992 25.121 29.016 ;
     RECT  25.085 30.144 25.121 30.84 ;
     RECT  24.304 23.376 25.229 26.76 ;
     RECT  25.229 23.376 25.265 24.504 ;
     RECT  24.892 12.528 25.283 12.648 ;
     RECT  24.304 47.952 25.373 54.6 ;
     RECT  25.091 5.088 25.379 5.256 ;
     RECT  25.091 6.72 25.379 6.84 ;
     RECT  24.304 68.928 25.405 68.952 ;
     RECT  24.304 56.352 25.409 58.776 ;
     RECT  25.405 68.928 25.409 69.048 ;
     RECT  24.803 10.848 25.441 11.4 ;
     RECT  24.797 70.512 25.441 70.68 ;
     RECT  25.085 72.192 25.441 72.84 ;
     RECT  24.304 46.896 25.481 46.92 ;
     RECT  24.304 21.072 25.505 21.096 ;
     RECT  25.333 7.968 25.513 7.992 ;
     RECT  25.505 21.072 25.513 21.672 ;
     RECT  25.379 5.232 25.517 5.256 ;
     RECT  25.373 51.168 25.549 54.6 ;
     RECT  25.513 21.072 25.589 22.2 ;
     RECT  24.563 0.144 25.621 1.128 ;
     RECT  24.563 15.696 25.621 19.944 ;
     RECT  25.057 14.208 25.657 14.28 ;
     RECT  25.621 15.456 25.657 19.944 ;
     RECT  25.621 0.144 25.661 1.752 ;
     RECT  25.379 6.72 25.661 6.744 ;
     RECT  25.657 14.208 25.661 19.944 ;
     RECT  25.085 31.92 25.667 34.152 ;
     RECT  25.661 16.8 25.693 19.944 ;
     RECT  25.441 70.512 25.697 72.84 ;
     RECT  25.085 73.92 25.729 74.856 ;
     RECT  25.697 70.656 25.733 72.84 ;
     RECT  25.441 10.272 25.765 11.4 ;
     RECT  25.283 12.528 25.765 12.552 ;
     RECT  25.589 22.176 25.765 22.2 ;
     RECT  25.729 23.184 25.765 23.208 ;
     RECT  24.304 65.136 25.765 67.176 ;
     RECT  24.545 44.304 25.769 44.328 ;
     RECT  25.409 56.352 25.769 58.728 ;
     RECT  25.409 69.024 25.805 69.048 ;
     RECT  24.797 9.12 25.837 9.144 ;
     RECT  25.765 10.272 25.837 12.552 ;
     RECT  25.765 64.896 25.837 67.176 ;
     RECT  25.661 0.192 25.859 1.752 ;
     RECT  25.667 32.736 25.873 34.152 ;
     RECT  25.549 51.168 25.873 55.08 ;
     RECT  25.769 56.352 25.913 58.152 ;
     RECT  24.576 3.072 25.981 3.432 ;
     RECT  25.873 51.168 25.985 55.224 ;
     RECT  25.837 9.12 26.005 12.552 ;
     RECT  25.013 35.808 26.017 35.832 ;
     RECT  25.013 36.912 26.017 39.384 ;
     RECT  24.545 60.864 26.017 61.224 ;
     RECT  24.617 62.496 26.017 63.72 ;
     RECT  26.005 9.072 26.029 12.552 ;
     RECT  25.121 30.72 26.053 30.84 ;
     RECT  25.913 56.352 26.057 57.048 ;
     RECT  24.545 59.76 26.089 59.832 ;
     RECT  26.017 60.864 26.089 63.72 ;
     RECT  25.733 71.088 26.093 72.84 ;
     RECT  25.981 2.88 26.101 3.432 ;
     RECT  25.373 47.952 26.125 50.136 ;
     RECT  26.017 35.808 26.129 39.384 ;
     RECT  25.693 16.8 26.149 19.992 ;
     RECT  25.589 21.072 26.149 21.096 ;
     RECT  26.093 72.384 26.161 72.84 ;
     RECT  26.089 59.76 26.195 63.72 ;
     RECT  25.873 32.736 26.201 34.776 ;
     RECT  25.729 73.92 26.201 74.904 ;
     RECT  25.229 25.632 26.233 26.76 ;
     RECT  26.149 16.8 26.291 21.096 ;
     RECT  26.029 10.944 26.305 12.552 ;
     RECT  25.285 43.296 26.305 43.32 ;
     RECT  26.291 19.392 26.309 21.096 ;
     RECT  26.305 10.944 26.339 12.6 ;
     RECT  25.765 22.176 26.339 23.208 ;
     RECT  26.101 2.256 26.341 3.432 ;
     RECT  25.661 14.208 26.341 15.72 ;
     RECT  26.201 33.456 26.341 34.776 ;
     RECT  26.129 35.808 26.341 36.936 ;
     RECT  26.339 22.8 26.345 23.208 ;
     RECT  26.305 43.104 26.345 43.32 ;
     RECT  26.341 13.872 26.387 15.72 ;
     RECT  26.309 19.392 26.387 20.616 ;
     RECT  26.341 33.456 26.409 36.936 ;
     RECT  26.161 72.384 26.413 72.888 ;
     RECT  26.409 33.456 26.428 35.16 ;
     RECT  25.985 53.328 26.557 55.224 ;
     RECT  25.837 64.848 26.557 67.176 ;
     RECT  26.017 41.376 26.593 41.4 ;
     RECT  26.341 2.256 26.677 3.72 ;
     RECT  26.053 30.72 26.677 31.704 ;
     RECT  25.265 24.336 26.701 24.504 ;
     RECT  26.233 25.632 26.701 27.336 ;
     RECT  26.093 71.088 26.701 71.304 ;
     RECT  26.345 43.104 26.725 43.128 ;
     RECT  25.909 45.696 26.725 45.72 ;
     RECT  26.677 2.256 26.737 3.912 ;
     RECT  26.521 5.28 26.737 5.304 ;
     RECT  26.029 9.072 26.737 9.96 ;
     RECT  26.701 24.336 26.737 27.336 ;
     RECT  26.593 40.416 26.771 41.4 ;
     RECT  26.737 2.256 26.777 5.304 ;
     RECT  26.677 30.672 26.777 31.704 ;
     RECT  26.557 64.848 26.809 67.608 ;
     RECT  26.809 64.848 26.813 68.136 ;
     RECT  26.777 2.256 26.819 2.856 ;
     RECT  26.339 10.944 26.819 10.968 ;
     RECT  26.777 30.768 26.821 31.704 ;
     RECT  26.821 30.768 26.849 32.184 ;
     RECT  26.771 41.088 26.849 41.4 ;
     RECT  26.849 31.632 26.867 32.184 ;
     RECT  26.428 33.648 26.885 35.16 ;
     RECT  26.867 31.68 26.908 32.184 ;
     RECT  26.819 2.832 26.915 2.856 ;
     RECT  26.387 19.968 26.921 20.616 ;
     RECT  26.339 12.528 26.953 12.6 ;
     RECT  26.387 13.872 26.953 14.28 ;
     RECT  26.813 64.848 26.993 64.872 ;
     RECT  26.917 21.648 27.001 21.672 ;
     RECT  26.813 66.048 27.025 68.136 ;
     RECT  26.777 3.888 27.029 5.304 ;
     RECT  25.513 7.92 27.061 7.992 ;
     RECT  26.737 9.024 27.061 9.96 ;
     RECT  27.061 7.92 27.065 9.96 ;
     RECT  26.129 38.112 27.097 39.384 ;
     RECT  26.953 12.528 27.101 14.28 ;
     RECT  26.291 16.8 27.101 18.264 ;
     RECT  26.725 45.024 27.101 45.72 ;
     RECT  27.101 12.528 27.155 13.704 ;
     RECT  26.195 61.008 27.173 63.72 ;
     RECT  26.413 72.384 27.205 72.936 ;
     RECT  27.025 66.048 27.209 69 ;
     RECT  26.387 15.456 27.26 15.72 ;
     RECT  26.125 47.568 27.269 50.136 ;
     RECT  26.737 24.336 27.277 27.864 ;
     RECT  26.195 59.76 27.277 59.784 ;
     RECT  27.205 72.288 27.277 72.936 ;
     RECT  26.201 73.92 27.277 73.944 ;
     RECT  27.173 62.016 27.301 63.72 ;
     RECT  25.859 0.192 27.313 1.128 ;
     RECT  27.101 17.664 27.317 18.264 ;
     RECT  26.057 57.024 27.317 57.048 ;
     RECT  27.26 15.456 27.347 16.68 ;
     RECT  27.313 0.192 27.349 1.176 ;
     RECT  26.409 36.528 27.353 36.936 ;
     RECT  27.269 46.752 27.353 50.136 ;
     RECT  27.277 24.336 27.395 27.912 ;
     RECT  26.725 43.008 27.421 43.128 ;
     RECT  26.557 53.328 27.421 55.368 ;
     RECT  27.395 25.632 27.445 27.912 ;
     RECT  27.353 36.672 27.461 36.936 ;
     RECT  27.445 25.632 27.491 28.68 ;
     RECT  27.173 61.008 27.497 61.032 ;
     RECT  27.491 28.656 27.532 28.68 ;
     RECT  27.349 0.144 27.533 1.176 ;
     RECT  27.209 66.048 27.533 68.136 ;
     RECT  27.491 25.632 27.569 27.384 ;
     RECT  27.421 52.992 27.569 55.368 ;
     RECT  27.533 66.048 27.569 66.456 ;
     RECT  27.533 0.192 27.587 1.176 ;
     RECT  27.533 68.112 27.605 68.136 ;
     RECT  27.569 66.384 27.641 66.408 ;
     RECT  26.345 23.184 27.644 23.208 ;
     RECT  27.347 15.456 27.673 15.72 ;
     RECT  27.317 18.24 27.673 18.264 ;
     RECT  27.644 22.848 27.673 23.208 ;
     RECT  27.395 24.336 27.673 24.456 ;
     RECT  27.673 22.848 27.731 24.456 ;
     RECT  27.731 22.992 27.757 24.456 ;
     RECT  27.349 44.256 27.785 44.28 ;
     RECT  27.101 45.312 27.785 45.72 ;
     RECT  26.885 33.648 27.821 33.672 ;
     RECT  27.421 42.144 27.827 43.128 ;
     RECT  27.733 6.288 27.857 6.312 ;
     RECT  27.673 18.24 27.857 18.792 ;
     RECT  27.065 7.968 27.889 9.96 ;
     RECT  27.353 47.712 27.889 50.136 ;
     RECT  25.985 51.168 27.889 51.72 ;
     RECT  27.097 38.064 27.893 39.384 ;
     RECT  27.817 11.424 27.901 11.976 ;
     RECT  27.587 0.192 27.916 0.6 ;
     RECT  27.029 4.416 27.925 5.304 ;
     RECT  27.857 18.768 27.929 18.792 ;
     RECT  26.849 41.088 27.932 41.112 ;
     RECT  27.827 42.144 27.932 43.032 ;
     RECT  27.889 7.968 27.961 10.296 ;
     RECT  27.889 47.712 27.997 51.72 ;
     RECT  27.569 52.992 27.997 54.648 ;
     RECT  27.529 56.448 28.001 56.472 ;
     RECT  27.932 41.088 28.019 43.032 ;
     RECT  27.961 7.968 28.033 10.92 ;
     RECT  27.925 4.416 28.037 6.264 ;
     RECT  27.461 36.672 28.037 36.696 ;
     RECT  28.019 41.088 28.037 41.112 ;
     RECT  27.277 59.328 28.037 59.784 ;
     RECT  28.037 4.416 28.069 5.112 ;
     RECT  27.893 38.064 28.073 39 ;
     RECT  25.913 58.128 28.145 58.152 ;
     RECT  27.916 0.192 28.163 0.552 ;
     RECT  28.069 3.936 28.249 5.112 ;
     RECT  26.885 35.136 28.261 35.16 ;
     RECT  27.155 13.056 28.285 13.704 ;
     RECT  27.673 14.784 28.285 15.72 ;
     RECT  28.213 60.816 28.3 60.984 ;
     RECT  28.285 13.056 28.325 15.72 ;
     RECT  27.277 72.288 28.361 73.944 ;
     RECT  28.261 34.8 28.393 35.16 ;
     RECT  28.037 59.76 28.465 59.784 ;
     RECT  26.921 20.592 28.681 20.616 ;
     RECT  27.637 1.728 28.753 1.752 ;
     RECT  28.361 72.384 28.753 73.944 ;
     RECT  28.325 15.456 28.861 15.72 ;
     RECT  28.163 0.528 28.897 0.552 ;
     RECT  28.753 1.728 28.897 2.232 ;
     RECT  28.537 18.816 28.897 18.84 ;
     RECT  28.897 0.528 28.981 2.232 ;
     RECT  28.249 3.408 28.981 5.112 ;
     RECT  26.701 70.32 29.005 71.304 ;
     RECT  27.757 22.992 29.041 23.256 ;
     RECT  27.757 24.432 29.041 24.456 ;
     RECT  28.897 55.728 29.041 55.752 ;
     RECT  28.717 68.448 29.041 68.472 ;
     RECT  28.073 38.976 29.077 39 ;
     RECT  28.465 59.76 29.077 59.832 ;
     RECT  29.041 68.448 29.077 68.664 ;
     RECT  29.077 68.352 29.113 68.664 ;
     RECT  29.041 22.992 29.141 24.456 ;
     RECT  27.569 25.824 29.141 27.384 ;
     RECT  28.681 20.256 29.18 20.616 ;
     RECT  27.997 47.712 29.185 54.648 ;
     RECT  29.041 55.68 29.185 56.472 ;
     RECT  29.077 58.656 29.185 59.832 ;
     RECT  28.981 0.528 29.221 5.112 ;
     RECT  28.897 18.816 29.269 19.272 ;
     RECT  29.18 20.256 29.269 21.096 ;
     RECT  29.141 22.992 29.269 27.384 ;
     RECT  27.785 45.312 29.269 45.336 ;
     RECT  29.185 57.6 29.269 59.832 ;
     RECT  28.3 60.816 29.269 60.84 ;
     RECT  27.301 62.016 29.269 63.816 ;
     RECT  28.393 34.224 29.293 35.16 ;
     RECT  29.113 68.16 29.329 68.664 ;
     RECT  28.033 7.632 29.365 10.92 ;
     RECT  29.221 0.288 29.408 5.112 ;
     RECT  28.037 6.192 29.408 6.264 ;
     RECT  29.365 7.392 29.408 10.92 ;
     RECT  27.901 11.952 29.408 11.976 ;
     RECT  28.325 13.056 29.408 14.328 ;
     RECT  28.861 15.456 29.408 16.536 ;
     RECT  29.269 18.816 29.408 21.096 ;
     RECT  29.269 22.992 29.408 27.624 ;
     RECT  26.908 31.68 29.408 31.704 ;
     RECT  28.717 33.024 29.408 33.048 ;
     RECT  29.293 34.224 29.408 35.448 ;
     RECT  28.609 36.576 29.408 36.6 ;
     RECT  29.077 38.976 29.408 39.288 ;
     RECT  29.149 40.656 29.408 40.68 ;
     RECT  28.019 42.624 29.408 43.032 ;
     RECT  29.269 44.352 29.408 45.336 ;
     RECT  29.185 47.712 29.408 56.472 ;
     RECT  29.269 57.6 29.408 63.816 ;
     RECT  29.329 67.584 29.408 68.664 ;
     RECT  29.005 70.08 29.408 71.304 ;
     RECT  28.753 72.384 29.408 74.088 ;
     RECT  29.408 0.288 29.512 75.612 ;
     RECT  29.512 0.288 29.704 75.342 ;
     RECT  29.704 47.424 29.729 55.848 ;
     RECT  29.704 21.024 29.843 21.048 ;
     RECT  29.704 72.528 29.891 74.328 ;
     RECT  29.704 59.232 29.981 59.832 ;
     RECT  29.704 0.288 29.987 4.632 ;
     RECT  29.704 33.024 30.053 35.448 ;
     RECT  29.704 38.88 30.083 40.68 ;
     RECT  29.704 36.48 30.089 36.6 ;
     RECT  29.704 66.768 30.089 68.28 ;
     RECT  29.981 59.808 30.124 59.832 ;
     RECT  29.704 41.76 30.161 43.32 ;
     RECT  29.891 72.528 30.197 73.608 ;
     RECT  30.053 33.072 30.227 35.448 ;
     RECT  30.161 42.192 30.227 43.32 ;
     RECT  30.227 34.512 30.268 34.824 ;
     RECT  29.704 60.816 30.269 63.816 ;
     RECT  29.704 25.632 30.305 25.656 ;
     RECT  29.704 18.816 30.323 19.992 ;
     RECT  29.729 47.616 30.323 55.848 ;
     RECT  29.704 46.128 30.412 46.152 ;
     RECT  30.323 18.816 30.449 19.512 ;
     RECT  30.323 47.616 30.449 50.28 ;
     RECT  30.083 38.88 30.521 39.336 ;
     RECT  30.227 43.296 30.557 43.32 ;
     RECT  29.704 26.736 30.629 27.192 ;
     RECT  29.704 30.864 30.689 30.888 ;
     RECT  30.197 72.528 30.697 73.512 ;
     RECT  30.089 67.296 30.701 68.28 ;
     RECT  30.323 51.408 30.709 55.848 ;
     RECT  29.704 13.104 30.745 13.128 ;
     RECT  30.668 32.064 30.755 32.088 ;
     RECT  29.704 9.696 30.757 10.536 ;
     RECT  29.704 11.712 30.757 11.736 ;
     RECT  29.704 14.928 30.757 16.584 ;
     RECT  29.704 5.712 30.769 5.736 ;
     RECT  29.704 6.816 30.769 7.416 ;
     RECT  29.704 22.176 30.769 22.2 ;
     RECT  30.689 30.672 30.769 30.888 ;
     RECT  30.449 47.616 30.769 49.848 ;
     RECT  29.704 71.232 30.769 71.256 ;
     RECT  30.697 72.384 30.769 73.512 ;
     RECT  29.987 0.288 30.773 1.848 ;
     RECT  30.769 30.672 30.773 31.08 ;
     RECT  29.987 3.552 30.805 4.632 ;
     RECT  30.757 14.688 30.809 16.584 ;
     RECT  30.521 38.88 30.809 39 ;
     RECT  30.805 3.552 30.812 4.728 ;
     RECT  30.769 5.712 30.812 7.416 ;
     RECT  29.704 8.448 30.853 8.568 ;
     RECT  30.757 9.696 30.853 11.736 ;
     RECT  30.812 3.552 30.881 7.416 ;
     RECT  30.773 30.768 30.881 31.08 ;
     RECT  30.809 16.56 30.901 16.584 ;
     RECT  30.881 3.648 30.908 7.416 ;
     RECT  30.853 8.448 30.908 11.736 ;
     RECT  30.769 22.176 30.917 22.728 ;
     RECT  29.704 28.656 30.985 28.68 ;
     RECT  30.908 3.648 30.995 11.736 ;
     RECT  30.901 16.56 31.025 17.256 ;
     RECT  30.985 28.656 31.025 28.968 ;
     RECT  30.769 71.232 31.025 73.512 ;
     RECT  30.701 68.256 31.091 68.28 ;
     RECT  31.025 71.232 31.091 72.984 ;
     RECT  30.227 33.072 31.097 33.096 ;
     RECT  30.709 51.408 31.097 56.52 ;
     RECT  31.091 71.232 31.132 71.496 ;
     RECT  31.132 71.232 31.169 71.256 ;
     RECT  29.704 57.6 31.201 57.624 ;
     RECT  31.201 57.6 31.241 58.392 ;
     RECT  30.995 8.448 31.283 11.736 ;
     RECT  29.704 44.352 31.309 45 ;
     RECT  31.025 16.56 31.313 17.208 ;
     RECT  31.091 72.528 31.313 72.984 ;
     RECT  31.241 58.032 31.331 58.392 ;
     RECT  31.313 17.184 31.357 17.208 ;
     RECT  30.809 14.688 31.417 15.48 ;
     RECT  30.917 22.176 31.525 22.632 ;
     RECT  30.995 3.648 31.529 7.416 ;
     RECT  30.769 47.376 31.561 49.848 ;
     RECT  31.309 44.016 31.601 45 ;
     RECT  31.283 8.736 31.637 11.736 ;
     RECT  31.097 51.408 31.637 55.848 ;
     RECT  31.025 28.896 31.66 28.968 ;
     RECT  30.449 19.488 31.669 19.512 ;
     RECT  30.227 42.192 31.673 42.216 ;
     RECT  30.773 0.288 31.741 1.752 ;
     RECT  31.633 20.688 31.741 20.712 ;
     RECT  31.525 21.744 31.741 22.632 ;
     RECT  31.637 10.272 31.817 11.736 ;
     RECT  31.817 10.512 31.849 11.736 ;
     RECT  31.529 4.608 31.853 7.416 ;
     RECT  31.637 52.224 31.853 55.848 ;
     RECT  30.881 31.056 31.885 31.08 ;
     RECT  30.809 38.976 31.885 39 ;
     RECT  31.853 52.224 31.925 55.704 ;
     RECT  31.417 14.592 31.955 15.48 ;
     RECT  31.925 53.376 31.961 55.704 ;
     RECT  31.741 20.688 31.993 22.632 ;
     RECT  29.704 24.336 31.993 24.36 ;
     RECT  31.741 0.24 32.003 1.752 ;
     RECT  30.269 60.816 32.033 61.8 ;
     RECT  31.993 20.688 32.051 24.36 ;
     RECT  32.051 22.704 32.06 24.36 ;
     RECT  30.629 27.168 32.065 27.192 ;
     RECT  32.06 22.704 32.093 24.936 ;
     RECT  31.849 10.512 32.101 12.552 ;
     RECT  31.669 19.392 32.101 19.512 ;
     RECT  32.093 22.704 32.101 25.032 ;
     RECT  31.885 31.056 32.101 31.272 ;
     RECT  31.925 52.224 32.141 52.248 ;
     RECT  32.029 70.416 32.177 70.44 ;
     RECT  32.101 31.056 32.185 31.944 ;
     RECT  31.561 47.088 32.209 49.848 ;
     RECT  32.101 22.704 32.213 25.128 ;
     RECT  31.66 28.944 32.245 28.968 ;
     RECT  32.209 47.088 32.245 50.664 ;
     RECT  32.003 0.24 32.249 0.648 ;
     RECT  32.003 1.728 32.281 1.752 ;
     RECT  32.101 10.512 32.285 13.464 ;
     RECT  31.601 44.016 32.291 44.904 ;
     RECT  31.331 58.032 32.293 58.152 ;
     RECT  31.853 4.608 32.339 6.84 ;
     RECT  32.065 27.168 32.341 27.96 ;
     RECT  32.245 28.944 32.341 29.592 ;
     RECT  32.185 31.056 32.341 31.272 ;
     RECT  32.285 12.528 32.357 13.464 ;
     RECT  32.051 20.688 32.381 21.672 ;
     RECT  32.281 1.728 32.387 2.28 ;
     RECT  32.213 22.704 32.393 23.208 ;
     RECT  31.909 41.568 32.393 41.592 ;
     RECT  32.101 18.768 32.396 19.512 ;
     RECT  32.396 18.384 32.425 19.512 ;
     RECT  32.381 20.544 32.425 21.672 ;
     RECT  31.628 56.88 32.461 57.048 ;
     RECT  32.293 58.032 32.461 58.056 ;
     RECT  31.309 74.016 32.461 74.04 ;
     RECT  32.425 18.384 32.465 21.672 ;
     RECT  32.465 18.384 32.483 18.84 ;
     RECT  32.341 26.784 32.483 27.96 ;
     RECT  32.033 60.816 32.483 61.608 ;
     RECT  30.268 34.8 32.485 34.824 ;
     RECT  32.339 4.608 32.497 5.688 ;
     RECT  32.461 56.88 32.501 58.056 ;
     RECT  32.497 3.84 32.509 5.688 ;
     RECT  32.393 22.752 32.524 23.208 ;
     RECT  32.341 28.944 32.531 31.272 ;
     RECT  32.485 34.8 32.531 35.352 ;
     RECT  32.249 0.24 32.533 0.456 ;
     RECT  31.955 14.832 32.533 15.48 ;
     RECT  32.437 17.088 32.533 17.112 ;
     RECT  32.245 46.176 32.573 50.664 ;
     RECT  31.313 72.816 32.609 72.984 ;
     RECT  32.483 60.96 32.627 61.608 ;
     RECT  32.533 0.144 32.645 0.456 ;
     RECT  32.645 0.192 32.668 0.456 ;
     RECT  32.339 6.816 32.675 6.84 ;
     RECT  30.269 63.168 32.717 63.816 ;
     RECT  32.533 14.832 32.75 17.208 ;
     RECT  32.483 27.12 32.821 27.96 ;
     RECT  32.531 28.944 32.821 30.84 ;
     RECT  32.573 46.176 32.821 49.272 ;
     RECT  32.75 14.832 32.833 17.16 ;
     RECT  32.285 10.512 32.849 10.872 ;
     RECT  32.627 60.96 32.861 61.224 ;
     RECT  31.961 53.616 32.897 55.704 ;
     RECT  32.573 50.304 32.965 50.664 ;
     RECT  32.833 14.832 32.969 17.112 ;
     RECT  32.609 72.816 32.969 72.936 ;
     RECT  30.089 36.48 33.037 36.504 ;
     RECT  32.828 37.824 33.037 37.848 ;
     RECT  31.093 59.808 33.041 59.832 ;
     RECT  32.821 27.12 33.059 30.84 ;
     RECT  32.509 3.84 33.107 5.256 ;
     RECT  31.637 8.736 33.109 9.144 ;
     RECT  33.059 27.12 33.113 30.696 ;
     RECT  31.957 32.976 33.145 33 ;
     RECT  32.849 10.272 33.185 10.872 ;
     RECT  33.037 36.48 33.185 37.848 ;
     RECT  32.291 44.448 33.217 44.904 ;
     RECT  32.821 46.128 33.217 49.272 ;
     RECT  32.969 72.912 33.221 72.936 ;
     RECT  32.461 74.016 33.253 74.376 ;
     RECT  33.109 7.968 33.289 9.144 ;
     RECT  33.185 10.272 33.289 10.296 ;
     RECT  33.113 27.12 33.299 29.112 ;
     RECT  33.001 69.744 33.325 69.768 ;
     RECT  33.217 44.448 33.329 49.272 ;
     RECT  33.289 7.968 33.347 10.296 ;
     RECT  32.501 56.88 33.397 57.576 ;
     RECT  32.357 13.44 33.433 13.464 ;
     RECT  33.433 13.056 33.445 13.464 ;
     RECT  32.483 18.768 33.445 18.84 ;
     RECT  33.217 66.768 33.473 66.792 ;
     RECT  33.445 12.528 33.5 13.464 ;
     RECT  33.397 56.592 33.509 57.576 ;
     RECT  32.861 61.056 33.509 61.224 ;
     RECT  32.387 1.728 33.538 1.752 ;
     RECT  33.185 37.2 33.545 37.848 ;
     RECT  33.325 68.256 33.545 68.28 ;
     RECT  33.253 74.016 33.577 74.664 ;
     RECT  33.325 69.744 33.581 70.632 ;
     RECT  33.5 11.952 33.587 13.464 ;
     RECT  33.587 12.528 33.637 13.464 ;
     RECT  32.465 21.12 33.637 21.672 ;
     RECT  32.524 22.752 33.637 22.776 ;
     RECT  32.213 24.336 33.637 25.128 ;
     RECT  33.545 37.584 33.637 37.848 ;
     RECT  31.885 38.976 33.637 39.912 ;
     RECT  33.637 37.584 33.653 39.912 ;
     RECT  33.538 1.728 33.661 1.8 ;
     RECT  32.969 15.456 33.683 17.112 ;
     RECT  33.637 21.12 33.683 22.776 ;
     RECT  33.653 37.584 33.683 39 ;
     RECT  33.145 32.976 33.689 33.672 ;
     RECT  33.577 73.536 33.721 74.664 ;
     RECT  33.445 18.72 33.757 18.84 ;
     RECT  32.465 19.968 33.757 19.992 ;
     RECT  33.637 23.808 33.761 25.128 ;
     RECT  33.661 1.728 33.865 1.752 ;
     RECT  32.531 35.328 33.865 35.352 ;
     RECT  33.865 34.944 33.901 35.352 ;
     RECT  33.509 56.592 33.901 56.616 ;
     RECT  33.757 6.288 33.925 6.312 ;
     RECT  33.299 27.12 33.937 29.016 ;
     RECT  33.757 18.72 33.973 19.992 ;
     RECT  32.668 0.192 34.021 0.36 ;
     RECT  34.021 0.192 34.045 0.408 ;
     RECT  33.329 44.88 34.045 49.272 ;
     RECT  32.965 50.304 34.045 50.952 ;
     RECT  34.045 0.144 34.069 0.408 ;
     RECT  33.925 6.288 34.069 6.888 ;
     RECT  33.685 52.272 34.076 52.296 ;
     RECT  32.897 53.616 34.076 55.128 ;
     RECT  33.683 21.12 34.081 22.056 ;
     RECT  34.069 0.144 34.157 0.504 ;
     RECT  33.761 24.336 34.189 25.128 ;
     RECT  33.107 4.416 34.213 5.256 ;
     RECT  34.069 6.288 34.213 6.984 ;
     RECT  33.347 7.968 34.213 9.96 ;
     RECT  34.045 44.88 34.225 50.952 ;
     RECT  33.973 18.24 34.297 19.992 ;
     RECT  33.689 33.312 34.357 33.672 ;
     RECT  33.901 34.752 34.357 35.352 ;
     RECT  34.213 4.416 34.369 9.96 ;
     RECT  34.001 11.472 34.369 11.496 ;
     RECT  33.865 1.632 34.403 1.752 ;
     RECT  33.581 69.744 34.405 69.768 ;
     RECT  34.405 68.976 34.549 69.768 ;
     RECT  33.901 56.256 34.621 56.616 ;
     RECT  34.157 0.192 34.705 0.408 ;
     RECT  34.081 21.072 34.729 22.056 ;
     RECT  33.937 26.736 34.729 29.016 ;
     RECT  34.297 3.408 34.765 3.432 ;
     RECT  33.637 12.528 34.801 14.232 ;
     RECT  34.403 1.728 34.808 1.752 ;
     RECT  34.765 3.12 34.808 3.432 ;
     RECT  34.369 4.416 34.808 11.496 ;
     RECT  34.801 12.528 34.808 14.664 ;
     RECT  33.683 15.792 34.808 17.112 ;
     RECT  34.297 18.24 34.808 20.088 ;
     RECT  34.729 21.072 34.808 22.824 ;
     RECT  34.189 24.336 34.808 25.224 ;
     RECT  34.729 26.352 34.808 29.016 ;
     RECT  33.113 30.24 34.808 30.696 ;
     RECT  33.433 31.92 34.808 31.944 ;
     RECT  34.357 33.312 34.808 35.352 ;
     RECT  33.683 38.016 34.808 39 ;
     RECT  32.749 41.664 34.808 41.688 ;
     RECT  34.009 43.872 34.808 43.896 ;
     RECT  34.225 44.88 34.808 51.144 ;
     RECT  34.076 52.272 34.808 55.128 ;
     RECT  34.621 56.256 34.808 57.432 ;
     RECT  33.509 61.104 34.808 61.224 ;
     RECT  33.505 62.832 34.808 62.856 ;
     RECT  33.181 64.08 34.808 64.104 ;
     RECT  34.549 68.112 34.808 69.768 ;
     RECT  33.685 70.8 34.808 70.824 ;
     RECT  34.405 72.192 34.808 72.216 ;
     RECT  33.721 73.536 34.808 74.712 ;
     RECT  34.808 1.728 34.912 75.612 ;
     RECT  34.912 1.728 35.104 75.342 ;
     RECT  35.104 24.048 35.165 28.536 ;
     RECT  35.104 61.104 35.201 61.224 ;
     RECT  35.104 22.032 35.267 23.064 ;
     RECT  34.705 0.24 35.269 0.408 ;
     RECT  35.104 1.728 35.273 4.44 ;
     RECT  35.104 6.144 35.273 11.448 ;
     RECT  35.267 22.032 35.28 22.776 ;
     RECT  35.104 30.72 35.315 31.32 ;
     RECT  35.315 30.72 35.345 30.84 ;
     RECT  35.273 1.728 35.363 3.432 ;
     RECT  35.104 15.696 35.381 20.568 ;
     RECT  35.104 12.528 35.404 14.664 ;
     RECT  35.104 62.688 35.417 62.856 ;
     RECT  35.104 56.256 35.453 58.104 ;
     RECT  35.273 6.192 35.459 11.448 ;
     RECT  35.453 56.4 35.525 58.104 ;
     RECT  35.104 64.08 35.525 64.104 ;
     RECT  35.273 4.416 35.555 4.44 ;
     RECT  35.345 30.816 35.561 30.84 ;
     RECT  35.363 1.728 35.597 3.336 ;
     RECT  35.165 24.048 35.597 26.712 ;
     RECT  35.269 0.24 35.605 0.552 ;
     RECT  35.459 6.24 35.633 11.448 ;
     RECT  35.404 14.64 35.651 14.664 ;
     RECT  35.104 41.616 35.669 42.6 ;
     RECT  35.525 57.408 35.669 58.104 ;
     RECT  35.633 8.208 35.713 11.448 ;
     RECT  35.597 1.728 35.773 2.904 ;
     RECT  35.381 15.696 35.795 19.512 ;
     RECT  35.201 61.2 35.813 61.224 ;
     RECT  35.417 62.832 35.813 62.856 ;
     RECT  35.795 15.696 35.836 18.696 ;
     RECT  35.381 20.544 35.849 20.568 ;
     RECT  35.773 1.68 35.857 2.904 ;
     RECT  35.836 15.696 35.857 18.264 ;
     RECT  35.104 71.952 35.885 74.952 ;
     RECT  35.605 0.24 35.917 0.6 ;
     RECT  35.104 68.4 35.921 70.296 ;
     RECT  35.633 6.24 35.939 6.408 ;
     RECT  35.713 8.208 35.957 11.4 ;
     RECT  35.857 15.696 35.957 16.584 ;
     RECT  35.957 16.56 35.987 16.584 ;
     RECT  35.917 0.144 36.029 0.6 ;
     RECT  35.404 12.528 36.073 13.272 ;
     RECT  35.921 68.4 36.101 68.424 ;
     RECT  35.921 69.552 36.101 70.296 ;
     RECT  35.104 38.448 36.137 39.384 ;
     RECT  35.104 59.664 36.169 59.688 ;
     RECT  35.857 17.616 36.173 18.264 ;
     RECT  35.28 22.032 36.173 22.056 ;
     RECT  35.597 24.336 36.173 26.712 ;
     RECT  35.104 37.056 36.179 37.08 ;
     RECT  36.173 24.336 36.209 25.656 ;
     RECT  35.165 28.032 36.229 28.536 ;
     RECT  35.104 46.752 36.241 51.144 ;
     RECT  35.104 52.32 36.241 52.344 ;
     RECT  36.209 24.336 36.275 25.08 ;
     RECT  35.104 35.424 36.275 36.072 ;
     RECT  36.073 12.528 36.281 13.128 ;
     RECT  35.885 71.952 36.281 73.368 ;
     RECT  36.029 0.336 36.317 0.6 ;
     RECT  36.137 38.976 36.349 39.384 ;
     RECT  36.229 26.784 36.371 28.632 ;
     RECT  35.104 65.52 36.385 65.544 ;
     RECT  36.169 58.416 36.457 59.88 ;
     RECT  36.101 69.552 36.461 69.576 ;
     RECT  36.173 17.904 36.515 18.264 ;
     RECT  36.457 58.416 36.533 60.84 ;
     RECT  36.317 0.336 36.569 0.552 ;
     RECT  36.275 35.424 36.569 35.448 ;
     RECT  36.385 65.52 36.601 66.168 ;
     RECT  36.517 62.448 36.604 62.472 ;
     RECT  36.601 65.52 36.604 66.696 ;
     RECT  36.371 27.744 36.605 27.768 ;
     RECT  36.533 58.416 36.641 58.68 ;
     RECT  36.493 4.608 36.668 4.632 ;
     RECT  35.939 6.384 36.673 6.408 ;
     RECT  35.957 10.272 36.677 11.4 ;
     RECT  35.525 56.4 36.709 56.424 ;
     RECT  35.669 57.408 36.709 57.432 ;
     RECT  36.349 38.976 36.713 39.768 ;
     RECT  36.668 4.512 36.755 4.632 ;
     RECT  36.515 18.24 36.755 18.264 ;
     RECT  36.713 39.168 36.805 39.768 ;
     RECT  36.805 39.168 36.817 40.536 ;
     RECT  35.669 41.616 36.817 41.64 ;
     RECT  36.205 45.552 36.853 45.576 ;
     RECT  36.241 46.752 36.853 52.344 ;
     RECT  36.817 39.168 36.857 41.64 ;
     RECT  36.857 39.168 36.892 41.352 ;
     RECT  36.673 6.384 36.925 6.984 ;
     RECT  35.104 53.616 36.925 54.6 ;
     RECT  35.885 74.448 36.925 74.952 ;
     RECT  35.957 8.208 36.961 8.808 ;
     RECT  36.677 10.8 36.961 11.4 ;
     RECT  35.857 1.728 36.995 2.904 ;
     RECT  36.925 6.24 36.997 6.984 ;
     RECT  36.961 8.16 36.997 8.808 ;
     RECT  36.421 36.624 37.001 36.648 ;
     RECT  36.569 0.336 37.033 0.456 ;
     RECT  36.853 45.552 37.033 52.344 ;
     RECT  36.275 24.336 37.043 24.504 ;
     RECT  36.892 39.168 37.043 39.768 ;
     RECT  36.997 6.24 37.045 8.808 ;
     RECT  37.045 6.24 37.069 9.144 ;
     RECT  36.925 53.616 37.069 54.936 ;
     RECT  36.709 56.4 37.069 57.432 ;
     RECT  37.069 5.808 37.1 9.144 ;
     RECT  36.533 59.856 37.109 60.84 ;
     RECT  37.033 45.024 37.139 52.344 ;
     RECT  37.139 45.024 37.145 46.056 ;
     RECT  36.925 74.448 37.145 75.24 ;
     RECT  37.1 5.808 37.153 9.24 ;
     RECT  36.709 22.608 37.177 22.632 ;
     RECT  37.033 0.192 37.187 0.456 ;
     RECT  36.925 31.392 37.213 31.416 ;
     RECT  37.109 60.816 37.217 60.84 ;
     RECT  37.213 30.768 37.361 31.416 ;
     RECT  36.281 72.48 37.361 73.368 ;
     RECT  37.141 71.088 37.397 71.112 ;
     RECT  37.361 72.72 37.433 73.368 ;
     RECT  37.043 39.36 37.469 39.768 ;
     RECT  36.961 10.8 37.493 11.832 ;
     RECT  36.995 2.832 37.501 2.904 ;
     RECT  37.177 21.648 37.501 22.632 ;
     RECT  36.604 66.144 37.501 66.696 ;
     RECT  37.501 66.144 37.541 67.272 ;
     RECT  37.139 47.328 37.573 52.344 ;
     RECT  37.069 53.616 37.573 57.432 ;
     RECT  36.517 63.792 37.577 63.816 ;
     RECT  37.177 25.728 37.609 25.752 ;
     RECT  37.501 2.832 37.621 3.432 ;
     RECT  37.469 39.36 37.667 39.48 ;
     RECT  37.609 25.728 37.669 26.232 ;
     RECT  37.621 3.408 37.676 3.432 ;
     RECT  37.501 21.12 37.685 22.632 ;
     RECT  36.892 41.28 37.685 41.352 ;
     RECT  37.621 38.16 37.708 38.184 ;
     RECT  37.669 25.728 37.781 26.808 ;
     RECT  37.541 67.248 37.825 67.272 ;
     RECT  37.753 14.88 37.861 14.904 ;
     RECT  37.781 25.104 37.865 26.808 ;
     RECT  37.573 47.328 37.865 57.432 ;
     RECT  37.825 67.248 37.865 67.416 ;
     RECT  37.676 3.408 37.897 4.104 ;
     RECT  37.285 5.184 37.897 5.4 ;
     RECT  37.493 10.8 37.897 12.648 ;
     RECT  37.861 14.88 37.897 15 ;
     RECT  37.865 47.328 37.901 56.472 ;
     RECT  37.897 10.8 37.981 13.416 ;
     RECT  37.153 6.432 38.077 9.24 ;
     RECT  37.501 23.904 38.077 23.928 ;
     RECT  37.433 72.816 38.077 73.368 ;
     RECT  37.145 74.448 38.077 74.952 ;
     RECT  37.901 54.384 38.081 56.472 ;
     RECT  37.681 68.64 38.113 68.664 ;
     RECT  36.995 1.728 38.149 1.8 ;
     RECT  37.865 25.728 38.149 26.808 ;
     RECT  38.077 72.816 38.149 74.952 ;
     RECT  38.077 6.432 38.185 9.672 ;
     RECT  37.981 10.8 38.185 13.128 ;
     RECT  37.177 19.968 38.189 19.992 ;
     RECT  38.149 72.816 38.221 75.144 ;
     RECT  37.537 43.872 38.225 43.896 ;
     RECT  37.187 0.192 38.243 0.312 ;
     RECT  38.149 1.728 38.243 2.328 ;
     RECT  37.145 46.032 38.257 46.056 ;
     RECT  38.221 72.816 38.293 75.192 ;
     RECT  36.641 58.416 38.329 58.44 ;
     RECT  37.685 21.12 38.333 21.144 ;
     RECT  38.149 25.728 38.401 27.096 ;
     RECT  38.257 46.032 38.405 46.104 ;
     RECT  37.897 3.408 38.437 5.4 ;
     RECT  38.185 6.432 38.437 13.128 ;
     RECT  38.329 58.08 38.437 58.44 ;
     RECT  38.329 18.384 38.473 18.408 ;
     RECT  37.357 34.656 38.473 34.68 ;
     RECT  38.405 46.08 38.473 46.104 ;
     RECT  37.901 47.328 38.473 53.016 ;
     RECT  37.897 14.832 38.477 15.288 ;
     RECT  38.437 3.408 38.483 13.128 ;
     RECT  37.541 66.144 38.545 66.168 ;
     RECT  38.113 68.64 38.549 68.952 ;
     RECT  38.243 0.288 38.581 0.312 ;
     RECT  38.477 15.264 38.581 15.288 ;
     RECT  37.717 16.272 38.581 16.296 ;
     RECT  38.473 18.384 38.581 18.792 ;
     RECT  38.293 72.816 38.581 75.24 ;
     RECT  38.401 25.728 38.617 27.432 ;
     RECT  38.581 72.432 38.621 75.24 ;
     RECT  38.483 9.072 38.627 13.128 ;
     RECT  37.361 31.392 38.653 31.416 ;
     RECT  37.501 64.896 38.653 64.92 ;
     RECT  38.549 68.64 38.657 68.664 ;
     RECT  38.329 70.8 38.657 70.824 ;
     RECT  38.581 0.288 38.675 0.408 ;
     RECT  37.501 61.008 38.684 61.032 ;
     RECT  38.581 17.616 38.693 18.792 ;
     RECT  37.685 22.608 38.725 22.632 ;
     RECT  38.684 61.008 38.725 61.896 ;
     RECT  38.627 9.648 38.729 13.128 ;
     RECT  38.437 58.08 38.729 59.064 ;
     RECT  38.243 1.728 38.761 1.752 ;
     RECT  38.621 72.432 38.765 75.192 ;
     RECT  38.729 9.648 38.771 11.448 ;
     RECT  38.729 12.48 38.771 13.128 ;
     RECT  38.693 17.616 38.771 18.408 ;
     RECT  38.725 60.72 38.771 61.896 ;
     RECT  38.473 34.32 38.833 34.68 ;
     RECT  37.685 41.28 38.833 41.304 ;
     RECT  38.581 15.264 38.837 16.296 ;
     RECT  38.725 21.936 38.873 22.632 ;
     RECT  38.771 60.72 38.873 61.368 ;
     RECT  38.483 3.408 38.88 7.992 ;
     RECT  38.771 9.888 38.909 11.448 ;
     RECT  38.725 19.92 38.909 19.944 ;
     RECT  38.761 1.68 38.915 1.752 ;
     RECT  38.077 23.616 38.941 23.928 ;
     RECT  38.653 31.344 38.941 31.416 ;
     RECT  38.729 58.08 38.941 58.728 ;
     RECT  37.865 67.392 38.945 67.416 ;
     RECT  38.941 23.616 39.013 24.552 ;
     RECT  38.941 30.768 39.013 31.416 ;
     RECT  37.145 45.024 39.017 45.048 ;
     RECT  38.88 6.288 39.025 7.992 ;
     RECT  38.837 16.032 39.049 16.296 ;
     RECT  38.941 57.696 39.053 58.728 ;
     RECT  38.771 12.48 39.089 12.504 ;
     RECT  39.025 6.288 39.107 7.848 ;
     RECT  38.833 41.28 39.155 42.216 ;
     RECT  38.833 34.32 39.157 34.728 ;
     RECT  38.365 35.952 39.157 35.976 ;
     RECT  38.081 54.384 39.157 55.704 ;
     RECT  39.107 6.624 39.197 7.848 ;
     RECT  39.157 34.32 39.203 35.976 ;
     RECT  38.88 3.408 39.205 5.208 ;
     RECT  38.765 72.432 39.233 74.952 ;
     RECT  39.013 30.768 39.308 31.896 ;
     RECT  37.357 32.976 39.308 33 ;
     RECT  39.308 30.768 39.337 33 ;
     RECT  39.155 41.28 39.337 41.64 ;
     RECT  38.473 46.08 39.409 53.016 ;
     RECT  39.157 54.384 39.409 56.664 ;
     RECT  39.013 23.568 39.481 24.6 ;
     RECT  38.617 25.728 39.481 28.152 ;
     RECT  38.675 0.384 39.493 0.408 ;
     RECT  39.205 3.36 39.541 5.208 ;
     RECT  39.409 46.08 39.589 56.664 ;
     RECT  39.053 57.696 39.589 58.44 ;
     RECT  37.667 39.456 39.661 39.48 ;
     RECT  38.149 62.976 39.661 63 ;
     RECT  38.653 64.032 39.661 64.92 ;
     RECT  38.915 1.728 39.733 1.752 ;
     RECT  39.337 41.232 39.733 41.64 ;
     RECT  39.733 1.728 39.737 1.848 ;
     RECT  39.737 1.776 39.769 1.848 ;
     RECT  39.541 2.88 39.769 5.208 ;
     RECT  39.589 46.08 39.769 58.44 ;
     RECT  39.337 13.68 39.781 13.704 ;
     RECT  39.481 23.568 39.805 28.152 ;
     RECT  39.661 38.736 39.829 39.48 ;
     RECT  39.049 16.032 39.877 16.536 ;
     RECT  38.771 18.24 39.877 18.408 ;
     RECT  39.877 16.032 39.932 16.824 ;
     RECT  39.781 13.68 39.949 13.752 ;
     RECT  39.932 15.072 39.949 16.824 ;
     RECT  39.493 0.384 39.973 0.552 ;
     RECT  39.203 34.656 39.985 35.976 ;
     RECT  38.653 37.008 39.985 37.032 ;
     RECT  38.873 21.936 40.049 21.96 ;
     RECT  39.973 0.288 40.069 0.552 ;
     RECT  39.589 68.976 40.093 69 ;
     RECT  39.805 23.568 40.129 28.872 ;
     RECT  39.769 1.776 40.208 5.208 ;
     RECT  39.197 6.624 40.208 6.84 ;
     RECT  39.197 7.824 40.208 7.848 ;
     RECT  38.909 10.848 40.208 11.448 ;
     RECT  39.949 13.68 40.208 16.824 ;
     RECT  39.877 18.24 40.208 18.792 ;
     RECT  40.049 21.936 40.208 22.152 ;
     RECT  40.129 23.568 40.208 29.064 ;
     RECT  39.337 30.768 40.208 33.336 ;
     RECT  39.985 34.656 40.208 37.032 ;
     RECT  39.829 38.16 40.208 39.48 ;
     RECT  39.733 41.04 40.208 41.64 ;
     RECT  39.301 43.488 40.208 43.512 ;
     RECT  39.769 45.696 40.208 58.44 ;
     RECT  39.877 60 40.208 60.024 ;
     RECT  38.873 61.344 40.208 61.368 ;
     RECT  39.661 62.976 40.208 64.92 ;
     RECT  38.545 65.904 40.208 66.168 ;
     RECT  40.093 68.208 40.208 69 ;
     RECT  39.233 72.432 40.208 73.56 ;
     RECT  39.233 74.64 40.208 74.952 ;
     RECT  40.208 1.776 40.312 75.612 ;
     RECT  40.069 0.288 40.355 0.648 ;
     RECT  40.312 1.776 40.504 75.342 ;
     RECT  40.504 30.816 40.565 31.512 ;
     RECT  40.504 45.696 40.565 55.8 ;
     RECT  40.504 72.432 40.637 74.952 ;
     RECT  40.504 36.912 40.643 37.656 ;
     RECT  40.504 15.984 40.673 17.688 ;
     RECT  40.504 21.12 40.673 23.976 ;
     RECT  40.504 57.936 40.709 58.728 ;
     RECT  40.637 72.432 40.709 74.904 ;
     RECT  40.643 36.912 40.717 37.08 ;
     RECT  40.504 25.728 40.739 29.208 ;
     RECT  40.504 34.8 40.739 35.304 ;
     RECT  40.717 36.912 40.739 37.032 ;
     RECT  40.565 45.696 40.745 55.704 ;
     RECT  40.504 62.64 40.745 63.096 ;
     RECT  40.739 35.184 40.781 35.304 ;
     RECT  40.745 45.696 40.853 54.36 ;
     RECT  40.504 1.776 40.957 5.64 ;
     RECT  40.673 21.12 40.969 22.536 ;
     RECT  40.709 58.032 40.969 58.728 ;
     RECT  40.565 31.488 40.979 31.512 ;
     RECT  40.355 0.288 40.981 0.6 ;
     RECT  40.853 45.696 40.997 53.88 ;
     RECT  40.504 33.504 41.02 33.528 ;
     RECT  40.504 10.848 41.033 11.496 ;
     RECT  40.504 13.68 41.075 14.472 ;
     RECT  40.997 45.696 41.075 52.584 ;
     RECT  40.739 25.728 41.105 26.808 ;
     RECT  40.957 1.728 41.171 5.64 ;
     RECT  40.504 68.208 41.219 68.664 ;
     RECT  41.075 46.08 41.249 52.584 ;
     RECT  41.171 1.728 41.257 1.848 ;
     RECT  40.673 16.8 41.363 17.688 ;
     RECT  40.739 27.888 41.459 29.208 ;
     RECT  41.171 2.832 41.465 5.64 ;
     RECT  40.981 0.192 41.497 0.6 ;
     RECT  41.075 14.256 41.497 14.472 ;
     RECT  40.504 39.84 41.501 39.864 ;
     RECT  41.257 1.728 41.555 1.8 ;
     RECT  40.504 18.768 41.569 18.792 ;
     RECT  40.969 58.032 41.603 58.44 ;
     RECT  40.504 64.368 41.605 65.016 ;
     RECT  40.504 70.656 41.605 70.68 ;
     RECT  41.497 0.144 41.609 0.6 ;
     RECT  41.465 2.88 41.651 5.64 ;
     RECT  40.504 41.232 41.651 42.168 ;
     RECT  40.504 66.72 41.651 67.128 ;
     RECT  41.033 10.848 41.66 11.352 ;
     RECT  41.651 2.88 41.699 4.872 ;
     RECT  40.504 6.672 41.701 8.28 ;
     RECT  41.569 18.768 41.701 19.464 ;
     RECT  41.701 6.672 41.747 8.568 ;
     RECT  41.66 10.224 41.747 11.352 ;
     RECT  40.673 23.568 41.749 23.976 ;
     RECT  41.249 46.08 41.753 52.536 ;
     RECT  41.749 23.568 41.785 24.696 ;
     RECT  41.699 2.88 41.795 4.536 ;
     RECT  41.609 0.192 41.825 0.6 ;
     RECT  41.747 8.544 41.825 8.568 ;
     RECT  40.504 56.832 41.929 56.856 ;
     RECT  41.603 58.032 41.929 58.104 ;
     RECT  40.709 72.816 41.965 74.856 ;
     RECT  41.825 0.24 42.037 0.6 ;
     RECT  40.969 21.936 42.073 22.536 ;
     RECT  41.785 23.568 42.073 25.08 ;
     RECT  41.747 6.672 42.085 6.984 ;
     RECT  41.497 14.256 42.109 14.856 ;
     RECT  41.605 64.368 42.109 65.4 ;
     RECT  41.651 66.72 42.109 66.744 ;
     RECT  42.109 14.256 42.133 15.384 ;
     RECT  41.105 26.688 42.133 26.808 ;
     RECT  41.459 27.888 42.133 29.064 ;
     RECT  41.651 41.232 42.145 41.592 ;
     RECT  40.504 60.96 42.145 61.368 ;
     RECT  40.745 62.64 42.145 63 ;
     RECT  42.037 0.24 42.179 0.648 ;
     RECT  41.785 12.384 42.179 12.408 ;
     RECT  41.893 42.672 42.181 42.696 ;
     RECT  42.145 60.96 42.181 63 ;
     RECT  42.109 64.368 42.181 66.744 ;
     RECT  41.929 56.832 42.185 58.104 ;
     RECT  40.781 35.184 42.217 35.208 ;
     RECT  40.745 55.44 42.217 55.704 ;
     RECT  42.133 13.44 42.22 15.384 ;
     RECT  42.181 42.672 42.227 43.272 ;
     RECT  42.181 60.96 42.227 66.744 ;
     RECT  41.747 10.272 42.253 11.352 ;
     RECT  42.185 56.832 42.257 58.056 ;
     RECT  42.22 14.256 42.293 15.384 ;
     RECT  42.257 56.976 42.329 58.056 ;
     RECT  42.179 0.24 42.365 0.264 ;
     RECT  42.145 41.04 42.401 41.592 ;
     RECT  42.227 43.248 42.401 43.272 ;
     RECT  41.753 50.592 42.419 52.536 ;
     RECT  42.227 60.96 42.419 65.544 ;
     RECT  40.739 37.008 42.433 37.032 ;
     RECT  42.353 20.544 42.437 20.568 ;
     RECT  42.133 26.688 42.473 29.064 ;
     RECT  42.227 66.72 42.473 66.744 ;
     RECT  42.293 14.256 42.509 14.76 ;
     RECT  42.181 38.928 42.545 38.952 ;
     RECT  42.361 30.672 42.581 30.696 ;
     RECT  41.363 16.8 42.613 16.824 ;
     RECT  41.701 18.192 42.613 19.464 ;
     RECT  42.419 60.96 42.649 62.184 ;
     RECT  42.073 21.936 42.668 25.08 ;
     RECT  41.965 72.816 42.685 75.24 ;
     RECT  41.753 46.656 42.721 49.56 ;
     RECT  42.419 50.592 42.721 52.44 ;
     RECT  42.419 63.552 42.725 63.864 ;
     RECT  42.419 64.992 42.725 65.544 ;
     RECT  42.685 72.672 42.725 75.24 ;
     RECT  42.613 16.8 42.755 19.464 ;
     RECT  42.668 21.936 42.755 25.128 ;
     RECT  42.085 6.144 42.757 6.984 ;
     RECT  42.473 27.312 42.785 29.064 ;
     RECT  42.757 6.144 42.793 7.416 ;
     RECT  42.217 34.8 42.797 35.208 ;
     RECT  42.755 16.8 42.803 18.072 ;
     RECT  41.795 2.88 42.829 4.008 ;
     RECT  41.713 44.976 42.829 45 ;
     RECT  42.755 21.936 42.851 25.08 ;
     RECT  42.803 16.8 42.865 16.824 ;
     RECT  42.785 27.312 42.869 29.688 ;
     RECT  42.755 19.392 42.893 19.464 ;
     RECT  42.851 24.336 42.905 25.08 ;
     RECT  42.757 26.064 42.947 26.088 ;
     RECT  42.893 19.392 42.977 19.992 ;
     RECT  42.829 2.88 42.995 4.872 ;
     RECT  42.829 44.448 42.995 45 ;
     RECT  42.793 6.144 43.004 7.512 ;
     RECT  41.555 1.728 43.009 1.752 ;
     RECT  42.995 2.88 43.009 4.296 ;
     RECT  42.865 32.784 43.013 32.808 ;
     RECT  42.721 46.656 43.013 52.44 ;
     RECT  42.803 18.048 43.043 18.072 ;
     RECT  42.977 19.392 43.043 19.416 ;
     RECT  42.869 27.312 43.043 28.824 ;
     RECT  42.995 44.976 43.049 45 ;
     RECT  43.009 1.728 43.085 4.296 ;
     RECT  42.253 10.272 43.121 12.12 ;
     RECT  41.821 67.824 43.157 67.848 ;
     RECT  43.153 9.072 43.189 9.096 ;
     RECT  42.725 72.672 43.193 75.096 ;
     RECT  43.004 5.28 43.225 7.512 ;
     RECT  43.189 8.544 43.225 9.096 ;
     RECT  42.433 37.008 43.229 37.608 ;
     RECT  43.225 5.28 43.265 9.096 ;
     RECT  41.605 70.512 43.297 70.68 ;
     RECT  42.509 14.736 43.301 14.76 ;
     RECT  42.649 60.672 43.337 62.184 ;
     RECT  43.193 72.816 43.337 75.096 ;
     RECT  40.997 53.568 43.34 53.88 ;
     RECT  43.229 37.008 43.373 37.032 ;
     RECT  43.153 45.024 43.379 45.048 ;
     RECT  42.217 55.296 43.381 55.704 ;
     RECT  43.34 53.568 43.427 53.976 ;
     RECT  43.381 55.152 43.427 55.704 ;
     RECT  42.865 39.744 43.441 39.768 ;
     RECT  42.329 57.072 43.441 58.056 ;
     RECT  42.725 63.648 43.441 63.864 ;
     RECT  42.725 64.992 43.441 65.448 ;
     RECT  42.905 25.056 43.481 25.08 ;
     RECT  43.441 39.744 43.481 39.912 ;
     RECT  43.427 55.152 43.513 55.32 ;
     RECT  43.265 6.144 43.541 9.096 ;
     RECT  43.013 46.656 43.553 47.736 ;
     RECT  43.513 55.056 43.553 55.32 ;
     RECT  43.441 57.072 43.573 58.152 ;
     RECT  43.043 28.464 43.589 28.824 ;
     RECT  43.013 48.768 43.589 52.44 ;
     RECT  43.441 63.648 43.619 65.448 ;
     RECT  42.401 41.04 43.667 41.4 ;
     RECT  43.397 0.528 43.669 0.552 ;
     RECT  43.427 53.568 43.697 53.88 ;
     RECT  42.797 34.896 43.729 35.208 ;
     RECT  43.337 72.864 43.733 75.096 ;
     RECT  43.085 1.728 43.741 3.816 ;
     RECT  43.553 55.056 43.763 55.272 ;
     RECT  43.669 0.288 43.765 0.552 ;
     RECT  42.851 21.936 43.813 23.352 ;
     RECT  42.865 16.368 43.861 16.824 ;
     RECT  43.813 21.648 43.861 23.352 ;
     RECT  43.619 65.28 43.868 65.448 ;
     RECT  43.741 2.832 43.885 3.816 ;
     RECT  43.861 21.648 43.945 23.4 ;
     RECT  43.667 41.04 43.949 41.064 ;
     RECT  43.868 65.28 43.955 65.544 ;
     RECT  43.765 13.632 43.985 13.656 ;
     RECT  43.945 21.648 44.029 23.976 ;
     RECT  43.297 70.512 44.06 71.256 ;
     RECT  43.553 46.752 44.089 47.736 ;
     RECT  43.589 48.768 44.089 52.296 ;
     RECT  43.861 16.368 44.093 17.112 ;
     RECT  44.06 70.512 44.147 71.688 ;
     RECT  43.733 73.056 44.161 75.096 ;
     RECT  43.589 28.512 44.165 28.824 ;
     RECT  44.147 70.512 44.193 71.256 ;
     RECT  43.337 60.672 44.195 62.04 ;
     RECT  43.043 27.312 44.197 27.336 ;
     RECT  43.729 34.896 44.197 35.352 ;
     RECT  43.593 43.824 44.197 43.896 ;
     RECT  44.165 28.512 44.243 28.536 ;
     RECT  43.573 57.072 44.269 59.112 ;
     RECT  43.909 66.72 44.273 66.744 ;
     RECT  43.885 2.88 44.305 3.816 ;
     RECT  44.293 14.784 44.305 14.808 ;
     RECT  44.305 2.88 44.341 4.056 ;
     RECT  44.305 14.784 44.341 14.856 ;
     RECT  44.093 16.368 44.345 16.824 ;
     RECT  44.195 60.96 44.377 62.04 ;
     RECT  44.341 2.88 44.413 4.584 ;
     RECT  43.541 6.144 44.413 9.144 ;
     RECT  44.089 46.752 44.417 52.296 ;
     RECT  43.765 0.192 44.437 0.552 ;
     RECT  44.197 34.896 44.437 35.88 ;
     RECT  44.089 36.912 44.437 36.936 ;
     RECT  43.765 38.112 44.437 38.136 ;
     RECT  44.017 69.504 44.437 69.528 ;
     RECT  44.193 70.512 44.437 70.68 ;
     RECT  44.413 2.88 44.449 9.144 ;
     RECT  43.121 10.272 44.449 12.024 ;
     RECT  44.197 43.824 44.449 44.472 ;
     RECT  44.437 34.896 44.483 38.136 ;
     RECT  44.449 2.88 44.521 12.024 ;
     RECT  44.483 36.384 44.524 36.408 ;
     RECT  43.117 30.048 44.525 30.072 ;
     RECT  44.437 68.784 44.561 70.68 ;
     RECT  44.437 0.192 44.597 0.6 ;
     RECT  44.521 2.88 44.627 12.552 ;
     RECT  44.029 21.648 44.629 23.688 ;
     RECT  44.483 34.896 44.629 35.352 ;
     RECT  44.417 48.96 44.633 52.296 ;
     RECT  44.269 57.072 44.809 59.64 ;
     RECT  43.741 1.728 44.881 1.8 ;
     RECT  44.809 57.024 44.924 59.64 ;
     RECT  44.161 73.056 44.953 75.24 ;
     RECT  43.717 18.816 45.025 18.84 ;
     RECT  44.629 21.072 45.025 23.688 ;
     RECT  44.377 60.96 45.061 62.184 ;
     RECT  43.619 63.648 45.061 64.296 ;
     RECT  44.341 14.784 45.097 14.952 ;
     RECT  45.025 21.072 45.097 24.552 ;
     RECT  45.025 18.288 45.133 18.84 ;
     RECT  45.097 14.352 45.205 15.144 ;
     RECT  44.345 16.8 45.205 16.824 ;
     RECT  45.133 17.952 45.205 18.84 ;
     RECT  43.697 53.856 45.241 53.88 ;
     RECT  44.597 0.192 45.313 0.552 ;
     RECT  44.953 72.816 45.313 75.24 ;
     RECT  45.205 16.8 45.349 18.84 ;
     RECT  43.945 31.872 45.349 31.896 ;
     RECT  43.481 39.888 45.385 39.912 ;
     RECT  45.205 14.352 45.404 15.576 ;
     RECT  45.313 0.144 45.425 0.552 ;
     RECT  45.404 14.16 45.445 15.576 ;
     RECT  44.924 57.024 45.493 59.88 ;
     RECT  45.061 60.96 45.493 64.296 ;
     RECT  44.483 37.632 45.529 38.136 ;
     RECT  45.349 16.8 45.565 19.32 ;
     RECT  44.629 34.512 45.601 35.352 ;
     RECT  43.763 55.056 45.601 55.176 ;
     RECT  44.881 1.728 45.608 1.848 ;
     RECT  44.627 2.976 45.608 12.552 ;
     RECT  45.445 13.92 45.608 15.576 ;
     RECT  45.565 16.8 45.608 19.8 ;
     RECT  45.097 21.072 45.608 25.08 ;
     RECT  44.197 26.736 45.608 27.336 ;
     RECT  45.349 31.776 45.608 31.896 ;
     RECT  45.601 34.512 45.608 35.736 ;
     RECT  45.529 37.344 45.608 38.136 ;
     RECT  45.385 39.504 45.608 39.912 ;
     RECT  44.449 43.296 45.608 44.472 ;
     RECT  44.417 46.752 45.608 47.88 ;
     RECT  44.633 48.96 45.608 52.2 ;
     RECT  45.241 53.568 45.608 53.88 ;
     RECT  45.601 54.864 45.608 55.176 ;
     RECT  45.493 57.024 45.608 64.296 ;
     RECT  43.955 65.28 45.608 65.304 ;
     RECT  44.953 68.352 45.608 68.376 ;
     RECT  44.561 69.456 45.608 70.68 ;
     RECT  45.169 71.664 45.608 71.688 ;
     RECT  45.313 72.72 45.608 75.24 ;
     RECT  45.608 1.728 45.712 75.612 ;
     RECT  45.712 1.728 45.857 75.342 ;
     RECT  45.857 1.776 45.904 75.342 ;
     RECT  45.904 24.528 46.019 28.104 ;
     RECT  45.904 46.08 46.019 55.416 ;
     RECT  45.904 8.256 46.045 9.144 ;
     RECT  45.904 33.072 46.045 33.624 ;
     RECT  46.019 26.256 46.067 28.104 ;
     RECT  45.904 34.608 46.08 39.912 ;
     RECT  45.904 65.52 46.108 66.744 ;
     RECT  45.904 1.776 46.145 2.904 ;
     RECT  45.904 10.848 46.163 12.36 ;
     RECT  46.08 37.584 46.181 39.912 ;
     RECT  45.904 30.816 46.211 31.896 ;
     RECT  45.904 13.632 46.217 19.992 ;
     RECT  45.904 72.816 46.253 73.272 ;
     RECT  46.108 65.52 46.307 65.928 ;
     RECT  45.904 63.072 46.325 64.104 ;
     RECT  45.425 0.288 46.393 0.552 ;
     RECT  45.904 5.136 46.397 5.256 ;
     RECT  46.217 14.256 46.397 19.992 ;
     RECT  46.163 10.848 46.433 12.024 ;
     RECT  46.045 8.256 46.451 8.376 ;
     RECT  46.253 72.912 46.469 73.272 ;
     RECT  45.904 6.72 46.492 7.224 ;
     RECT  45.904 43.296 46.499 43.896 ;
     RECT  46.211 30.816 46.541 31.8 ;
     RECT  46.451 8.352 46.547 8.376 ;
     RECT  46.492 6.72 46.574 6.888 ;
     RECT  46.397 14.736 46.577 19.992 ;
     RECT  46.577 14.736 46.595 18.696 ;
     RECT  46.595 14.736 46.685 18.216 ;
     RECT  46.433 10.848 46.739 11.448 ;
     RECT  46.08 34.608 46.739 35.736 ;
     RECT  45.904 70.272 46.749 71.688 ;
     RECT  46.393 0.192 46.753 0.552 ;
     RECT  46.045 33.6 46.78 33.624 ;
     RECT  46.019 47.088 46.793 55.416 ;
     RECT  45.904 58.752 46.793 59.208 ;
     RECT  46.067 26.256 46.829 27.24 ;
     RECT  46.793 53.76 46.829 55.416 ;
     RECT  46.181 38.592 46.865 39.912 ;
     RECT  46.577 19.776 46.883 19.992 ;
     RECT  46.685 15.984 46.901 18.216 ;
     RECT  46.541 30.864 46.937 31.8 ;
     RECT  46.181 37.584 46.937 37.608 ;
     RECT  46.019 46.08 46.937 46.104 ;
     RECT  46.469 73.104 47.005 73.272 ;
     RECT  45.904 74.4 47.005 75.24 ;
     RECT  46.019 24.528 47.009 25.08 ;
     RECT  45.904 60.672 47.009 62.04 ;
     RECT  45.904 68.448 47.009 68.952 ;
     RECT  46.865 39.888 47.113 39.912 ;
     RECT  45.904 41.04 47.113 41.064 ;
     RECT  47.005 29.088 47.18 29.112 ;
     RECT  47.113 39.888 47.221 41.064 ;
     RECT  46.901 15.984 47.261 16.536 ;
     RECT  45.904 57.024 47.261 57.672 ;
     RECT  47.005 73.104 47.261 75.24 ;
     RECT  47.18 28.32 47.267 29.112 ;
     RECT  46.325 63.072 47.293 63.096 ;
     RECT  46.793 47.088 47.297 52.68 ;
     RECT  47.185 23.808 47.315 23.928 ;
     RECT  47.009 61.584 47.327 62.04 ;
     RECT  47.293 63.024 47.327 63.096 ;
     RECT  46.307 65.904 47.329 65.928 ;
     RECT  47.261 16.512 47.333 16.536 ;
     RECT  47.297 47.088 47.333 48.696 ;
     RECT  46.145 2.304 47.365 2.904 ;
     RECT  47.327 61.584 47.365 63.096 ;
     RECT  47.221 39.888 47.369 41.544 ;
     RECT  47.365 1.776 47.393 2.904 ;
     RECT  46.901 17.664 47.405 18.216 ;
     RECT  47.365 61.584 47.411 63.288 ;
     RECT  46.739 35.712 47.437 35.736 ;
     RECT  47.077 37.008 47.437 37.032 ;
     RECT  47.261 73.104 47.437 75.192 ;
     RECT  47.393 1.728 47.477 2.904 ;
     RECT  47.437 35.712 47.477 37.032 ;
     RECT  47.477 1.776 47.509 2.904 ;
     RECT  46.499 43.296 47.509 43.32 ;
     RECT  47.369 39.888 47.549 40.44 ;
     RECT  47.437 8.544 47.555 8.568 ;
     RECT  46.793 59.184 47.557 59.208 ;
     RECT  46.829 53.76 47.603 55.176 ;
     RECT  47.509 1.776 47.651 3.336 ;
     RECT  46.397 5.232 47.653 5.256 ;
     RECT  47.365 14.256 47.653 14.28 ;
     RECT  46.937 30.864 47.689 31.56 ;
     RECT  47.009 25.056 47.693 25.08 ;
     RECT  47.653 4.56 47.725 5.256 ;
     RECT  46.574 6.72 47.725 6.84 ;
     RECT  47.405 18.144 47.725 18.216 ;
     RECT  47.725 4.56 47.747 6.84 ;
     RECT  47.267 29.088 47.797 29.112 ;
     RECT  47.261 57.072 47.797 57.672 ;
     RECT  47.653 13.584 47.843 14.28 ;
     RECT  47.509 42.624 47.845 43.32 ;
     RECT  47.747 5.088 47.869 6.84 ;
     RECT  47.797 29.088 47.869 29.784 ;
     RECT  47.689 30.816 47.869 31.56 ;
     RECT  47.869 5.088 47.873 7.56 ;
     RECT  45.904 44.976 47.891 45 ;
     RECT  47.651 2.352 47.893 3.336 ;
     RECT  45.904 22.176 47.905 22.536 ;
     RECT  47.315 23.808 47.905 23.832 ;
     RECT  47.333 47.088 47.939 48.408 ;
     RECT  47.297 49.872 47.941 52.68 ;
     RECT  47.603 53.76 47.941 54.888 ;
     RECT  47.893 2.352 47.987 4.056 ;
     RECT  47.329 65.904 47.987 66.792 ;
     RECT  47.873 6.72 48.017 7.56 ;
     RECT  47.893 12.528 48.017 12.552 ;
     RECT  47.797 57.072 48.053 57.96 ;
     RECT  47.987 2.832 48.083 4.056 ;
     RECT  46.753 0.192 48.085 0.6 ;
     RECT  47.905 22.176 48.125 23.832 ;
     RECT  47.009 68.448 48.161 68.472 ;
     RECT  46.865 38.592 48.193 38.616 ;
     RECT  47.477 35.712 48.197 36.456 ;
     RECT  47.987 66.48 48.229 66.792 ;
     RECT  47.845 42.624 48.233 43.368 ;
     RECT  48.053 57.072 48.265 57.144 ;
     RECT  47.549 39.888 48.269 40.104 ;
     RECT  48.233 43.344 48.269 43.368 ;
     RECT  48.013 16.56 48.275 16.584 ;
     RECT  47.941 49.872 48.332 54.888 ;
     RECT  47.939 47.088 48.337 47.88 ;
     RECT  47.411 61.728 48.337 63.288 ;
     RECT  47.329 64.368 48.337 64.392 ;
     RECT  48.037 15.408 48.341 15.432 ;
     RECT  47.869 29.088 48.377 31.56 ;
     RECT  46.739 34.608 48.38 34.632 ;
     RECT  48.197 35.712 48.38 35.928 ;
     RECT  48.193 38.592 48.413 38.808 ;
     RECT  46.829 26.496 48.421 27.24 ;
     RECT  46.749 70.272 48.421 71.256 ;
     RECT  47.725 18.144 48.445 18.792 ;
     RECT  46.883 19.776 48.445 19.8 ;
     RECT  48.421 69.456 48.445 71.256 ;
     RECT  48.421 26.496 48.467 27.912 ;
     RECT  48.377 29.088 48.467 30.264 ;
     RECT  48.445 68.928 48.467 71.256 ;
     RECT  48.467 71.232 48.485 71.256 ;
     RECT  48.085 0.192 48.521 0.648 ;
     RECT  48.437 9.696 48.521 9.72 ;
     RECT  48.467 27.84 48.563 27.912 ;
     RECT  48.377 31.536 48.589 31.56 ;
     RECT  48.337 61.728 48.593 64.392 ;
     RECT  46.739 10.848 48.661 11.4 ;
     RECT  47.977 25.152 48.661 25.224 ;
     RECT  48.467 30.24 48.665 30.264 ;
     RECT  48.337 46.176 48.665 47.88 ;
     RECT  48.413 38.592 48.701 38.76 ;
     RECT  48.332 49.392 48.701 54.888 ;
     RECT  48.661 25.152 48.707 25.368 ;
     RECT  48.701 49.392 48.769 54.6 ;
     RECT  48.083 2.832 48.773 3.432 ;
     RECT  48.593 61.728 48.773 63.672 ;
     RECT  48.467 68.928 48.773 69.576 ;
     RECT  48.625 21.504 48.809 21.528 ;
     RECT  48.661 10.848 48.841 11.448 ;
     RECT  48.229 66.48 48.881 67.368 ;
     RECT  47.437 72.816 48.913 75.192 ;
     RECT  48.773 61.728 48.917 61.752 ;
     RECT  48.853 1.728 48.949 1.752 ;
     RECT  48.265 56.256 48.953 57.144 ;
     RECT  48.707 25.248 48.985 25.368 ;
     RECT  48.467 26.496 48.985 26.808 ;
     RECT  48.38 34.608 48.995 35.928 ;
     RECT  48.445 18.144 48.997 19.8 ;
     RECT  48.985 25.248 49.025 26.808 ;
     RECT  48.665 46.752 49.025 47.88 ;
     RECT  48.913 72.144 49.025 75.192 ;
     RECT  48.949 1.728 49.033 1.848 ;
     RECT  48.997 18.144 49.043 20.04 ;
     RECT  48.017 7.008 49.045 7.56 ;
     RECT  47.557 59.184 49.057 59.304 ;
     RECT  48.697 60.384 49.057 60.408 ;
     RECT  48.995 34.608 49.061 34.632 ;
     RECT  47.843 13.584 49.093 13.608 ;
     RECT  49.045 6.288 49.133 7.56 ;
     RECT  48.881 67.248 49.165 67.368 ;
     RECT  48.953 56.976 49.169 57.144 ;
     RECT  48.773 3.408 49.189 3.432 ;
     RECT  48.841 10.272 49.237 11.448 ;
     RECT  49.189 3.408 49.276 3.768 ;
     RECT  47.873 5.088 49.283 5.256 ;
     RECT  49.237 10.272 49.283 11.688 ;
     RECT  49.093 17.088 49.34 17.112 ;
     RECT  49.043 18.144 49.34 18.792 ;
     RECT  48.589 31.536 49.349 31.896 ;
     RECT  49.34 17.088 49.381 18.792 ;
     RECT  49.169 57.024 49.381 57.144 ;
     RECT  49.283 5.232 49.421 5.256 ;
     RECT  48.157 37.488 49.421 37.512 ;
     RECT  49.381 16.512 49.427 18.792 ;
     RECT  48.769 49.056 49.453 54.6 ;
     RECT  49.025 72.144 49.453 72.84 ;
     RECT  48.269 40.08 49.457 40.104 ;
     RECT  48.701 38.592 49.493 38.616 ;
     RECT  49.453 48.528 49.529 54.6 ;
     RECT  49.165 67.248 49.571 67.992 ;
     RECT  49.283 10.848 49.621 11.688 ;
     RECT  49.276 3.408 49.637 3.432 ;
     RECT  49.057 59.184 49.637 60.408 ;
     RECT  48.563 27.888 49.669 27.912 ;
     RECT  48.517 29.04 49.669 29.064 ;
     RECT  49.025 25.872 49.673 26.808 ;
     RECT  49.669 27.888 49.705 29.064 ;
     RECT  49.529 49.872 49.709 54.6 ;
     RECT  48.521 0.24 49.717 0.648 ;
     RECT  49.717 0.192 49.741 0.648 ;
     RECT  49.033 1.728 49.741 1.8 ;
     RECT  48.773 62.736 49.777 63.672 ;
     RECT  49.349 31.536 49.781 31.56 ;
     RECT  49.427 16.512 49.789 17.112 ;
     RECT  49.093 13.584 49.813 13.704 ;
     RECT  49.453 71.328 49.817 72.84 ;
     RECT  49.345 61.392 49.849 61.416 ;
     RECT  49.427 18.144 49.889 18.792 ;
     RECT  49.621 10.848 49.909 12.024 ;
     RECT  49.813 13.056 49.909 13.704 ;
     RECT  49.813 14.784 49.909 14.808 ;
     RECT  49.909 10.848 49.955 14.808 ;
     RECT  48.125 22.512 49.957 23.832 ;
     RECT  49.043 20.016 50.021 20.04 ;
     RECT  49.381 57.024 50.033 58.104 ;
     RECT  49.025 46.752 50.101 47.448 ;
     RECT  49.529 48.528 50.101 48.552 ;
     RECT  49.957 8.976 50.129 9 ;
     RECT  50.129 8.976 50.165 9.144 ;
     RECT  49.741 0.192 50.173 1.8 ;
     RECT  48.773 69.408 50.197 69.576 ;
     RECT  49.817 71.328 50.197 71.352 ;
     RECT  49.777 62.736 50.245 63.816 ;
     RECT  50.173 0.192 50.281 1.848 ;
     RECT  49.955 10.848 50.281 10.92 ;
     RECT  49.955 12 50.281 14.808 ;
     RECT  50.281 0.192 50.285 2.28 ;
     RECT  50.285 0.192 50.339 0.648 ;
     RECT  50.033 57.312 50.381 58.104 ;
     RECT  49.637 59.184 50.381 59.976 ;
     RECT  49.133 6.288 50.389 6.648 ;
     RECT  50.339 0.192 50.393 0.552 ;
     RECT  50.197 69.408 50.447 71.352 ;
     RECT  49.597 37.152 50.461 37.176 ;
     RECT  50.245 62.736 50.569 63.864 ;
     RECT  49.345 45.648 50.641 45.672 ;
     RECT  50.101 46.752 50.641 48.552 ;
     RECT  49.709 49.872 50.641 52.488 ;
     RECT  50.533 25.104 50.677 25.128 ;
     RECT  47.369 41.52 50.677 41.544 ;
     RECT  50.381 57.312 50.677 59.976 ;
     RECT  49.849 61.008 50.677 61.416 ;
     RECT  49.571 67.248 50.677 67.272 ;
     RECT  50.389 6.048 50.725 6.648 ;
     RECT  50.281 12 50.725 15.24 ;
     RECT  50.677 41.52 50.749 42.504 ;
     RECT  49.709 53.76 50.849 54.6 ;
     RECT  50.677 57.312 50.857 61.416 ;
     RECT  50.857 57.312 50.869 61.656 ;
     RECT  50.569 62.736 50.869 64.392 ;
     RECT  49.669 7.968 50.893 7.992 ;
     RECT  48.995 35.712 50.965 35.928 ;
     RECT  50.461 36.912 50.965 37.176 ;
     RECT  50.641 45.648 50.965 52.488 ;
     RECT  50.849 53.76 50.965 54.696 ;
     RECT  50.285 1.728 51.008 2.28 ;
     RECT  50.821 3.84 51.008 3.864 ;
     RECT  50.725 4.896 51.008 6.648 ;
     RECT  50.893 7.632 51.008 7.992 ;
     RECT  50.165 8.976 51.008 9.72 ;
     RECT  50.281 10.8 51.008 10.92 ;
     RECT  50.725 12 51.008 15.48 ;
     RECT  49.789 16.512 51.008 16.536 ;
     RECT  49.889 18.144 51.008 18.216 ;
     RECT  50.021 19.968 51.008 20.04 ;
     RECT  49.957 22.512 51.008 23.976 ;
     RECT  50.677 25.104 51.008 25.464 ;
     RECT  49.673 26.496 51.008 26.808 ;
     RECT  49.705 27.888 51.008 29.112 ;
     RECT  50.605 30.384 51.008 30.408 ;
     RECT  50.965 35.712 51.008 37.176 ;
     RECT  50.353 38.256 51.008 38.28 ;
     RECT  50.749 40.656 51.008 42.504 ;
     RECT  49.237 43.776 51.008 43.8 ;
     RECT  50.965 45.648 51.008 54.696 ;
     RECT  50.869 57.312 51.008 64.392 ;
     RECT  49.957 65.52 51.008 65.544 ;
     RECT  50.677 67.152 51.008 67.272 ;
     RECT  50.447 68.64 51.008 71.352 ;
     RECT  49.817 72.816 51.008 72.84 ;
     RECT  49.025 74.016 51.008 75.192 ;
     RECT  51.008 1.728 51.112 75.612 ;
     RECT  51.112 1.728 51.304 75.342 ;
     RECT  51.304 49.776 51.329 53.928 ;
     RECT  51.304 25.968 51.365 27.192 ;
     RECT  51.304 74.688 51.365 75.192 ;
     RECT  51.304 13.056 51.401 13.608 ;
     RECT  51.304 28.224 51.401 28.248 ;
     RECT  51.304 23.808 51.443 23.832 ;
     RECT  50.393 0.192 51.541 0.504 ;
     RECT  51.365 75.072 51.545 75.192 ;
     RECT  51.304 72.192 51.581 73.368 ;
     RECT  51.365 25.968 51.617 26.808 ;
     RECT  51.304 47.088 51.617 48.408 ;
     RECT  51.304 63.072 51.689 63.864 ;
     RECT  51.304 70.8 51.689 70.824 ;
     RECT  51.617 47.28 51.875 48.408 ;
     RECT  51.304 18.144 51.923 19.992 ;
     RECT  51.541 0.192 51.937 0.648 ;
     RECT  51.304 1.728 51.937 5.208 ;
     RECT  51.304 6.624 52.019 7.8 ;
     RECT  51.304 57.12 52.211 60.216 ;
     RECT  51.937 0.192 52.229 5.208 ;
     RECT  51.304 30.384 52.229 31.32 ;
     RECT  51.304 35.712 52.259 39 ;
     RECT  51.304 9.216 52.265 9.24 ;
     RECT  51.304 10.8 52.265 11.064 ;
     RECT  51.304 33.6 52.273 34.2 ;
     RECT  52.259 36.528 52.297 39 ;
     RECT  51.304 65.52 52.301 69.624 ;
     RECT  52.019 6.624 52.307 7.464 ;
     RECT  52.301 65.52 52.307 69.192 ;
     RECT  52.229 3.408 52.337 5.208 ;
     RECT  52.307 65.52 52.348 66.648 ;
     RECT  51.304 44.448 52.369 44.472 ;
     RECT  52.348 65.52 52.369 66.168 ;
     RECT  52.307 6.624 52.373 6.84 ;
     RECT  52.297 36.528 52.373 39.288 ;
     RECT  52.337 4.992 52.405 5.208 ;
     RECT  51.875 47.424 52.405 48.408 ;
     RECT  51.329 49.776 52.405 52.392 ;
     RECT  51.329 53.376 52.405 53.928 ;
     RECT  52.229 30.384 52.409 30.744 ;
     RECT  51.304 61.2 52.409 61.656 ;
     RECT  52.333 11.424 52.445 11.832 ;
     RECT  52.307 67.824 52.445 69.192 ;
     RECT  52.405 4.992 52.451 5.736 ;
     RECT  51.581 72.432 52.477 73.368 ;
     RECT  52.373 6.816 52.481 6.84 ;
     RECT  52.451 5.136 52.489 5.736 ;
     RECT  51.304 42.48 52.501 42.504 ;
     RECT  51.545 75.072 52.513 75.144 ;
     RECT  51.401 13.056 52.585 13.08 ;
     RECT  52.585 12.528 52.597 13.08 ;
     RECT  52.409 61.536 52.621 61.656 ;
     RECT  52.369 65.184 52.697 66.168 ;
     RECT  52.369 44.448 52.796 45 ;
     RECT  51.689 63.216 52.805 63.864 ;
     RECT  52.501 42.048 52.873 42.504 ;
     RECT  51.304 32.352 52.877 32.376 ;
     RECT  52.621 61.536 52.877 62.184 ;
     RECT  52.873 41.568 52.883 42.504 ;
     RECT  52.796 44.064 52.883 45 ;
     RECT  52.489 5.136 52.949 5.304 ;
     RECT  52.693 10.128 52.949 10.152 ;
     RECT  52.949 5.136 52.985 5.16 ;
     RECT  52.597 12.528 53.021 13.128 ;
     RECT  52.445 68.544 53.021 69.192 ;
     RECT  51.304 14.784 53.053 17.112 ;
     RECT  52.477 72.432 53.057 73.8 ;
     RECT  53.053 14.256 53.089 17.112 ;
     RECT  51.923 18.144 53.089 19.8 ;
     RECT  52.273 33.6 53.093 33.624 ;
     RECT  52.373 36.528 53.129 36.6 ;
     RECT  52.883 44.976 53.129 45 ;
     RECT  52.211 57.12 53.165 59.736 ;
     RECT  51.617 25.968 53.305 26.664 ;
     RECT  51.304 22.512 53.315 22.536 ;
     RECT  53.089 14.256 53.333 19.8 ;
     RECT  52.513 75.024 53.341 75.144 ;
     RECT  51.304 46.032 53.345 46.056 ;
     RECT  52.445 11.424 53.377 11.448 ;
     RECT  53.305 25.824 53.377 26.664 ;
     RECT  52.877 61.536 53.381 61.656 ;
     RECT  53.057 72.432 53.381 73.512 ;
     RECT  53.333 14.208 53.417 19.8 ;
     RECT  52.405 47.424 53.417 53.928 ;
     RECT  52.229 0.192 53.449 2.232 ;
     RECT  52.409 30.72 53.449 30.744 ;
     RECT  53.417 47.424 53.449 47.88 ;
     RECT  51.304 21.12 53.485 21.144 ;
     RECT  53.129 36.528 53.485 36.552 ;
     RECT  52.805 63.216 53.485 63.24 ;
     RECT  53.449 30.72 53.533 31.368 ;
     RECT  53.417 15.072 53.557 19.8 ;
     RECT  53.485 21.072 53.557 21.144 ;
     RECT  52.373 37.872 53.557 39.288 ;
     RECT  53.449 47.136 53.557 47.88 ;
     RECT  53.449 0.192 53.561 2.328 ;
     RECT  53.161 28.272 53.593 28.296 ;
     RECT  52.765 8.544 53.597 8.568 ;
     RECT  53.557 37.872 53.597 39.912 ;
     RECT  53.377 25.824 53.605 27.24 ;
     RECT  53.593 28.272 53.605 29.112 ;
     RECT  53.165 57.168 53.605 59.736 ;
     RECT  53.377 10.848 53.633 11.448 ;
     RECT  53.557 15.072 53.633 21.144 ;
     RECT  53.597 38.16 53.641 39.912 ;
     RECT  53.605 25.824 53.651 29.112 ;
     RECT  53.605 57.168 53.651 60.888 ;
     RECT  53.485 36.432 53.669 36.552 ;
     RECT  53.651 29.088 53.677 29.112 ;
     RECT  53.651 27.888 53.692 27.912 ;
     RECT  53.651 60.384 53.692 60.888 ;
     RECT  53.629 6.912 53.737 6.936 ;
     RECT  53.737 6.864 53.738 6.936 ;
     RECT  53.633 15.984 53.741 21.144 ;
     RECT  53.669 36.528 53.741 36.552 ;
     RECT  53.561 1.728 53.773 2.328 ;
     RECT  52.337 3.408 53.773 3.48 ;
     RECT  53.557 47.088 53.773 47.88 ;
     RECT  53.557 35.328 53.777 35.352 ;
     RECT  53.417 48.864 53.845 53.928 ;
     RECT  53.641 38.16 53.849 39.384 ;
     RECT  53.773 1.728 53.885 3.48 ;
     RECT  53.749 9.696 53.885 9.72 ;
     RECT  53.533 30.72 53.921 30.744 ;
     RECT  53.021 69.168 53.941 69.192 ;
     RECT  53.917 70.704 53.941 70.728 ;
     RECT  53.738 6.864 53.993 6.888 ;
     RECT  53.917 13.872 54.001 13.896 ;
     RECT  53.381 72.432 54.025 73.368 ;
     RECT  53.773 46.944 54.029 47.88 ;
     RECT  52.697 65.184 54.061 66.12 ;
     RECT  53.885 2.688 54.065 3.48 ;
     RECT  53.989 23.376 54.073 23.4 ;
     RECT  53.651 25.824 54.097 26.52 ;
     RECT  53.341 74.976 54.097 75.144 ;
     RECT  53.741 15.984 54.101 19.368 ;
     RECT  53.849 38.544 54.101 39.384 ;
     RECT  54.044 13.632 54.131 13.704 ;
     RECT  53.741 20.496 54.169 21.144 ;
     RECT  54.101 15.984 54.209 19.224 ;
     RECT  54.097 25.632 54.241 26.52 ;
     RECT  54.169 20.496 54.325 21.72 ;
     RECT  53.561 0.192 54.461 0.552 ;
     RECT  54.065 2.88 54.493 3.48 ;
     RECT  54.029 47.088 54.533 47.88 ;
     RECT  53.845 48.864 54.565 54.12 ;
     RECT  54.493 2.88 54.601 4.584 ;
     RECT  52.883 41.568 54.601 41.592 ;
     RECT  54.533 47.28 54.605 47.88 ;
     RECT  54.325 20.496 54.611 20.952 ;
     RECT  54.529 22.752 54.613 22.776 ;
     RECT  54.613 8.544 54.637 8.568 ;
     RECT  54.565 48.864 54.637 54.6 ;
     RECT  53.485 63.12 54.637 63.24 ;
     RECT  54.061 65.04 54.637 66.12 ;
     RECT  54.025 72.288 54.673 73.368 ;
     RECT  54.601 2.88 54.685 5.016 ;
     RECT  53.692 60.384 54.709 60.408 ;
     RECT  54.673 35.808 54.745 35.832 ;
     RECT  54.209 16.512 54.748 19.224 ;
     RECT  53.633 10.848 54.781 11.16 ;
     RECT  53.021 12.528 54.781 12.552 ;
     RECT  54.781 10.848 54.821 12.552 ;
     RECT  54.737 15.408 54.821 15.432 ;
     RECT  54.637 63.12 54.853 66.12 ;
     RECT  54.673 72.288 54.917 73.512 ;
     RECT  54.097 74.976 54.917 75.192 ;
     RECT  54.673 31.68 54.925 32.52 ;
     RECT  54.745 35.808 54.961 35.976 ;
     RECT  54.025 6 54.997 6.744 ;
     RECT  54.925 30.816 55.009 32.52 ;
     RECT  54.601 41.472 55.033 41.592 ;
     RECT  54.853 62.64 55.036 66.12 ;
     RECT  54.637 8.544 55.061 9.48 ;
     RECT  54.997 37.872 55.069 37.896 ;
     RECT  54.997 1.728 55.093 1.752 ;
     RECT  55.061 8.496 55.093 9.48 ;
     RECT  54.821 10.848 55.093 11.976 ;
     RECT  54.637 48.864 55.105 54.888 ;
     RECT  55.036 62.64 55.105 63.24 ;
     RECT  53.651 57.168 55.109 59.208 ;
     RECT  55.093 8.496 55.145 11.976 ;
     RECT  54.961 35.808 55.181 36.408 ;
     RECT  54.461 0.24 55.189 0.552 ;
     RECT  55.036 64.368 55.189 66.12 ;
     RECT  55.189 64.368 55.217 66.168 ;
     RECT  54.997 6 55.237 6.888 ;
     RECT  55.109 58.128 55.244 59.208 ;
     RECT  54.709 60.384 55.244 60.456 ;
     RECT  54.241 25.104 55.249 26.52 ;
     RECT  55.093 1.728 55.285 1.8 ;
     RECT  54.685 2.88 55.285 4.056 ;
     RECT  55.181 36.384 55.285 36.408 ;
     RECT  55.069 37.584 55.285 37.896 ;
     RECT  55.244 58.128 55.285 60.456 ;
     RECT  55.105 48.672 55.325 54.888 ;
     RECT  55.285 58.128 55.331 60.984 ;
     RECT  55.009 31.68 55.361 32.52 ;
     RECT  54.101 39.36 55.361 39.384 ;
     RECT  55.033 40.896 55.537 41.592 ;
     RECT  55.331 60.288 55.58 60.984 ;
     RECT  53.941 69.168 55.609 70.728 ;
     RECT  55.105 34.08 55.645 34.104 ;
     RECT  55.189 0.24 55.669 0.6 ;
     RECT  54.611 20.928 55.669 20.952 ;
     RECT  55.393 45.648 55.681 45.672 ;
     RECT  55.217 65.184 55.753 66.168 ;
     RECT  53.701 67.344 55.753 67.368 ;
     RECT  55.669 0.24 55.765 0.648 ;
     RECT  55.393 19.824 55.765 19.848 ;
     RECT  55.669 20.928 55.765 21.096 ;
     RECT  54.748 16.512 55.789 18.264 ;
     RECT  55.525 28.8 55.813 28.824 ;
     RECT  55.249 25.104 55.82 26.616 ;
     RECT  55.765 0.24 55.861 0.696 ;
     RECT  55.237 5.136 55.861 6.888 ;
     RECT  54.131 13.68 55.861 13.704 ;
     RECT  55.82 25.104 55.861 26.76 ;
     RECT  55.861 0.192 55.933 0.696 ;
     RECT  55.681 45.648 56.005 46.296 ;
     RECT  54.605 47.28 56.005 47.688 ;
     RECT  55.933 0.144 56.117 0.696 ;
     RECT  55.429 56.496 56.257 56.808 ;
     RECT  56.005 45.648 56.293 47.688 ;
     RECT  55.609 69.168 56.293 70.824 ;
     RECT  56.293 45.552 56.329 47.688 ;
     RECT  55.765 19.824 56.365 21.096 ;
     RECT  56.221 22.656 56.365 22.68 ;
     RECT  55.361 31.68 56.401 31.704 ;
     RECT  55.501 33.072 56.401 33.096 ;
     RECT  55.285 1.728 56.408 4.056 ;
     RECT  55.861 5.136 56.408 6.984 ;
     RECT  55.573 7.968 56.408 7.992 ;
     RECT  55.145 9.12 56.408 11.976 ;
     RECT  55.861 13.68 56.408 13.752 ;
     RECT  55.573 14.832 56.408 14.856 ;
     RECT  55.789 16.512 56.408 18.792 ;
     RECT  56.365 19.824 56.408 22.68 ;
     RECT  55.861 24.48 56.408 26.76 ;
     RECT  55.813 27.936 56.408 28.824 ;
     RECT  55.717 30.672 56.408 30.696 ;
     RECT  56.401 31.68 56.408 33.096 ;
     RECT  55.645 34.08 56.408 34.824 ;
     RECT  55.285 36.384 56.408 37.896 ;
     RECT  55.537 40.32 56.408 41.592 ;
     RECT  56.329 45.168 56.408 47.688 ;
     RECT  55.325 48.672 56.408 51.912 ;
     RECT  55.325 52.992 56.408 54.888 ;
     RECT  56.257 56.256 56.408 56.808 ;
     RECT  55.331 58.128 56.408 59.256 ;
     RECT  55.58 60.288 56.408 61.272 ;
     RECT  55.105 62.496 56.408 63.24 ;
     RECT  55.753 65.184 56.408 67.368 ;
     RECT  56.293 68.928 56.408 70.824 ;
     RECT  54.917 72.288 56.408 75.192 ;
     RECT  56.408 1.728 56.512 75.612 ;
     RECT  56.117 0.192 56.617 0.696 ;
     RECT  56.512 1.728 56.617 75.342 ;
     RECT  56.617 0.192 56.704 75.342 ;
     RECT  56.704 31.68 56.765 32.232 ;
     RECT  56.704 44.448 56.801 45.192 ;
     RECT  56.704 16.896 56.837 18.36 ;
     RECT  56.704 72.336 57.017 75.192 ;
     RECT  56.704 24.48 57.053 24.504 ;
     RECT  56.837 16.896 57.059 18.216 ;
     RECT  56.704 33.264 57.059 33.672 ;
     RECT  56.704 11.52 57.061 12.024 ;
     RECT  57.059 16.896 57.089 17.928 ;
     RECT  56.704 46.176 57.089 52.584 ;
     RECT  57.059 33.648 57.107 33.672 ;
     RECT  56.704 19.872 57.155 23.256 ;
     RECT  56.704 28.992 57.155 30.264 ;
     RECT  56.704 57.84 57.161 59.256 ;
     RECT  56.704 60.816 57.161 60.84 ;
     RECT  56.704 66.576 57.251 67.704 ;
     RECT  56.704 7.968 57.277 8.568 ;
     RECT  56.704 69.936 57.292 70.824 ;
     RECT  57.089 16.896 57.299 16.92 ;
     RECT  56.704 40.32 57.299 41.496 ;
     RECT  56.704 10.176 57.305 10.2 ;
     RECT  57.089 47.328 57.305 52.584 ;
     RECT  57.155 20.016 57.347 23.256 ;
     RECT  57.347 23.232 57.388 23.256 ;
     RECT  56.801 44.448 57.413 45.048 ;
     RECT  56.704 56.016 57.413 56.424 ;
     RECT  57.017 72.336 57.413 73.944 ;
     RECT  57.347 20.016 57.521 22.152 ;
     RECT  56.704 15.6 57.529 15.624 ;
     RECT  57.305 47.328 57.557 47.64 ;
     RECT  57.277 8.496 57.587 8.568 ;
     RECT  57.292 69.984 57.593 70.824 ;
     RECT  56.704 36.048 57.629 37.464 ;
     RECT  57.557 47.616 57.629 47.64 ;
     RECT  56.704 62.496 57.629 63.096 ;
     RECT  57.413 56.16 57.724 56.424 ;
     RECT  56.704 43.296 57.737 43.32 ;
     RECT  57.161 57.84 57.809 58.68 ;
     RECT  57.413 72.336 57.845 73.512 ;
     RECT  57.769 14.256 57.853 14.28 ;
     RECT  57.089 46.176 57.877 46.2 ;
     RECT  57.629 62.496 57.917 63 ;
     RECT  57.305 48.624 57.949 52.584 ;
     RECT  57.949 48.624 57.973 52.872 ;
     RECT  57.629 37.056 57.989 37.464 ;
     RECT  56.704 54.672 58.019 54.696 ;
     RECT  57.809 57.84 58.019 57.864 ;
     RECT  57.724 56.16 58.06 56.184 ;
     RECT  57.089 17.904 58.085 17.928 ;
     RECT  57.973 48.624 58.097 53.4 ;
     RECT  56.704 0.192 58.129 6.312 ;
     RECT  57.913 13.008 58.163 13.032 ;
     RECT  58.085 17.616 58.169 17.928 ;
     RECT  57.521 20.016 58.169 21.672 ;
     RECT  58.169 20.016 58.204 20.568 ;
     RECT  58.021 43.344 58.205 43.368 ;
     RECT  57.877 46.08 58.205 46.2 ;
     RECT  57.251 66.576 58.273 67.608 ;
     RECT  58.129 0.192 58.276 6.744 ;
     RECT  56.704 65.184 58.309 65.448 ;
     RECT  56.704 26.496 58.313 27.336 ;
     RECT  57.989 37.056 58.313 37.32 ;
     RECT  57.061 11.52 58.345 11.544 ;
     RECT  58.345 11.424 58.385 11.544 ;
     RECT  57.587 8.496 58.453 8.52 ;
     RECT  57.299 40.32 58.453 41.208 ;
     RECT  58.165 13.104 58.489 13.128 ;
     RECT  56.765 31.872 58.489 32.232 ;
     RECT  58.453 40.032 58.501 41.208 ;
     RECT  58.501 40.032 58.547 41.928 ;
     RECT  58.276 0.192 58.561 6.792 ;
     RECT  58.169 17.904 58.561 17.928 ;
     RECT  58.547 41.904 58.561 41.928 ;
     RECT  57.155 28.992 58.625 29.928 ;
     RECT  58.625 28.992 58.633 30.84 ;
     RECT  58.489 31.872 58.633 32.376 ;
     RECT  58.385 11.424 58.645 11.496 ;
     RECT  57.845 72.816 58.669 73.512 ;
     RECT  58.489 13.104 58.691 13.848 ;
     RECT  58.633 28.992 58.691 32.376 ;
     RECT  58.561 17.904 58.693 18.744 ;
     RECT  58.204 20.016 58.693 20.04 ;
     RECT  58.205 46.128 58.705 46.2 ;
     RECT  58.669 72.816 58.705 74.088 ;
     RECT  57.017 75.168 58.705 75.192 ;
     RECT  58.691 30.816 58.709 32.376 ;
     RECT  58.693 17.904 58.739 20.04 ;
     RECT  58.705 46.128 58.741 47.016 ;
     RECT  58.097 48.624 58.741 52.872 ;
     RECT  58.561 41.904 58.777 42.168 ;
     RECT  57.593 69.984 58.777 70.152 ;
     RECT  57.413 45.024 58.781 45.048 ;
     RECT  58.741 46.128 58.781 52.872 ;
     RECT  58.781 46.128 58.817 51.72 ;
     RECT  58.273 66.576 58.817 67.704 ;
     RECT  58.561 0.144 58.849 6.792 ;
     RECT  58.709 31.344 58.853 32.376 ;
     RECT  58.853 32.208 58.925 32.376 ;
     RECT  58.777 69.984 58.925 70.68 ;
     RECT  58.817 47.28 58.961 51.72 ;
     RECT  56.704 68.928 59.065 68.952 ;
     RECT  58.309 65.136 59.101 65.448 ;
     RECT  58.705 72.816 59.105 75.192 ;
     RECT  58.453 7.968 59.137 8.52 ;
     RECT  58.817 67.296 59.141 67.704 ;
     RECT  58.925 70.656 59.173 70.68 ;
     RECT  58.777 41.904 59.177 43.128 ;
     RECT  57.917 62.496 59.177 62.952 ;
     RECT  59.105 74.064 59.177 75.192 ;
     RECT  59.101 65.136 59.18 66.168 ;
     RECT  58.547 40.032 59.209 40.056 ;
     RECT  59.177 62.496 59.209 62.664 ;
     RECT  59.173 70.656 59.219 71.832 ;
     RECT  59.137 7.968 59.221 9.144 ;
     RECT  59.209 39.888 59.249 40.056 ;
     RECT  59.219 71.328 59.26 71.832 ;
     RECT  59.18 64.896 59.267 66.168 ;
     RECT  58.817 46.128 59.321 46.2 ;
     RECT  58.781 52.752 59.321 52.872 ;
     RECT  58.645 10.848 59.393 11.496 ;
     RECT  59.321 46.176 59.393 46.2 ;
     RECT  59.065 68.928 59.429 69.096 ;
     RECT  59.177 75.168 59.497 75.192 ;
     RECT  57.629 36.048 59.501 36.072 ;
     RECT  58.313 26.496 59.509 26.52 ;
     RECT  58.691 28.992 59.555 29.4 ;
     RECT  59.221 8.064 59.564 9.144 ;
     RECT  59.393 10.848 59.564 11.448 ;
     RECT  58.885 25.44 59.564 25.464 ;
     RECT  59.173 23.376 59.605 23.4 ;
     RECT  59.564 24.48 59.605 25.464 ;
     RECT  59.173 34.752 59.641 34.776 ;
     RECT  59.564 8.064 59.651 11.448 ;
     RECT  59.605 23.376 59.651 25.464 ;
     RECT  59.429 68.928 59.677 68.952 ;
     RECT  58.313 37.296 59.708 37.32 ;
     RECT  58.741 38.4 59.708 38.424 ;
     RECT  59.209 61.536 59.747 62.664 ;
     RECT  59.651 25.44 59.753 25.464 ;
     RECT  59.555 29.376 59.785 29.4 ;
     RECT  58.169 21.648 59.857 21.672 ;
     RECT  59.267 66.096 59.857 66.168 ;
     RECT  59.141 67.296 59.857 67.32 ;
     RECT  59.785 29.376 59.891 29.496 ;
     RECT  59.857 21.648 59.897 22.2 ;
     RECT  59.177 43.104 59.897 43.128 ;
     RECT  58.961 47.28 59.897 51.48 ;
     RECT  59.857 66.096 59.897 67.32 ;
     RECT  59.845 27.888 59.932 27.912 ;
     RECT  58.849 0.144 60.001 6.84 ;
     RECT  59.321 52.752 60.005 52.776 ;
     RECT  58.691 13.824 60.037 13.848 ;
     RECT  58.739 17.904 60.037 17.928 ;
     RECT  58.925 32.208 60.037 32.232 ;
     RECT  60.037 13.824 60.041 14.28 ;
     RECT  58.129 60.288 60.044 60.312 ;
     RECT  60.041 14.256 60.109 14.28 ;
     RECT  59.897 47.664 60.109 51.48 ;
     RECT  60.044 60.288 60.113 60.408 ;
     RECT  60.113 60.384 60.131 60.408 ;
     RECT  60.001 0.144 60.179 6.888 ;
     RECT  59.651 8.064 60.221 9.144 ;
     RECT  59.651 23.376 60.221 23.88 ;
     RECT  59.209 44.352 60.253 44.376 ;
     RECT  60.253 43.296 60.293 44.376 ;
     RECT  59.747 62.64 60.365 62.664 ;
     RECT  59.677 68.448 60.365 68.952 ;
     RECT  58.777 16.272 60.389 16.296 ;
     RECT  59.177 41.904 60.397 41.928 ;
     RECT  60.037 21.024 60.401 21.048 ;
     RECT  59.177 74.064 60.421 74.088 ;
     RECT  59.497 75.168 60.421 75.288 ;
     RECT  60.421 74.064 60.467 75.288 ;
     RECT  60.221 8.064 60.469 8.808 ;
     RECT  60.467 74.976 60.473 75.288 ;
     RECT  59.26 71.808 60.476 71.832 ;
     RECT  59.105 72.816 60.476 72.84 ;
     RECT  60.469 7.968 60.553 8.808 ;
     RECT  60.476 71.808 60.563 72.84 ;
     RECT  60.553 8.256 60.581 8.808 ;
     RECT  60.473 74.976 60.581 75.192 ;
     RECT  60.037 32.208 60.613 32.472 ;
     RECT  60.397 41.904 60.613 42.216 ;
     RECT  60.563 71.808 60.649 71.832 ;
     RECT  60.581 8.256 60.653 8.376 ;
     RECT  60.293 43.296 60.653 44.28 ;
     RECT  60.109 14.256 60.685 14.328 ;
     RECT  60.649 71.184 60.689 71.832 ;
     RECT  59.708 37.296 60.716 38.424 ;
     RECT  59.249 39.888 60.716 39.912 ;
     RECT  60.389 15.984 60.793 16.296 ;
     RECT  59.509 26.496 60.803 26.712 ;
     RECT  60.757 25.056 60.805 25.08 ;
     RECT  59.651 10.8 60.833 11.448 ;
     RECT  60.685 14.256 60.865 14.376 ;
     RECT  60.803 26.688 60.901 26.712 ;
     RECT  59.641 34.752 60.937 35.88 ;
     RECT  59.897 22.176 60.973 22.2 ;
     RECT  60.221 23.376 60.973 23.4 ;
     RECT  60.757 70.08 60.973 70.104 ;
     RECT  60.689 71.184 60.973 71.736 ;
     RECT  60.793 15.984 61.009 16.536 ;
     RECT  60.805 24.864 61.045 25.08 ;
     RECT  60.716 37.296 61.045 39.912 ;
     RECT  60.613 41.04 61.045 42.216 ;
     RECT  60.901 45.792 61.045 45.816 ;
     RECT  60.037 17.712 61.081 17.928 ;
     RECT  58.739 19.344 61.081 20.04 ;
     RECT  61.045 45.792 61.081 46.104 ;
     RECT  60.833 10.848 61.237 11.448 ;
     RECT  60.505 12.48 61.237 12.504 ;
     RECT  60.973 22.176 61.261 23.4 ;
     RECT  59.897 66.384 61.261 66.408 ;
     RECT  60.865 14.256 61.297 14.52 ;
     RECT  61.009 15.984 61.429 16.584 ;
     RECT  61.081 17.712 61.429 20.04 ;
     RECT  60.179 2.832 61.441 6.888 ;
     RECT  61.297 14.16 61.441 14.52 ;
     RECT  61.429 15.984 61.441 20.04 ;
     RECT  61.261 22.032 61.477 23.4 ;
     RECT  61.045 37.296 61.477 42.216 ;
     RECT  60.653 43.92 61.477 44.28 ;
     RECT  61.081 45.792 61.477 46.584 ;
     RECT  61.477 21.792 61.58 23.4 ;
     RECT  61.477 43.92 61.585 46.584 ;
     RECT  60.109 47.664 61.585 51.96 ;
     RECT  61.58 21.792 61.613 23.688 ;
     RECT  60.653 8.256 61.621 8.28 ;
     RECT  59.891 29.472 61.657 29.496 ;
     RECT  60.937 33.84 61.657 35.88 ;
     RECT  61.613 21.792 61.669 23.784 ;
     RECT  61.045 24.864 61.669 25.32 ;
     RECT  60.973 70.08 61.669 71.736 ;
     RECT  60.563 72.816 61.669 72.84 ;
     RECT  60.179 0.144 61.808 1.848 ;
     RECT  61.441 2.832 61.808 7.224 ;
     RECT  61.621 8.256 61.808 8.472 ;
     RECT  61.621 9.504 61.808 9.528 ;
     RECT  61.237 10.848 61.808 12.504 ;
     RECT  61.441 14.16 61.808 20.04 ;
     RECT  61.669 21.792 61.808 25.32 ;
     RECT  60.901 26.688 61.808 27.192 ;
     RECT  61.693 28.464 61.808 28.488 ;
     RECT  61.657 29.472 61.808 29.784 ;
     RECT  60.613 32.208 61.808 32.616 ;
     RECT  61.657 33.84 61.808 35.976 ;
     RECT  61.477 37.248 61.808 42.216 ;
     RECT  61.585 43.92 61.808 51.96 ;
     RECT  59.747 61.536 61.808 61.56 ;
     RECT  61.369 64.704 61.808 64.728 ;
     RECT  61.261 66.384 61.808 67.32 ;
     RECT  60.365 68.88 61.808 68.952 ;
     RECT  61.669 70.08 61.808 72.84 ;
     RECT  60.581 74.976 61.808 75 ;
     RECT  61.808 0.144 61.912 75.612 ;
     RECT  61.912 0.144 62.104 75.342 ;
     RECT  62.104 18.816 62.201 18.984 ;
     RECT  62.104 43.2 62.237 52.44 ;
     RECT  62.104 22.032 62.381 22.056 ;
     RECT  62.104 25.008 62.417 25.992 ;
     RECT  62.104 71.712 62.489 72.84 ;
     RECT  62.104 29.76 62.525 29.784 ;
     RECT  62.104 34.08 62.597 35.208 ;
     RECT  62.104 2.784 62.633 9.528 ;
     RECT  62.633 3.84 62.669 9.528 ;
     RECT  62.237 43.2 62.675 47.736 ;
     RECT  62.237 48.768 62.771 52.44 ;
     RECT  62.675 44.928 62.777 47.736 ;
     RECT  62.669 4.272 62.813 9.528 ;
     RECT  62.633 2.784 62.819 2.856 ;
     RECT  62.104 67.296 62.819 68.952 ;
     RECT  62.813 4.464 62.921 9.096 ;
     RECT  62.104 32.448 62.921 33.048 ;
     RECT  62.104 0.144 62.957 1.752 ;
     RECT  62.104 27.168 62.957 27.96 ;
     RECT  62.921 32.592 62.957 33.048 ;
     RECT  62.104 64.176 62.957 64.728 ;
     RECT  62.957 64.176 62.963 64.2 ;
     RECT  62.104 66.144 63.065 66.168 ;
     RECT  62.489 72.528 63.101 72.84 ;
     RECT  62.597 34.08 63.137 34.824 ;
     RECT  62.104 38.784 63.137 38.808 ;
     RECT  62.417 25.008 63.169 25.608 ;
     RECT  62.104 41.856 63.241 41.976 ;
     RECT  62.675 43.2 63.241 43.224 ;
     RECT  63.241 41.856 63.281 43.224 ;
     RECT  62.819 68.928 63.281 68.952 ;
     RECT  62.104 70.272 63.301 70.296 ;
     RECT  62.819 67.296 63.316 67.32 ;
     RECT  63.316 67.248 63.317 67.32 ;
     RECT  62.104 20.4 63.353 20.424 ;
     RECT  62.104 40.032 63.353 40.44 ;
     RECT  63.101 72.528 63.361 72.552 ;
     RECT  62.777 47.712 63.389 47.736 ;
     RECT  63.301 70.272 63.389 71.496 ;
     RECT  62.921 4.464 63.425 8.376 ;
     RECT  62.104 14.688 63.497 17.592 ;
     RECT  63.497 16.656 63.529 17.592 ;
     RECT  63.529 16.656 63.533 17.64 ;
     RECT  63.281 41.856 63.569 42.6 ;
     RECT  63.425 4.464 63.587 7.176 ;
     RECT  62.957 33.024 63.709 33.048 ;
     RECT  62.771 48.768 63.709 48.792 ;
     RECT  63.169 24.528 63.745 25.608 ;
     RECT  62.957 27.168 63.745 27.864 ;
     RECT  62.104 11.232 63.781 11.256 ;
     RECT  63.097 22.176 63.785 22.2 ;
     RECT  63.569 41.856 63.785 42.216 ;
     RECT  63.565 23.328 63.809 23.352 ;
     RECT  63.745 24.528 63.809 27.864 ;
     RECT  63.781 11.232 63.827 11.976 ;
     RECT  63.809 23.328 63.829 27.864 ;
     RECT  63.829 22.656 63.893 27.864 ;
     RECT  62.957 0.144 63.929 1.032 ;
     RECT  63.425 8.16 63.961 8.376 ;
     RECT  63.587 4.656 63.965 7.176 ;
     RECT  63.965 6.24 64.001 6.456 ;
     RECT  63.389 71.472 64.001 71.496 ;
     RECT  63.353 40.032 64.037 40.2 ;
     RECT  63.893 22.656 64.073 23.256 ;
     RECT  63.965 4.656 64.115 5.256 ;
     RECT  63.961 8.16 64.213 8.472 ;
     RECT  62.201 18.96 64.213 18.984 ;
     RECT  63.533 17.04 64.249 17.64 ;
     RECT  64.213 18.912 64.249 18.984 ;
     RECT  63.709 33.024 64.285 33.624 ;
     RECT  63.137 34.8 64.285 34.824 ;
     RECT  63.317 67.248 64.289 67.272 ;
     RECT  63.827 11.952 64.357 11.976 ;
     RECT  64.249 13.056 64.357 13.08 ;
     RECT  62.771 49.872 64.361 52.44 ;
     RECT  64.213 8.16 64.393 8.52 ;
     RECT  64.249 38.208 64.403 38.664 ;
     RECT  64.285 33.024 64.405 35.064 ;
     RECT  64.405 32.496 64.451 35.064 ;
     RECT  64.451 33.6 64.499 34.248 ;
     RECT  63.893 24.336 64.577 27.864 ;
     RECT  63.709 47.808 64.577 48.792 ;
     RECT  64.249 17.04 64.613 19.416 ;
     RECT  64.577 27.168 64.649 27.864 ;
     RECT  62.777 44.928 64.649 46.632 ;
     RECT  64.357 36.096 64.681 36.12 ;
     RECT  64.681 35.328 64.685 36.12 ;
     RECT  64.393 8.16 64.717 9.048 ;
     RECT  64.577 48.768 64.717 48.792 ;
     RECT  64.361 49.872 64.717 51.48 ;
     RECT  64.501 31.104 64.828 31.128 ;
     RECT  64.613 17.04 64.829 18.936 ;
     RECT  64.649 27.648 64.865 27.864 ;
     RECT  64.717 48.768 64.883 51.48 ;
     RECT  64.649 45.168 64.933 46.632 ;
     RECT  64.717 8.16 65.005 9.528 ;
     RECT  62.819 2.784 65.009 2.808 ;
     RECT  64.829 17.616 65.009 18.936 ;
     RECT  64.577 24.336 65.027 25.704 ;
     RECT  64.073 23.232 65.081 23.256 ;
     RECT  63.785 42.144 65.081 42.216 ;
     RECT  63.497 14.688 65.117 15.336 ;
     RECT  65.009 17.616 65.117 17.64 ;
     RECT  64.033 21.36 65.221 21.384 ;
     RECT  64.451 32.496 65.221 32.52 ;
     RECT  64.933 45.168 65.257 46.68 ;
     RECT  63.929 0.144 65.297 0.984 ;
     RECT  65.027 24.336 65.297 25.176 ;
     RECT  64.883 51.408 65.441 51.48 ;
     RECT  65.117 14.688 65.549 14.808 ;
     RECT  65.221 20.736 65.555 21.384 ;
     RECT  63.205 29.088 65.581 29.112 ;
     RECT  65.549 14.688 65.585 14.712 ;
     RECT  64.357 11.952 65.621 13.08 ;
     RECT  64.865 27.84 65.621 27.864 ;
     RECT  65.257 45.168 65.693 47.112 ;
     RECT  65.693 47.088 65.797 47.112 ;
     RECT  64.883 48.768 65.797 50.424 ;
     RECT  65.797 47.088 65.837 50.424 ;
     RECT  65.297 0.144 65.873 0.936 ;
     RECT  64.403 38.64 65.873 38.664 ;
     RECT  65.581 29.088 65.905 29.64 ;
     RECT  64.001 6.24 65.945 6.264 ;
     RECT  64.357 10.848 66.085 10.872 ;
     RECT  65.621 11.952 66.085 12.888 ;
     RECT  65.005 8.112 66.125 9.528 ;
     RECT  66.085 10.848 66.125 12.888 ;
     RECT  65.297 24.768 66.133 25.176 ;
     RECT  66.133 24.768 66.161 25.752 ;
     RECT  66.161 25.152 66.179 25.752 ;
     RECT  64.037 40.176 66.284 40.2 ;
     RECT  65.365 41.616 66.301 41.64 ;
     RECT  66.284 39.984 66.325 40.2 ;
     RECT  66.301 41.424 66.476 41.64 ;
     RECT  65.221 31.92 66.481 32.52 ;
     RECT  66.337 17.616 66.517 17.64 ;
     RECT  66.085 43.488 66.589 43.512 ;
     RECT  65.693 45.168 66.589 46.008 ;
     RECT  65.125 22.704 66.697 22.728 ;
     RECT  66.125 10.896 66.709 12.888 ;
     RECT  66.589 43.488 66.733 46.008 ;
     RECT  65.837 47.088 66.733 48.792 ;
     RECT  66.481 31.296 66.769 32.52 ;
     RECT  66.229 34.128 66.769 34.152 ;
     RECT  66.121 38.208 66.86 38.232 ;
     RECT  65.009 18.768 66.908 18.936 ;
     RECT  66.517 17.088 66.949 17.64 ;
     RECT  66.908 18.768 66.949 19.176 ;
     RECT  66.179 25.728 66.985 25.752 ;
     RECT  65.905 27.936 66.985 29.64 ;
     RECT  66.985 25.728 67.093 26.232 ;
     RECT  64.115 4.656 67.165 4.872 ;
     RECT  65.837 49.872 67.165 50.424 ;
     RECT  65.441 51.456 67.165 51.48 ;
     RECT  67.165 4.656 67.208 5.208 ;
     RECT  66.125 8.112 67.208 8.712 ;
     RECT  66.709 10.896 67.208 13.704 ;
     RECT  66.949 16.368 67.208 17.64 ;
     RECT  66.949 18.768 67.208 19.56 ;
     RECT  65.555 20.736 67.208 20.76 ;
     RECT  66.697 22.704 67.208 22.824 ;
     RECT  67.093 25.728 67.208 26.664 ;
     RECT  66.985 27.936 67.208 30.168 ;
     RECT  66.769 31.296 67.208 34.152 ;
     RECT  64.685 35.328 67.208 35.352 ;
     RECT  66.901 36.624 67.208 36.648 ;
     RECT  66.86 37.824 67.208 38.232 ;
     RECT  66.325 39.6 67.208 40.2 ;
     RECT  66.476 41.424 67.208 42.408 ;
     RECT  66.733 43.488 67.208 48.792 ;
     RECT  67.165 49.872 67.208 51.48 ;
     RECT  67.208 2.148 67.312 75.612 ;
     RECT  67.312 2.418 67.504 75.342 ;
     RECT  65.873 0.144 67.673 0.888 ;
     RECT  67.504 6.288 67.673 6.648 ;
     RECT  67.504 23.328 67.745 26.664 ;
     RECT  67.673 0.816 67.853 0.888 ;
     RECT  67.504 3.312 67.853 3.336 ;
     RECT  67.504 36.48 67.969 36.504 ;
     RECT  67.745 23.328 67.997 25.752 ;
     RECT  67.504 41.424 67.997 41.448 ;
     RECT  67.504 49.872 68.033 51.48 ;
     RECT  67.504 43.824 68.051 45.864 ;
     RECT  68.033 49.872 68.069 49.896 ;
     RECT  67.504 31.872 68.099 35.112 ;
     RECT  67.853 0.816 68.213 0.84 ;
     RECT  67.504 19.536 68.285 20.184 ;
     RECT  67.997 24.24 68.339 25.752 ;
     RECT  68.099 33.312 68.393 35.112 ;
     RECT  67.504 16.368 68.465 16.536 ;
     RECT  67.504 17.616 68.501 17.64 ;
     RECT  67.504 39.36 68.605 39.384 ;
     RECT  67.504 48.48 68.645 48.792 ;
     RECT  67.504 8.16 68.713 10.92 ;
     RECT  68.605 39.36 68.713 39.912 ;
     RECT  68.051 43.824 68.732 45.624 ;
     RECT  68.393 33.312 68.753 33.336 ;
     RECT  68.713 38.736 68.771 39.912 ;
     RECT  68.771 38.736 68.797 38.76 ;
     RECT  68.732 43.152 68.819 45.624 ;
     RECT  67.504 21.984 68.821 22.248 ;
     RECT  68.713 7.584 68.825 10.92 ;
     RECT  68.641 37.2 68.861 37.32 ;
     RECT  67.504 30.144 68.897 30.168 ;
     RECT  68.861 37.296 68.969 37.32 ;
     RECT  68.821 21.648 69.005 22.248 ;
     RECT  68.465 16.512 69.041 16.536 ;
     RECT  67.504 47.28 69.077 47.304 ;
     RECT  69.005 21.648 69.149 21.672 ;
     RECT  67.673 6.288 69.212 6.312 ;
     RECT  68.825 7.584 69.212 10.056 ;
     RECT  67.504 5.184 69.253 5.208 ;
     RECT  69.212 6.288 69.253 10.056 ;
     RECT  69.253 5.184 69.299 10.056 ;
     RECT  68.339 25.68 69.329 25.752 ;
     RECT  67.504 28.368 69.361 28.392 ;
     RECT  69.145 30 69.361 30.024 ;
     RECT  68.819 43.824 69.401 45.624 ;
     RECT  69.361 26.736 69.473 26.76 ;
     RECT  68.033 51.456 69.473 51.48 ;
     RECT  69.299 8.16 69.509 8.184 ;
     RECT  69.452 16.944 69.539 16.968 ;
     RECT  69.401 44.688 69.545 45.624 ;
     RECT  69.361 28.368 69.548 30.024 ;
     RECT  68.285 20.16 69.577 20.184 ;
     RECT  69.548 27.744 69.581 30.024 ;
     RECT  69.299 5.184 69.589 5.688 ;
     RECT  67.504 13.056 69.589 13.08 ;
     RECT  68.099 31.872 69.617 31.896 ;
     RECT  69.581 27.744 69.635 27.768 ;
     RECT  69.493 18.768 69.637 18.792 ;
     RECT  69.577 20.16 69.637 21.096 ;
     RECT  69.589 5.04 69.653 5.688 ;
     RECT  69.589 13.056 69.676 13.464 ;
     RECT  69.637 18.768 69.689 21.096 ;
     RECT  69.689 19.344 69.724 21.096 ;
     RECT  69.589 3.408 69.725 3.432 ;
     RECT  69.299 9.744 69.761 9.768 ;
     RECT  68.893 14.784 69.821 14.808 ;
     RECT  69.676 13.056 69.865 13.08 ;
     RECT  69.865 12.72 69.869 13.08 ;
     RECT  69.724 20.16 69.869 21.096 ;
     RECT  69.821 14.784 69.875 14.904 ;
     RECT  69.875 14.88 69.905 14.904 ;
     RECT  68.771 39.888 69.941 39.912 ;
     RECT  69.581 29.04 69.977 30.024 ;
     RECT  68.645 48.768 69.977 48.792 ;
     RECT  69.329 25.68 70.117 25.704 ;
     RECT  69.721 37.584 70.153 37.608 ;
     RECT  69.653 5.04 70.157 5.064 ;
     RECT  69.469 46.704 70.157 46.728 ;
     RECT  69.869 21.072 70.163 21.096 ;
     RECT  70.117 25.056 70.163 25.704 ;
     RECT  68.393 35.088 70.165 35.112 ;
     RECT  69.977 30 70.193 30.024 ;
     RECT  69.545 44.688 70.193 44.712 ;
     RECT  70.165 35.088 70.211 35.88 ;
     RECT  69.869 12.72 70.229 12.744 ;
     RECT  70.163 25.056 70.229 25.08 ;
     RECT  70.153 37.056 70.237 37.608 ;
     RECT  70.211 35.856 70.252 35.88 ;
     RECT  70.117 22.176 70.259 22.2 ;
     RECT  70.172 24.048 70.259 24.072 ;
     RECT  70.237 37.584 70.301 37.608 ;
     RECT  69.757 17.616 70.373 17.64 ;
     RECT  70.477 11.808 70.733 11.832 ;
    LAYER M5 ;
     RECT  8.976 0.133 9 0.229 ;
     RECT  10.224 0.133 10.248 0.229 ;
     RECT  8.496 0.229 9 0.277 ;
     RECT  10.224 0.229 10.488 0.325 ;
     RECT  12 0.144 60.984 0.325 ;
     RECT  8.4 0.277 9 0.373 ;
     RECT  10.224 0.325 60.984 0.373 ;
     RECT  8.4 0.373 60.984 1.141 ;
     RECT  8.4 1.141 61.32 1.381 ;
     RECT  7.392 0.181 7.416 2.137 ;
     RECT  8.4 1.381 62.28 2.137 ;
     RECT  2.4 2.137 2.52 2.151 ;
     RECT  67.2 2.137 67.32 2.151 ;
     RECT  7.392 2.137 62.28 2.339 ;
     RECT  7.8 2.339 62.28 2.387 ;
     RECT  9.504 2.387 62.28 2.773 ;
     RECT  4.704 2.245 4.728 2.821 ;
     RECT  2.4 2.151 2.712 3.397 ;
     RECT  7.8 2.387 8.112 3.397 ;
     RECT  9.504 2.773 62.952 3.397 ;
     RECT  2.4 3.397 2.808 4.163 ;
     RECT  7.8 3.397 62.952 4.453 ;
     RECT  7.8 4.453 63.576 4.691 ;
     RECT  4.704 2.821 5.688 4.739 ;
     RECT  4.848 4.739 5.688 4.787 ;
     RECT  7.8 4.691 13.944 4.787 ;
     RECT  4.848 4.787 5.112 4.835 ;
     RECT  7.8 4.787 13.656 4.883 ;
     RECT  9.6 4.883 13.656 4.931 ;
     RECT  13.2 4.931 13.656 4.979 ;
     RECT  69.6 3.397 69.624 5.219 ;
     RECT  14.928 4.691 63.576 5.221 ;
     RECT  9.6 4.931 12.12 5.459 ;
     RECT  13.2 4.979 13.512 5.893 ;
     RECT  14.928 5.221 64.104 5.987 ;
     RECT  6.384 6.565 6.408 7.333 ;
     RECT  7.8 4.883 8.112 7.333 ;
     RECT  9.6 5.459 11.88 7.381 ;
     RECT  13.008 5.893 13.512 7.381 ;
     RECT  14.928 5.987 62.808 7.475 ;
     RECT  17.28 7.475 62.808 7.571 ;
     RECT  4.848 4.835 4.872 7.621 ;
     RECT  6.384 7.333 8.112 7.621 ;
     RECT  4.848 7.621 8.112 7.669 ;
     RECT  9.504 7.381 13.512 7.669 ;
     RECT  14.928 7.475 16.296 7.763 ;
     RECT  17.568 7.571 62.808 8.003 ;
     RECT  60.144 8.003 62.808 8.195 ;
     RECT  4.848 7.669 13.512 8.293 ;
     RECT  4.848 8.293 14.28 8.579 ;
     RECT  17.568 8.003 57.816 8.579 ;
     RECT  4.848 8.579 10.392 8.869 ;
     RECT  4.56 8.869 10.392 8.915 ;
     RECT  67.2 2.151 67.512 9.061 ;
     RECT  69.264 5.653 69.288 9.061 ;
     RECT  58.944 8.003 58.968 9.109 ;
     RECT  60.144 8.195 62.28 9.109 ;
     RECT  5.664 8.915 10.392 9.155 ;
     RECT  11.856 8.579 11.88 9.251 ;
     RECT  4.56 8.915 4.584 9.971 ;
     RECT  12.96 8.579 14.28 9.971 ;
     RECT  58.944 9.109 62.28 10.019 ;
     RECT  67.2 9.061 69.288 10.067 ;
     RECT  15.552 7.763 16.296 10.309 ;
     RECT  17.712 8.579 57.816 10.309 ;
     RECT  15.552 10.309 57.816 10.835 ;
     RECT  17.712 10.835 57.816 10.837 ;
     RECT  58.944 10.019 58.968 10.837 ;
     RECT  67.2 10.067 68.424 10.931 ;
     RECT  10.368 9.155 10.392 11.365 ;
     RECT  17.712 10.837 58.968 11.507 ;
     RECT  13.056 9.971 14.28 11.941 ;
     RECT  67.2 10.931 67.512 11.941 ;
     RECT  63.792 5.987 64.104 11.987 ;
     RECT  12.528 11.941 14.28 12.467 ;
     RECT  17.712 11.507 58.68 12.563 ;
     RECT  12.528 12.467 13.848 12.995 ;
     RECT  10.368 11.365 10.776 13.045 ;
     RECT  18.48 12.563 58.68 13.139 ;
     RECT  18.48 13.139 57.816 13.715 ;
     RECT  66.72 11.941 67.512 13.715 ;
     RECT  2.4 4.163 2.712 14.197 ;
     RECT  18.48 13.715 27.048 14.197 ;
     RECT  17.904 14.197 27.048 14.291 ;
     RECT  28.512 13.715 57.816 14.291 ;
     RECT  28.512 14.291 46.872 14.339 ;
     RECT  60.144 10.019 62.28 14.339 ;
     RECT  10.368 13.045 10.872 14.387 ;
     RECT  13.104 12.995 13.848 14.771 ;
     RECT  69.6 13.429 69.624 14.773 ;
     RECT  64.08 11.987 64.104 14.819 ;
     RECT  69.6 14.773 69.864 14.819 ;
     RECT  5.664 9.155 9.096 14.867 ;
     RECT  60.432 14.339 62.28 14.867 ;
     RECT  5.664 14.867 6.792 14.915 ;
     RECT  69.84 14.819 69.864 14.915 ;
     RECT  4.272 14.485 4.296 15.061 ;
     RECT  4.272 15.061 5.208 15.107 ;
     RECT  15.552 10.835 16.296 15.349 ;
     RECT  6.384 14.915 6.792 15.395 ;
     RECT  2.4 14.197 3.192 15.443 ;
     RECT  6.768 15.395 6.792 15.443 ;
     RECT  47.952 14.291 57.48 15.443 ;
     RECT  17.904 14.291 26.952 15.445 ;
     RECT  55.536 15.443 57.48 15.635 ;
     RECT  10.368 14.387 10.776 15.637 ;
     RECT  47.952 15.443 54.408 16.019 ;
     RECT  60.432 14.867 62.112 16.019 ;
     RECT  10.368 15.637 11.4 16.067 ;
     RECT  52.896 16.019 54.408 16.211 ;
     RECT  67.2 13.715 67.512 16.357 ;
     RECT  13.2 14.771 13.848 16.501 ;
     RECT  5.184 15.107 5.208 16.547 ;
     RECT  17.904 15.445 27.336 16.691 ;
     RECT  15.312 15.349 16.296 16.837 ;
     RECT  55.536 15.635 57.096 16.885 ;
     RECT  10.704 16.067 11.4 16.981 ;
     RECT  12.384 16.501 13.848 16.981 ;
     RECT  10.704 16.981 13.848 17.123 ;
     RECT  17.904 16.691 26.952 17.123 ;
     RECT  47.952 16.019 51.576 17.123 ;
     RECT  15.216 16.837 16.296 17.171 ;
     RECT  11.952 17.123 13.848 17.219 ;
     RECT  28.608 14.339 46.872 17.267 ;
     RECT  61.44 16.019 62.112 17.555 ;
     RECT  53.376 16.211 54.408 17.605 ;
     RECT  55.536 16.885 57.288 17.605 ;
     RECT  11.952 17.219 13.512 17.651 ;
     RECT  11.952 17.651 11.976 17.699 ;
     RECT  17.904 17.123 19.032 18.133 ;
     RECT  53.376 17.605 58.152 18.181 ;
     RECT  31.68 17.267 46.872 18.275 ;
     RECT  10.704 17.123 10.776 18.421 ;
     RECT  10.704 18.421 11.064 18.467 ;
     RECT  52.848 18.181 58.152 18.709 ;
     RECT  47.952 17.123 51.312 18.803 ;
     RECT  69.504 16.933 69.528 18.803 ;
     RECT  28.608 17.267 30.168 18.805 ;
     RECT  10.752 18.467 11.064 18.851 ;
     RECT  20.016 17.123 26.952 18.851 ;
     RECT  28.608 18.805 30.312 18.851 ;
     RECT  17.28 18.133 19.032 18.995 ;
     RECT  11.04 18.851 11.064 19.189 ;
     RECT  11.04 19.189 11.16 19.235 ;
     RECT  13.104 17.651 13.512 19.333 ;
     RECT  50.064 18.803 51.312 19.333 ;
     RECT  52.848 18.709 58.728 19.333 ;
     RECT  13.104 19.333 13.608 19.379 ;
     RECT  50.064 19.333 58.728 19.379 ;
     RECT  31.68 18.275 36.168 19.427 ;
     RECT  17.28 18.995 17.304 19.621 ;
     RECT  16.896 19.621 17.304 19.667 ;
     RECT  29.28 18.851 30.312 20.003 ;
     RECT  37.44 18.275 46.872 20.003 ;
     RECT  50.064 19.379 58.152 20.003 ;
     RECT  60.432 19.333 60.456 20.003 ;
     RECT  47.952 18.803 49.032 20.051 ;
     RECT  69.648 19.333 69.672 20.195 ;
     RECT  29.28 20.003 29.712 20.245 ;
     RECT  15.216 17.171 15.336 20.339 ;
     RECT  32.112 19.427 33.48 20.579 ;
     RECT  34.608 19.427 36.168 20.579 ;
     RECT  50.112 20.003 58.152 20.579 ;
     RECT  13.2 19.379 13.608 20.821 ;
     RECT  29.232 20.245 29.712 21.013 ;
     RECT  33.216 20.579 33.48 21.061 ;
     RECT  34.608 20.579 35.112 21.061 ;
     RECT  29.232 21.013 29.832 21.107 ;
     RECT  20.064 18.851 26.952 21.155 ;
     RECT  33.216 21.061 35.112 21.155 ;
     RECT  50.112 20.579 57.336 21.155 ;
     RECT  65.52 20.725 65.544 21.349 ;
     RECT  65.136 21.349 65.544 21.395 ;
     RECT  15.312 20.339 15.336 21.541 ;
     RECT  5.04 18.181 5.064 21.683 ;
     RECT  13.2 20.821 14.328 21.683 ;
     RECT  16.896 19.667 16.92 21.683 ;
     RECT  20.208 21.155 21.576 21.683 ;
     RECT  23.04 21.155 26.952 21.683 ;
     RECT  3.984 20.485 4.008 21.731 ;
     RECT  61.488 17.555 62.112 21.827 ;
     RECT  11.136 19.235 11.16 22.021 ;
     RECT  33.264 21.155 35.112 22.067 ;
     RECT  32.112 20.579 32.136 22.165 ;
     RECT  70.128 21.061 70.152 22.165 ;
     RECT  10.848 22.021 11.16 22.211 ;
     RECT  26.16 21.683 26.328 22.211 ;
     RECT  29.4 21.107 29.832 22.211 ;
     RECT  70.128 22.165 70.248 22.211 ;
     RECT  21.552 21.683 21.576 22.259 ;
     RECT  18.6 18.995 19.032 22.453 ;
     RECT  20.208 21.683 20.232 22.453 ;
     RECT  36.144 20.579 36.168 22.597 ;
     RECT  37.44 20.003 46.824 22.597 ;
     RECT  13.2 21.683 13.512 22.693 ;
     RECT  65.136 21.395 65.16 22.739 ;
     RECT  18.6 22.453 20.232 22.741 ;
     RECT  34.656 22.067 35.112 22.741 ;
     RECT  36.144 22.597 46.824 22.741 ;
     RECT  32.016 22.165 32.136 22.789 ;
     RECT  12.528 22.693 13.512 22.835 ;
     RECT  47.952 20.051 48.936 22.835 ;
     RECT  66.96 16.357 67.512 22.835 ;
     RECT  15.312 21.541 15.432 23.075 ;
     RECT  32.016 22.789 32.232 23.075 ;
     RECT  32.208 23.075 32.232 23.173 ;
     RECT  33.264 22.067 33.672 23.173 ;
     RECT  53.28 21.155 57.336 23.267 ;
     RECT  18.6 22.741 21.192 23.269 ;
     RECT  61.8 21.827 62.112 23.269 ;
     RECT  18.48 23.269 21.192 23.317 ;
     RECT  23.04 21.683 24.84 23.365 ;
     RECT  61.056 23.269 62.112 23.365 ;
     RECT  34.656 22.741 46.824 23.411 ;
     RECT  47.952 22.835 48.6 23.411 ;
     RECT  53.28 23.267 57.144 23.411 ;
     RECT  27.696 22.837 27.72 23.699 ;
     RECT  44.976 23.411 46.824 23.699 ;
     RECT  50.112 21.155 51.312 23.797 ;
     RECT  45.168 23.699 46.824 23.893 ;
     RECT  11.472 22.741 11.496 23.987 ;
     RECT  15.312 23.075 15.336 23.987 ;
     RECT  34.656 23.411 43.992 23.987 ;
     RECT  45.168 23.893 47.304 23.987 ;
     RECT  50.112 23.797 51.432 23.987 ;
     RECT  63.84 22.645 63.864 23.987 ;
     RECT  45.504 23.987 47.304 24.035 ;
     RECT  70.224 22.211 70.248 24.083 ;
     RECT  67.2 22.835 67.512 24.229 ;
     RECT  3.888 22.165 3.912 24.371 ;
     RECT  2.4 15.443 2.712 24.421 ;
     RECT  42.624 23.987 43.368 24.467 ;
     RECT  22.896 23.365 24.84 24.469 ;
     RECT  18.336 23.317 21.192 24.517 ;
     RECT  2.4 24.421 2.856 24.563 ;
     RECT  45.6 24.035 47.304 24.563 ;
     RECT  18.336 24.517 21.672 24.659 ;
     RECT  32.208 23.173 33.672 24.899 ;
     RECT  32.208 24.899 33.48 24.901 ;
     RECT  60.816 23.365 62.112 24.997 ;
     RECT  18.336 24.659 20.232 25.043 ;
     RECT  13.2 22.835 13.512 25.045 ;
     RECT  26.16 22.211 26.184 25.045 ;
     RECT  27.36 24.805 27.384 25.045 ;
     RECT  29.4 22.211 29.712 25.045 ;
     RECT  60.816 24.997 62.232 25.045 ;
     RECT  22.704 24.469 24.84 25.139 ;
     RECT  42.72 24.467 43.368 25.139 ;
     RECT  50.544 23.987 51.432 25.139 ;
     RECT  48.672 25.141 48.696 25.379 ;
     RECT  45.6 24.563 46.008 25.475 ;
     RECT  50.688 25.139 51.432 25.475 ;
     RECT  59.616 23.845 59.64 25.475 ;
     RECT  7.8 14.867 8.112 25.621 ;
     RECT  22.704 25.139 24.408 25.667 ;
     RECT  26.16 25.045 27.384 25.667 ;
     RECT  54.576 23.411 57.144 25.667 ;
     RECT  64.992 25.093 65.016 25.715 ;
     RECT  67.2 24.229 68.328 25.715 ;
     RECT  70.128 25.045 70.152 25.715 ;
     RECT  66.144 25.141 66.168 25.717 ;
     RECT  67.2 25.715 67.512 25.717 ;
     RECT  12.288 25.045 13.512 25.763 ;
     RECT  14.736 24.229 14.76 25.763 ;
     RECT  66.144 25.717 67.512 25.763 ;
     RECT  29.184 25.045 29.712 25.813 ;
     RECT  26.16 25.667 26.76 25.859 ;
     RECT  18.336 25.043 18.912 25.861 ;
     RECT  3.696 25.429 3.72 26.003 ;
     RECT  60.768 25.045 62.232 26.003 ;
     RECT  18.288 25.861 18.912 26.053 ;
     RECT  20.208 25.043 20.232 26.053 ;
     RECT  11.28 25.957 11.304 26.149 ;
     RECT  18.288 26.053 20.232 26.243 ;
     RECT  34.656 23.987 41.64 26.243 ;
     RECT  51 25.475 51.432 26.243 ;
     RECT  53.28 23.411 53.544 26.243 ;
     RECT  54.72 25.667 57.144 26.243 ;
     RECT  21.648 24.659 21.672 26.291 ;
     RECT  45.6 25.475 45.912 26.485 ;
     RECT  34.656 26.243 37.704 26.627 ;
     RECT  6.864 25.621 8.112 26.675 ;
     RECT  60.768 26.003 62.112 26.723 ;
     RECT  28.464 25.813 29.712 26.725 ;
     RECT  42.912 25.139 43.368 26.725 ;
     RECT  11.088 26.149 11.304 26.779 ;
     RECT  36.144 26.627 37.704 26.819 ;
     RECT  49.584 25.861 49.608 26.819 ;
     RECT  53.52 26.243 53.544 26.819 ;
     RECT  45.6 26.485 46.152 27.107 ;
     RECT  32.112 24.901 33.48 27.157 ;
     RECT  28.272 26.725 29.712 27.203 ;
     RECT  31.584 27.157 33.48 27.203 ;
     RECT  38.736 26.243 41.64 27.205 ;
     RECT  42.912 26.725 44.232 27.205 ;
     RECT  61.8 26.723 62.112 27.205 ;
     RECT  47.28 24.563 47.304 27.251 ;
     RECT  2.4 24.563 2.712 27.349 ;
     RECT  18.288 26.243 19.368 27.395 ;
     RECT  11.088 26.779 11.256 27.635 ;
     RECT  13.056 25.763 13.512 27.635 ;
     RECT  29.28 27.203 29.712 27.635 ;
     RECT  48.432 27.205 48.456 27.829 ;
     RECT  28.272 27.203 28.296 27.877 ;
     RECT  59.52 26.677 59.544 27.877 ;
     RECT  60.768 26.723 60.792 27.877 ;
     RECT  38.736 27.205 44.232 27.923 ;
     RECT  18.288 27.395 18.912 27.971 ;
     RECT  61.8 27.205 62.232 27.971 ;
     RECT  66.384 25.763 67.512 27.971 ;
     RECT  2.4 27.349 2.856 28.019 ;
     RECT  38.736 27.923 41.64 28.115 ;
     RECT  45.6 27.107 46.056 28.115 ;
     RECT  5.136 25.621 5.16 28.309 ;
     RECT  4.512 28.309 5.16 28.453 ;
     RECT  33.264 27.203 33.48 28.453 ;
     RECT  34.656 26.627 35.112 28.453 ;
     RECT  42.816 27.923 44.232 28.547 ;
     RECT  27.456 27.877 28.296 28.691 ;
     RECT  31.584 27.203 32.136 28.931 ;
     RECT  33.264 28.453 35.112 29.027 ;
     RECT  59.52 27.877 60.792 29.027 ;
     RECT  7.8 26.675 8.112 29.029 ;
     RECT  48.432 27.829 48.552 29.075 ;
     RECT  69.6 27.733 69.624 29.075 ;
     RECT  15.552 27.205 15.576 29.123 ;
     RECT  33.264 29.027 33.48 29.123 ;
     RECT  47.232 28.309 47.256 29.123 ;
     RECT  53.616 27.205 53.64 29.123 ;
     RECT  20.544 26.773 20.568 29.363 ;
     RECT  7.8 29.029 8.424 29.365 ;
     RECT  59.856 29.027 60.792 29.507 ;
     RECT  4.512 28.453 5.208 29.555 ;
     RECT  7.68 29.365 8.424 29.555 ;
     RECT  11.088 27.635 11.112 29.605 ;
     RECT  42.816 28.547 43.368 29.699 ;
     RECT  48.432 29.075 48.456 29.699 ;
     RECT  7.68 29.555 8.112 29.843 ;
     RECT  13.2 27.635 13.512 29.941 ;
     RECT  32.112 28.931 32.136 30.181 ;
     RECT  54.96 26.243 57.144 30.275 ;
     RECT  5.136 29.555 5.208 30.371 ;
     RECT  2.4 28.019 2.712 30.661 ;
     RECT  26.16 25.859 26.184 30.661 ;
     RECT  32.112 30.181 32.376 30.661 ;
     RECT  33.456 29.123 33.48 30.661 ;
     RECT  13.2 29.941 13.656 30.709 ;
     RECT  34.656 29.027 35.112 30.709 ;
     RECT  36.144 26.819 37.032 30.709 ;
     RECT  26.16 30.661 26.712 30.805 ;
     RECT  11.088 29.605 11.592 30.851 ;
     RECT  23.28 25.667 24.408 30.851 ;
     RECT  58.656 29.365 58.68 30.851 ;
     RECT  64.752 29.077 64.776 31.139 ;
     RECT  16.08 30.757 16.104 31.237 ;
     RECT  51 26.243 51.312 31.285 ;
     RECT  67.2 27.971 67.512 31.285 ;
     RECT  34.656 30.709 37.032 31.331 ;
     RECT  2.4 30.661 3.432 31.379 ;
     RECT  53.472 30.709 53.496 31.379 ;
     RECT  7.8 29.843 8.112 31.381 ;
     RECT  25.632 30.805 26.712 31.621 ;
     RECT  54.96 30.275 57.096 31.669 ;
     RECT  39.12 28.115 41.64 31.861 ;
     RECT  45.6 28.115 46.008 31.861 ;
     RECT  66.528 31.285 67.512 31.861 ;
     RECT  5.136 30.371 5.16 31.909 ;
     RECT  5.136 31.909 5.352 31.955 ;
     RECT  16.08 31.237 17.016 31.955 ;
     RECT  25.632 31.621 26.856 31.955 ;
     RECT  32.112 30.661 33.48 31.955 ;
     RECT  60.768 29.507 60.792 32.197 ;
     RECT  61.8 27.971 62.112 32.197 ;
     RECT  11.088 30.851 11.112 32.437 ;
     RECT  7.8 31.381 8.232 32.483 ;
     RECT  13.2 30.709 13.704 32.485 ;
     RECT  54.816 31.669 57.096 32.531 ;
     RECT  66.528 31.861 68.088 32.531 ;
     RECT  60.768 32.197 62.112 32.581 ;
     RECT  60.624 32.581 62.112 32.627 ;
     RECT  26.16 31.955 26.856 32.915 ;
     RECT  23.28 30.851 24.312 32.965 ;
     RECT  11.088 32.437 11.448 33.107 ;
     RECT  30.72 30.661 30.744 33.107 ;
     RECT  34.656 31.331 35.112 33.301 ;
     RECT  5.328 31.955 5.352 33.445 ;
     RECT  45.6 31.861 46.2 33.589 ;
     RECT  64.416 32.485 64.44 33.589 ;
     RECT  13.2 32.485 14.232 33.683 ;
     RECT  26.352 32.915 26.856 33.683 ;
     RECT  55.68 32.531 57.096 33.683 ;
     RECT  23.088 32.965 24.312 33.779 ;
     RECT  60.624 32.627 60.648 33.829 ;
     RECT  61.8 32.627 62.112 33.829 ;
     RECT  34.368 33.301 35.112 33.923 ;
     RECT  29.4 27.635 29.712 33.925 ;
     RECT  4.8 33.445 5.352 34.067 ;
     RECT  13.2 33.683 13.512 34.165 ;
     RECT  51 31.285 52.2 34.165 ;
     RECT  64.416 33.589 64.488 34.259 ;
     RECT  39.024 31.861 41.64 34.355 ;
     RECT  7.8 32.483 8.112 34.501 ;
     RECT  45.6 33.589 46.728 34.501 ;
     RECT  64.416 34.259 64.44 34.595 ;
     RECT  4.8 34.067 4.824 34.741 ;
     RECT  16.08 31.955 16.104 34.741 ;
     RECT  60.624 33.829 62.112 34.741 ;
     RECT  4.56 34.741 4.824 34.787 ;
     RECT  28.272 28.691 28.296 34.835 ;
     RECT  34.656 33.923 35.112 34.835 ;
     RECT  55.68 33.683 56.712 34.835 ;
     RECT  59.664 34.741 62.112 34.835 ;
     RECT  59.664 34.835 60.648 34.883 ;
     RECT  48.432 34.597 48.456 34.933 ;
     RECT  11.424 33.107 11.448 35.269 ;
     RECT  12.576 34.165 13.512 35.269 ;
     RECT  18.6 27.971 18.912 35.269 ;
     RECT  11.424 35.269 13.512 35.315 ;
     RECT  32.496 31.955 32.52 35.317 ;
     RECT  4.56 34.787 4.584 35.363 ;
     RECT  32.496 35.317 32.904 35.363 ;
     RECT  44.64 34.501 46.728 35.363 ;
     RECT  59.664 34.883 60.6 35.363 ;
     RECT  23.28 33.779 24.312 35.365 ;
     RECT  21.12 32.437 21.144 35.411 ;
     RECT  11.424 35.315 11.928 35.459 ;
     RECT  48.432 34.933 48.984 35.555 ;
     RECT  45.6 35.363 46.728 35.747 ;
     RECT  51 34.165 52.248 35.747 ;
     RECT  26.352 33.683 26.376 35.843 ;
     RECT  48.96 35.555 48.984 35.939 ;
     RECT  15.168 34.741 16.104 35.987 ;
     RECT  61.68 34.835 62.112 35.987 ;
     RECT  2.4 31.379 2.712 36.085 ;
     RECT  10.224 35.269 10.248 36.085 ;
     RECT  56.4 34.835 56.712 36.373 ;
     RECT  10.224 36.085 10.344 36.515 ;
     RECT  16.08 35.987 16.104 36.515 ;
     RECT  18.24 35.269 18.912 36.515 ;
     RECT  19.968 35.845 19.992 36.515 ;
     RECT  29.4 33.925 30.216 36.515 ;
     RECT  67.2 32.531 67.944 36.515 ;
     RECT  67.2 36.515 67.512 36.613 ;
     RECT  11.904 35.459 11.928 37.043 ;
     RECT  55.968 36.373 57.576 37.043 ;
     RECT  10.32 36.515 10.344 37.091 ;
     RECT  22.848 35.365 24.312 37.091 ;
     RECT  36.144 31.331 37.032 37.091 ;
     RECT  51 35.747 51.912 37.091 ;
     RECT  56.4 37.043 57.576 37.091 ;
     RECT  70.176 35.077 70.2 37.091 ;
     RECT  23.328 37.091 24.312 37.283 ;
     RECT  59.76 35.363 60.6 37.331 ;
     RECT  32.88 35.363 32.904 37.573 ;
     RECT  44.448 35.845 44.472 37.667 ;
     RECT  32.88 37.573 33.672 37.859 ;
     RECT  66.912 36.613 67.512 37.859 ;
     RECT  33.648 37.859 33.672 38.005 ;
     RECT  34.8 34.835 35.112 38.005 ;
     RECT  33.648 38.005 35.112 38.051 ;
     RECT  37.008 37.091 37.032 38.149 ;
     RECT  64.368 35.029 64.392 38.243 ;
     RECT  59.76 37.331 59.784 38.435 ;
     RECT  7.248 34.501 8.112 38.675 ;
     RECT  34.416 38.051 35.112 38.819 ;
     RECT  2.4 36.085 3.432 39.011 ;
     RECT  45.6 35.747 46.008 39.061 ;
     RECT  61.8 35.987 62.112 39.061 ;
     RECT  29.4 36.515 29.712 39.301 ;
     RECT  37.008 38.149 37.656 39.491 ;
     RECT  67.2 37.859 67.512 39.589 ;
     RECT  37.008 39.491 37.032 39.733 ;
     RECT  15.408 38.725 15.432 39.923 ;
     RECT  16.8 39.301 16.824 39.923 ;
     RECT  45.6 39.061 46.776 39.923 ;
     RECT  53.568 39.253 53.592 39.923 ;
     RECT  60.768 39.061 62.112 39.923 ;
     RECT  68.736 38.725 68.76 39.923 ;
     RECT  66.336 39.589 67.512 40.019 ;
     RECT  61.68 39.923 62.112 40.021 ;
     RECT  21.504 38.965 21.528 40.307 ;
     RECT  36.816 39.733 37.032 40.547 ;
     RECT  61.68 40.021 62.664 40.595 ;
     RECT  13.2 35.315 13.512 40.837 ;
     RECT  17.088 40.549 17.112 41.029 ;
     RECT  17.088 41.029 17.208 41.075 ;
     RECT  19.968 40.405 19.992 41.075 ;
     RECT  3.744 39.301 3.768 41.219 ;
     RECT  6.384 39.637 6.408 41.219 ;
     RECT  42.96 29.699 43.368 41.269 ;
     RECT  56.4 37.091 56.712 41.269 ;
     RECT  67.2 40.019 67.512 41.413 ;
     RECT  39.12 34.355 41.64 41.557 ;
     RECT  42.96 41.269 43.656 41.557 ;
     RECT  13.056 40.837 13.512 41.653 ;
     RECT  17.184 41.075 17.208 41.749 ;
     RECT  29.4 39.301 30.072 41.795 ;
     RECT  17.184 41.749 17.4 41.845 ;
     RECT  58.512 40.981 58.536 41.939 ;
     RECT  17.184 41.845 17.544 42.085 ;
     RECT  7.8 38.675 8.112 42.133 ;
     RECT  27.984 41.797 28.008 42.133 ;
     RECT  39.12 41.557 43.656 42.179 ;
     RECT  15.36 41.557 15.384 42.227 ;
     RECT  20.016 41.269 20.04 42.227 ;
     RECT  39.12 42.179 41.064 42.227 ;
     RECT  66.528 41.413 67.512 42.419 ;
     RECT  52.512 42.037 52.536 42.469 ;
     RECT  52.512 42.469 52.872 42.515 ;
     RECT  27.792 42.133 28.008 42.755 ;
     RECT  16.416 42.085 17.544 42.995 ;
     RECT  26.736 40.405 26.76 43.093 ;
     RECT  27.792 42.755 27.816 43.093 ;
     RECT  26.736 43.093 27.816 43.139 ;
     RECT  29.4 41.795 29.712 43.141 ;
     RECT  42.192 42.179 43.656 43.283 ;
     RECT  47.232 40.981 47.256 43.331 ;
     RECT  56.4 41.269 57.288 43.331 ;
     RECT  21.648 43.333 21.672 43.765 ;
     RECT  42.96 43.283 43.656 43.859 ;
     RECT  12.768 41.653 13.512 43.861 ;
     RECT  45.6 39.923 45.912 43.861 ;
     RECT  67.2 42.419 67.512 43.861 ;
     RECT  68.784 43.141 68.808 43.861 ;
     RECT  31.92 41.557 31.944 44.005 ;
     RECT  31.92 44.005 32.28 44.051 ;
     RECT  4.512 43.285 4.536 44.099 ;
     RECT  52.848 42.515 52.872 44.099 ;
     RECT  21.072 43.765 21.672 44.245 ;
     RECT  20.496 44.245 21.672 44.291 ;
     RECT  26.736 43.139 27.384 44.291 ;
     RECT  7.8 42.133 8.904 44.339 ;
     RECT  25.296 43.285 25.32 44.339 ;
     RECT  29.4 43.141 30.216 44.341 ;
     RECT  42.96 43.859 43.368 44.483 ;
     RECT  68.784 43.861 69.24 44.723 ;
     RECT  17.52 42.995 17.544 44.869 ;
     RECT  18.6 36.515 18.912 44.869 ;
     RECT  17.52 44.869 18.912 44.963 ;
     RECT  29.28 44.341 30.216 45.011 ;
     RECT  47.856 43.333 47.88 45.011 ;
     RECT  37.008 40.547 37.032 45.013 ;
     RECT  26.736 44.291 26.76 45.059 ;
     RECT  43.344 44.483 43.368 45.059 ;
     RECT  20.496 44.291 21.096 45.157 ;
     RECT  61.8 40.595 62.664 45.203 ;
     RECT  12.768 43.861 13.992 45.443 ;
     RECT  56.4 43.331 56.712 45.541 ;
     RECT  68.784 44.723 68.808 45.635 ;
     RECT  39.888 42.227 41.064 45.731 ;
     RECT  67.2 43.861 67.8 45.829 ;
     RECT  52.992 44.965 53.016 46.067 ;
     RECT  17.616 44.963 18.912 46.115 ;
     RECT  7.8 44.339 8.112 46.117 ;
     RECT  29.28 45.011 29.712 46.117 ;
     RECT  32.256 44.051 32.28 46.211 ;
     RECT  5.664 45.541 5.688 46.259 ;
     RECT  7.8 46.117 8.376 46.693 ;
     RECT  39.888 45.731 40.632 46.739 ;
     RECT  7.8 46.693 9.192 46.787 ;
     RECT  20.16 45.157 21.096 46.787 ;
     RECT  27.312 45.685 27.336 46.787 ;
     RECT  51 37.091 51.312 47.269 ;
     RECT  67.2 45.829 68.04 47.315 ;
     RECT  9.168 46.787 9.192 47.363 ;
     RECT  33.072 47.173 33.096 47.363 ;
     RECT  37.008 45.013 37.128 47.363 ;
     RECT  38.784 46.069 38.808 47.363 ;
     RECT  7.8 46.787 8.112 47.605 ;
     RECT  22.224 46.645 22.248 47.843 ;
     RECT  40.2 46.739 40.632 47.843 ;
     RECT  29.28 46.117 30.36 47.845 ;
     RECT  29.04 47.845 30.36 47.891 ;
     RECT  13.2 45.443 13.992 48.277 ;
     RECT  60.48 44.245 60.504 48.277 ;
     RECT  13.2 48.277 14.904 48.371 ;
     RECT  16.416 42.995 16.44 48.373 ;
     RECT  37.008 47.363 37.032 48.421 ;
     RECT  56.304 45.541 56.712 48.421 ;
     RECT  29.04 47.891 30.264 48.515 ;
     RECT  26.208 47.557 26.232 48.659 ;
     RECT  6.816 47.605 8.112 48.805 ;
     RECT  33.648 48.229 33.672 48.851 ;
     RECT  34.8 38.819 35.112 48.949 ;
     RECT  20.112 47.461 20.136 48.997 ;
     RECT  20.112 48.997 20.616 49.043 ;
     RECT  29.232 48.515 30.264 49.043 ;
     RECT  40.2 47.843 40.512 49.237 ;
     RECT  41.568 47.845 41.592 49.237 ;
     RECT  18.6 46.115 18.912 49.333 ;
     RECT  47.904 48.373 47.928 49.381 ;
     RECT  34.8 48.949 35.208 49.475 ;
     RECT  36.432 48.421 37.032 49.475 ;
     RECT  40.2 49.237 41.592 49.525 ;
     RECT  61.8 45.203 62.112 49.525 ;
     RECT  40.2 49.525 42.504 49.715 ;
     RECT  64.848 48.997 65.496 49.763 ;
     RECT  60.432 48.277 60.504 49.811 ;
     RECT  24 37.283 24.312 49.813 ;
     RECT  15.936 48.373 16.44 49.859 ;
     RECT  18.048 49.333 18.912 49.907 ;
     RECT  14.88 48.371 14.904 49.957 ;
     RECT  15.936 49.859 16.152 49.957 ;
     RECT  51 47.269 51.864 50.003 ;
     RECT  45.6 43.861 46.488 50.005 ;
     RECT  14.88 49.957 16.152 50.051 ;
     RECT  47.904 49.381 48.408 50.051 ;
     RECT  20.592 49.043 20.616 50.149 ;
     RECT  27.984 48.661 28.008 50.195 ;
     RECT  61.8 49.525 62.76 50.195 ;
     RECT  54.672 48.949 54.696 50.291 ;
     RECT  56.304 48.421 57.048 50.341 ;
     RECT  61.8 50.195 62.616 50.387 ;
     RECT  60.48 49.811 60.504 50.579 ;
     RECT  64.848 49.763 65.4 50.579 ;
     RECT  6.096 48.805 8.112 50.627 ;
     RECT  51 50.003 51.312 50.629 ;
     RECT  15.12 50.051 16.152 50.771 ;
     RECT  48.384 50.051 48.408 50.771 ;
     RECT  56.016 50.341 57.048 50.771 ;
     RECT  41.568 49.715 42.504 51.155 ;
     RECT  13.2 48.371 13.512 51.205 ;
     RECT  29.28 49.043 30.264 51.205 ;
     RECT  65.376 50.579 65.4 51.443 ;
     RECT  50.4 50.629 51.312 51.445 ;
     RECT  49.824 51.445 51.312 51.635 ;
     RECT  18.6 49.907 18.912 51.733 ;
     RECT  20.448 50.149 20.616 51.923 ;
     RECT  29.28 51.205 30.312 51.923 ;
     RECT  38.88 48.373 38.904 51.923 ;
     RECT  24 49.813 24.408 51.971 ;
     RECT  41.568 51.155 42.408 52.211 ;
     RECT  45.6 50.005 46.728 52.211 ;
     RECT  52.752 51.493 52.776 52.211 ;
     RECT  34.8 49.475 35.112 52.405 ;
     RECT  40.2 49.715 40.512 52.453 ;
     RECT  11.424 50.965 11.448 52.499 ;
     RECT  15.12 50.771 15.72 52.499 ;
     RECT  56.016 50.771 56.952 52.499 ;
     RECT  42.384 52.211 42.408 52.547 ;
     RECT  34.608 52.405 35.112 52.885 ;
     RECT  40.08 52.453 40.512 52.979 ;
     RECT  20.592 51.923 20.616 52.981 ;
     RECT  24 51.971 24.312 52.981 ;
     RECT  18.6 51.733 19.032 53.027 ;
     RECT  22.272 52.405 22.584 53.027 ;
     RECT  13.104 51.205 13.512 53.075 ;
     RECT  15.12 52.499 15.144 53.075 ;
     RECT  20.592 52.981 21.096 53.461 ;
     RECT  29.28 51.923 30.216 53.507 ;
     RECT  7.8 50.627 8.112 53.557 ;
     RECT  24 52.981 24.648 53.603 ;
     RECT  6.096 50.627 6.12 53.651 ;
     RECT  37.008 49.475 37.032 53.651 ;
     RECT  54.672 52.837 54.696 53.699 ;
     RECT  20.544 53.461 21.096 53.795 ;
     RECT  2.4 39.011 2.712 54.085 ;
     RECT  22.56 53.027 22.584 54.085 ;
     RECT  29.28 53.507 29.832 54.085 ;
     RECT  22.464 54.085 22.584 54.131 ;
     RECT  34.128 52.885 35.112 54.131 ;
     RECT  27.888 52.981 27.912 54.179 ;
     RECT  20.544 53.795 20.568 54.371 ;
     RECT  24 53.603 24.312 54.565 ;
     RECT  34.608 54.131 35.112 54.707 ;
     RECT  7.344 53.557 8.112 54.755 ;
     RECT  29.232 54.085 29.832 54.755 ;
     RECT  45.6 52.211 45.912 54.853 ;
     RECT  56.016 52.499 56.712 54.899 ;
     RECT  40.2 52.979 40.512 54.901 ;
     RECT  37.056 54.085 37.08 54.947 ;
     RECT  29.28 54.755 29.832 55.139 ;
     RECT  34.704 54.707 35.112 55.139 ;
     RECT  45.6 54.853 46.776 55.141 ;
     RECT  14.544 54.085 14.568 55.237 ;
     RECT  43.392 53.941 43.416 55.237 ;
     RECT  45.6 55.141 47.592 55.427 ;
     RECT  40.08 54.901 40.512 55.669 ;
     RECT  2.4 54.085 3.528 55.715 ;
     RECT  43.392 55.237 43.752 55.715 ;
     RECT  31.344 54.661 31.368 55.813 ;
     RECT  56.4 54.899 56.712 56.389 ;
     RECT  57.984 53.365 58.008 56.389 ;
     RECT  9.168 54.085 9.192 56.483 ;
     RECT  24 54.565 24.504 56.483 ;
     RECT  29.28 55.139 29.712 56.483 ;
     RECT  30.72 55.813 31.704 56.531 ;
     RECT  40.08 55.669 40.92 56.531 ;
     RECT  14.544 55.237 15.192 57.059 ;
     RECT  31.68 56.531 31.704 57.059 ;
     RECT  18.6 53.027 18.912 57.397 ;
     RECT  21.024 56.533 21.048 57.875 ;
     RECT  56.4 56.389 58.008 57.875 ;
     RECT  34.8 55.139 35.112 57.973 ;
     RECT  40.2 56.531 40.92 58.021 ;
     RECT  22.464 54.131 22.488 58.117 ;
     RECT  56.4 57.875 57.672 58.117 ;
     RECT  52.512 58.117 52.536 58.355 ;
     RECT  32.256 58.117 32.28 58.357 ;
     RECT  18.192 57.397 18.912 58.403 ;
     RECT  40.2 58.021 41.592 58.451 ;
     RECT  13.2 53.075 13.512 58.645 ;
     RECT  29.4 56.483 29.712 58.645 ;
     RECT  50.4 51.635 51.312 58.691 ;
     RECT  14.784 57.059 15.192 58.739 ;
     RECT  40.2 58.451 40.92 58.739 ;
     RECT  21.648 58.117 22.488 58.931 ;
     RECT  55.68 58.117 57.672 58.931 ;
     RECT  43.728 55.715 43.752 59.077 ;
     RECT  43.584 59.077 43.752 59.123 ;
     RECT  15.168 58.739 15.192 59.171 ;
     RECT  11.52 58.885 11.544 59.173 ;
     RECT  7.392 54.755 8.112 59.219 ;
     RECT  45.6 55.427 45.912 59.221 ;
     RECT  29.088 58.645 29.712 59.267 ;
     RECT  19.968 58.597 19.992 59.315 ;
     RECT  47.568 55.427 47.592 59.315 ;
     RECT  50.88 58.691 51.312 59.315 ;
     RECT  22.464 58.931 22.488 59.555 ;
     RECT  11.424 59.173 11.544 59.749 ;
     RECT  12.528 58.645 13.512 59.749 ;
     RECT  11.424 59.749 13.512 59.795 ;
     RECT  29.28 59.267 29.712 59.797 ;
     RECT  31.296 58.357 32.28 59.843 ;
     RECT  18.6 58.403 18.912 59.845 ;
     RECT  13.104 59.795 13.512 59.891 ;
     RECT  44.976 59.221 45.912 59.891 ;
     RECT  25.68 59.797 25.704 60.133 ;
     RECT  51 59.315 51.312 60.181 ;
     RECT  10.032 59.845 10.056 60.323 ;
     RECT  7.8 59.219 8.112 60.373 ;
     RECT  11.424 59.795 12.024 60.419 ;
     RECT  17.856 59.845 18.912 60.515 ;
     RECT  43.584 59.123 43.608 60.661 ;
     RECT  32.256 59.843 32.28 60.805 ;
     RECT  32.256 60.805 32.472 60.851 ;
     RECT  53.616 59.701 53.64 60.899 ;
     RECT  29.28 59.797 30.072 60.949 ;
     RECT  32.448 60.851 32.472 60.949 ;
     RECT  28.224 59.749 28.248 60.995 ;
     RECT  32.448 60.949 32.808 61.091 ;
     RECT  7.68 60.373 8.112 61.139 ;
     RECT  25.68 60.133 26.184 61.139 ;
     RECT  32.448 61.091 32.616 61.139 ;
     RECT  34.8 57.973 35.4 61.235 ;
     RECT  51 60.181 52.2 61.235 ;
     RECT  54.96 59.173 55.32 61.237 ;
     RECT  56.4 58.931 57.672 61.237 ;
     RECT  21.456 59.749 21.48 61.331 ;
     RECT  43.584 60.661 44.184 61.475 ;
     RECT  42.48 61.333 42.504 61.525 ;
     RECT  42.384 61.525 42.504 61.571 ;
     RECT  60.096 60.373 60.12 61.571 ;
     RECT  32.592 61.139 32.616 61.619 ;
     RECT  29.28 60.949 30.84 61.811 ;
     RECT  38.736 60.709 38.76 61.907 ;
     RECT  45.504 59.891 45.912 62.005 ;
     RECT  51 61.235 51.312 62.005 ;
     RECT  29.28 61.811 30.072 62.291 ;
     RECT  24 56.483 24.312 62.389 ;
     RECT  17.04 61.573 17.064 62.435 ;
     RECT  54.96 61.237 57.672 62.531 ;
     RECT  23.568 62.389 24.312 62.629 ;
     RECT  54.96 62.531 56.712 62.629 ;
     RECT  54.864 62.629 56.712 62.675 ;
     RECT  11.424 60.419 11.544 62.723 ;
     RECT  50.88 62.005 51.312 62.771 ;
     RECT  2.4 55.715 2.712 63.061 ;
     RECT  5.424 62.293 5.448 63.061 ;
     RECT  47.376 61.573 47.4 63.061 ;
     RECT  5.424 63.061 6.36 63.107 ;
     RECT  23.568 62.629 25.08 63.155 ;
     RECT  18.6 60.515 18.912 63.157 ;
     RECT  23.568 63.155 24.312 63.299 ;
     RECT  47.376 63.061 48.072 63.299 ;
     RECT  7.8 61.139 8.112 63.397 ;
     RECT  42.384 61.571 42.408 63.541 ;
     RECT  11.52 62.723 11.544 63.781 ;
     RECT  17.904 63.157 18.912 63.827 ;
     RECT  54.864 62.675 54.984 63.923 ;
     RECT  7.8 63.397 9.096 64.019 ;
     RECT  40.2 58.739 40.512 64.021 ;
     RECT  61.8 50.387 62.112 64.165 ;
     RECT  45.072 62.005 45.912 64.307 ;
     RECT  6.336 63.107 6.36 64.357 ;
     RECT  48.048 63.299 48.072 64.357 ;
     RECT  51 62.771 51.312 64.357 ;
     RECT  6.24 64.357 6.36 64.403 ;
     RECT  42.192 63.541 42.408 64.595 ;
     RECT  59.712 62.485 59.736 64.885 ;
     RECT  6.24 64.403 6.264 65.027 ;
     RECT  10.896 63.781 11.976 65.027 ;
     RECT  18.48 63.827 18.912 65.027 ;
     RECT  43.584 61.475 43.608 65.027 ;
     RECT  2.4 63.061 3.384 65.123 ;
     RECT  54.912 63.923 54.936 65.317 ;
     RECT  42.192 64.595 42.216 65.365 ;
     RECT  45.6 64.307 45.912 65.509 ;
     RECT  50.592 64.357 51.312 65.555 ;
     RECT  40.08 64.021 40.512 65.939 ;
     RECT  45.6 65.509 46.296 65.939 ;
     RECT  59.232 64.885 59.736 66.131 ;
     RECT  20.592 62.581 20.616 66.179 ;
     RECT  36.528 62.437 36.552 66.179 ;
     RECT  41.616 65.365 42.216 66.179 ;
     RECT  54.912 65.317 55.224 66.179 ;
     RECT  59.712 66.131 59.736 66.179 ;
     RECT  61.8 64.165 62.952 66.179 ;
     RECT  51 65.555 51.312 66.613 ;
     RECT  40.2 65.939 40.512 66.709 ;
     RECT  41.616 66.179 41.64 66.709 ;
     RECT  11.52 65.027 11.976 66.755 ;
     RECT  26.16 61.139 26.184 66.755 ;
     RECT  27.312 63.685 27.336 66.755 ;
     RECT  43.92 65.509 43.944 66.755 ;
     RECT  45.6 65.939 46.056 66.755 ;
     RECT  47.952 64.357 48.072 66.755 ;
     RECT  47.952 66.755 47.976 66.803 ;
     RECT  2.4 65.123 2.712 67.237 ;
     RECT  51 66.613 52.296 67.283 ;
     RECT  61.8 66.179 62.112 67.285 ;
     RECT  56.4 62.675 56.712 67.669 ;
     RECT  61.8 67.285 62.808 68.147 ;
     RECT  11.952 66.755 11.976 68.245 ;
     RECT  13.2 59.891 13.512 68.341 ;
     RECT  45.6 66.755 45.912 68.341 ;
     RECT  2.4 67.237 3.432 68.387 ;
     RECT  49.536 67.957 49.56 68.629 ;
     RECT  51 67.283 51.312 68.629 ;
     RECT  40.2 66.709 41.64 68.675 ;
     RECT  44.976 68.341 45.912 68.773 ;
     RECT  61.8 68.147 62.112 68.869 ;
     RECT  11.424 68.245 11.976 68.917 ;
     RECT  56.4 67.669 57.24 68.917 ;
     RECT  54.912 66.179 54.936 69.157 ;
     RECT  56.304 68.917 57.24 69.157 ;
     RECT  49.536 68.629 51.312 69.443 ;
     RECT  11.376 68.917 11.976 69.445 ;
     RECT  13.104 68.341 13.512 69.445 ;
     RECT  6.048 65.749 6.072 69.491 ;
     RECT  44.448 68.773 45.912 69.491 ;
     RECT  11.376 69.445 13.512 69.731 ;
     RECT  7.8 64.019 8.112 69.829 ;
     RECT  54.912 69.157 57.24 69.829 ;
     RECT  53.952 69.829 57.24 69.971 ;
     RECT  16.752 69.349 16.776 70.069 ;
     RECT  44.448 69.491 44.472 70.115 ;
     RECT  18.6 65.027 18.912 70.357 ;
     RECT  50.496 69.443 51.312 70.405 ;
     RECT  11.424 69.731 13.512 70.499 ;
     RECT  41.616 68.675 41.64 70.547 ;
     RECT  45.6 69.491 45.912 70.645 ;
     RECT  53.952 69.971 56.712 70.739 ;
     RECT  7.68 69.829 8.112 71.075 ;
     RECT  60.816 68.869 62.112 71.219 ;
     RECT  16.512 70.069 16.776 71.221 ;
     RECT  29.4 62.291 30.072 71.269 ;
     RECT  5.28 69.493 5.304 71.315 ;
     RECT  22.608 64.453 22.632 71.315 ;
     RECT  27.024 67.237 27.048 71.315 ;
     RECT  50.208 70.405 51.312 71.363 ;
     RECT  12 70.499 13.512 71.411 ;
     RECT  12 71.411 12.168 71.651 ;
     RECT  45.6 70.645 46.728 71.699 ;
     RECT  9.504 71.221 9.528 71.747 ;
     RECT  59.184 70.645 59.208 71.843 ;
     RECT  15.984 71.221 16.776 72.131 ;
     RECT  61.68 71.219 62.112 72.179 ;
     RECT  18.6 70.357 19.032 72.227 ;
     RECT  4.752 72.037 4.776 72.325 ;
     RECT  7.8 71.075 8.112 72.373 ;
     RECT  24 63.299 24.312 72.373 ;
     RECT  26.016 72.181 26.04 72.373 ;
     RECT  31.056 68.245 31.08 72.419 ;
     RECT  60.528 71.797 60.552 72.419 ;
     RECT  63.312 71.221 63.336 72.563 ;
     RECT  24 72.373 26.04 72.659 ;
     RECT  15.984 72.131 16.008 72.707 ;
     RECT  28.656 71.269 30.072 72.803 ;
     RECT  6.816 72.373 8.112 72.851 ;
     RECT  55.872 70.739 56.712 72.853 ;
     RECT  28.656 72.803 29.88 72.995 ;
     RECT  48.432 69.445 48.456 72.995 ;
     RECT  4.704 72.325 4.776 73.235 ;
     RECT  12.144 71.651 12.168 73.283 ;
     RECT  13.2 71.411 13.512 73.477 ;
     RECT  55.872 72.853 57.048 73.477 ;
     RECT  54.96 73.477 57.048 73.571 ;
     RECT  4.704 73.235 4.728 74.339 ;
     RECT  29.4 72.995 29.88 74.339 ;
     RECT  54.96 73.571 56.712 74.579 ;
     RECT  11.952 73.477 11.976 74.675 ;
     RECT  7.392 72.851 8.112 74.723 ;
     RECT  44.112 70.645 44.136 74.723 ;
     RECT  26.016 72.659 26.04 74.819 ;
     RECT  54.96 74.579 54.984 75.011 ;
     RECT  56.016 74.579 56.712 75.155 ;
     RECT  60.432 74.053 60.456 75.299 ;
     RECT  13.2 73.477 13.608 75.443 ;
     RECT  2.4 68.387 2.712 75.609 ;
     RECT  7.8 74.723 8.112 75.609 ;
     RECT  13.2 75.443 13.512 75.609 ;
     RECT  18.6 72.227 18.912 75.609 ;
     RECT  24 72.659 24.312 75.609 ;
     RECT  29.4 74.339 29.712 75.609 ;
     RECT  34.8 61.235 35.112 75.609 ;
     RECT  40.2 68.675 40.512 75.609 ;
     RECT  45.6 71.699 45.912 75.609 ;
     RECT  51 71.363 51.312 75.609 ;
     RECT  56.4 75.155 56.712 75.609 ;
     RECT  61.8 72.179 62.112 75.609 ;
     RECT  67.2 47.315 67.512 75.609 ;
     RECT  2.4 75.609 2.52 75.623 ;
     RECT  7.8 75.609 7.92 75.623 ;
     RECT  13.2 75.609 13.32 75.623 ;
     RECT  18.6 75.609 18.72 75.623 ;
     RECT  24 75.609 24.12 75.623 ;
     RECT  29.4 75.609 29.52 75.623 ;
     RECT  34.8 75.609 34.92 75.623 ;
     RECT  40.2 75.609 40.32 75.623 ;
     RECT  45.6 75.609 45.72 75.623 ;
     RECT  51 75.609 51.12 75.623 ;
     RECT  56.4 75.609 56.52 75.623 ;
     RECT  61.8 75.609 61.92 75.623 ;
     RECT  67.2 75.609 67.32 75.623 ;
     RECT  9 0.133 10.224 0.373 ;
     RECT  7.416 0.229 8.496 0.277 ;
     RECT  10.488 0.229 11.952 0.24 ;
     RECT  10.488 0.24 12 0.325 ;
     RECT  7.416 0.277 8.4 2.137 ;
     RECT  8.112 2.387 9.504 3.397 ;
     RECT  13.944 4.691 14.928 4.787 ;
     RECT  13.656 4.787 14.928 4.979 ;
     RECT  8.112 4.883 9.6 7.381 ;
     RECT  12.12 4.931 13.2 5.459 ;
     RECT  13.512 4.979 14.928 7.763 ;
     RECT  11.88 5.459 13.2 5.893 ;
     RECT  11.88 5.893 13.008 7.381 ;
     RECT  62.808 5.987 63.792 8.195 ;
     RECT  4.872 6.565 6.384 7.621 ;
     RECT  6.408 6.565 7.8 7.333 ;
     RECT  8.112 7.381 9.504 7.669 ;
     RECT  16.296 7.475 17.28 7.571 ;
     RECT  16.296 7.571 17.568 8.579 ;
     RECT  13.512 7.763 15.552 8.293 ;
     RECT  57.816 8.003 58.944 10.837 ;
     RECT  58.968 8.003 60.144 9.109 ;
     RECT  62.28 8.195 63.792 11.987 ;
     RECT  14.28 8.293 15.552 12.467 ;
     RECT  10.392 8.579 11.856 9.251 ;
     RECT  11.88 8.579 12.96 9.251 ;
     RECT  16.296 8.579 17.712 10.309 ;
     RECT  4.584 8.915 5.664 9.971 ;
     RECT  9.096 9.155 10.368 14.867 ;
     RECT  58.968 10.019 60.144 11.507 ;
     RECT  16.296 10.835 17.712 12.563 ;
     RECT  58.68 11.507 60.144 13.139 ;
     RECT  27.048 13.715 28.512 14.291 ;
     RECT  26.952 14.291 28.512 14.339 ;
     RECT  46.872 14.291 47.952 20.003 ;
     RECT  26.952 14.339 28.608 15.445 ;
     RECT  10.776 14.387 10.872 15.637 ;
     RECT  3.192 14.485 4.272 15.107 ;
     RECT  4.296 14.485 5.664 14.915 ;
     RECT  6.792 14.867 7.8 15.443 ;
     RECT  4.296 14.915 6.384 15.061 ;
     RECT  5.208 15.061 6.384 15.395 ;
     RECT  13.848 15.349 15.312 16.837 ;
     RECT  54.408 15.443 55.536 17.605 ;
     RECT  27.336 15.445 28.608 16.691 ;
     RECT  57.096 15.635 57.288 16.885 ;
     RECT  51.576 16.019 52.896 16.211 ;
     RECT  11.4 16.501 12.384 16.981 ;
     RECT  13.848 16.837 15.216 17.219 ;
     RECT  10.776 17.123 11.952 17.699 ;
     RECT  19.032 17.123 20.016 18.851 ;
     RECT  30.168 17.267 31.68 18.805 ;
     RECT  11.976 17.651 13.104 17.699 ;
     RECT  10.776 17.699 11.16 18.421 ;
     RECT  36.168 18.275 37.44 22.597 ;
     RECT  11.064 18.421 11.16 19.189 ;
     RECT  49.032 18.803 50.064 20.003 ;
     RECT  30.312 18.805 31.68 19.427 ;
     RECT  19.032 18.851 20.064 21.155 ;
     RECT  29.232 18.851 29.28 20.245 ;
     RECT  17.304 18.995 18.6 19.667 ;
     RECT  60.456 19.333 61.488 20.003 ;
     RECT  33.48 19.427 34.608 21.061 ;
     RECT  29.712 20.003 29.832 21.013 ;
     RECT  46.824 20.003 47.952 23.411 ;
     RECT  49.032 20.003 50.112 20.051 ;
     RECT  48.936 20.051 50.112 22.835 ;
     RECT  15.216 20.339 15.312 20.821 ;
     RECT  2.712 20.485 3.984 21.731 ;
     RECT  4.008 20.485 5.04 21.683 ;
     RECT  32.136 20.579 33.216 21.155 ;
     RECT  35.112 20.579 36.144 22.741 ;
     RECT  65.544 20.725 66.96 21.395 ;
     RECT  14.328 20.821 15.312 21.683 ;
     RECT  19.032 21.155 20.208 22.453 ;
     RECT  21.576 21.155 23.04 22.259 ;
     RECT  32.136 21.155 33.264 22.789 ;
     RECT  15.432 21.541 16.896 21.683 ;
     RECT  20.232 21.683 21.552 22.259 ;
     RECT  24.84 21.683 26.16 25.139 ;
     RECT  26.328 21.683 26.952 22.211 ;
     RECT  2.712 21.731 3.912 22.165 ;
     RECT  61.488 21.827 61.8 23.269 ;
     RECT  33.672 22.067 34.656 24.899 ;
     RECT  2.712 22.165 3.888 24.371 ;
     RECT  26.184 22.211 26.952 22.837 ;
     RECT  20.232 22.259 21.192 22.741 ;
     RECT  22.896 22.259 23.04 23.365 ;
     RECT  63.864 22.645 65.136 22.739 ;
     RECT  11.496 22.741 12.528 22.835 ;
     RECT  32.232 22.789 33.264 23.173 ;
     RECT  48.6 22.835 50.112 23.411 ;
     RECT  26.184 22.837 27.696 23.699 ;
     RECT  43.992 23.411 44.976 23.699 ;
     RECT  46.824 23.411 47.304 23.893 ;
     RECT  53.544 23.411 54.576 25.667 ;
     RECT  26.184 23.699 27.384 24.805 ;
     RECT  43.992 23.699 45.168 23.987 ;
     RECT  59.64 23.845 60.816 25.045 ;
     RECT  41.64 23.987 42.624 24.467 ;
     RECT  13.512 24.229 14.736 25.763 ;
     RECT  2.712 24.371 3.912 24.421 ;
     RECT  2.856 24.421 3.912 24.563 ;
     RECT  41.64 24.467 42.72 25.139 ;
     RECT  21.192 24.469 22.704 24.517 ;
     RECT  21.672 24.517 22.704 25.667 ;
     RECT  2.712 24.563 3.912 25.429 ;
     RECT  46.008 24.563 47.28 25.475 ;
     RECT  20.232 24.659 21.648 26.243 ;
     RECT  26.184 24.805 27.36 25.045 ;
     RECT  33.48 24.899 34.656 28.453 ;
     RECT  18.912 25.043 20.208 26.053 ;
     RECT  59.64 25.045 60.768 25.475 ;
     RECT  41.64 25.139 42.912 27.205 ;
     RECT  50.544 25.139 50.688 25.475 ;
     RECT  47.304 25.141 48.672 25.379 ;
     RECT  65.016 25.141 66.144 25.715 ;
     RECT  66.168 25.141 67.2 25.717 ;
     RECT  2.712 25.429 3.696 26.003 ;
     RECT  3.72 25.429 3.912 25.621 ;
     RECT  45.912 25.475 47.28 26.485 ;
     RECT  50.544 25.475 51 25.861 ;
     RECT  59.616 25.475 60.768 26.677 ;
     RECT  3.72 25.621 5.136 26.003 ;
     RECT  53.544 25.667 54.72 26.243 ;
     RECT  49.608 25.861 51 26.819 ;
     RECT  2.712 26.003 2.856 27.349 ;
     RECT  62.112 26.003 62.232 27.205 ;
     RECT  19.368 26.243 21.648 26.291 ;
     RECT  37.704 26.243 38.736 26.819 ;
     RECT  53.544 26.243 54.96 26.819 ;
     RECT  19.368 26.291 20.568 26.773 ;
     RECT  46.152 26.485 47.28 27.107 ;
     RECT  35.112 26.627 36.144 30.709 ;
     RECT  59.544 26.677 60.768 27.877 ;
     RECT  60.792 26.723 61.8 32.197 ;
     RECT  44.232 26.725 45.6 28.547 ;
     RECT  19.368 26.773 20.544 27.395 ;
     RECT  53.616 26.819 54.96 27.205 ;
     RECT  46.056 27.107 47.28 27.251 ;
     RECT  28.296 27.203 29.28 27.635 ;
     RECT  32.136 27.203 33.264 29.123 ;
     RECT  47.304 27.205 48.432 27.251 ;
     RECT  53.64 27.205 54.96 29.123 ;
     RECT  46.056 27.251 48.432 28.115 ;
     RECT  28.296 27.635 29.4 34.835 ;
     RECT  26.184 27.877 27.456 28.691 ;
     RECT  41.64 27.923 42.816 29.699 ;
     RECT  46.008 28.115 48.432 28.309 ;
     RECT  46.008 28.309 47.232 29.123 ;
     RECT  47.256 28.309 48.432 29.123 ;
     RECT  33.48 29.027 34.656 31.955 ;
     RECT  59.52 29.027 59.856 29.365 ;
     RECT  32.136 29.123 33.456 30.181 ;
     RECT  57.144 29.365 58.656 30.275 ;
     RECT  58.68 29.365 59.856 29.507 ;
     RECT  41.64 29.699 42.96 41.557 ;
     RECT  32.376 30.181 33.456 30.661 ;
     RECT  29.712 30.661 30.72 33.107 ;
     RECT  30.744 30.661 32.112 31.955 ;
     RECT  53.496 30.709 54.96 31.379 ;
     RECT  24.408 30.805 25.632 30.851 ;
     RECT  24.312 30.851 25.632 31.955 ;
     RECT  52.2 31.285 53.472 31.379 ;
     RECT  35.112 31.331 36.144 37.091 ;
     RECT  54.816 31.379 54.96 31.669 ;
     RECT  26.856 31.621 28.272 33.683 ;
     RECT  5.136 31.955 5.328 33.445 ;
     RECT  34.368 31.955 34.656 33.301 ;
     RECT  60.648 32.627 61.8 33.829 ;
     RECT  29.712 33.107 30.216 33.925 ;
     RECT  11.448 34.165 12.576 35.269 ;
     RECT  43.368 34.501 44.64 35.363 ;
     RECT  60.648 34.835 61.68 34.883 ;
     RECT  60.6 34.883 61.68 35.987 ;
     RECT  10.248 35.269 11.424 35.459 ;
     RECT  11.928 35.315 13.2 37.043 ;
     RECT  43.368 35.363 45.6 35.845 ;
     RECT  10.248 35.459 10.344 36.085 ;
     RECT  18.912 35.845 19.968 36.515 ;
     RECT  43.368 35.845 44.448 37.667 ;
     RECT  44.472 35.845 45.6 37.667 ;
     RECT  60.6 35.987 61.8 37.331 ;
     RECT  33.672 37.573 34.8 38.005 ;
     RECT  37.656 38.149 39.12 39.491 ;
     RECT  7.248 38.675 7.8 39.637 ;
     RECT  67.512 38.725 68.736 39.923 ;
     RECT  2.712 39.011 3.432 39.301 ;
     RECT  2.712 39.301 3.744 41.219 ;
     RECT  15.432 39.301 16.8 39.923 ;
     RECT  6.408 39.637 7.8 41.219 ;
     RECT  45.912 39.923 46.776 40.981 ;
     RECT  66.528 40.019 67.2 41.413 ;
     RECT  18.912 40.405 19.968 41.075 ;
     RECT  17.112 40.549 18.6 41.029 ;
     RECT  45.912 40.981 47.232 43.331 ;
     RECT  17.208 41.029 18.6 41.749 ;
     RECT  17.088 41.075 17.184 42.085 ;
     RECT  18.912 41.075 19.992 41.269 ;
     RECT  18.912 41.269 20.016 42.227 ;
     RECT  57.288 41.269 58.512 41.939 ;
     RECT  17.4 41.749 18.6 41.845 ;
     RECT  29.712 41.795 30.072 43.141 ;
     RECT  26.76 41.797 27.984 42.133 ;
     RECT  28.008 41.797 29.4 42.755 ;
     RECT  17.544 41.845 18.6 44.869 ;
     RECT  51.312 42.037 52.512 42.515 ;
     RECT  15.384 42.085 16.416 42.227 ;
     RECT  26.76 42.133 27.792 43.093 ;
     RECT  41.064 42.179 42.192 43.283 ;
     RECT  16.44 42.995 17.52 44.963 ;
     RECT  67.512 43.141 68.784 43.861 ;
     RECT  24.312 43.285 25.296 44.339 ;
     RECT  25.32 43.285 26.736 44.339 ;
     RECT  45.912 43.331 47.256 43.333 ;
     RECT  45.912 43.333 47.856 43.861 ;
     RECT  46.488 43.861 47.856 45.011 ;
     RECT  67.8 43.861 68.784 45.635 ;
     RECT  60.504 44.245 61.8 50.579 ;
     RECT  26.76 44.291 27.336 45.059 ;
     RECT  16.44 44.963 17.616 46.115 ;
     RECT  29.712 45.011 30.216 46.117 ;
     RECT  27.312 45.059 27.336 45.685 ;
     RECT  18.912 45.157 20.16 46.787 ;
     RECT  67.8 45.635 68.04 45.829 ;
     RECT  38.808 46.069 39.888 46.739 ;
     RECT  21.096 46.645 22.224 46.787 ;
     RECT  38.808 46.739 40.2 47.363 ;
     RECT  8.112 46.787 9.168 47.363 ;
     RECT  18.912 46.787 20.136 47.461 ;
     RECT  38.88 47.363 40.2 48.373 ;
     RECT  18.912 47.461 20.112 49.043 ;
     RECT  40.512 47.843 40.632 47.845 ;
     RECT  40.512 47.845 41.568 49.237 ;
     RECT  33.672 48.229 34.8 48.851 ;
     RECT  14.904 48.277 16.416 48.373 ;
     RECT  13.512 48.371 14.88 50.051 ;
     RECT  14.904 48.373 15.936 49.957 ;
     RECT  38.904 48.373 40.2 51.923 ;
     RECT  46.488 48.373 47.904 50.005 ;
     RECT  35.112 48.421 36.432 48.949 ;
     RECT  29.04 48.515 29.232 48.661 ;
     RECT  28.008 48.661 29.232 49.043 ;
     RECT  35.208 48.949 36.432 49.475 ;
     RECT  20.448 49.043 20.592 50.149 ;
     RECT  28.008 49.043 29.28 50.195 ;
     RECT  40.512 49.715 41.568 52.211 ;
     RECT  51.312 50.003 51.864 51.493 ;
     RECT  46.728 50.005 47.904 50.051 ;
     RECT  51.312 51.493 52.752 52.211 ;
     RECT  19.032 51.733 20.448 51.923 ;
     RECT  40.08 51.923 40.2 52.453 ;
     RECT  24.312 51.971 24.408 52.981 ;
     RECT  22.584 52.405 24 54.131 ;
     RECT  56.712 52.499 56.952 53.365 ;
     RECT  54.696 52.837 56.016 53.699 ;
     RECT  21.096 52.981 22.272 53.027 ;
     RECT  27.912 52.981 29.28 54.085 ;
     RECT  21.096 53.027 22.56 53.795 ;
     RECT  56.712 53.365 57.984 56.389 ;
     RECT  29.832 53.507 30.216 54.661 ;
     RECT  6.12 53.557 7.344 53.651 ;
     RECT  24.312 53.603 24.504 54.565 ;
     RECT  22.464 53.795 22.56 54.085 ;
     RECT  8.112 54.085 9.168 56.483 ;
     RECT  13.512 54.085 14.544 57.059 ;
     RECT  27.912 54.085 29.232 54.179 ;
     RECT  22.488 54.131 24 59.555 ;
     RECT  29.832 54.661 31.344 55.139 ;
     RECT  29.712 55.139 31.344 55.813 ;
     RECT  29.712 55.813 30.72 56.531 ;
     RECT  21.048 56.533 22.464 57.875 ;
     RECT  13.512 57.059 14.784 58.739 ;
     RECT  31.68 57.059 31.704 58.117 ;
     RECT  21.648 57.875 22.464 58.117 ;
     RECT  31.68 58.117 32.256 58.357 ;
     RECT  51.312 58.117 52.512 58.355 ;
     RECT  18.192 58.403 18.6 59.845 ;
     RECT  18.912 58.597 19.968 59.315 ;
     RECT  11.544 58.885 12.528 59.749 ;
     RECT  55.68 58.931 56.4 59.173 ;
     RECT  43.608 59.123 43.752 59.221 ;
     RECT  55.32 59.173 56.4 61.237 ;
     RECT  7.68 59.219 7.8 60.373 ;
     RECT  43.608 59.221 44.976 59.891 ;
     RECT  29.088 59.267 29.28 59.749 ;
     RECT  53.64 59.701 54.96 60.899 ;
     RECT  28.248 59.749 29.28 60.995 ;
     RECT  12.024 59.795 13.104 59.891 ;
     RECT  24.312 59.797 25.68 61.139 ;
     RECT  30.072 59.797 31.296 59.843 ;
     RECT  30.072 59.843 32.256 60.851 ;
     RECT  10.056 59.845 11.424 60.323 ;
     RECT  12.024 59.891 13.2 60.419 ;
     RECT  43.608 59.891 45.504 60.661 ;
     RECT  52.2 60.181 53.616 60.899 ;
     RECT  44.184 60.661 45.504 61.475 ;
     RECT  38.76 60.709 40.2 61.907 ;
     RECT  30.072 60.851 30.84 60.949 ;
     RECT  24.312 61.139 26.16 62.629 ;
     RECT  35.112 61.235 35.4 62.437 ;
     RECT  42.504 61.333 43.584 61.571 ;
     RECT  43.608 61.475 45.504 62.005 ;
     RECT  42.408 61.571 43.584 64.595 ;
     RECT  45.912 61.573 47.376 63.299 ;
     RECT  43.608 62.005 45.072 64.307 ;
     RECT  35.112 62.437 36.528 66.179 ;
     RECT  25.08 62.629 26.16 63.155 ;
     RECT  54.984 62.675 56.4 63.923 ;
     RECT  11.424 62.723 11.52 63.781 ;
     RECT  6.36 63.061 7.8 64.403 ;
     RECT  6.24 63.107 6.336 64.357 ;
     RECT  23.568 63.299 24 64.453 ;
     RECT  47.952 63.299 48.048 64.357 ;
     RECT  26.184 63.685 27.312 66.755 ;
     RECT  11.976 63.781 13.2 68.341 ;
     RECT  54.936 63.923 56.4 65.317 ;
     RECT  43.608 64.307 43.944 65.027 ;
     RECT  22.632 64.453 24 71.315 ;
     RECT  42.216 64.595 43.584 65.027 ;
     RECT  43.92 65.027 43.944 65.509 ;
     RECT  55.224 65.317 56.4 66.179 ;
     RECT  40.512 65.365 41.616 66.709 ;
     RECT  54.936 66.179 56.4 68.917 ;
     RECT  62.112 66.179 62.808 67.285 ;
     RECT  11.52 66.755 11.952 68.245 ;
     RECT  27.024 66.755 27.048 67.237 ;
     RECT  49.56 67.957 51 68.629 ;
     RECT  30.072 68.245 31.056 72.419 ;
     RECT  11.976 68.341 13.104 69.445 ;
     RECT  40.512 68.675 41.616 70.547 ;
     RECT  54.936 68.917 56.304 69.157 ;
     RECT  50.208 69.443 50.496 70.405 ;
     RECT  44.472 69.491 45.6 70.115 ;
     RECT  44.448 70.115 45.6 70.645 ;
     RECT  44.136 70.645 45.6 74.723 ;
     RECT  7.68 71.075 7.8 72.373 ;
     RECT  60.816 71.219 61.68 71.797 ;
     RECT  8.112 71.221 9.504 71.747 ;
     RECT  62.112 71.221 63.312 72.563 ;
     RECT  12.168 71.411 13.2 73.283 ;
     RECT  59.208 71.797 60.528 71.843 ;
     RECT  60.552 71.797 61.68 72.179 ;
     RECT  60.552 72.179 61.8 72.419 ;
     RECT  12.144 73.283 13.2 73.477 ;
     RECT  11.976 73.477 13.2 74.675 ;
     RECT  60.456 74.053 61.8 75.299 ;
     RECT  54.984 74.579 56.016 75.011 ;
  END
END ot_s81_pq_aq_common_native
END LIBRARY
